# 
# ******************************************************************************
# *                                                                            *
# *                   Copyright (C) 2004-2010, Nangate Inc.                    *
# *                           All rights reserved.                             *
# *                                                                            *
# * Nangate and the Nangate logo are trademarks of Nangate Inc.                *
# *                                                                            *
# * All trademarks, logos, software marks, and trade names (collectively the   *
# * "Marks") in this program are proprietary to Nangate or other respective    *
# * owners that have granted Nangate the right and license to use such Marks.  *
# * You are not permitted to use the Marks without the prior written consent   *
# * of Nangate or such third party that may own the Marks.                     *
# *                                                                            *
# * This file has been provided pursuant to a License Agreement containing     *
# * restrictions on its use. This file contains valuable trade secrets and     *
# * proprietary information of Nangate Inc., and is protected by U.S. and      *
# * international laws and/or treaties.                                        *
# *                                                                            *
# * The copyright notice(s) in this file does not indicate actual or intended  *
# * publication of this file.                                                  *
# *                                                                            *
# *     NGLibraryCreator, v2010.08-HR32-SP3-2010-08-05 - build 1009061800      *
# *                                                                            *
# ******************************************************************************
# 
# 
# Running on brazil06.nangate.com.br for user Giancarlo Franciscatto (gfr).
# Local time is now Fri, 3 Dec 2010, 19:32:18.
# Main process id is 27821.

VERSION 5.6 ;
BUSBITCHARS "[]" ;
DIVIDERCHAR "/" ;

UNITS
  DATABASE MICRONS 2000 ;
END UNITS

MANUFACTURINGGRID 0.0050 ;

LAYER poly
  TYPE MASTERSLICE ;
END poly

LAYER active
  TYPE MASTERSLICE ;
END active

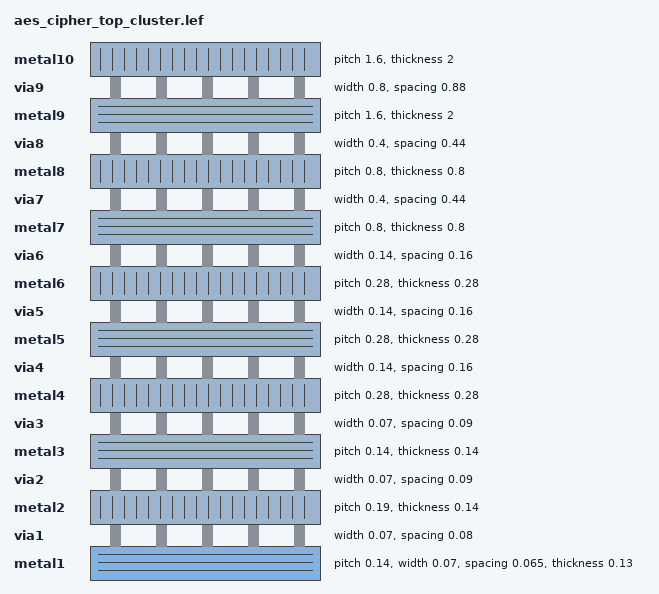
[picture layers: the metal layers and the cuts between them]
LAYER metal1
  TYPE ROUTING ;
  SPACING 0.065 ;
  WIDTH 0.07 ;
  PITCH 0.14 ;
  DIRECTION HORIZONTAL ;
  OFFSET 0.095 0.07 ;
  RESISTANCE RPERSQ 0.38 ;
  THICKNESS 0.13 ;
  HEIGHT 0.37 ;
  CAPACITANCE CPERSQDIST 7.7161e-05 ;
  EDGECAPACITANCE 2.7365e-05 ;
END metal1

LAYER via1
  TYPE CUT ;
  SPACING 0.08 ;
  WIDTH 0.07 ;
  RESISTANCE 5 ;
END via1

LAYER metal2
  TYPE ROUTING ;
  SPACINGTABLE 
    PARALLELRUNLENGTH    0.0000     0.3000     0.9000     1.8000     2.7000     4.0000     
      WIDTH 0.0000       0.0700     0.0700     0.0700     0.0700     0.0700     0.0700     
      WIDTH 0.0900       0.0700     0.0900     0.0900     0.0900     0.0900     0.0900     
      WIDTH 0.2700       0.0700     0.0900     0.2700     0.2700     0.2700     0.2700     
      WIDTH 0.5000       0.0700     0.0900     0.2700     0.5000     0.5000     0.5000     
      WIDTH 0.9000       0.0700     0.0900     0.2700     0.5000     0.9000     0.9000     
      WIDTH 1.5000       0.0700     0.0900     0.2700     0.5000     0.9000     1.5000      ;
  WIDTH 0.07 ;
  PITCH 0.19 ;
  DIRECTION VERTICAL ;
  OFFSET 0.095 0.07 ;
  RESISTANCE RPERSQ 0.25 ;
  THICKNESS 0.14 ;
  HEIGHT 0.62 ;
  CAPACITANCE CPERSQDIST 4.0896e-05 ;
  EDGECAPACITANCE 2.5157e-05 ;
END metal2

LAYER via2
  TYPE CUT ;
  SPACING 0.09 ;
  WIDTH 0.07 ;
  RESISTANCE 5 ;
END via2

LAYER metal3
  TYPE ROUTING ;
  SPACINGTABLE 
    PARALLELRUNLENGTH    0.0000     0.3000     0.9000     1.8000     2.7000     4.0000     
      WIDTH 0.0000       0.0700     0.0700     0.0700     0.0700     0.0700     0.0700     
      WIDTH 0.0900       0.0700     0.0900     0.0900     0.0900     0.0900     0.0900     
      WIDTH 0.2700       0.0700     0.0900     0.2700     0.2700     0.2700     0.2700     
      WIDTH 0.5000       0.0700     0.0900     0.2700     0.5000     0.5000     0.5000     
      WIDTH 0.9000       0.0700     0.0900     0.2700     0.5000     0.9000     0.9000     
      WIDTH 1.5000       0.0700     0.0900     0.2700     0.5000     0.9000     1.5000      ;
  WIDTH 0.07 ;
  PITCH 0.14 ;
  DIRECTION HORIZONTAL ;
  OFFSET 0.095 0.07 ;
  RESISTANCE RPERSQ 0.25 ;
  THICKNESS 0.14 ;
  HEIGHT 0.88 ;
  CAPACITANCE CPERSQDIST 2.7745e-05 ;
  EDGECAPACITANCE 2.5157e-05 ;
END metal3

LAYER via3
  TYPE CUT ;
  SPACING 0.09 ;
  WIDTH 0.07 ;
  RESISTANCE 5 ;
END via3

LAYER metal4
  TYPE ROUTING ;
  SPACINGTABLE 
    PARALLELRUNLENGTH    0.0000     0.9000     1.8000     2.7000     4.0000     
      WIDTH 0.0000       0.1400     0.1400     0.1400     0.1400     0.1400     
      WIDTH 0.2700       0.1400     0.2700     0.2700     0.2700     0.2700     
      WIDTH 0.5000       0.1400     0.2700     0.5000     0.5000     0.5000     
      WIDTH 0.9000       0.1400     0.2700     0.5000     0.9000     0.9000     
      WIDTH 1.5000       0.1400     0.2700     0.5000     0.9000     1.5000      ;
  WIDTH 0.14 ;
  PITCH 0.28 ;
  DIRECTION VERTICAL ;
  OFFSET 0.095 0.07 ;
  RESISTANCE RPERSQ 0.21 ;
  THICKNESS 0.28 ;
  HEIGHT 1.14 ;
  CAPACITANCE CPERSQDIST 2.0743e-05 ;
  EDGECAPACITANCE 3.0908e-05 ;
END metal4

LAYER via4
  TYPE CUT ;
  SPACING 0.16 ;
  WIDTH 0.14 ;
  RESISTANCE 3 ;
END via4

LAYER metal5
  TYPE ROUTING ;
  SPACINGTABLE 
    PARALLELRUNLENGTH    0.0000     0.9000     1.8000     2.7000     4.0000     
      WIDTH 0.0000       0.1400     0.1400     0.1400     0.1400     0.1400     
      WIDTH 0.2700       0.1400     0.2700     0.2700     0.2700     0.2700     
      WIDTH 0.5000       0.1400     0.2700     0.5000     0.5000     0.5000     
      WIDTH 0.9000       0.1400     0.2700     0.5000     0.9000     0.9000     
      WIDTH 1.5000       0.1400     0.2700     0.5000     0.9000     1.5000      ;
  WIDTH 0.14 ;
  PITCH 0.28 ;
  DIRECTION HORIZONTAL ;
  OFFSET 0.095 0.07 ;
  RESISTANCE RPERSQ 0.21 ;
  THICKNESS 0.28 ;
  HEIGHT 1.71 ;
  CAPACITANCE CPERSQDIST 1.3527e-05 ;
  EDGECAPACITANCE 2.3863e-06 ;
END metal5

LAYER via5
  TYPE CUT ;
  SPACING 0.16 ;
  WIDTH 0.14 ;
  RESISTANCE 3 ;
END via5

LAYER metal6
  TYPE ROUTING ;
  SPACINGTABLE 
    PARALLELRUNLENGTH    0.0000     0.9000     1.8000     2.7000     4.0000     
      WIDTH 0.0000       0.1400     0.1400     0.1400     0.1400     0.1400     
      WIDTH 0.2700       0.1400     0.2700     0.2700     0.2700     0.2700     
      WIDTH 0.5000       0.1400     0.2700     0.5000     0.5000     0.5000     
      WIDTH 0.9000       0.1400     0.2700     0.5000     0.9000     0.9000     
      WIDTH 1.5000       0.1400     0.2700     0.5000     0.9000     1.5000      ;
  WIDTH 0.14 ;
  PITCH 0.28 ;
  DIRECTION VERTICAL ;
  OFFSET 0.095 0.07 ;
  RESISTANCE RPERSQ 0.21 ;
  THICKNESS 0.28 ;
  HEIGHT 2.28 ;
  CAPACITANCE CPERSQDIST 1.0036e-05 ;
  EDGECAPACITANCE 2.3863e-05 ;
END metal6

LAYER via6
  TYPE CUT ;
  SPACING 0.16 ;
  WIDTH 0.14 ;
  RESISTANCE 3 ;
END via6

LAYER metal7
  TYPE ROUTING ;
  SPACINGTABLE 
    PARALLELRUNLENGTH    0.0000     1.8000     2.7000     4.0000     
      WIDTH 0.0000       0.4000     0.4000     0.4000     0.4000     
      WIDTH 0.5000       0.4000     0.5000     0.5000     0.5000     
      WIDTH 0.9000       0.4000     0.5000     0.9000     0.9000     
      WIDTH 1.5000       0.4000     0.5000     0.9000     1.5000      ;
  WIDTH 0.4 ;
  PITCH 0.8 ;
  DIRECTION HORIZONTAL ;
  OFFSET 0.095 0.07 ;
  RESISTANCE RPERSQ 0.075 ;
  THICKNESS 0.8 ;
  HEIGHT 2.85 ;
  CAPACITANCE CPERSQDIST 7.9771e-06 ;
  EDGECAPACITANCE 3.2577e-05 ;
END metal7

LAYER via7
  TYPE CUT ;
  SPACING 0.44 ;
  WIDTH 0.4 ;
  RESISTANCE 1 ;
END via7

LAYER metal8
  TYPE ROUTING ;
  SPACINGTABLE 
    PARALLELRUNLENGTH    0.0000     1.8000     2.7000     4.0000     
      WIDTH 0.0000       0.4000     0.4000     0.4000     0.4000     
      WIDTH 0.5000       0.4000     0.5000     0.5000     0.5000     
      WIDTH 0.9000       0.4000     0.5000     0.9000     0.9000     
      WIDTH 1.5000       0.4000     0.5000     0.9000     1.5000      ;
  WIDTH 0.4 ;
  PITCH 0.8 ;
  DIRECTION VERTICAL ;
  OFFSET 0.095 0.07 ;
  RESISTANCE RPERSQ 0.075 ;
  THICKNESS 0.8 ;
  HEIGHT 4.47 ;
  CAPACITANCE CPERSQDIST 5.0391e-06 ;
  EDGECAPACITANCE 2.3932e-05 ;
END metal8

LAYER via8
  TYPE CUT ;
  SPACING 0.44 ;
  WIDTH 0.4 ;
  RESISTANCE 1 ;
END via8

LAYER metal9
  TYPE ROUTING ;
  SPACINGTABLE 
    PARALLELRUNLENGTH    0.0000     2.7000     4.0000     
      WIDTH 0.0000       0.8000     0.8000     0.8000     
      WIDTH 0.9000       0.8000     0.9000     0.9000     
      WIDTH 1.5000       0.8000     0.9000     1.5000      ;
  WIDTH 0.8 ;
  PITCH 1.6 ;
  DIRECTION HORIZONTAL ;
  OFFSET 0.095 0.07 ;
  RESISTANCE RPERSQ 0.03 ;
  THICKNESS 2 ;
  HEIGHT 6.09 ;
  CAPACITANCE CPERSQDIST 3.6827e-06 ;
  EDGECAPACITANCE 3.0803e-05 ;
END metal9

LAYER via9
  TYPE CUT ;
  SPACING 0.88 ;
  WIDTH 0.8 ;
  RESISTANCE 0.5 ;
END via9

LAYER metal10
  TYPE ROUTING ;
  SPACINGTABLE 
    PARALLELRUNLENGTH    0.0000     2.7000     4.0000     
      WIDTH 0.0000       0.8000     0.8000     0.8000     
      WIDTH 0.9000       0.8000     0.9000     0.9000     
      WIDTH 1.5000       0.8000     0.9000     1.5000      ;
  WIDTH 0.8 ;
  PITCH 1.6 ;
  DIRECTION VERTICAL ;
  OFFSET 0.095 0.07 ;
  RESISTANCE RPERSQ 0.03 ;
  THICKNESS 2 ;
  HEIGHT 10.09 ;
  CAPACITANCE CPERSQDIST 2.2124e-06 ;
  EDGECAPACITANCE 2.3667e-05 ;
END metal10

LAYER OVERLAP
  TYPE OVERLAP ;
END OVERLAP

VIA via1_4 DEFAULT
  LAYER via1 ;
    RECT -0.035 -0.035 0.035 0.035 ;
  LAYER metal1 ;
    RECT -0.035 -0.07 0.035 0.07 ;
  LAYER metal2 ;
    RECT -0.035 -0.07 0.035 0.07 ;
END via1_4

VIA via1_0 DEFAULT
  LAYER via1 ;
    RECT -0.035 -0.035 0.035 0.035 ;
  LAYER metal1 ;
    RECT -0.07 -0.07 0.07 0.07 ;
  LAYER metal2 ;
    RECT -0.07 -0.07 0.07 0.07 ;
END via1_0

VIA via1_1 DEFAULT
  LAYER via1 ;
    RECT -0.035 -0.035 0.035 0.035 ;
  LAYER metal1 ;
    RECT -0.07 -0.07 0.07 0.07 ;
  LAYER metal2 ;
    RECT -0.035 -0.07 0.035 0.07 ;
END via1_1

VIA via1_2 DEFAULT
  LAYER via1 ;
    RECT -0.035 -0.035 0.035 0.035 ;
  LAYER metal1 ;
    RECT -0.07 -0.07 0.07 0.07 ;
  LAYER metal2 ;
    RECT -0.07 -0.035 0.07 0.035 ;
END via1_2

VIA via1_3 DEFAULT
  LAYER via1 ;
    RECT -0.035 -0.035 0.035 0.035 ;
  LAYER metal1 ;
    RECT -0.035 -0.07 0.035 0.07 ;
  LAYER metal2 ;
    RECT -0.07 -0.07 0.07 0.07 ;
END via1_3

VIA via1_5 DEFAULT
  LAYER via1 ;
    RECT -0.035 -0.035 0.035 0.035 ;
  LAYER metal1 ;
    RECT -0.035 -0.07 0.035 0.07 ;
  LAYER metal2 ;
    RECT -0.07 -0.035 0.07 0.035 ;
END via1_5

VIA via1_6 DEFAULT
  LAYER via1 ;
    RECT -0.035 -0.035 0.035 0.035 ;
  LAYER metal1 ;
    RECT -0.07 -0.035 0.07 0.035 ;
  LAYER metal2 ;
    RECT -0.07 -0.07 0.07 0.07 ;
END via1_6

VIA via1_7 DEFAULT
  LAYER via1 ;
    RECT -0.035 -0.035 0.035 0.035 ;
  LAYER metal1 ;
    RECT -0.07 -0.035 0.07 0.035 ;
  LAYER metal2 ;
    RECT -0.035 -0.07 0.035 0.07 ;
END via1_7

VIA via1_8 DEFAULT
  LAYER via1 ;
    RECT -0.035 -0.035 0.035 0.035 ;
  LAYER metal1 ;
    RECT -0.07 -0.035 0.07 0.035 ;
  LAYER metal2 ;
    RECT -0.07 -0.035 0.07 0.035 ;
END via1_8

VIA via2_8 DEFAULT
  LAYER via2 ;
    RECT -0.035 -0.035 0.035 0.035 ;
  LAYER metal2 ;
    RECT -0.07 -0.035 0.07 0.035 ;
  LAYER metal3 ;
    RECT -0.07 -0.035 0.07 0.035 ;
END via2_8

VIA via2_4 DEFAULT
  LAYER via2 ;
    RECT -0.035 -0.035 0.035 0.035 ;
  LAYER metal2 ;
    RECT -0.035 -0.07 0.035 0.07 ;
  LAYER metal3 ;
    RECT -0.035 -0.07 0.035 0.07 ;
END via2_4

VIA via2_5 DEFAULT
  LAYER via2 ;
    RECT -0.035 -0.035 0.035 0.035 ;
  LAYER metal2 ;
    RECT -0.035 -0.07 0.035 0.07 ;
  LAYER metal3 ;
    RECT -0.07 -0.035 0.07 0.035 ;
END via2_5

VIA via2_7 DEFAULT
  LAYER via2 ;
    RECT -0.035 -0.035 0.035 0.035 ;
  LAYER metal2 ;
    RECT -0.07 -0.035 0.07 0.035 ;
  LAYER metal3 ;
    RECT -0.035 -0.07 0.035 0.07 ;
END via2_7

VIA via2_6 DEFAULT
  LAYER via2 ;
    RECT -0.035 -0.035 0.035 0.035 ;
  LAYER metal2 ;
    RECT -0.07 -0.035 0.07 0.035 ;
  LAYER metal3 ;
    RECT -0.07 -0.07 0.07 0.07 ;
END via2_6

VIA via2_0 DEFAULT
  LAYER via2 ;
    RECT -0.035 -0.035 0.035 0.035 ;
  LAYER metal2 ;
    RECT -0.07 -0.07 0.07 0.07 ;
  LAYER metal3 ;
    RECT -0.07 -0.07 0.07 0.07 ;
END via2_0

VIA via2_1 DEFAULT
  LAYER via2 ;
    RECT -0.035 -0.035 0.035 0.035 ;
  LAYER metal2 ;
    RECT -0.07 -0.07 0.07 0.07 ;
  LAYER metal3 ;
    RECT -0.035 -0.07 0.035 0.07 ;
END via2_1

VIA via2_2 DEFAULT
  LAYER via2 ;
    RECT -0.035 -0.035 0.035 0.035 ;
  LAYER metal2 ;
    RECT -0.07 -0.07 0.07 0.07 ;
  LAYER metal3 ;
    RECT -0.07 -0.035 0.07 0.035 ;
END via2_2

VIA via2_3 DEFAULT
  LAYER via2 ;
    RECT -0.035 -0.035 0.035 0.035 ;
  LAYER metal2 ;
    RECT -0.035 -0.07 0.035 0.07 ;
  LAYER metal3 ;
    RECT -0.07 -0.07 0.07 0.07 ;
END via2_3

VIA via3_2 DEFAULT
  LAYER via3 ;
    RECT -0.035 -0.035 0.035 0.035 ;
  LAYER metal3 ;
    RECT -0.07 -0.035 0.07 0.035 ;
  LAYER metal4 ;
    RECT -0.07 -0.07 0.07 0.07 ;
END via3_2

VIA via3_0 DEFAULT
  LAYER via3 ;
    RECT -0.035 -0.035 0.035 0.035 ;
  LAYER metal3 ;
    RECT -0.07 -0.07 0.07 0.07 ;
  LAYER metal4 ;
    RECT -0.07 -0.07 0.07 0.07 ;
END via3_0

VIA via3_1 DEFAULT
  LAYER via3 ;
    RECT -0.035 -0.035 0.035 0.035 ;
  LAYER metal3 ;
    RECT -0.035 -0.07 0.035 0.07 ;
  LAYER metal4 ;
    RECT -0.07 -0.07 0.07 0.07 ;
END via3_1

VIA via4_0 DEFAULT
  LAYER via4 ;
    RECT -0.07 -0.07 0.07 0.07 ;
  LAYER metal4 ;
    RECT -0.07 -0.07 0.07 0.07 ;
  LAYER metal5 ;
    RECT -0.07 -0.07 0.07 0.07 ;
END via4_0

VIA via5_0 DEFAULT
  LAYER via5 ;
    RECT -0.07 -0.07 0.07 0.07 ;
  LAYER metal5 ;
    RECT -0.07 -0.07 0.07 0.07 ;
  LAYER metal6 ;
    RECT -0.07 -0.07 0.07 0.07 ;
END via5_0

VIA via6_0 DEFAULT
  LAYER via6 ;
    RECT -0.07 -0.07 0.07 0.07 ;
  LAYER metal6 ;
    RECT -0.07 -0.07 0.07 0.07 ;
  LAYER metal7 ;
    RECT -0.2 -0.2 0.2 0.2 ;
END via6_0

VIA via7_0 DEFAULT
  LAYER via7 ;
    RECT -0.2 -0.2 0.2 0.2 ;
  LAYER metal7 ;
    RECT -0.2 -0.2 0.2 0.2 ;
  LAYER metal8 ;
    RECT -0.2 -0.2 0.2 0.2 ;
END via7_0

VIA via8_0 DEFAULT
  LAYER via8 ;
    RECT -0.2 -0.2 0.2 0.2 ;
  LAYER metal8 ;
    RECT -0.2 -0.2 0.2 0.2 ;
  LAYER metal9 ;
    RECT -0.4 -0.4 0.4 0.4 ;
END via8_0

VIA via9_0 DEFAULT
  LAYER via9 ;
    RECT -0.4 -0.4 0.4 0.4 ;
  LAYER metal9 ;
    RECT -0.4 -0.4 0.4 0.4 ;
  LAYER metal10 ;
    RECT -0.4 -0.4 0.4 0.4 ;
END via9_0

VIARULE Via1Array-0 GENERATE
  LAYER metal1 ;
    ENCLOSURE 0.035 0.035 ;
  LAYER metal2 ;
    ENCLOSURE 0.035 0.035 ;
  LAYER via1 ;
    RECT -0.035 -0.035 0.035 0.035 ;
    SPACING 0.15 BY 0.15 ;
END Via1Array-0

VIARULE Via1Array-1 GENERATE
  LAYER metal1 ;
    ENCLOSURE 0 0.035 ;
  LAYER metal2 ;
    ENCLOSURE 0 0.035 ;
  LAYER via1 ;
    RECT -0.035 -0.035 0.035 0.035 ;
    SPACING 0.15 BY 0.15 ;
END Via1Array-1

VIARULE Via1Array-2 GENERATE
  LAYER metal1 ;
    ENCLOSURE 0.035 0 ;
  LAYER metal2 ;
    ENCLOSURE 0.035 0 ;
  LAYER via1 ;
    RECT -0.035 -0.035 0.035 0.035 ;
    SPACING 0.15 BY 0.15 ;
END Via1Array-2

VIARULE Via1Array-3 GENERATE
  LAYER metal1 ;
    ENCLOSURE 0 0.035 ;
  LAYER metal2 ;
    ENCLOSURE 0.035 0 ;
  LAYER via1 ;
    RECT -0.035 -0.035 0.035 0.035 ;
    SPACING 0.15 BY 0.15 ;
END Via1Array-3

VIARULE Via1Array-4 GENERATE
  LAYER metal1 ;
    ENCLOSURE 0.035 0 ;
  LAYER metal2 ;
    ENCLOSURE 0 0.035 ;
  LAYER via1 ;
    RECT -0.035 -0.035 0.035 0.035 ;
    SPACING 0.15 BY 0.15 ;
END Via1Array-4

VIARULE Via2Array-0 GENERATE
  LAYER metal2 ;
    ENCLOSURE 0.035 0.035 ;
  LAYER metal3 ;
    ENCLOSURE 0.035 0.035 ;
  LAYER via2 ;
    RECT -0.035 -0.035 0.035 0.035 ;
    SPACING 0.16 BY 0.16 ;
END Via2Array-0

VIARULE Via2Array-1 GENERATE
  LAYER metal2 ;
    ENCLOSURE 0 0.035 ;
  LAYER metal3 ;
    ENCLOSURE 0 0.035 ;
  LAYER via2 ;
    RECT -0.035 -0.035 0.035 0.035 ;
    SPACING 0.16 BY 0.16 ;
END Via2Array-1

VIARULE Via2Array-2 GENERATE
  LAYER metal2 ;
    ENCLOSURE 0.035 0 ;
  LAYER metal3 ;
    ENCLOSURE 0.035 0 ;
  LAYER via2 ;
    RECT -0.035 -0.035 0.035 0.035 ;
    SPACING 0.16 BY 0.16 ;
END Via2Array-2

VIARULE Via2Array-3 GENERATE
  LAYER metal2 ;
    ENCLOSURE 0 0.035 ;
  LAYER metal3 ;
    ENCLOSURE 0.035 0 ;
  LAYER via2 ;
    RECT -0.035 -0.035 0.035 0.035 ;
    SPACING 0.16 BY 0.16 ;
END Via2Array-3

VIARULE Via2Array-4 GENERATE
  LAYER metal2 ;
    ENCLOSURE 0.035 0 ;
  LAYER metal3 ;
    ENCLOSURE 0 0.035 ;
  LAYER via2 ;
    RECT -0.035 -0.035 0.035 0.035 ;
    SPACING 0.16 BY 0.16 ;
END Via2Array-4

VIARULE Via3Array-0 GENERATE
  LAYER metal3 ;
    ENCLOSURE 0.035 0.035 ;
  LAYER metal4 ;
    ENCLOSURE 0.035 0.035 ;
  LAYER via3 ;
    RECT -0.035 -0.035 0.035 0.035 ;
    SPACING 0.16 BY 0.16 ;
END Via3Array-0

VIARULE Via3Array-1 GENERATE
  LAYER metal3 ;
    ENCLOSURE 0 0.035 ;
  LAYER metal4 ;
    ENCLOSURE 0.035 0.035 ;
  LAYER via3 ;
    RECT -0.035 -0.035 0.035 0.035 ;
    SPACING 0.16 BY 0.16 ;
END Via3Array-1

VIARULE Via3Array-2 GENERATE
  LAYER metal3 ;
    ENCLOSURE 0.035 0 ;
  LAYER metal4 ;
    ENCLOSURE 0.035 0.035 ;
  LAYER via3 ;
    RECT -0.035 -0.035 0.035 0.035 ;
    SPACING 0.16 BY 0.16 ;
END Via3Array-2

VIARULE Via4Array-0 GENERATE
  LAYER metal4 ;
    ENCLOSURE 0 0 ;
  LAYER metal5 ;
    ENCLOSURE 0 0 ;
  LAYER via4 ;
    RECT -0.07 -0.07 0.07 0.07 ;
    SPACING 0.3 BY 0.3 ;
END Via4Array-0

VIARULE Via5Array-0 GENERATE
  LAYER metal5 ;
    ENCLOSURE 0 0 ;
  LAYER metal6 ;
    ENCLOSURE 0 0 ;
  LAYER via5 ;
    RECT -0.07 -0.07 0.07 0.07 ;
    SPACING 0.3 BY 0.3 ;
END Via5Array-0

VIARULE Via6Array-0 GENERATE
  LAYER metal6 ;
    ENCLOSURE 0 0 ;
  LAYER metal7 ;
    ENCLOSURE 0.13 0.13 ;
  LAYER via6 ;
    RECT -0.07 -0.07 0.07 0.07 ;
    SPACING 0.3 BY 0.3 ;
END Via6Array-0

VIARULE Via7Array-0 GENERATE
  LAYER metal7 ;
    ENCLOSURE 0 0 ;
  LAYER metal8 ;
    ENCLOSURE 0 0 ;
  LAYER via7 ;
    RECT -0.2 -0.2 0.2 0.2 ;
    SPACING 0.84 BY 0.84 ;
END Via7Array-0

VIARULE Via8Array-0 GENERATE
  LAYER metal8 ;
    ENCLOSURE 0 0 ;
  LAYER metal9 ;
    ENCLOSURE 0.2 0.2 ;
  LAYER via8 ;
    RECT -0.2 -0.2 0.2 0.2 ;
    SPACING 0.84 BY 0.84 ;
END Via8Array-0

VIARULE Via9Array-0 GENERATE
  LAYER metal10 ;
    ENCLOSURE 0 0 ;
  LAYER metal9 ;
    ENCLOSURE 0 0 ;
  LAYER via9 ;
    RECT -0.4 -0.4 0.4 0.4 ;
    SPACING 1.68 BY 1.68 ;
END Via9Array-0

SPACING
  SAMENET metal1 metal1 0.065 ;
  SAMENET metal2 metal2 0.07 ;
  SAMENET metal3 metal3 0.07 ;
  SAMENET metal4 metal4 0.14 ;
  SAMENET metal5 metal5 0.14 ;
  SAMENET metal6 metal6 0.14 ;
  SAMENET metal7 metal7 0.4 ;
  SAMENET metal8 metal8 0.4 ;
  SAMENET metal9 metal9 0.8 ;
  SAMENET metal10 metal10 0.8 ;
  SAMENET via1 via1 0.08 ;
  SAMENET via2 via2 0.09 ;
  SAMENET via3 via3 0.09 ;
  SAMENET via4 via4 0.16 ;
  SAMENET via5 via5 0.16 ;
  SAMENET via6 via6 0.16 ;
  SAMENET via7 via7 0.44 ;
  SAMENET via8 via8 0.44 ;
  SAMENET via9 via9 0.88 ;
  SAMENET via1 via2 0.0 STACK ;
  SAMENET via2 via3 0.0 STACK ;
  SAMENET via3 via4 0.0 STACK ;
  SAMENET via4 via5 0.0 STACK ;
  SAMENET via5 via6 0.0 STACK ;
  SAMENET via6 via7 0.0 STACK ;
  SAMENET via7 via8 0.0 STACK ;
  SAMENET via8 via9 0.0 STACK ;
END SPACING

SITE FreePDK45_38x28_10R_NP_162NW_34O
  SYMMETRY y ;
  CLASS core ;
  SIZE 0.19 BY 1.4 ;
END FreePDK45_38x28_10R_NP_162NW_34O

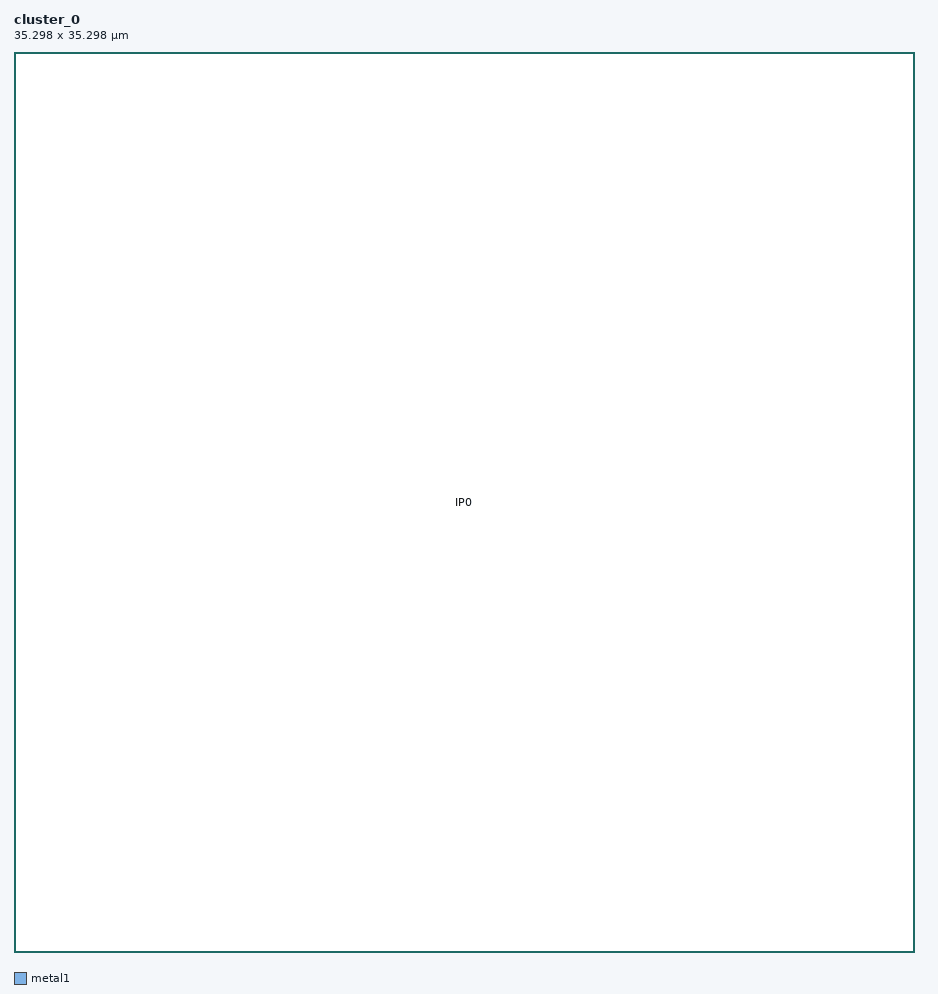
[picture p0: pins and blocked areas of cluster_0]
MACRO cluster_0
	CLASS BLOCK ;
	ORIGIN 0 0 ;
	FOREIGN cluster_0 0 0 ;
	SIZE 35.298 BY 35.298 ;
	SYMMETRY X Y ;
	PIN OP0
		DIRECTION OUTPUT ;
		USE SIGNAL ;
		PORT
			LAYER metal1 ;
			RECT 17.649 17.649 17.649 17.649 ;
			END
		END OP0
	PIN OP1
		DIRECTION OUTPUT ;
		USE SIGNAL ;
		PORT
			LAYER metal1 ;
			RECT 17.649 17.649 17.649 17.649 ;
			END
		END OP1
	PIN OP2
		DIRECTION OUTPUT ;
		USE SIGNAL ;
		PORT
			LAYER metal1 ;
			RECT 17.649 17.649 17.649 17.649 ;
			END
		END OP2
	PIN OP3
		DIRECTION OUTPUT ;
		USE SIGNAL ;
		PORT
			LAYER metal1 ;
			RECT 17.649 17.649 17.649 17.649 ;
			END
		END OP3
	PIN OP4
		DIRECTION OUTPUT ;
		USE SIGNAL ;
		PORT
			LAYER metal1 ;
			RECT 17.649 17.649 17.649 17.649 ;
			END
		END OP4
	PIN OP5
		DIRECTION OUTPUT ;
		USE SIGNAL ;
		PORT
			LAYER metal1 ;
			RECT 17.649 17.649 17.649 17.649 ;
			END
		END OP5
	PIN OP6
		DIRECTION OUTPUT ;
		USE SIGNAL ;
		PORT
			LAYER metal1 ;
			RECT 17.649 17.649 17.649 17.649 ;
			END
		END OP6
	PIN OP7
		DIRECTION OUTPUT ;
		USE SIGNAL ;
		PORT
			LAYER metal1 ;
			RECT 17.649 17.649 17.649 17.649 ;
			END
		END OP7
	PIN OP8
		DIRECTION OUTPUT ;
		USE SIGNAL ;
		PORT
			LAYER metal1 ;
			RECT 17.649 17.649 17.649 17.649 ;
			END
		END OP8
	PIN OP9
		DIRECTION OUTPUT ;
		USE SIGNAL ;
		PORT
			LAYER metal1 ;
			RECT 17.649 17.649 17.649 17.649 ;
			END
		END OP9
	PIN OP10
		DIRECTION OUTPUT ;
		USE SIGNAL ;
		PORT
			LAYER metal1 ;
			RECT 17.649 17.649 17.649 17.649 ;
			END
		END OP10
	PIN OP11
		DIRECTION OUTPUT ;
		USE SIGNAL ;
		PORT
			LAYER metal1 ;
			RECT 17.649 17.649 17.649 17.649 ;
			END
		END OP11
	PIN OP12
		DIRECTION OUTPUT ;
		USE SIGNAL ;
		PORT
			LAYER metal1 ;
			RECT 17.649 17.649 17.649 17.649 ;
			END
		END OP12
	PIN OP13
		DIRECTION OUTPUT ;
		USE SIGNAL ;
		PORT
			LAYER metal1 ;
			RECT 17.649 17.649 17.649 17.649 ;
			END
		END OP13
	PIN OP14
		DIRECTION OUTPUT ;
		USE SIGNAL ;
		PORT
			LAYER metal1 ;
			RECT 17.649 17.649 17.649 17.649 ;
			END
		END OP14
	PIN OP15
		DIRECTION OUTPUT ;
		USE SIGNAL ;
		PORT
			LAYER metal1 ;
			RECT 17.649 17.649 17.649 17.649 ;
			END
		END OP15
	PIN OP16
		DIRECTION OUTPUT ;
		USE SIGNAL ;
		PORT
			LAYER metal1 ;
			RECT 17.649 17.649 17.649 17.649 ;
			END
		END OP16
	PIN OP17
		DIRECTION OUTPUT ;
		USE SIGNAL ;
		PORT
			LAYER metal1 ;
			RECT 17.649 17.649 17.649 17.649 ;
			END
		END OP17
	PIN OP18
		DIRECTION OUTPUT ;
		USE SIGNAL ;
		PORT
			LAYER metal1 ;
			RECT 17.649 17.649 17.649 17.649 ;
			END
		END OP18
	PIN OP19
		DIRECTION OUTPUT ;
		USE SIGNAL ;
		PORT
			LAYER metal1 ;
			RECT 17.649 17.649 17.649 17.649 ;
			END
		END OP19
	PIN OP20
		DIRECTION OUTPUT ;
		USE SIGNAL ;
		PORT
			LAYER metal1 ;
			RECT 17.649 17.649 17.649 17.649 ;
			END
		END OP20
	PIN OP21
		DIRECTION OUTPUT ;
		USE SIGNAL ;
		PORT
			LAYER metal1 ;
			RECT 17.649 17.649 17.649 17.649 ;
			END
		END OP21
	PIN OP22
		DIRECTION OUTPUT ;
		USE SIGNAL ;
		PORT
			LAYER metal1 ;
			RECT 17.649 17.649 17.649 17.649 ;
			END
		END OP22
	PIN OP23
		DIRECTION OUTPUT ;
		USE SIGNAL ;
		PORT
			LAYER metal1 ;
			RECT 17.649 17.649 17.649 17.649 ;
			END
		END OP23
	PIN OP24
		DIRECTION OUTPUT ;
		USE SIGNAL ;
		PORT
			LAYER metal1 ;
			RECT 17.649 17.649 17.649 17.649 ;
			END
		END OP24
	PIN OP25
		DIRECTION OUTPUT ;
		USE SIGNAL ;
		PORT
			LAYER metal1 ;
			RECT 17.649 17.649 17.649 17.649 ;
			END
		END OP25
	PIN OP26
		DIRECTION OUTPUT ;
		USE SIGNAL ;
		PORT
			LAYER metal1 ;
			RECT 17.649 17.649 17.649 17.649 ;
			END
		END OP26
	PIN OP27
		DIRECTION OUTPUT ;
		USE SIGNAL ;
		PORT
			LAYER metal1 ;
			RECT 17.649 17.649 17.649 17.649 ;
			END
		END OP27
	PIN OP28
		DIRECTION OUTPUT ;
		USE SIGNAL ;
		PORT
			LAYER metal1 ;
			RECT 17.649 17.649 17.649 17.649 ;
			END
		END OP28
	PIN OP29
		DIRECTION OUTPUT ;
		USE SIGNAL ;
		PORT
			LAYER metal1 ;
			RECT 17.649 17.649 17.649 17.649 ;
			END
		END OP29
	PIN OP30
		DIRECTION OUTPUT ;
		USE SIGNAL ;
		PORT
			LAYER metal1 ;
			RECT 17.649 17.649 17.649 17.649 ;
			END
		END OP30
	PIN OP31
		DIRECTION OUTPUT ;
		USE SIGNAL ;
		PORT
			LAYER metal1 ;
			RECT 17.649 17.649 17.649 17.649 ;
			END
		END OP31
	PIN OP32
		DIRECTION OUTPUT ;
		USE SIGNAL ;
		PORT
			LAYER metal1 ;
			RECT 17.649 17.649 17.649 17.649 ;
			END
		END OP32
	PIN OP33
		DIRECTION OUTPUT ;
		USE SIGNAL ;
		PORT
			LAYER metal1 ;
			RECT 17.649 17.649 17.649 17.649 ;
			END
		END OP33
	PIN OP34
		DIRECTION OUTPUT ;
		USE SIGNAL ;
		PORT
			LAYER metal1 ;
			RECT 17.649 17.649 17.649 17.649 ;
			END
		END OP34
	PIN OP35
		DIRECTION OUTPUT ;
		USE SIGNAL ;
		PORT
			LAYER metal1 ;
			RECT 17.649 17.649 17.649 17.649 ;
			END
		END OP35
	PIN OP36
		DIRECTION OUTPUT ;
		USE SIGNAL ;
		PORT
			LAYER metal1 ;
			RECT 17.649 17.649 17.649 17.649 ;
			END
		END OP36
	PIN OP37
		DIRECTION OUTPUT ;
		USE SIGNAL ;
		PORT
			LAYER metal1 ;
			RECT 17.649 17.649 17.649 17.649 ;
			END
		END OP37
	PIN OP38
		DIRECTION OUTPUT ;
		USE SIGNAL ;
		PORT
			LAYER metal1 ;
			RECT 17.649 17.649 17.649 17.649 ;
			END
		END OP38
	PIN OP39
		DIRECTION OUTPUT ;
		USE SIGNAL ;
		PORT
			LAYER metal1 ;
			RECT 17.649 17.649 17.649 17.649 ;
			END
		END OP39
	PIN OP40
		DIRECTION OUTPUT ;
		USE SIGNAL ;
		PORT
			LAYER metal1 ;
			RECT 17.649 17.649 17.649 17.649 ;
			END
		END OP40
	PIN OP41
		DIRECTION OUTPUT ;
		USE SIGNAL ;
		PORT
			LAYER metal1 ;
			RECT 17.649 17.649 17.649 17.649 ;
			END
		END OP41
	PIN OP42
		DIRECTION OUTPUT ;
		USE SIGNAL ;
		PORT
			LAYER metal1 ;
			RECT 17.649 17.649 17.649 17.649 ;
			END
		END OP42
	PIN OP43
		DIRECTION OUTPUT ;
		USE SIGNAL ;
		PORT
			LAYER metal1 ;
			RECT 17.649 17.649 17.649 17.649 ;
			END
		END OP43
	PIN OP44
		DIRECTION OUTPUT ;
		USE SIGNAL ;
		PORT
			LAYER metal1 ;
			RECT 17.649 17.649 17.649 17.649 ;
			END
		END OP44
	PIN OP45
		DIRECTION OUTPUT ;
		USE SIGNAL ;
		PORT
			LAYER metal1 ;
			RECT 17.649 17.649 17.649 17.649 ;
			END
		END OP45
	PIN OP46
		DIRECTION OUTPUT ;
		USE SIGNAL ;
		PORT
			LAYER metal1 ;
			RECT 17.649 17.649 17.649 17.649 ;
			END
		END OP46
	PIN OP47
		DIRECTION OUTPUT ;
		USE SIGNAL ;
		PORT
			LAYER metal1 ;
			RECT 17.649 17.649 17.649 17.649 ;
			END
		END OP47
	PIN OP48
		DIRECTION OUTPUT ;
		USE SIGNAL ;
		PORT
			LAYER metal1 ;
			RECT 17.649 17.649 17.649 17.649 ;
			END
		END OP48
	PIN OP49
		DIRECTION OUTPUT ;
		USE SIGNAL ;
		PORT
			LAYER metal1 ;
			RECT 17.649 17.649 17.649 17.649 ;
			END
		END OP49
	PIN OP50
		DIRECTION OUTPUT ;
		USE SIGNAL ;
		PORT
			LAYER metal1 ;
			RECT 17.649 17.649 17.649 17.649 ;
			END
		END OP50
	PIN OP51
		DIRECTION OUTPUT ;
		USE SIGNAL ;
		PORT
			LAYER metal1 ;
			RECT 17.649 17.649 17.649 17.649 ;
			END
		END OP51
	PIN OP52
		DIRECTION OUTPUT ;
		USE SIGNAL ;
		PORT
			LAYER metal1 ;
			RECT 17.649 17.649 17.649 17.649 ;
			END
		END OP52
	PIN OP53
		DIRECTION OUTPUT ;
		USE SIGNAL ;
		PORT
			LAYER metal1 ;
			RECT 17.649 17.649 17.649 17.649 ;
			END
		END OP53
	PIN OP54
		DIRECTION OUTPUT ;
		USE SIGNAL ;
		PORT
			LAYER metal1 ;
			RECT 17.649 17.649 17.649 17.649 ;
			END
		END OP54
	PIN OP55
		DIRECTION OUTPUT ;
		USE SIGNAL ;
		PORT
			LAYER metal1 ;
			RECT 17.649 17.649 17.649 17.649 ;
			END
		END OP55
	PIN OP56
		DIRECTION OUTPUT ;
		USE SIGNAL ;
		PORT
			LAYER metal1 ;
			RECT 17.649 17.649 17.649 17.649 ;
			END
		END OP56
	PIN OP57
		DIRECTION OUTPUT ;
		USE SIGNAL ;
		PORT
			LAYER metal1 ;
			RECT 17.649 17.649 17.649 17.649 ;
			END
		END OP57
	PIN OP58
		DIRECTION OUTPUT ;
		USE SIGNAL ;
		PORT
			LAYER metal1 ;
			RECT 17.649 17.649 17.649 17.649 ;
			END
		END OP58
	PIN OP59
		DIRECTION OUTPUT ;
		USE SIGNAL ;
		PORT
			LAYER metal1 ;
			RECT 17.649 17.649 17.649 17.649 ;
			END
		END OP59
	PIN IP0
		DIRECTION INPUT ;
		USE SIGNAL ;
		PORT
			LAYER metal1 ;
			RECT 17.649 17.649 17.649 17.649 ;
			END
		END IP0
	PIN IP1
		DIRECTION INPUT ;
		USE SIGNAL ;
		PORT
			LAYER metal1 ;
			RECT 17.649 17.649 17.649 17.649 ;
			END
		END IP1
	PIN IP2
		DIRECTION INPUT ;
		USE SIGNAL ;
		PORT
			LAYER metal1 ;
			RECT 17.649 17.649 17.649 17.649 ;
			END
		END IP2
	PIN IP3
		DIRECTION INPUT ;
		USE SIGNAL ;
		PORT
			LAYER metal1 ;
			RECT 17.649 17.649 17.649 17.649 ;
			END
		END IP3
	PIN IP4
		DIRECTION INPUT ;
		USE SIGNAL ;
		PORT
			LAYER metal1 ;
			RECT 17.649 17.649 17.649 17.649 ;
			END
		END IP4
	PIN IP5
		DIRECTION INPUT ;
		USE SIGNAL ;
		PORT
			LAYER metal1 ;
			RECT 17.649 17.649 17.649 17.649 ;
			END
		END IP5
	PIN IP6
		DIRECTION INPUT ;
		USE SIGNAL ;
		PORT
			LAYER metal1 ;
			RECT 17.649 17.649 17.649 17.649 ;
			END
		END IP6
	PIN IP7
		DIRECTION INPUT ;
		USE SIGNAL ;
		PORT
			LAYER metal1 ;
			RECT 17.649 17.649 17.649 17.649 ;
			END
		END IP7
	PIN IP8
		DIRECTION INPUT ;
		USE SIGNAL ;
		PORT
			LAYER metal1 ;
			RECT 17.649 17.649 17.649 17.649 ;
			END
		END IP8
	PIN IP9
		DIRECTION INPUT ;
		USE SIGNAL ;
		PORT
			LAYER metal1 ;
			RECT 17.649 17.649 17.649 17.649 ;
			END
		END IP9
	PIN IP10
		DIRECTION INPUT ;
		USE SIGNAL ;
		PORT
			LAYER metal1 ;
			RECT 17.649 17.649 17.649 17.649 ;
			END
		END IP10
	PIN IP11
		DIRECTION INPUT ;
		USE SIGNAL ;
		PORT
			LAYER metal1 ;
			RECT 17.649 17.649 17.649 17.649 ;
			END
		END IP11
	PIN IP12
		DIRECTION INPUT ;
		USE SIGNAL ;
		PORT
			LAYER metal1 ;
			RECT 17.649 17.649 17.649 17.649 ;
			END
		END IP12
	PIN IP13
		DIRECTION INPUT ;
		USE SIGNAL ;
		PORT
			LAYER metal1 ;
			RECT 17.649 17.649 17.649 17.649 ;
			END
		END IP13
	PIN IP14
		DIRECTION INPUT ;
		USE SIGNAL ;
		PORT
			LAYER metal1 ;
			RECT 17.649 17.649 17.649 17.649 ;
			END
		END IP14
	PIN IP15
		DIRECTION INPUT ;
		USE SIGNAL ;
		PORT
			LAYER metal1 ;
			RECT 17.649 17.649 17.649 17.649 ;
			END
		END IP15
	PIN IP16
		DIRECTION INPUT ;
		USE SIGNAL ;
		PORT
			LAYER metal1 ;
			RECT 17.649 17.649 17.649 17.649 ;
			END
		END IP16
	PIN IP17
		DIRECTION INPUT ;
		USE SIGNAL ;
		PORT
			LAYER metal1 ;
			RECT 17.649 17.649 17.649 17.649 ;
			END
		END IP17
	PIN IP18
		DIRECTION INPUT ;
		USE SIGNAL ;
		PORT
			LAYER metal1 ;
			RECT 17.649 17.649 17.649 17.649 ;
			END
		END IP18
	PIN IP19
		DIRECTION INPUT ;
		USE SIGNAL ;
		PORT
			LAYER metal1 ;
			RECT 17.649 17.649 17.649 17.649 ;
			END
		END IP19
	PIN IP20
		DIRECTION INPUT ;
		USE SIGNAL ;
		PORT
			LAYER metal1 ;
			RECT 17.649 17.649 17.649 17.649 ;
			END
		END IP20
	PIN IP21
		DIRECTION INPUT ;
		USE SIGNAL ;
		PORT
			LAYER metal1 ;
			RECT 17.649 17.649 17.649 17.649 ;
			END
		END IP21
	PIN IP22
		DIRECTION INPUT ;
		USE SIGNAL ;
		PORT
			LAYER metal1 ;
			RECT 17.649 17.649 17.649 17.649 ;
			END
		END IP22
	PIN IP23
		DIRECTION INPUT ;
		USE SIGNAL ;
		PORT
			LAYER metal1 ;
			RECT 17.649 17.649 17.649 17.649 ;
			END
		END IP23
	PIN IP24
		DIRECTION INPUT ;
		USE SIGNAL ;
		PORT
			LAYER metal1 ;
			RECT 17.649 17.649 17.649 17.649 ;
			END
		END IP24
	PIN IP25
		DIRECTION INPUT ;
		USE SIGNAL ;
		PORT
			LAYER metal1 ;
			RECT 17.649 17.649 17.649 17.649 ;
			END
		END IP25
	PIN IP26
		DIRECTION INPUT ;
		USE SIGNAL ;
		PORT
			LAYER metal1 ;
			RECT 17.649 17.649 17.649 17.649 ;
			END
		END IP26
	PIN IP27
		DIRECTION INPUT ;
		USE SIGNAL ;
		PORT
			LAYER metal1 ;
			RECT 17.649 17.649 17.649 17.649 ;
			END
		END IP27
	PIN IP28
		DIRECTION INPUT ;
		USE SIGNAL ;
		PORT
			LAYER metal1 ;
			RECT 17.649 17.649 17.649 17.649 ;
			END
		END IP28
	PIN IP29
		DIRECTION INPUT ;
		USE SIGNAL ;
		PORT
			LAYER metal1 ;
			RECT 17.649 17.649 17.649 17.649 ;
			END
		END IP29
	PIN IP30
		DIRECTION INPUT ;
		USE SIGNAL ;
		PORT
			LAYER metal1 ;
			RECT 17.649 17.649 17.649 17.649 ;
			END
		END IP30
	PIN IP31
		DIRECTION INPUT ;
		USE SIGNAL ;
		PORT
			LAYER metal1 ;
			RECT 17.649 17.649 17.649 17.649 ;
			END
		END IP31
	PIN IP32
		DIRECTION INPUT ;
		USE SIGNAL ;
		PORT
			LAYER metal1 ;
			RECT 17.649 17.649 17.649 17.649 ;
			END
		END IP32
	PIN IP33
		DIRECTION INPUT ;
		USE SIGNAL ;
		PORT
			LAYER metal1 ;
			RECT 17.649 17.649 17.649 17.649 ;
			END
		END IP33
END cluster_0
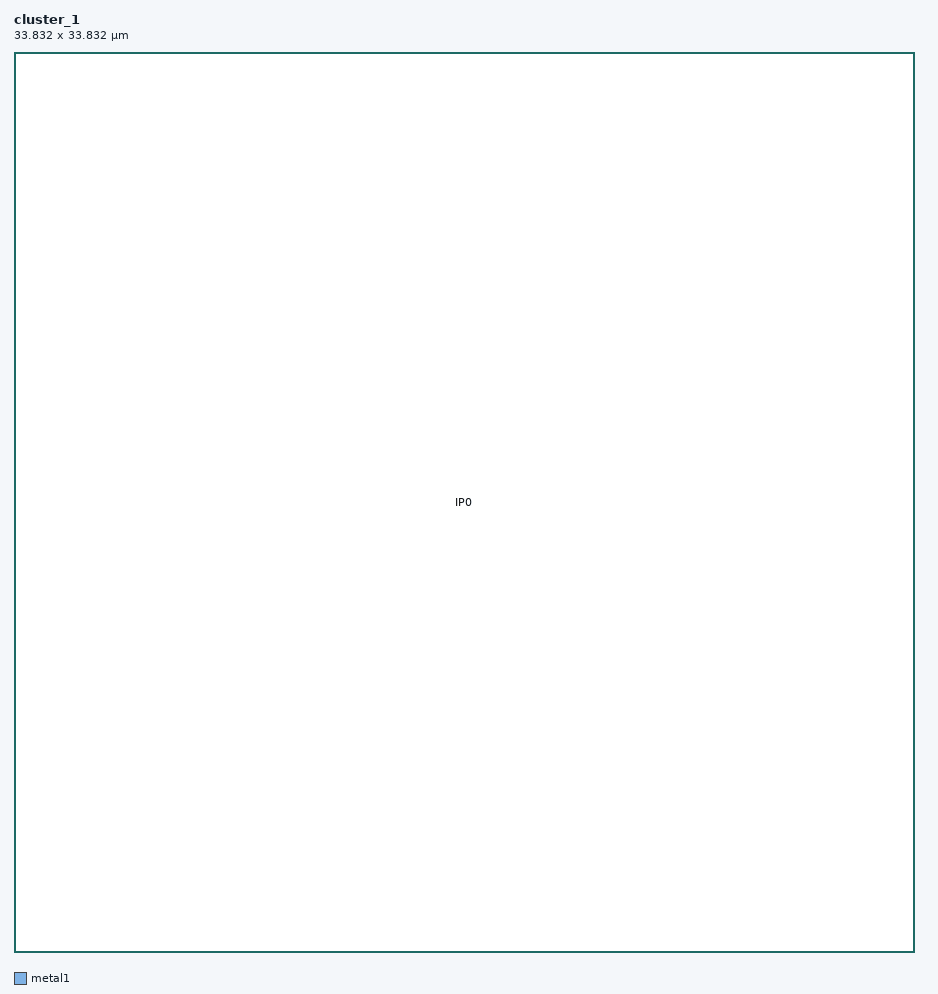
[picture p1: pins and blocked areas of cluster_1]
MACRO cluster_1
	CLASS BLOCK ;
	ORIGIN 0 0 ;
	FOREIGN cluster_1 0 0 ;
	SIZE 33.832 BY 33.832 ;
	SYMMETRY X Y ;
	PIN OP0
		DIRECTION OUTPUT ;
		USE SIGNAL ;
		PORT
			LAYER metal1 ;
			RECT 16.916 16.916 16.916 16.916 ;
			END
		END OP0
	PIN OP1
		DIRECTION OUTPUT ;
		USE SIGNAL ;
		PORT
			LAYER metal1 ;
			RECT 16.916 16.916 16.916 16.916 ;
			END
		END OP1
	PIN OP2
		DIRECTION OUTPUT ;
		USE SIGNAL ;
		PORT
			LAYER metal1 ;
			RECT 16.916 16.916 16.916 16.916 ;
			END
		END OP2
	PIN OP3
		DIRECTION OUTPUT ;
		USE SIGNAL ;
		PORT
			LAYER metal1 ;
			RECT 16.916 16.916 16.916 16.916 ;
			END
		END OP3
	PIN OP4
		DIRECTION OUTPUT ;
		USE SIGNAL ;
		PORT
			LAYER metal1 ;
			RECT 16.916 16.916 16.916 16.916 ;
			END
		END OP4
	PIN OP5
		DIRECTION OUTPUT ;
		USE SIGNAL ;
		PORT
			LAYER metal1 ;
			RECT 16.916 16.916 16.916 16.916 ;
			END
		END OP5
	PIN OP6
		DIRECTION OUTPUT ;
		USE SIGNAL ;
		PORT
			LAYER metal1 ;
			RECT 16.916 16.916 16.916 16.916 ;
			END
		END OP6
	PIN OP7
		DIRECTION OUTPUT ;
		USE SIGNAL ;
		PORT
			LAYER metal1 ;
			RECT 16.916 16.916 16.916 16.916 ;
			END
		END OP7
	PIN OP8
		DIRECTION OUTPUT ;
		USE SIGNAL ;
		PORT
			LAYER metal1 ;
			RECT 16.916 16.916 16.916 16.916 ;
			END
		END OP8
	PIN OP9
		DIRECTION OUTPUT ;
		USE SIGNAL ;
		PORT
			LAYER metal1 ;
			RECT 16.916 16.916 16.916 16.916 ;
			END
		END OP9
	PIN OP10
		DIRECTION OUTPUT ;
		USE SIGNAL ;
		PORT
			LAYER metal1 ;
			RECT 16.916 16.916 16.916 16.916 ;
			END
		END OP10
	PIN OP11
		DIRECTION OUTPUT ;
		USE SIGNAL ;
		PORT
			LAYER metal1 ;
			RECT 16.916 16.916 16.916 16.916 ;
			END
		END OP11
	PIN OP12
		DIRECTION OUTPUT ;
		USE SIGNAL ;
		PORT
			LAYER metal1 ;
			RECT 16.916 16.916 16.916 16.916 ;
			END
		END OP12
	PIN OP13
		DIRECTION OUTPUT ;
		USE SIGNAL ;
		PORT
			LAYER metal1 ;
			RECT 16.916 16.916 16.916 16.916 ;
			END
		END OP13
	PIN OP14
		DIRECTION OUTPUT ;
		USE SIGNAL ;
		PORT
			LAYER metal1 ;
			RECT 16.916 16.916 16.916 16.916 ;
			END
		END OP14
	PIN OP15
		DIRECTION OUTPUT ;
		USE SIGNAL ;
		PORT
			LAYER metal1 ;
			RECT 16.916 16.916 16.916 16.916 ;
			END
		END OP15
	PIN OP16
		DIRECTION OUTPUT ;
		USE SIGNAL ;
		PORT
			LAYER metal1 ;
			RECT 16.916 16.916 16.916 16.916 ;
			END
		END OP16
	PIN OP17
		DIRECTION OUTPUT ;
		USE SIGNAL ;
		PORT
			LAYER metal1 ;
			RECT 16.916 16.916 16.916 16.916 ;
			END
		END OP17
	PIN OP18
		DIRECTION OUTPUT ;
		USE SIGNAL ;
		PORT
			LAYER metal1 ;
			RECT 16.916 16.916 16.916 16.916 ;
			END
		END OP18
	PIN OP19
		DIRECTION OUTPUT ;
		USE SIGNAL ;
		PORT
			LAYER metal1 ;
			RECT 16.916 16.916 16.916 16.916 ;
			END
		END OP19
	PIN OP20
		DIRECTION OUTPUT ;
		USE SIGNAL ;
		PORT
			LAYER metal1 ;
			RECT 16.916 16.916 16.916 16.916 ;
			END
		END OP20
	PIN OP21
		DIRECTION OUTPUT ;
		USE SIGNAL ;
		PORT
			LAYER metal1 ;
			RECT 16.916 16.916 16.916 16.916 ;
			END
		END OP21
	PIN OP22
		DIRECTION OUTPUT ;
		USE SIGNAL ;
		PORT
			LAYER metal1 ;
			RECT 16.916 16.916 16.916 16.916 ;
			END
		END OP22
	PIN OP23
		DIRECTION OUTPUT ;
		USE SIGNAL ;
		PORT
			LAYER metal1 ;
			RECT 16.916 16.916 16.916 16.916 ;
			END
		END OP23
	PIN OP24
		DIRECTION OUTPUT ;
		USE SIGNAL ;
		PORT
			LAYER metal1 ;
			RECT 16.916 16.916 16.916 16.916 ;
			END
		END OP24
	PIN OP25
		DIRECTION OUTPUT ;
		USE SIGNAL ;
		PORT
			LAYER metal1 ;
			RECT 16.916 16.916 16.916 16.916 ;
			END
		END OP25
	PIN OP26
		DIRECTION OUTPUT ;
		USE SIGNAL ;
		PORT
			LAYER metal1 ;
			RECT 16.916 16.916 16.916 16.916 ;
			END
		END OP26
	PIN OP27
		DIRECTION OUTPUT ;
		USE SIGNAL ;
		PORT
			LAYER metal1 ;
			RECT 16.916 16.916 16.916 16.916 ;
			END
		END OP27
	PIN OP28
		DIRECTION OUTPUT ;
		USE SIGNAL ;
		PORT
			LAYER metal1 ;
			RECT 16.916 16.916 16.916 16.916 ;
			END
		END OP28
	PIN OP29
		DIRECTION OUTPUT ;
		USE SIGNAL ;
		PORT
			LAYER metal1 ;
			RECT 16.916 16.916 16.916 16.916 ;
			END
		END OP29
	PIN OP30
		DIRECTION OUTPUT ;
		USE SIGNAL ;
		PORT
			LAYER metal1 ;
			RECT 16.916 16.916 16.916 16.916 ;
			END
		END OP30
	PIN OP31
		DIRECTION OUTPUT ;
		USE SIGNAL ;
		PORT
			LAYER metal1 ;
			RECT 16.916 16.916 16.916 16.916 ;
			END
		END OP31
	PIN OP32
		DIRECTION OUTPUT ;
		USE SIGNAL ;
		PORT
			LAYER metal1 ;
			RECT 16.916 16.916 16.916 16.916 ;
			END
		END OP32
	PIN OP33
		DIRECTION OUTPUT ;
		USE SIGNAL ;
		PORT
			LAYER metal1 ;
			RECT 16.916 16.916 16.916 16.916 ;
			END
		END OP33
	PIN OP34
		DIRECTION OUTPUT ;
		USE SIGNAL ;
		PORT
			LAYER metal1 ;
			RECT 16.916 16.916 16.916 16.916 ;
			END
		END OP34
	PIN OP35
		DIRECTION OUTPUT ;
		USE SIGNAL ;
		PORT
			LAYER metal1 ;
			RECT 16.916 16.916 16.916 16.916 ;
			END
		END OP35
	PIN OP36
		DIRECTION OUTPUT ;
		USE SIGNAL ;
		PORT
			LAYER metal1 ;
			RECT 16.916 16.916 16.916 16.916 ;
			END
		END OP36
	PIN OP37
		DIRECTION OUTPUT ;
		USE SIGNAL ;
		PORT
			LAYER metal1 ;
			RECT 16.916 16.916 16.916 16.916 ;
			END
		END OP37
	PIN OP38
		DIRECTION OUTPUT ;
		USE SIGNAL ;
		PORT
			LAYER metal1 ;
			RECT 16.916 16.916 16.916 16.916 ;
			END
		END OP38
	PIN OP39
		DIRECTION OUTPUT ;
		USE SIGNAL ;
		PORT
			LAYER metal1 ;
			RECT 16.916 16.916 16.916 16.916 ;
			END
		END OP39
	PIN OP40
		DIRECTION OUTPUT ;
		USE SIGNAL ;
		PORT
			LAYER metal1 ;
			RECT 16.916 16.916 16.916 16.916 ;
			END
		END OP40
	PIN OP41
		DIRECTION OUTPUT ;
		USE SIGNAL ;
		PORT
			LAYER metal1 ;
			RECT 16.916 16.916 16.916 16.916 ;
			END
		END OP41
	PIN OP42
		DIRECTION OUTPUT ;
		USE SIGNAL ;
		PORT
			LAYER metal1 ;
			RECT 16.916 16.916 16.916 16.916 ;
			END
		END OP42
	PIN OP43
		DIRECTION OUTPUT ;
		USE SIGNAL ;
		PORT
			LAYER metal1 ;
			RECT 16.916 16.916 16.916 16.916 ;
			END
		END OP43
	PIN OP44
		DIRECTION OUTPUT ;
		USE SIGNAL ;
		PORT
			LAYER metal1 ;
			RECT 16.916 16.916 16.916 16.916 ;
			END
		END OP44
	PIN OP45
		DIRECTION OUTPUT ;
		USE SIGNAL ;
		PORT
			LAYER metal1 ;
			RECT 16.916 16.916 16.916 16.916 ;
			END
		END OP45
	PIN OP46
		DIRECTION OUTPUT ;
		USE SIGNAL ;
		PORT
			LAYER metal1 ;
			RECT 16.916 16.916 16.916 16.916 ;
			END
		END OP46
	PIN OP47
		DIRECTION OUTPUT ;
		USE SIGNAL ;
		PORT
			LAYER metal1 ;
			RECT 16.916 16.916 16.916 16.916 ;
			END
		END OP47
	PIN OP48
		DIRECTION OUTPUT ;
		USE SIGNAL ;
		PORT
			LAYER metal1 ;
			RECT 16.916 16.916 16.916 16.916 ;
			END
		END OP48
	PIN OP49
		DIRECTION OUTPUT ;
		USE SIGNAL ;
		PORT
			LAYER metal1 ;
			RECT 16.916 16.916 16.916 16.916 ;
			END
		END OP49
	PIN OP50
		DIRECTION OUTPUT ;
		USE SIGNAL ;
		PORT
			LAYER metal1 ;
			RECT 16.916 16.916 16.916 16.916 ;
			END
		END OP50
	PIN OP51
		DIRECTION OUTPUT ;
		USE SIGNAL ;
		PORT
			LAYER metal1 ;
			RECT 16.916 16.916 16.916 16.916 ;
			END
		END OP51
	PIN OP52
		DIRECTION OUTPUT ;
		USE SIGNAL ;
		PORT
			LAYER metal1 ;
			RECT 16.916 16.916 16.916 16.916 ;
			END
		END OP52
	PIN OP53
		DIRECTION OUTPUT ;
		USE SIGNAL ;
		PORT
			LAYER metal1 ;
			RECT 16.916 16.916 16.916 16.916 ;
			END
		END OP53
	PIN OP54
		DIRECTION OUTPUT ;
		USE SIGNAL ;
		PORT
			LAYER metal1 ;
			RECT 16.916 16.916 16.916 16.916 ;
			END
		END OP54
	PIN IP0
		DIRECTION INPUT ;
		USE SIGNAL ;
		PORT
			LAYER metal1 ;
			RECT 16.916 16.916 16.916 16.916 ;
			END
		END IP0
	PIN IP1
		DIRECTION INPUT ;
		USE SIGNAL ;
		PORT
			LAYER metal1 ;
			RECT 16.916 16.916 16.916 16.916 ;
			END
		END IP1
	PIN IP2
		DIRECTION INPUT ;
		USE SIGNAL ;
		PORT
			LAYER metal1 ;
			RECT 16.916 16.916 16.916 16.916 ;
			END
		END IP2
	PIN IP3
		DIRECTION INPUT ;
		USE SIGNAL ;
		PORT
			LAYER metal1 ;
			RECT 16.916 16.916 16.916 16.916 ;
			END
		END IP3
	PIN IP4
		DIRECTION INPUT ;
		USE SIGNAL ;
		PORT
			LAYER metal1 ;
			RECT 16.916 16.916 16.916 16.916 ;
			END
		END IP4
	PIN IP5
		DIRECTION INPUT ;
		USE SIGNAL ;
		PORT
			LAYER metal1 ;
			RECT 16.916 16.916 16.916 16.916 ;
			END
		END IP5
	PIN IP6
		DIRECTION INPUT ;
		USE SIGNAL ;
		PORT
			LAYER metal1 ;
			RECT 16.916 16.916 16.916 16.916 ;
			END
		END IP6
	PIN IP7
		DIRECTION INPUT ;
		USE SIGNAL ;
		PORT
			LAYER metal1 ;
			RECT 16.916 16.916 16.916 16.916 ;
			END
		END IP7
	PIN IP8
		DIRECTION INPUT ;
		USE SIGNAL ;
		PORT
			LAYER metal1 ;
			RECT 16.916 16.916 16.916 16.916 ;
			END
		END IP8
	PIN IP9
		DIRECTION INPUT ;
		USE SIGNAL ;
		PORT
			LAYER metal1 ;
			RECT 16.916 16.916 16.916 16.916 ;
			END
		END IP9
	PIN IP10
		DIRECTION INPUT ;
		USE SIGNAL ;
		PORT
			LAYER metal1 ;
			RECT 16.916 16.916 16.916 16.916 ;
			END
		END IP10
	PIN IP11
		DIRECTION INPUT ;
		USE SIGNAL ;
		PORT
			LAYER metal1 ;
			RECT 16.916 16.916 16.916 16.916 ;
			END
		END IP11
	PIN IP12
		DIRECTION INPUT ;
		USE SIGNAL ;
		PORT
			LAYER metal1 ;
			RECT 16.916 16.916 16.916 16.916 ;
			END
		END IP12
	PIN IP13
		DIRECTION INPUT ;
		USE SIGNAL ;
		PORT
			LAYER metal1 ;
			RECT 16.916 16.916 16.916 16.916 ;
			END
		END IP13
	PIN IP14
		DIRECTION INPUT ;
		USE SIGNAL ;
		PORT
			LAYER metal1 ;
			RECT 16.916 16.916 16.916 16.916 ;
			END
		END IP14
	PIN IP15
		DIRECTION INPUT ;
		USE SIGNAL ;
		PORT
			LAYER metal1 ;
			RECT 16.916 16.916 16.916 16.916 ;
			END
		END IP15
	PIN IP16
		DIRECTION INPUT ;
		USE SIGNAL ;
		PORT
			LAYER metal1 ;
			RECT 16.916 16.916 16.916 16.916 ;
			END
		END IP16
END cluster_1
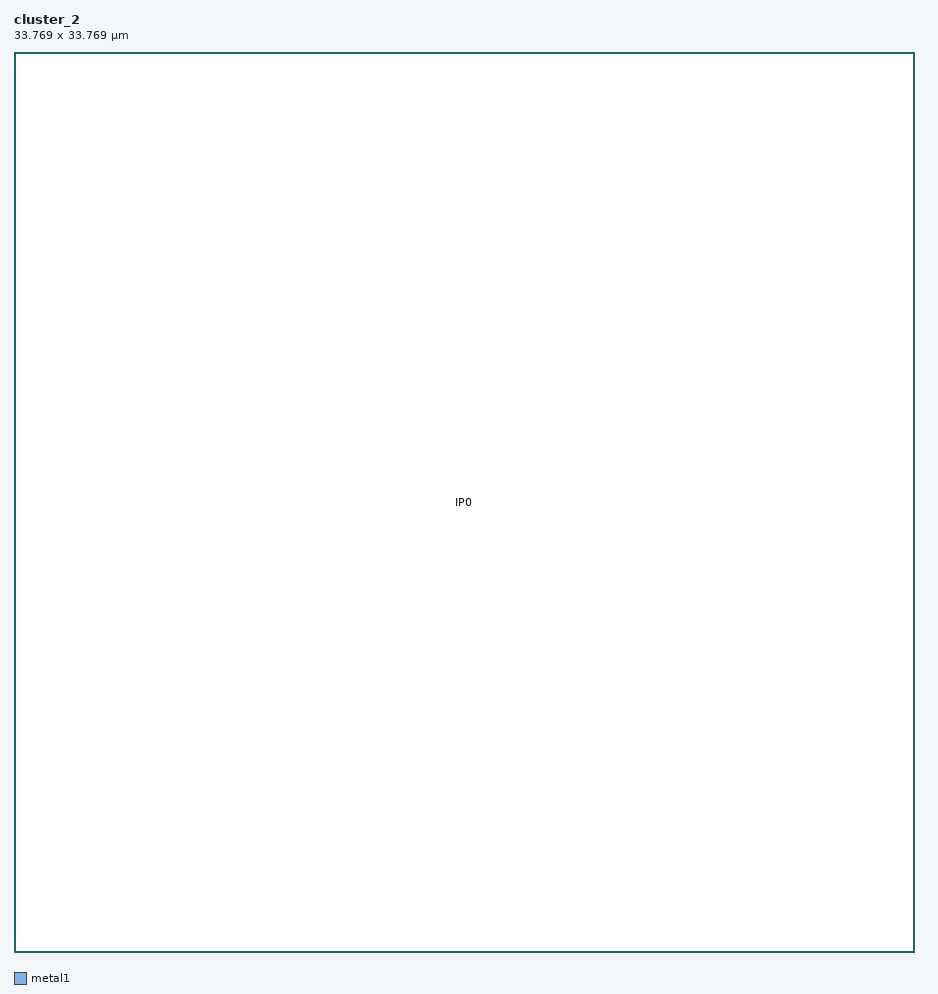
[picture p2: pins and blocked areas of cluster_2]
MACRO cluster_2
	CLASS BLOCK ;
	ORIGIN 0 0 ;
	FOREIGN cluster_2 0 0 ;
	SIZE 33.769 BY 33.769 ;
	SYMMETRY X Y ;
	PIN OP0
		DIRECTION OUTPUT ;
		USE SIGNAL ;
		PORT
			LAYER metal1 ;
			RECT 16.884 16.884 16.884 16.884 ;
			END
		END OP0
	PIN OP1
		DIRECTION OUTPUT ;
		USE SIGNAL ;
		PORT
			LAYER metal1 ;
			RECT 16.884 16.884 16.884 16.884 ;
			END
		END OP1
	PIN OP2
		DIRECTION OUTPUT ;
		USE SIGNAL ;
		PORT
			LAYER metal1 ;
			RECT 16.884 16.884 16.884 16.884 ;
			END
		END OP2
	PIN OP3
		DIRECTION OUTPUT ;
		USE SIGNAL ;
		PORT
			LAYER metal1 ;
			RECT 16.884 16.884 16.884 16.884 ;
			END
		END OP3
	PIN OP4
		DIRECTION OUTPUT ;
		USE SIGNAL ;
		PORT
			LAYER metal1 ;
			RECT 16.884 16.884 16.884 16.884 ;
			END
		END OP4
	PIN OP5
		DIRECTION OUTPUT ;
		USE SIGNAL ;
		PORT
			LAYER metal1 ;
			RECT 16.884 16.884 16.884 16.884 ;
			END
		END OP5
	PIN OP6
		DIRECTION OUTPUT ;
		USE SIGNAL ;
		PORT
			LAYER metal1 ;
			RECT 16.884 16.884 16.884 16.884 ;
			END
		END OP6
	PIN OP7
		DIRECTION OUTPUT ;
		USE SIGNAL ;
		PORT
			LAYER metal1 ;
			RECT 16.884 16.884 16.884 16.884 ;
			END
		END OP7
	PIN OP8
		DIRECTION OUTPUT ;
		USE SIGNAL ;
		PORT
			LAYER metal1 ;
			RECT 16.884 16.884 16.884 16.884 ;
			END
		END OP8
	PIN OP9
		DIRECTION OUTPUT ;
		USE SIGNAL ;
		PORT
			LAYER metal1 ;
			RECT 16.884 16.884 16.884 16.884 ;
			END
		END OP9
	PIN OP10
		DIRECTION OUTPUT ;
		USE SIGNAL ;
		PORT
			LAYER metal1 ;
			RECT 16.884 16.884 16.884 16.884 ;
			END
		END OP10
	PIN OP11
		DIRECTION OUTPUT ;
		USE SIGNAL ;
		PORT
			LAYER metal1 ;
			RECT 16.884 16.884 16.884 16.884 ;
			END
		END OP11
	PIN OP12
		DIRECTION OUTPUT ;
		USE SIGNAL ;
		PORT
			LAYER metal1 ;
			RECT 16.884 16.884 16.884 16.884 ;
			END
		END OP12
	PIN OP13
		DIRECTION OUTPUT ;
		USE SIGNAL ;
		PORT
			LAYER metal1 ;
			RECT 16.884 16.884 16.884 16.884 ;
			END
		END OP13
	PIN OP14
		DIRECTION OUTPUT ;
		USE SIGNAL ;
		PORT
			LAYER metal1 ;
			RECT 16.884 16.884 16.884 16.884 ;
			END
		END OP14
	PIN OP15
		DIRECTION OUTPUT ;
		USE SIGNAL ;
		PORT
			LAYER metal1 ;
			RECT 16.884 16.884 16.884 16.884 ;
			END
		END OP15
	PIN OP16
		DIRECTION OUTPUT ;
		USE SIGNAL ;
		PORT
			LAYER metal1 ;
			RECT 16.884 16.884 16.884 16.884 ;
			END
		END OP16
	PIN OP17
		DIRECTION OUTPUT ;
		USE SIGNAL ;
		PORT
			LAYER metal1 ;
			RECT 16.884 16.884 16.884 16.884 ;
			END
		END OP17
	PIN OP18
		DIRECTION OUTPUT ;
		USE SIGNAL ;
		PORT
			LAYER metal1 ;
			RECT 16.884 16.884 16.884 16.884 ;
			END
		END OP18
	PIN OP19
		DIRECTION OUTPUT ;
		USE SIGNAL ;
		PORT
			LAYER metal1 ;
			RECT 16.884 16.884 16.884 16.884 ;
			END
		END OP19
	PIN OP20
		DIRECTION OUTPUT ;
		USE SIGNAL ;
		PORT
			LAYER metal1 ;
			RECT 16.884 16.884 16.884 16.884 ;
			END
		END OP20
	PIN OP21
		DIRECTION OUTPUT ;
		USE SIGNAL ;
		PORT
			LAYER metal1 ;
			RECT 16.884 16.884 16.884 16.884 ;
			END
		END OP21
	PIN OP22
		DIRECTION OUTPUT ;
		USE SIGNAL ;
		PORT
			LAYER metal1 ;
			RECT 16.884 16.884 16.884 16.884 ;
			END
		END OP22
	PIN OP23
		DIRECTION OUTPUT ;
		USE SIGNAL ;
		PORT
			LAYER metal1 ;
			RECT 16.884 16.884 16.884 16.884 ;
			END
		END OP23
	PIN OP24
		DIRECTION OUTPUT ;
		USE SIGNAL ;
		PORT
			LAYER metal1 ;
			RECT 16.884 16.884 16.884 16.884 ;
			END
		END OP24
	PIN OP25
		DIRECTION OUTPUT ;
		USE SIGNAL ;
		PORT
			LAYER metal1 ;
			RECT 16.884 16.884 16.884 16.884 ;
			END
		END OP25
	PIN OP26
		DIRECTION OUTPUT ;
		USE SIGNAL ;
		PORT
			LAYER metal1 ;
			RECT 16.884 16.884 16.884 16.884 ;
			END
		END OP26
	PIN OP27
		DIRECTION OUTPUT ;
		USE SIGNAL ;
		PORT
			LAYER metal1 ;
			RECT 16.884 16.884 16.884 16.884 ;
			END
		END OP27
	PIN OP28
		DIRECTION OUTPUT ;
		USE SIGNAL ;
		PORT
			LAYER metal1 ;
			RECT 16.884 16.884 16.884 16.884 ;
			END
		END OP28
	PIN OP29
		DIRECTION OUTPUT ;
		USE SIGNAL ;
		PORT
			LAYER metal1 ;
			RECT 16.884 16.884 16.884 16.884 ;
			END
		END OP29
	PIN OP30
		DIRECTION OUTPUT ;
		USE SIGNAL ;
		PORT
			LAYER metal1 ;
			RECT 16.884 16.884 16.884 16.884 ;
			END
		END OP30
	PIN OP31
		DIRECTION OUTPUT ;
		USE SIGNAL ;
		PORT
			LAYER metal1 ;
			RECT 16.884 16.884 16.884 16.884 ;
			END
		END OP31
	PIN OP32
		DIRECTION OUTPUT ;
		USE SIGNAL ;
		PORT
			LAYER metal1 ;
			RECT 16.884 16.884 16.884 16.884 ;
			END
		END OP32
	PIN OP33
		DIRECTION OUTPUT ;
		USE SIGNAL ;
		PORT
			LAYER metal1 ;
			RECT 16.884 16.884 16.884 16.884 ;
			END
		END OP33
	PIN OP34
		DIRECTION OUTPUT ;
		USE SIGNAL ;
		PORT
			LAYER metal1 ;
			RECT 16.884 16.884 16.884 16.884 ;
			END
		END OP34
	PIN OP35
		DIRECTION OUTPUT ;
		USE SIGNAL ;
		PORT
			LAYER metal1 ;
			RECT 16.884 16.884 16.884 16.884 ;
			END
		END OP35
	PIN OP36
		DIRECTION OUTPUT ;
		USE SIGNAL ;
		PORT
			LAYER metal1 ;
			RECT 16.884 16.884 16.884 16.884 ;
			END
		END OP36
	PIN OP37
		DIRECTION OUTPUT ;
		USE SIGNAL ;
		PORT
			LAYER metal1 ;
			RECT 16.884 16.884 16.884 16.884 ;
			END
		END OP37
	PIN OP38
		DIRECTION OUTPUT ;
		USE SIGNAL ;
		PORT
			LAYER metal1 ;
			RECT 16.884 16.884 16.884 16.884 ;
			END
		END OP38
	PIN OP39
		DIRECTION OUTPUT ;
		USE SIGNAL ;
		PORT
			LAYER metal1 ;
			RECT 16.884 16.884 16.884 16.884 ;
			END
		END OP39
	PIN OP40
		DIRECTION OUTPUT ;
		USE SIGNAL ;
		PORT
			LAYER metal1 ;
			RECT 16.884 16.884 16.884 16.884 ;
			END
		END OP40
	PIN OP41
		DIRECTION OUTPUT ;
		USE SIGNAL ;
		PORT
			LAYER metal1 ;
			RECT 16.884 16.884 16.884 16.884 ;
			END
		END OP41
	PIN OP42
		DIRECTION OUTPUT ;
		USE SIGNAL ;
		PORT
			LAYER metal1 ;
			RECT 16.884 16.884 16.884 16.884 ;
			END
		END OP42
	PIN OP43
		DIRECTION OUTPUT ;
		USE SIGNAL ;
		PORT
			LAYER metal1 ;
			RECT 16.884 16.884 16.884 16.884 ;
			END
		END OP43
	PIN OP44
		DIRECTION OUTPUT ;
		USE SIGNAL ;
		PORT
			LAYER metal1 ;
			RECT 16.884 16.884 16.884 16.884 ;
			END
		END OP44
	PIN OP45
		DIRECTION OUTPUT ;
		USE SIGNAL ;
		PORT
			LAYER metal1 ;
			RECT 16.884 16.884 16.884 16.884 ;
			END
		END OP45
	PIN OP46
		DIRECTION OUTPUT ;
		USE SIGNAL ;
		PORT
			LAYER metal1 ;
			RECT 16.884 16.884 16.884 16.884 ;
			END
		END OP46
	PIN OP47
		DIRECTION OUTPUT ;
		USE SIGNAL ;
		PORT
			LAYER metal1 ;
			RECT 16.884 16.884 16.884 16.884 ;
			END
		END OP47
	PIN OP48
		DIRECTION OUTPUT ;
		USE SIGNAL ;
		PORT
			LAYER metal1 ;
			RECT 16.884 16.884 16.884 16.884 ;
			END
		END OP48
	PIN OP49
		DIRECTION OUTPUT ;
		USE SIGNAL ;
		PORT
			LAYER metal1 ;
			RECT 16.884 16.884 16.884 16.884 ;
			END
		END OP49
	PIN OP50
		DIRECTION OUTPUT ;
		USE SIGNAL ;
		PORT
			LAYER metal1 ;
			RECT 16.884 16.884 16.884 16.884 ;
			END
		END OP50
	PIN OP51
		DIRECTION OUTPUT ;
		USE SIGNAL ;
		PORT
			LAYER metal1 ;
			RECT 16.884 16.884 16.884 16.884 ;
			END
		END OP51
	PIN OP52
		DIRECTION OUTPUT ;
		USE SIGNAL ;
		PORT
			LAYER metal1 ;
			RECT 16.884 16.884 16.884 16.884 ;
			END
		END OP52
	PIN OP53
		DIRECTION OUTPUT ;
		USE SIGNAL ;
		PORT
			LAYER metal1 ;
			RECT 16.884 16.884 16.884 16.884 ;
			END
		END OP53
	PIN OP54
		DIRECTION OUTPUT ;
		USE SIGNAL ;
		PORT
			LAYER metal1 ;
			RECT 16.884 16.884 16.884 16.884 ;
			END
		END OP54
	PIN OP55
		DIRECTION OUTPUT ;
		USE SIGNAL ;
		PORT
			LAYER metal1 ;
			RECT 16.884 16.884 16.884 16.884 ;
			END
		END OP55
	PIN OP56
		DIRECTION OUTPUT ;
		USE SIGNAL ;
		PORT
			LAYER metal1 ;
			RECT 16.884 16.884 16.884 16.884 ;
			END
		END OP56
	PIN OP57
		DIRECTION OUTPUT ;
		USE SIGNAL ;
		PORT
			LAYER metal1 ;
			RECT 16.884 16.884 16.884 16.884 ;
			END
		END OP57
	PIN OP58
		DIRECTION OUTPUT ;
		USE SIGNAL ;
		PORT
			LAYER metal1 ;
			RECT 16.884 16.884 16.884 16.884 ;
			END
		END OP58
	PIN OP59
		DIRECTION OUTPUT ;
		USE SIGNAL ;
		PORT
			LAYER metal1 ;
			RECT 16.884 16.884 16.884 16.884 ;
			END
		END OP59
	PIN OP60
		DIRECTION OUTPUT ;
		USE SIGNAL ;
		PORT
			LAYER metal1 ;
			RECT 16.884 16.884 16.884 16.884 ;
			END
		END OP60
	PIN OP61
		DIRECTION OUTPUT ;
		USE SIGNAL ;
		PORT
			LAYER metal1 ;
			RECT 16.884 16.884 16.884 16.884 ;
			END
		END OP61
	PIN OP62
		DIRECTION OUTPUT ;
		USE SIGNAL ;
		PORT
			LAYER metal1 ;
			RECT 16.884 16.884 16.884 16.884 ;
			END
		END OP62
	PIN OP63
		DIRECTION OUTPUT ;
		USE SIGNAL ;
		PORT
			LAYER metal1 ;
			RECT 16.884 16.884 16.884 16.884 ;
			END
		END OP63
	PIN OP64
		DIRECTION OUTPUT ;
		USE SIGNAL ;
		PORT
			LAYER metal1 ;
			RECT 16.884 16.884 16.884 16.884 ;
			END
		END OP64
	PIN IP0
		DIRECTION INPUT ;
		USE SIGNAL ;
		PORT
			LAYER metal1 ;
			RECT 16.884 16.884 16.884 16.884 ;
			END
		END IP0
	PIN IP1
		DIRECTION INPUT ;
		USE SIGNAL ;
		PORT
			LAYER metal1 ;
			RECT 16.884 16.884 16.884 16.884 ;
			END
		END IP1
	PIN IP2
		DIRECTION INPUT ;
		USE SIGNAL ;
		PORT
			LAYER metal1 ;
			RECT 16.884 16.884 16.884 16.884 ;
			END
		END IP2
	PIN IP3
		DIRECTION INPUT ;
		USE SIGNAL ;
		PORT
			LAYER metal1 ;
			RECT 16.884 16.884 16.884 16.884 ;
			END
		END IP3
	PIN IP4
		DIRECTION INPUT ;
		USE SIGNAL ;
		PORT
			LAYER metal1 ;
			RECT 16.884 16.884 16.884 16.884 ;
			END
		END IP4
	PIN IP5
		DIRECTION INPUT ;
		USE SIGNAL ;
		PORT
			LAYER metal1 ;
			RECT 16.884 16.884 16.884 16.884 ;
			END
		END IP5
	PIN IP6
		DIRECTION INPUT ;
		USE SIGNAL ;
		PORT
			LAYER metal1 ;
			RECT 16.884 16.884 16.884 16.884 ;
			END
		END IP6
	PIN IP7
		DIRECTION INPUT ;
		USE SIGNAL ;
		PORT
			LAYER metal1 ;
			RECT 16.884 16.884 16.884 16.884 ;
			END
		END IP7
	PIN IP8
		DIRECTION INPUT ;
		USE SIGNAL ;
		PORT
			LAYER metal1 ;
			RECT 16.884 16.884 16.884 16.884 ;
			END
		END IP8
	PIN IP9
		DIRECTION INPUT ;
		USE SIGNAL ;
		PORT
			LAYER metal1 ;
			RECT 16.884 16.884 16.884 16.884 ;
			END
		END IP9
	PIN IP10
		DIRECTION INPUT ;
		USE SIGNAL ;
		PORT
			LAYER metal1 ;
			RECT 16.884 16.884 16.884 16.884 ;
			END
		END IP10
	PIN IP11
		DIRECTION INPUT ;
		USE SIGNAL ;
		PORT
			LAYER metal1 ;
			RECT 16.884 16.884 16.884 16.884 ;
			END
		END IP11
	PIN IP12
		DIRECTION INPUT ;
		USE SIGNAL ;
		PORT
			LAYER metal1 ;
			RECT 16.884 16.884 16.884 16.884 ;
			END
		END IP12
	PIN IP13
		DIRECTION INPUT ;
		USE SIGNAL ;
		PORT
			LAYER metal1 ;
			RECT 16.884 16.884 16.884 16.884 ;
			END
		END IP13
	PIN IP14
		DIRECTION INPUT ;
		USE SIGNAL ;
		PORT
			LAYER metal1 ;
			RECT 16.884 16.884 16.884 16.884 ;
			END
		END IP14
	PIN IP15
		DIRECTION INPUT ;
		USE SIGNAL ;
		PORT
			LAYER metal1 ;
			RECT 16.884 16.884 16.884 16.884 ;
			END
		END IP15
	PIN IP16
		DIRECTION INPUT ;
		USE SIGNAL ;
		PORT
			LAYER metal1 ;
			RECT 16.884 16.884 16.884 16.884 ;
			END
		END IP16
END cluster_2
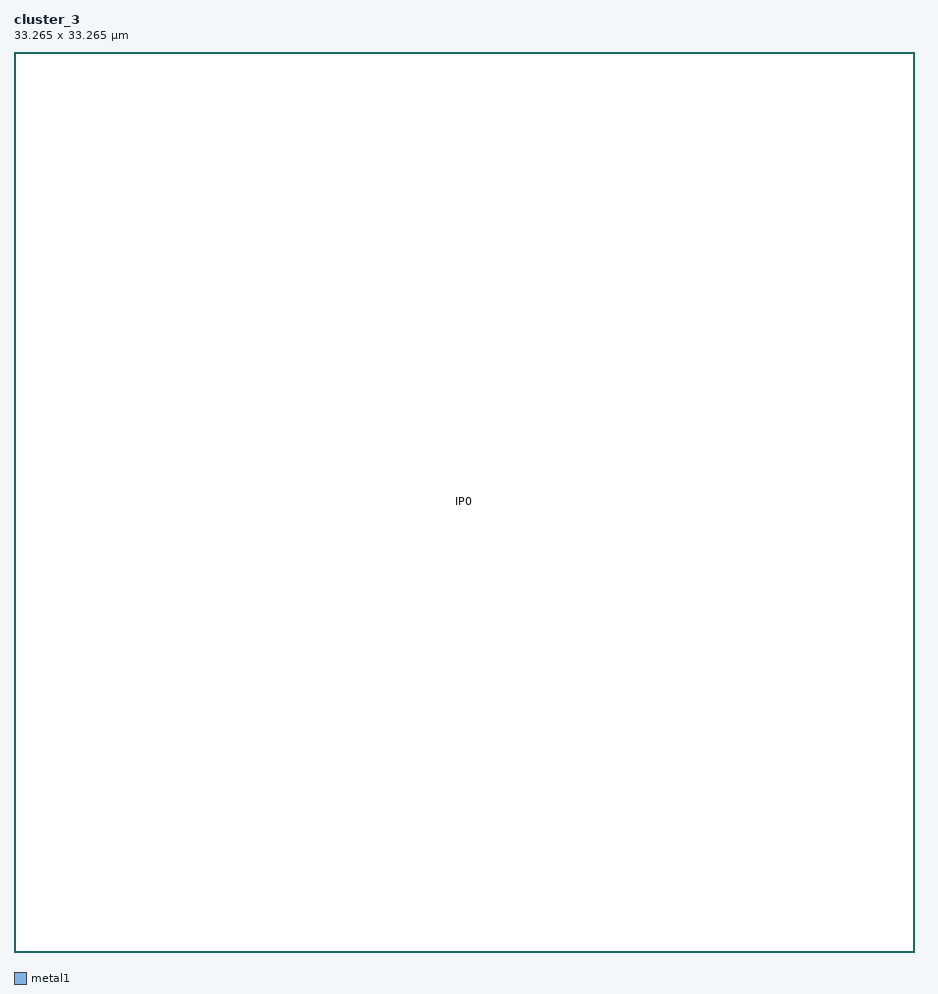
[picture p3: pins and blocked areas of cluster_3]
MACRO cluster_3
	CLASS BLOCK ;
	ORIGIN 0 0 ;
	FOREIGN cluster_3 0 0 ;
	SIZE 33.265 BY 33.265 ;
	SYMMETRY X Y ;
	PIN OP0
		DIRECTION OUTPUT ;
		USE SIGNAL ;
		PORT
			LAYER metal1 ;
			RECT 16.633 16.633 16.633 16.633 ;
			END
		END OP0
	PIN OP1
		DIRECTION OUTPUT ;
		USE SIGNAL ;
		PORT
			LAYER metal1 ;
			RECT 16.633 16.633 16.633 16.633 ;
			END
		END OP1
	PIN OP2
		DIRECTION OUTPUT ;
		USE SIGNAL ;
		PORT
			LAYER metal1 ;
			RECT 16.633 16.633 16.633 16.633 ;
			END
		END OP2
	PIN OP3
		DIRECTION OUTPUT ;
		USE SIGNAL ;
		PORT
			LAYER metal1 ;
			RECT 16.633 16.633 16.633 16.633 ;
			END
		END OP3
	PIN OP4
		DIRECTION OUTPUT ;
		USE SIGNAL ;
		PORT
			LAYER metal1 ;
			RECT 16.633 16.633 16.633 16.633 ;
			END
		END OP4
	PIN OP5
		DIRECTION OUTPUT ;
		USE SIGNAL ;
		PORT
			LAYER metal1 ;
			RECT 16.633 16.633 16.633 16.633 ;
			END
		END OP5
	PIN OP6
		DIRECTION OUTPUT ;
		USE SIGNAL ;
		PORT
			LAYER metal1 ;
			RECT 16.633 16.633 16.633 16.633 ;
			END
		END OP6
	PIN OP7
		DIRECTION OUTPUT ;
		USE SIGNAL ;
		PORT
			LAYER metal1 ;
			RECT 16.633 16.633 16.633 16.633 ;
			END
		END OP7
	PIN OP8
		DIRECTION OUTPUT ;
		USE SIGNAL ;
		PORT
			LAYER metal1 ;
			RECT 16.633 16.633 16.633 16.633 ;
			END
		END OP8
	PIN OP9
		DIRECTION OUTPUT ;
		USE SIGNAL ;
		PORT
			LAYER metal1 ;
			RECT 16.633 16.633 16.633 16.633 ;
			END
		END OP9
	PIN OP10
		DIRECTION OUTPUT ;
		USE SIGNAL ;
		PORT
			LAYER metal1 ;
			RECT 16.633 16.633 16.633 16.633 ;
			END
		END OP10
	PIN OP11
		DIRECTION OUTPUT ;
		USE SIGNAL ;
		PORT
			LAYER metal1 ;
			RECT 16.633 16.633 16.633 16.633 ;
			END
		END OP11
	PIN OP12
		DIRECTION OUTPUT ;
		USE SIGNAL ;
		PORT
			LAYER metal1 ;
			RECT 16.633 16.633 16.633 16.633 ;
			END
		END OP12
	PIN OP13
		DIRECTION OUTPUT ;
		USE SIGNAL ;
		PORT
			LAYER metal1 ;
			RECT 16.633 16.633 16.633 16.633 ;
			END
		END OP13
	PIN OP14
		DIRECTION OUTPUT ;
		USE SIGNAL ;
		PORT
			LAYER metal1 ;
			RECT 16.633 16.633 16.633 16.633 ;
			END
		END OP14
	PIN OP15
		DIRECTION OUTPUT ;
		USE SIGNAL ;
		PORT
			LAYER metal1 ;
			RECT 16.633 16.633 16.633 16.633 ;
			END
		END OP15
	PIN OP16
		DIRECTION OUTPUT ;
		USE SIGNAL ;
		PORT
			LAYER metal1 ;
			RECT 16.633 16.633 16.633 16.633 ;
			END
		END OP16
	PIN OP17
		DIRECTION OUTPUT ;
		USE SIGNAL ;
		PORT
			LAYER metal1 ;
			RECT 16.633 16.633 16.633 16.633 ;
			END
		END OP17
	PIN OP18
		DIRECTION OUTPUT ;
		USE SIGNAL ;
		PORT
			LAYER metal1 ;
			RECT 16.633 16.633 16.633 16.633 ;
			END
		END OP18
	PIN OP19
		DIRECTION OUTPUT ;
		USE SIGNAL ;
		PORT
			LAYER metal1 ;
			RECT 16.633 16.633 16.633 16.633 ;
			END
		END OP19
	PIN OP20
		DIRECTION OUTPUT ;
		USE SIGNAL ;
		PORT
			LAYER metal1 ;
			RECT 16.633 16.633 16.633 16.633 ;
			END
		END OP20
	PIN OP21
		DIRECTION OUTPUT ;
		USE SIGNAL ;
		PORT
			LAYER metal1 ;
			RECT 16.633 16.633 16.633 16.633 ;
			END
		END OP21
	PIN OP22
		DIRECTION OUTPUT ;
		USE SIGNAL ;
		PORT
			LAYER metal1 ;
			RECT 16.633 16.633 16.633 16.633 ;
			END
		END OP22
	PIN OP23
		DIRECTION OUTPUT ;
		USE SIGNAL ;
		PORT
			LAYER metal1 ;
			RECT 16.633 16.633 16.633 16.633 ;
			END
		END OP23
	PIN OP24
		DIRECTION OUTPUT ;
		USE SIGNAL ;
		PORT
			LAYER metal1 ;
			RECT 16.633 16.633 16.633 16.633 ;
			END
		END OP24
	PIN OP25
		DIRECTION OUTPUT ;
		USE SIGNAL ;
		PORT
			LAYER metal1 ;
			RECT 16.633 16.633 16.633 16.633 ;
			END
		END OP25
	PIN OP26
		DIRECTION OUTPUT ;
		USE SIGNAL ;
		PORT
			LAYER metal1 ;
			RECT 16.633 16.633 16.633 16.633 ;
			END
		END OP26
	PIN OP27
		DIRECTION OUTPUT ;
		USE SIGNAL ;
		PORT
			LAYER metal1 ;
			RECT 16.633 16.633 16.633 16.633 ;
			END
		END OP27
	PIN OP28
		DIRECTION OUTPUT ;
		USE SIGNAL ;
		PORT
			LAYER metal1 ;
			RECT 16.633 16.633 16.633 16.633 ;
			END
		END OP28
	PIN OP29
		DIRECTION OUTPUT ;
		USE SIGNAL ;
		PORT
			LAYER metal1 ;
			RECT 16.633 16.633 16.633 16.633 ;
			END
		END OP29
	PIN OP30
		DIRECTION OUTPUT ;
		USE SIGNAL ;
		PORT
			LAYER metal1 ;
			RECT 16.633 16.633 16.633 16.633 ;
			END
		END OP30
	PIN OP31
		DIRECTION OUTPUT ;
		USE SIGNAL ;
		PORT
			LAYER metal1 ;
			RECT 16.633 16.633 16.633 16.633 ;
			END
		END OP31
	PIN OP32
		DIRECTION OUTPUT ;
		USE SIGNAL ;
		PORT
			LAYER metal1 ;
			RECT 16.633 16.633 16.633 16.633 ;
			END
		END OP32
	PIN OP33
		DIRECTION OUTPUT ;
		USE SIGNAL ;
		PORT
			LAYER metal1 ;
			RECT 16.633 16.633 16.633 16.633 ;
			END
		END OP33
	PIN OP34
		DIRECTION OUTPUT ;
		USE SIGNAL ;
		PORT
			LAYER metal1 ;
			RECT 16.633 16.633 16.633 16.633 ;
			END
		END OP34
	PIN OP35
		DIRECTION OUTPUT ;
		USE SIGNAL ;
		PORT
			LAYER metal1 ;
			RECT 16.633 16.633 16.633 16.633 ;
			END
		END OP35
	PIN OP36
		DIRECTION OUTPUT ;
		USE SIGNAL ;
		PORT
			LAYER metal1 ;
			RECT 16.633 16.633 16.633 16.633 ;
			END
		END OP36
	PIN OP37
		DIRECTION OUTPUT ;
		USE SIGNAL ;
		PORT
			LAYER metal1 ;
			RECT 16.633 16.633 16.633 16.633 ;
			END
		END OP37
	PIN OP38
		DIRECTION OUTPUT ;
		USE SIGNAL ;
		PORT
			LAYER metal1 ;
			RECT 16.633 16.633 16.633 16.633 ;
			END
		END OP38
	PIN OP39
		DIRECTION OUTPUT ;
		USE SIGNAL ;
		PORT
			LAYER metal1 ;
			RECT 16.633 16.633 16.633 16.633 ;
			END
		END OP39
	PIN OP40
		DIRECTION OUTPUT ;
		USE SIGNAL ;
		PORT
			LAYER metal1 ;
			RECT 16.633 16.633 16.633 16.633 ;
			END
		END OP40
	PIN OP41
		DIRECTION OUTPUT ;
		USE SIGNAL ;
		PORT
			LAYER metal1 ;
			RECT 16.633 16.633 16.633 16.633 ;
			END
		END OP41
	PIN OP42
		DIRECTION OUTPUT ;
		USE SIGNAL ;
		PORT
			LAYER metal1 ;
			RECT 16.633 16.633 16.633 16.633 ;
			END
		END OP42
	PIN OP43
		DIRECTION OUTPUT ;
		USE SIGNAL ;
		PORT
			LAYER metal1 ;
			RECT 16.633 16.633 16.633 16.633 ;
			END
		END OP43
	PIN OP44
		DIRECTION OUTPUT ;
		USE SIGNAL ;
		PORT
			LAYER metal1 ;
			RECT 16.633 16.633 16.633 16.633 ;
			END
		END OP44
	PIN OP45
		DIRECTION OUTPUT ;
		USE SIGNAL ;
		PORT
			LAYER metal1 ;
			RECT 16.633 16.633 16.633 16.633 ;
			END
		END OP45
	PIN OP46
		DIRECTION OUTPUT ;
		USE SIGNAL ;
		PORT
			LAYER metal1 ;
			RECT 16.633 16.633 16.633 16.633 ;
			END
		END OP46
	PIN OP47
		DIRECTION OUTPUT ;
		USE SIGNAL ;
		PORT
			LAYER metal1 ;
			RECT 16.633 16.633 16.633 16.633 ;
			END
		END OP47
	PIN OP48
		DIRECTION OUTPUT ;
		USE SIGNAL ;
		PORT
			LAYER metal1 ;
			RECT 16.633 16.633 16.633 16.633 ;
			END
		END OP48
	PIN OP49
		DIRECTION OUTPUT ;
		USE SIGNAL ;
		PORT
			LAYER metal1 ;
			RECT 16.633 16.633 16.633 16.633 ;
			END
		END OP49
	PIN OP50
		DIRECTION OUTPUT ;
		USE SIGNAL ;
		PORT
			LAYER metal1 ;
			RECT 16.633 16.633 16.633 16.633 ;
			END
		END OP50
	PIN OP51
		DIRECTION OUTPUT ;
		USE SIGNAL ;
		PORT
			LAYER metal1 ;
			RECT 16.633 16.633 16.633 16.633 ;
			END
		END OP51
	PIN OP52
		DIRECTION OUTPUT ;
		USE SIGNAL ;
		PORT
			LAYER metal1 ;
			RECT 16.633 16.633 16.633 16.633 ;
			END
		END OP52
	PIN OP53
		DIRECTION OUTPUT ;
		USE SIGNAL ;
		PORT
			LAYER metal1 ;
			RECT 16.633 16.633 16.633 16.633 ;
			END
		END OP53
	PIN OP54
		DIRECTION OUTPUT ;
		USE SIGNAL ;
		PORT
			LAYER metal1 ;
			RECT 16.633 16.633 16.633 16.633 ;
			END
		END OP54
	PIN OP55
		DIRECTION OUTPUT ;
		USE SIGNAL ;
		PORT
			LAYER metal1 ;
			RECT 16.633 16.633 16.633 16.633 ;
			END
		END OP55
	PIN OP56
		DIRECTION OUTPUT ;
		USE SIGNAL ;
		PORT
			LAYER metal1 ;
			RECT 16.633 16.633 16.633 16.633 ;
			END
		END OP56
	PIN OP57
		DIRECTION OUTPUT ;
		USE SIGNAL ;
		PORT
			LAYER metal1 ;
			RECT 16.633 16.633 16.633 16.633 ;
			END
		END OP57
	PIN OP58
		DIRECTION OUTPUT ;
		USE SIGNAL ;
		PORT
			LAYER metal1 ;
			RECT 16.633 16.633 16.633 16.633 ;
			END
		END OP58
	PIN OP59
		DIRECTION OUTPUT ;
		USE SIGNAL ;
		PORT
			LAYER metal1 ;
			RECT 16.633 16.633 16.633 16.633 ;
			END
		END OP59
	PIN OP60
		DIRECTION OUTPUT ;
		USE SIGNAL ;
		PORT
			LAYER metal1 ;
			RECT 16.633 16.633 16.633 16.633 ;
			END
		END OP60
	PIN OP61
		DIRECTION OUTPUT ;
		USE SIGNAL ;
		PORT
			LAYER metal1 ;
			RECT 16.633 16.633 16.633 16.633 ;
			END
		END OP61
	PIN OP62
		DIRECTION OUTPUT ;
		USE SIGNAL ;
		PORT
			LAYER metal1 ;
			RECT 16.633 16.633 16.633 16.633 ;
			END
		END OP62
	PIN IP0
		DIRECTION INPUT ;
		USE SIGNAL ;
		PORT
			LAYER metal1 ;
			RECT 16.633 16.633 16.633 16.633 ;
			END
		END IP0
	PIN IP1
		DIRECTION INPUT ;
		USE SIGNAL ;
		PORT
			LAYER metal1 ;
			RECT 16.633 16.633 16.633 16.633 ;
			END
		END IP1
	PIN IP2
		DIRECTION INPUT ;
		USE SIGNAL ;
		PORT
			LAYER metal1 ;
			RECT 16.633 16.633 16.633 16.633 ;
			END
		END IP2
	PIN IP3
		DIRECTION INPUT ;
		USE SIGNAL ;
		PORT
			LAYER metal1 ;
			RECT 16.633 16.633 16.633 16.633 ;
			END
		END IP3
	PIN IP4
		DIRECTION INPUT ;
		USE SIGNAL ;
		PORT
			LAYER metal1 ;
			RECT 16.633 16.633 16.633 16.633 ;
			END
		END IP4
	PIN IP5
		DIRECTION INPUT ;
		USE SIGNAL ;
		PORT
			LAYER metal1 ;
			RECT 16.633 16.633 16.633 16.633 ;
			END
		END IP5
	PIN IP6
		DIRECTION INPUT ;
		USE SIGNAL ;
		PORT
			LAYER metal1 ;
			RECT 16.633 16.633 16.633 16.633 ;
			END
		END IP6
	PIN IP7
		DIRECTION INPUT ;
		USE SIGNAL ;
		PORT
			LAYER metal1 ;
			RECT 16.633 16.633 16.633 16.633 ;
			END
		END IP7
	PIN IP8
		DIRECTION INPUT ;
		USE SIGNAL ;
		PORT
			LAYER metal1 ;
			RECT 16.633 16.633 16.633 16.633 ;
			END
		END IP8
	PIN IP9
		DIRECTION INPUT ;
		USE SIGNAL ;
		PORT
			LAYER metal1 ;
			RECT 16.633 16.633 16.633 16.633 ;
			END
		END IP9
	PIN IP10
		DIRECTION INPUT ;
		USE SIGNAL ;
		PORT
			LAYER metal1 ;
			RECT 16.633 16.633 16.633 16.633 ;
			END
		END IP10
	PIN IP11
		DIRECTION INPUT ;
		USE SIGNAL ;
		PORT
			LAYER metal1 ;
			RECT 16.633 16.633 16.633 16.633 ;
			END
		END IP11
	PIN IP12
		DIRECTION INPUT ;
		USE SIGNAL ;
		PORT
			LAYER metal1 ;
			RECT 16.633 16.633 16.633 16.633 ;
			END
		END IP12
	PIN IP13
		DIRECTION INPUT ;
		USE SIGNAL ;
		PORT
			LAYER metal1 ;
			RECT 16.633 16.633 16.633 16.633 ;
			END
		END IP13
	PIN IP14
		DIRECTION INPUT ;
		USE SIGNAL ;
		PORT
			LAYER metal1 ;
			RECT 16.633 16.633 16.633 16.633 ;
			END
		END IP14
END cluster_3
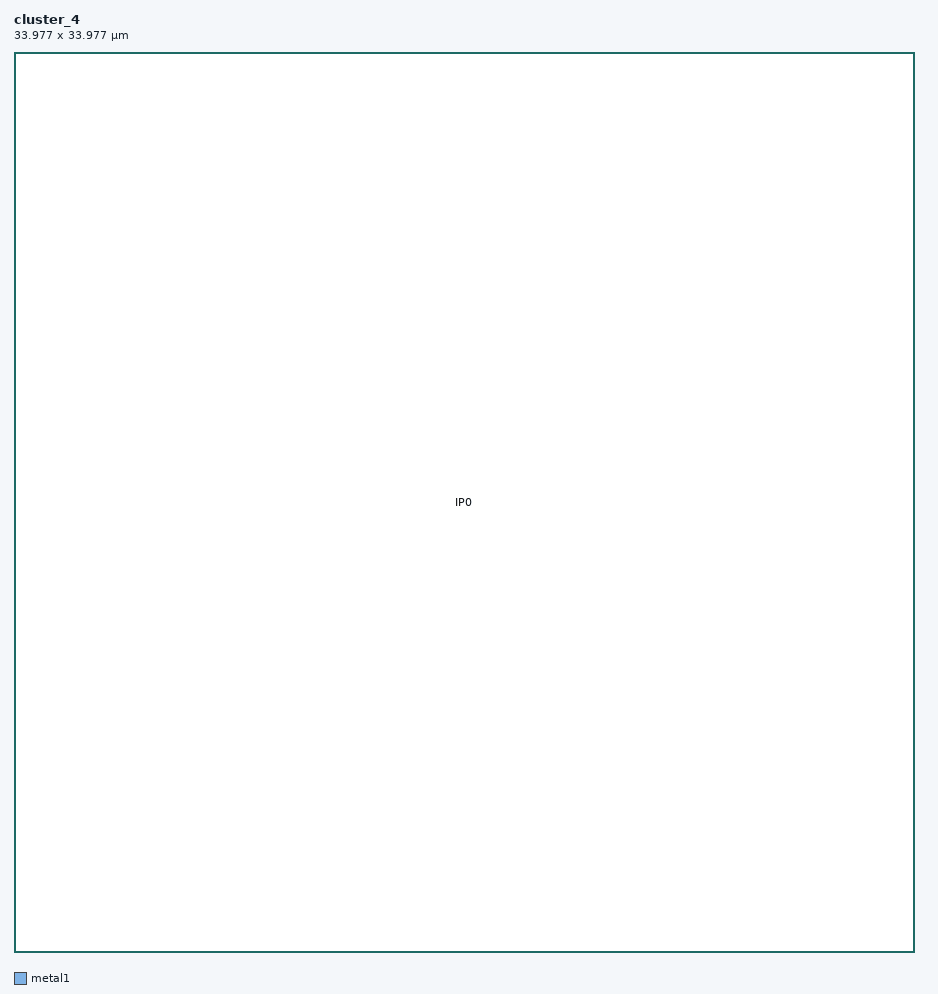
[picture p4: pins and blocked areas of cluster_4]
MACRO cluster_4
	CLASS BLOCK ;
	ORIGIN 0 0 ;
	FOREIGN cluster_4 0 0 ;
	SIZE 33.977 BY 33.977 ;
	SYMMETRY X Y ;
	PIN OP0
		DIRECTION OUTPUT ;
		USE SIGNAL ;
		PORT
			LAYER metal1 ;
			RECT 16.988 16.988 16.988 16.988 ;
			END
		END OP0
	PIN OP1
		DIRECTION OUTPUT ;
		USE SIGNAL ;
		PORT
			LAYER metal1 ;
			RECT 16.988 16.988 16.988 16.988 ;
			END
		END OP1
	PIN OP2
		DIRECTION OUTPUT ;
		USE SIGNAL ;
		PORT
			LAYER metal1 ;
			RECT 16.988 16.988 16.988 16.988 ;
			END
		END OP2
	PIN OP3
		DIRECTION OUTPUT ;
		USE SIGNAL ;
		PORT
			LAYER metal1 ;
			RECT 16.988 16.988 16.988 16.988 ;
			END
		END OP3
	PIN OP4
		DIRECTION OUTPUT ;
		USE SIGNAL ;
		PORT
			LAYER metal1 ;
			RECT 16.988 16.988 16.988 16.988 ;
			END
		END OP4
	PIN OP5
		DIRECTION OUTPUT ;
		USE SIGNAL ;
		PORT
			LAYER metal1 ;
			RECT 16.988 16.988 16.988 16.988 ;
			END
		END OP5
	PIN OP6
		DIRECTION OUTPUT ;
		USE SIGNAL ;
		PORT
			LAYER metal1 ;
			RECT 16.988 16.988 16.988 16.988 ;
			END
		END OP6
	PIN OP7
		DIRECTION OUTPUT ;
		USE SIGNAL ;
		PORT
			LAYER metal1 ;
			RECT 16.988 16.988 16.988 16.988 ;
			END
		END OP7
	PIN OP8
		DIRECTION OUTPUT ;
		USE SIGNAL ;
		PORT
			LAYER metal1 ;
			RECT 16.988 16.988 16.988 16.988 ;
			END
		END OP8
	PIN OP9
		DIRECTION OUTPUT ;
		USE SIGNAL ;
		PORT
			LAYER metal1 ;
			RECT 16.988 16.988 16.988 16.988 ;
			END
		END OP9
	PIN OP10
		DIRECTION OUTPUT ;
		USE SIGNAL ;
		PORT
			LAYER metal1 ;
			RECT 16.988 16.988 16.988 16.988 ;
			END
		END OP10
	PIN OP11
		DIRECTION OUTPUT ;
		USE SIGNAL ;
		PORT
			LAYER metal1 ;
			RECT 16.988 16.988 16.988 16.988 ;
			END
		END OP11
	PIN OP12
		DIRECTION OUTPUT ;
		USE SIGNAL ;
		PORT
			LAYER metal1 ;
			RECT 16.988 16.988 16.988 16.988 ;
			END
		END OP12
	PIN OP13
		DIRECTION OUTPUT ;
		USE SIGNAL ;
		PORT
			LAYER metal1 ;
			RECT 16.988 16.988 16.988 16.988 ;
			END
		END OP13
	PIN OP14
		DIRECTION OUTPUT ;
		USE SIGNAL ;
		PORT
			LAYER metal1 ;
			RECT 16.988 16.988 16.988 16.988 ;
			END
		END OP14
	PIN OP15
		DIRECTION OUTPUT ;
		USE SIGNAL ;
		PORT
			LAYER metal1 ;
			RECT 16.988 16.988 16.988 16.988 ;
			END
		END OP15
	PIN OP16
		DIRECTION OUTPUT ;
		USE SIGNAL ;
		PORT
			LAYER metal1 ;
			RECT 16.988 16.988 16.988 16.988 ;
			END
		END OP16
	PIN OP17
		DIRECTION OUTPUT ;
		USE SIGNAL ;
		PORT
			LAYER metal1 ;
			RECT 16.988 16.988 16.988 16.988 ;
			END
		END OP17
	PIN OP18
		DIRECTION OUTPUT ;
		USE SIGNAL ;
		PORT
			LAYER metal1 ;
			RECT 16.988 16.988 16.988 16.988 ;
			END
		END OP18
	PIN OP19
		DIRECTION OUTPUT ;
		USE SIGNAL ;
		PORT
			LAYER metal1 ;
			RECT 16.988 16.988 16.988 16.988 ;
			END
		END OP19
	PIN OP20
		DIRECTION OUTPUT ;
		USE SIGNAL ;
		PORT
			LAYER metal1 ;
			RECT 16.988 16.988 16.988 16.988 ;
			END
		END OP20
	PIN OP21
		DIRECTION OUTPUT ;
		USE SIGNAL ;
		PORT
			LAYER metal1 ;
			RECT 16.988 16.988 16.988 16.988 ;
			END
		END OP21
	PIN OP22
		DIRECTION OUTPUT ;
		USE SIGNAL ;
		PORT
			LAYER metal1 ;
			RECT 16.988 16.988 16.988 16.988 ;
			END
		END OP22
	PIN OP23
		DIRECTION OUTPUT ;
		USE SIGNAL ;
		PORT
			LAYER metal1 ;
			RECT 16.988 16.988 16.988 16.988 ;
			END
		END OP23
	PIN OP24
		DIRECTION OUTPUT ;
		USE SIGNAL ;
		PORT
			LAYER metal1 ;
			RECT 16.988 16.988 16.988 16.988 ;
			END
		END OP24
	PIN OP25
		DIRECTION OUTPUT ;
		USE SIGNAL ;
		PORT
			LAYER metal1 ;
			RECT 16.988 16.988 16.988 16.988 ;
			END
		END OP25
	PIN OP26
		DIRECTION OUTPUT ;
		USE SIGNAL ;
		PORT
			LAYER metal1 ;
			RECT 16.988 16.988 16.988 16.988 ;
			END
		END OP26
	PIN OP27
		DIRECTION OUTPUT ;
		USE SIGNAL ;
		PORT
			LAYER metal1 ;
			RECT 16.988 16.988 16.988 16.988 ;
			END
		END OP27
	PIN OP28
		DIRECTION OUTPUT ;
		USE SIGNAL ;
		PORT
			LAYER metal1 ;
			RECT 16.988 16.988 16.988 16.988 ;
			END
		END OP28
	PIN OP29
		DIRECTION OUTPUT ;
		USE SIGNAL ;
		PORT
			LAYER metal1 ;
			RECT 16.988 16.988 16.988 16.988 ;
			END
		END OP29
	PIN OP30
		DIRECTION OUTPUT ;
		USE SIGNAL ;
		PORT
			LAYER metal1 ;
			RECT 16.988 16.988 16.988 16.988 ;
			END
		END OP30
	PIN OP31
		DIRECTION OUTPUT ;
		USE SIGNAL ;
		PORT
			LAYER metal1 ;
			RECT 16.988 16.988 16.988 16.988 ;
			END
		END OP31
	PIN OP32
		DIRECTION OUTPUT ;
		USE SIGNAL ;
		PORT
			LAYER metal1 ;
			RECT 16.988 16.988 16.988 16.988 ;
			END
		END OP32
	PIN OP33
		DIRECTION OUTPUT ;
		USE SIGNAL ;
		PORT
			LAYER metal1 ;
			RECT 16.988 16.988 16.988 16.988 ;
			END
		END OP33
	PIN OP34
		DIRECTION OUTPUT ;
		USE SIGNAL ;
		PORT
			LAYER metal1 ;
			RECT 16.988 16.988 16.988 16.988 ;
			END
		END OP34
	PIN OP35
		DIRECTION OUTPUT ;
		USE SIGNAL ;
		PORT
			LAYER metal1 ;
			RECT 16.988 16.988 16.988 16.988 ;
			END
		END OP35
	PIN OP36
		DIRECTION OUTPUT ;
		USE SIGNAL ;
		PORT
			LAYER metal1 ;
			RECT 16.988 16.988 16.988 16.988 ;
			END
		END OP36
	PIN OP37
		DIRECTION OUTPUT ;
		USE SIGNAL ;
		PORT
			LAYER metal1 ;
			RECT 16.988 16.988 16.988 16.988 ;
			END
		END OP37
	PIN OP38
		DIRECTION OUTPUT ;
		USE SIGNAL ;
		PORT
			LAYER metal1 ;
			RECT 16.988 16.988 16.988 16.988 ;
			END
		END OP38
	PIN OP39
		DIRECTION OUTPUT ;
		USE SIGNAL ;
		PORT
			LAYER metal1 ;
			RECT 16.988 16.988 16.988 16.988 ;
			END
		END OP39
	PIN OP40
		DIRECTION OUTPUT ;
		USE SIGNAL ;
		PORT
			LAYER metal1 ;
			RECT 16.988 16.988 16.988 16.988 ;
			END
		END OP40
	PIN OP41
		DIRECTION OUTPUT ;
		USE SIGNAL ;
		PORT
			LAYER metal1 ;
			RECT 16.988 16.988 16.988 16.988 ;
			END
		END OP41
	PIN OP42
		DIRECTION OUTPUT ;
		USE SIGNAL ;
		PORT
			LAYER metal1 ;
			RECT 16.988 16.988 16.988 16.988 ;
			END
		END OP42
	PIN OP43
		DIRECTION OUTPUT ;
		USE SIGNAL ;
		PORT
			LAYER metal1 ;
			RECT 16.988 16.988 16.988 16.988 ;
			END
		END OP43
	PIN OP44
		DIRECTION OUTPUT ;
		USE SIGNAL ;
		PORT
			LAYER metal1 ;
			RECT 16.988 16.988 16.988 16.988 ;
			END
		END OP44
	PIN OP45
		DIRECTION OUTPUT ;
		USE SIGNAL ;
		PORT
			LAYER metal1 ;
			RECT 16.988 16.988 16.988 16.988 ;
			END
		END OP45
	PIN OP46
		DIRECTION OUTPUT ;
		USE SIGNAL ;
		PORT
			LAYER metal1 ;
			RECT 16.988 16.988 16.988 16.988 ;
			END
		END OP46
	PIN OP47
		DIRECTION OUTPUT ;
		USE SIGNAL ;
		PORT
			LAYER metal1 ;
			RECT 16.988 16.988 16.988 16.988 ;
			END
		END OP47
	PIN OP48
		DIRECTION OUTPUT ;
		USE SIGNAL ;
		PORT
			LAYER metal1 ;
			RECT 16.988 16.988 16.988 16.988 ;
			END
		END OP48
	PIN OP49
		DIRECTION OUTPUT ;
		USE SIGNAL ;
		PORT
			LAYER metal1 ;
			RECT 16.988 16.988 16.988 16.988 ;
			END
		END OP49
	PIN OP50
		DIRECTION OUTPUT ;
		USE SIGNAL ;
		PORT
			LAYER metal1 ;
			RECT 16.988 16.988 16.988 16.988 ;
			END
		END OP50
	PIN OP51
		DIRECTION OUTPUT ;
		USE SIGNAL ;
		PORT
			LAYER metal1 ;
			RECT 16.988 16.988 16.988 16.988 ;
			END
		END OP51
	PIN OP52
		DIRECTION OUTPUT ;
		USE SIGNAL ;
		PORT
			LAYER metal1 ;
			RECT 16.988 16.988 16.988 16.988 ;
			END
		END OP52
	PIN OP53
		DIRECTION OUTPUT ;
		USE SIGNAL ;
		PORT
			LAYER metal1 ;
			RECT 16.988 16.988 16.988 16.988 ;
			END
		END OP53
	PIN OP54
		DIRECTION OUTPUT ;
		USE SIGNAL ;
		PORT
			LAYER metal1 ;
			RECT 16.988 16.988 16.988 16.988 ;
			END
		END OP54
	PIN OP55
		DIRECTION OUTPUT ;
		USE SIGNAL ;
		PORT
			LAYER metal1 ;
			RECT 16.988 16.988 16.988 16.988 ;
			END
		END OP55
	PIN OP56
		DIRECTION OUTPUT ;
		USE SIGNAL ;
		PORT
			LAYER metal1 ;
			RECT 16.988 16.988 16.988 16.988 ;
			END
		END OP56
	PIN OP57
		DIRECTION OUTPUT ;
		USE SIGNAL ;
		PORT
			LAYER metal1 ;
			RECT 16.988 16.988 16.988 16.988 ;
			END
		END OP57
	PIN OP58
		DIRECTION OUTPUT ;
		USE SIGNAL ;
		PORT
			LAYER metal1 ;
			RECT 16.988 16.988 16.988 16.988 ;
			END
		END OP58
	PIN OP59
		DIRECTION OUTPUT ;
		USE SIGNAL ;
		PORT
			LAYER metal1 ;
			RECT 16.988 16.988 16.988 16.988 ;
			END
		END OP59
	PIN OP60
		DIRECTION OUTPUT ;
		USE SIGNAL ;
		PORT
			LAYER metal1 ;
			RECT 16.988 16.988 16.988 16.988 ;
			END
		END OP60
	PIN OP61
		DIRECTION OUTPUT ;
		USE SIGNAL ;
		PORT
			LAYER metal1 ;
			RECT 16.988 16.988 16.988 16.988 ;
			END
		END OP61
	PIN OP62
		DIRECTION OUTPUT ;
		USE SIGNAL ;
		PORT
			LAYER metal1 ;
			RECT 16.988 16.988 16.988 16.988 ;
			END
		END OP62
	PIN OP63
		DIRECTION OUTPUT ;
		USE SIGNAL ;
		PORT
			LAYER metal1 ;
			RECT 16.988 16.988 16.988 16.988 ;
			END
		END OP63
	PIN OP64
		DIRECTION OUTPUT ;
		USE SIGNAL ;
		PORT
			LAYER metal1 ;
			RECT 16.988 16.988 16.988 16.988 ;
			END
		END OP64
	PIN OP65
		DIRECTION OUTPUT ;
		USE SIGNAL ;
		PORT
			LAYER metal1 ;
			RECT 16.988 16.988 16.988 16.988 ;
			END
		END OP65
	PIN OP66
		DIRECTION OUTPUT ;
		USE SIGNAL ;
		PORT
			LAYER metal1 ;
			RECT 16.988 16.988 16.988 16.988 ;
			END
		END OP66
	PIN OP67
		DIRECTION OUTPUT ;
		USE SIGNAL ;
		PORT
			LAYER metal1 ;
			RECT 16.988 16.988 16.988 16.988 ;
			END
		END OP67
	PIN OP68
		DIRECTION OUTPUT ;
		USE SIGNAL ;
		PORT
			LAYER metal1 ;
			RECT 16.988 16.988 16.988 16.988 ;
			END
		END OP68
	PIN IP0
		DIRECTION INPUT ;
		USE SIGNAL ;
		PORT
			LAYER metal1 ;
			RECT 16.988 16.988 16.988 16.988 ;
			END
		END IP0
	PIN IP1
		DIRECTION INPUT ;
		USE SIGNAL ;
		PORT
			LAYER metal1 ;
			RECT 16.988 16.988 16.988 16.988 ;
			END
		END IP1
	PIN IP2
		DIRECTION INPUT ;
		USE SIGNAL ;
		PORT
			LAYER metal1 ;
			RECT 16.988 16.988 16.988 16.988 ;
			END
		END IP2
	PIN IP3
		DIRECTION INPUT ;
		USE SIGNAL ;
		PORT
			LAYER metal1 ;
			RECT 16.988 16.988 16.988 16.988 ;
			END
		END IP3
	PIN IP4
		DIRECTION INPUT ;
		USE SIGNAL ;
		PORT
			LAYER metal1 ;
			RECT 16.988 16.988 16.988 16.988 ;
			END
		END IP4
	PIN IP5
		DIRECTION INPUT ;
		USE SIGNAL ;
		PORT
			LAYER metal1 ;
			RECT 16.988 16.988 16.988 16.988 ;
			END
		END IP5
	PIN IP6
		DIRECTION INPUT ;
		USE SIGNAL ;
		PORT
			LAYER metal1 ;
			RECT 16.988 16.988 16.988 16.988 ;
			END
		END IP6
	PIN IP7
		DIRECTION INPUT ;
		USE SIGNAL ;
		PORT
			LAYER metal1 ;
			RECT 16.988 16.988 16.988 16.988 ;
			END
		END IP7
	PIN IP8
		DIRECTION INPUT ;
		USE SIGNAL ;
		PORT
			LAYER metal1 ;
			RECT 16.988 16.988 16.988 16.988 ;
			END
		END IP8
	PIN IP9
		DIRECTION INPUT ;
		USE SIGNAL ;
		PORT
			LAYER metal1 ;
			RECT 16.988 16.988 16.988 16.988 ;
			END
		END IP9
	PIN IP10
		DIRECTION INPUT ;
		USE SIGNAL ;
		PORT
			LAYER metal1 ;
			RECT 16.988 16.988 16.988 16.988 ;
			END
		END IP10
	PIN IP11
		DIRECTION INPUT ;
		USE SIGNAL ;
		PORT
			LAYER metal1 ;
			RECT 16.988 16.988 16.988 16.988 ;
			END
		END IP11
	PIN IP12
		DIRECTION INPUT ;
		USE SIGNAL ;
		PORT
			LAYER metal1 ;
			RECT 16.988 16.988 16.988 16.988 ;
			END
		END IP12
	PIN IP13
		DIRECTION INPUT ;
		USE SIGNAL ;
		PORT
			LAYER metal1 ;
			RECT 16.988 16.988 16.988 16.988 ;
			END
		END IP13
	PIN IP14
		DIRECTION INPUT ;
		USE SIGNAL ;
		PORT
			LAYER metal1 ;
			RECT 16.988 16.988 16.988 16.988 ;
			END
		END IP14
	PIN IP15
		DIRECTION INPUT ;
		USE SIGNAL ;
		PORT
			LAYER metal1 ;
			RECT 16.988 16.988 16.988 16.988 ;
			END
		END IP15
	PIN IP16
		DIRECTION INPUT ;
		USE SIGNAL ;
		PORT
			LAYER metal1 ;
			RECT 16.988 16.988 16.988 16.988 ;
			END
		END IP16
	PIN IP17
		DIRECTION INPUT ;
		USE SIGNAL ;
		PORT
			LAYER metal1 ;
			RECT 16.988 16.988 16.988 16.988 ;
			END
		END IP17
	PIN IP18
		DIRECTION INPUT ;
		USE SIGNAL ;
		PORT
			LAYER metal1 ;
			RECT 16.988 16.988 16.988 16.988 ;
			END
		END IP18
	PIN IP19
		DIRECTION INPUT ;
		USE SIGNAL ;
		PORT
			LAYER metal1 ;
			RECT 16.988 16.988 16.988 16.988 ;
			END
		END IP19
END cluster_4
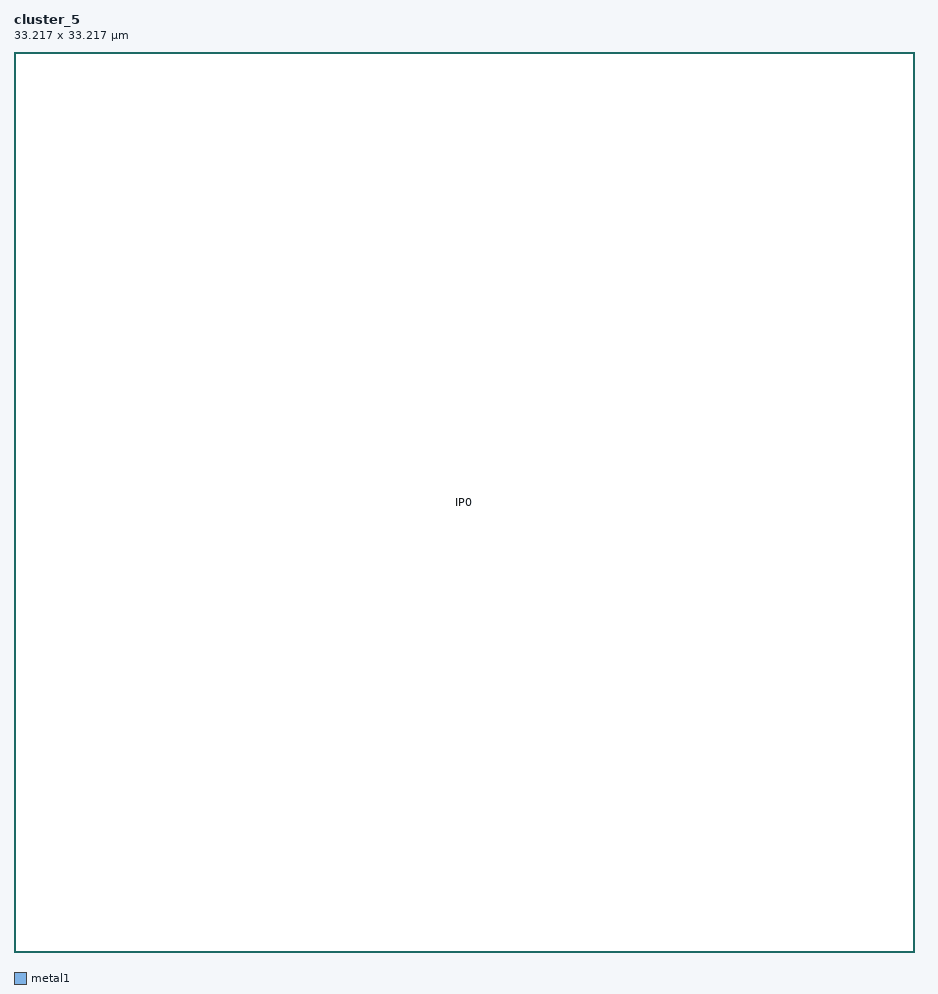
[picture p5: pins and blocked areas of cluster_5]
MACRO cluster_5
	CLASS BLOCK ;
	ORIGIN 0 0 ;
	FOREIGN cluster_5 0 0 ;
	SIZE 33.217 BY 33.217 ;
	SYMMETRY X Y ;
	PIN OP0
		DIRECTION OUTPUT ;
		USE SIGNAL ;
		PORT
			LAYER metal1 ;
			RECT 16.608 16.608 16.608 16.608 ;
			END
		END OP0
	PIN OP1
		DIRECTION OUTPUT ;
		USE SIGNAL ;
		PORT
			LAYER metal1 ;
			RECT 16.608 16.608 16.608 16.608 ;
			END
		END OP1
	PIN OP2
		DIRECTION OUTPUT ;
		USE SIGNAL ;
		PORT
			LAYER metal1 ;
			RECT 16.608 16.608 16.608 16.608 ;
			END
		END OP2
	PIN OP3
		DIRECTION OUTPUT ;
		USE SIGNAL ;
		PORT
			LAYER metal1 ;
			RECT 16.608 16.608 16.608 16.608 ;
			END
		END OP3
	PIN OP4
		DIRECTION OUTPUT ;
		USE SIGNAL ;
		PORT
			LAYER metal1 ;
			RECT 16.608 16.608 16.608 16.608 ;
			END
		END OP4
	PIN OP5
		DIRECTION OUTPUT ;
		USE SIGNAL ;
		PORT
			LAYER metal1 ;
			RECT 16.608 16.608 16.608 16.608 ;
			END
		END OP5
	PIN OP6
		DIRECTION OUTPUT ;
		USE SIGNAL ;
		PORT
			LAYER metal1 ;
			RECT 16.608 16.608 16.608 16.608 ;
			END
		END OP6
	PIN OP7
		DIRECTION OUTPUT ;
		USE SIGNAL ;
		PORT
			LAYER metal1 ;
			RECT 16.608 16.608 16.608 16.608 ;
			END
		END OP7
	PIN OP8
		DIRECTION OUTPUT ;
		USE SIGNAL ;
		PORT
			LAYER metal1 ;
			RECT 16.608 16.608 16.608 16.608 ;
			END
		END OP8
	PIN OP9
		DIRECTION OUTPUT ;
		USE SIGNAL ;
		PORT
			LAYER metal1 ;
			RECT 16.608 16.608 16.608 16.608 ;
			END
		END OP9
	PIN OP10
		DIRECTION OUTPUT ;
		USE SIGNAL ;
		PORT
			LAYER metal1 ;
			RECT 16.608 16.608 16.608 16.608 ;
			END
		END OP10
	PIN OP11
		DIRECTION OUTPUT ;
		USE SIGNAL ;
		PORT
			LAYER metal1 ;
			RECT 16.608 16.608 16.608 16.608 ;
			END
		END OP11
	PIN OP12
		DIRECTION OUTPUT ;
		USE SIGNAL ;
		PORT
			LAYER metal1 ;
			RECT 16.608 16.608 16.608 16.608 ;
			END
		END OP12
	PIN OP13
		DIRECTION OUTPUT ;
		USE SIGNAL ;
		PORT
			LAYER metal1 ;
			RECT 16.608 16.608 16.608 16.608 ;
			END
		END OP13
	PIN OP14
		DIRECTION OUTPUT ;
		USE SIGNAL ;
		PORT
			LAYER metal1 ;
			RECT 16.608 16.608 16.608 16.608 ;
			END
		END OP14
	PIN OP15
		DIRECTION OUTPUT ;
		USE SIGNAL ;
		PORT
			LAYER metal1 ;
			RECT 16.608 16.608 16.608 16.608 ;
			END
		END OP15
	PIN OP16
		DIRECTION OUTPUT ;
		USE SIGNAL ;
		PORT
			LAYER metal1 ;
			RECT 16.608 16.608 16.608 16.608 ;
			END
		END OP16
	PIN OP17
		DIRECTION OUTPUT ;
		USE SIGNAL ;
		PORT
			LAYER metal1 ;
			RECT 16.608 16.608 16.608 16.608 ;
			END
		END OP17
	PIN OP18
		DIRECTION OUTPUT ;
		USE SIGNAL ;
		PORT
			LAYER metal1 ;
			RECT 16.608 16.608 16.608 16.608 ;
			END
		END OP18
	PIN OP19
		DIRECTION OUTPUT ;
		USE SIGNAL ;
		PORT
			LAYER metal1 ;
			RECT 16.608 16.608 16.608 16.608 ;
			END
		END OP19
	PIN OP20
		DIRECTION OUTPUT ;
		USE SIGNAL ;
		PORT
			LAYER metal1 ;
			RECT 16.608 16.608 16.608 16.608 ;
			END
		END OP20
	PIN OP21
		DIRECTION OUTPUT ;
		USE SIGNAL ;
		PORT
			LAYER metal1 ;
			RECT 16.608 16.608 16.608 16.608 ;
			END
		END OP21
	PIN OP22
		DIRECTION OUTPUT ;
		USE SIGNAL ;
		PORT
			LAYER metal1 ;
			RECT 16.608 16.608 16.608 16.608 ;
			END
		END OP22
	PIN OP23
		DIRECTION OUTPUT ;
		USE SIGNAL ;
		PORT
			LAYER metal1 ;
			RECT 16.608 16.608 16.608 16.608 ;
			END
		END OP23
	PIN OP24
		DIRECTION OUTPUT ;
		USE SIGNAL ;
		PORT
			LAYER metal1 ;
			RECT 16.608 16.608 16.608 16.608 ;
			END
		END OP24
	PIN OP25
		DIRECTION OUTPUT ;
		USE SIGNAL ;
		PORT
			LAYER metal1 ;
			RECT 16.608 16.608 16.608 16.608 ;
			END
		END OP25
	PIN OP26
		DIRECTION OUTPUT ;
		USE SIGNAL ;
		PORT
			LAYER metal1 ;
			RECT 16.608 16.608 16.608 16.608 ;
			END
		END OP26
	PIN OP27
		DIRECTION OUTPUT ;
		USE SIGNAL ;
		PORT
			LAYER metal1 ;
			RECT 16.608 16.608 16.608 16.608 ;
			END
		END OP27
	PIN OP28
		DIRECTION OUTPUT ;
		USE SIGNAL ;
		PORT
			LAYER metal1 ;
			RECT 16.608 16.608 16.608 16.608 ;
			END
		END OP28
	PIN OP29
		DIRECTION OUTPUT ;
		USE SIGNAL ;
		PORT
			LAYER metal1 ;
			RECT 16.608 16.608 16.608 16.608 ;
			END
		END OP29
	PIN OP30
		DIRECTION OUTPUT ;
		USE SIGNAL ;
		PORT
			LAYER metal1 ;
			RECT 16.608 16.608 16.608 16.608 ;
			END
		END OP30
	PIN OP31
		DIRECTION OUTPUT ;
		USE SIGNAL ;
		PORT
			LAYER metal1 ;
			RECT 16.608 16.608 16.608 16.608 ;
			END
		END OP31
	PIN OP32
		DIRECTION OUTPUT ;
		USE SIGNAL ;
		PORT
			LAYER metal1 ;
			RECT 16.608 16.608 16.608 16.608 ;
			END
		END OP32
	PIN OP33
		DIRECTION OUTPUT ;
		USE SIGNAL ;
		PORT
			LAYER metal1 ;
			RECT 16.608 16.608 16.608 16.608 ;
			END
		END OP33
	PIN OP34
		DIRECTION OUTPUT ;
		USE SIGNAL ;
		PORT
			LAYER metal1 ;
			RECT 16.608 16.608 16.608 16.608 ;
			END
		END OP34
	PIN OP35
		DIRECTION OUTPUT ;
		USE SIGNAL ;
		PORT
			LAYER metal1 ;
			RECT 16.608 16.608 16.608 16.608 ;
			END
		END OP35
	PIN OP36
		DIRECTION OUTPUT ;
		USE SIGNAL ;
		PORT
			LAYER metal1 ;
			RECT 16.608 16.608 16.608 16.608 ;
			END
		END OP36
	PIN OP37
		DIRECTION OUTPUT ;
		USE SIGNAL ;
		PORT
			LAYER metal1 ;
			RECT 16.608 16.608 16.608 16.608 ;
			END
		END OP37
	PIN OP38
		DIRECTION OUTPUT ;
		USE SIGNAL ;
		PORT
			LAYER metal1 ;
			RECT 16.608 16.608 16.608 16.608 ;
			END
		END OP38
	PIN OP39
		DIRECTION OUTPUT ;
		USE SIGNAL ;
		PORT
			LAYER metal1 ;
			RECT 16.608 16.608 16.608 16.608 ;
			END
		END OP39
	PIN OP40
		DIRECTION OUTPUT ;
		USE SIGNAL ;
		PORT
			LAYER metal1 ;
			RECT 16.608 16.608 16.608 16.608 ;
			END
		END OP40
	PIN OP41
		DIRECTION OUTPUT ;
		USE SIGNAL ;
		PORT
			LAYER metal1 ;
			RECT 16.608 16.608 16.608 16.608 ;
			END
		END OP41
	PIN OP42
		DIRECTION OUTPUT ;
		USE SIGNAL ;
		PORT
			LAYER metal1 ;
			RECT 16.608 16.608 16.608 16.608 ;
			END
		END OP42
	PIN OP43
		DIRECTION OUTPUT ;
		USE SIGNAL ;
		PORT
			LAYER metal1 ;
			RECT 16.608 16.608 16.608 16.608 ;
			END
		END OP43
	PIN OP44
		DIRECTION OUTPUT ;
		USE SIGNAL ;
		PORT
			LAYER metal1 ;
			RECT 16.608 16.608 16.608 16.608 ;
			END
		END OP44
	PIN OP45
		DIRECTION OUTPUT ;
		USE SIGNAL ;
		PORT
			LAYER metal1 ;
			RECT 16.608 16.608 16.608 16.608 ;
			END
		END OP45
	PIN OP46
		DIRECTION OUTPUT ;
		USE SIGNAL ;
		PORT
			LAYER metal1 ;
			RECT 16.608 16.608 16.608 16.608 ;
			END
		END OP46
	PIN OP47
		DIRECTION OUTPUT ;
		USE SIGNAL ;
		PORT
			LAYER metal1 ;
			RECT 16.608 16.608 16.608 16.608 ;
			END
		END OP47
	PIN OP48
		DIRECTION OUTPUT ;
		USE SIGNAL ;
		PORT
			LAYER metal1 ;
			RECT 16.608 16.608 16.608 16.608 ;
			END
		END OP48
	PIN OP49
		DIRECTION OUTPUT ;
		USE SIGNAL ;
		PORT
			LAYER metal1 ;
			RECT 16.608 16.608 16.608 16.608 ;
			END
		END OP49
	PIN OP50
		DIRECTION OUTPUT ;
		USE SIGNAL ;
		PORT
			LAYER metal1 ;
			RECT 16.608 16.608 16.608 16.608 ;
			END
		END OP50
	PIN OP51
		DIRECTION OUTPUT ;
		USE SIGNAL ;
		PORT
			LAYER metal1 ;
			RECT 16.608 16.608 16.608 16.608 ;
			END
		END OP51
	PIN OP52
		DIRECTION OUTPUT ;
		USE SIGNAL ;
		PORT
			LAYER metal1 ;
			RECT 16.608 16.608 16.608 16.608 ;
			END
		END OP52
	PIN OP53
		DIRECTION OUTPUT ;
		USE SIGNAL ;
		PORT
			LAYER metal1 ;
			RECT 16.608 16.608 16.608 16.608 ;
			END
		END OP53
	PIN OP54
		DIRECTION OUTPUT ;
		USE SIGNAL ;
		PORT
			LAYER metal1 ;
			RECT 16.608 16.608 16.608 16.608 ;
			END
		END OP54
	PIN OP55
		DIRECTION OUTPUT ;
		USE SIGNAL ;
		PORT
			LAYER metal1 ;
			RECT 16.608 16.608 16.608 16.608 ;
			END
		END OP55
	PIN IP0
		DIRECTION INPUT ;
		USE SIGNAL ;
		PORT
			LAYER metal1 ;
			RECT 16.608 16.608 16.608 16.608 ;
			END
		END IP0
	PIN IP1
		DIRECTION INPUT ;
		USE SIGNAL ;
		PORT
			LAYER metal1 ;
			RECT 16.608 16.608 16.608 16.608 ;
			END
		END IP1
	PIN IP2
		DIRECTION INPUT ;
		USE SIGNAL ;
		PORT
			LAYER metal1 ;
			RECT 16.608 16.608 16.608 16.608 ;
			END
		END IP2
	PIN IP3
		DIRECTION INPUT ;
		USE SIGNAL ;
		PORT
			LAYER metal1 ;
			RECT 16.608 16.608 16.608 16.608 ;
			END
		END IP3
	PIN IP4
		DIRECTION INPUT ;
		USE SIGNAL ;
		PORT
			LAYER metal1 ;
			RECT 16.608 16.608 16.608 16.608 ;
			END
		END IP4
	PIN IP5
		DIRECTION INPUT ;
		USE SIGNAL ;
		PORT
			LAYER metal1 ;
			RECT 16.608 16.608 16.608 16.608 ;
			END
		END IP5
	PIN IP6
		DIRECTION INPUT ;
		USE SIGNAL ;
		PORT
			LAYER metal1 ;
			RECT 16.608 16.608 16.608 16.608 ;
			END
		END IP6
	PIN IP7
		DIRECTION INPUT ;
		USE SIGNAL ;
		PORT
			LAYER metal1 ;
			RECT 16.608 16.608 16.608 16.608 ;
			END
		END IP7
	PIN IP8
		DIRECTION INPUT ;
		USE SIGNAL ;
		PORT
			LAYER metal1 ;
			RECT 16.608 16.608 16.608 16.608 ;
			END
		END IP8
	PIN IP9
		DIRECTION INPUT ;
		USE SIGNAL ;
		PORT
			LAYER metal1 ;
			RECT 16.608 16.608 16.608 16.608 ;
			END
		END IP9
	PIN IP10
		DIRECTION INPUT ;
		USE SIGNAL ;
		PORT
			LAYER metal1 ;
			RECT 16.608 16.608 16.608 16.608 ;
			END
		END IP10
	PIN IP11
		DIRECTION INPUT ;
		USE SIGNAL ;
		PORT
			LAYER metal1 ;
			RECT 16.608 16.608 16.608 16.608 ;
			END
		END IP11
	PIN IP12
		DIRECTION INPUT ;
		USE SIGNAL ;
		PORT
			LAYER metal1 ;
			RECT 16.608 16.608 16.608 16.608 ;
			END
		END IP12
	PIN IP13
		DIRECTION INPUT ;
		USE SIGNAL ;
		PORT
			LAYER metal1 ;
			RECT 16.608 16.608 16.608 16.608 ;
			END
		END IP13
	PIN IP14
		DIRECTION INPUT ;
		USE SIGNAL ;
		PORT
			LAYER metal1 ;
			RECT 16.608 16.608 16.608 16.608 ;
			END
		END IP14
	PIN IP15
		DIRECTION INPUT ;
		USE SIGNAL ;
		PORT
			LAYER metal1 ;
			RECT 16.608 16.608 16.608 16.608 ;
			END
		END IP15
END cluster_5
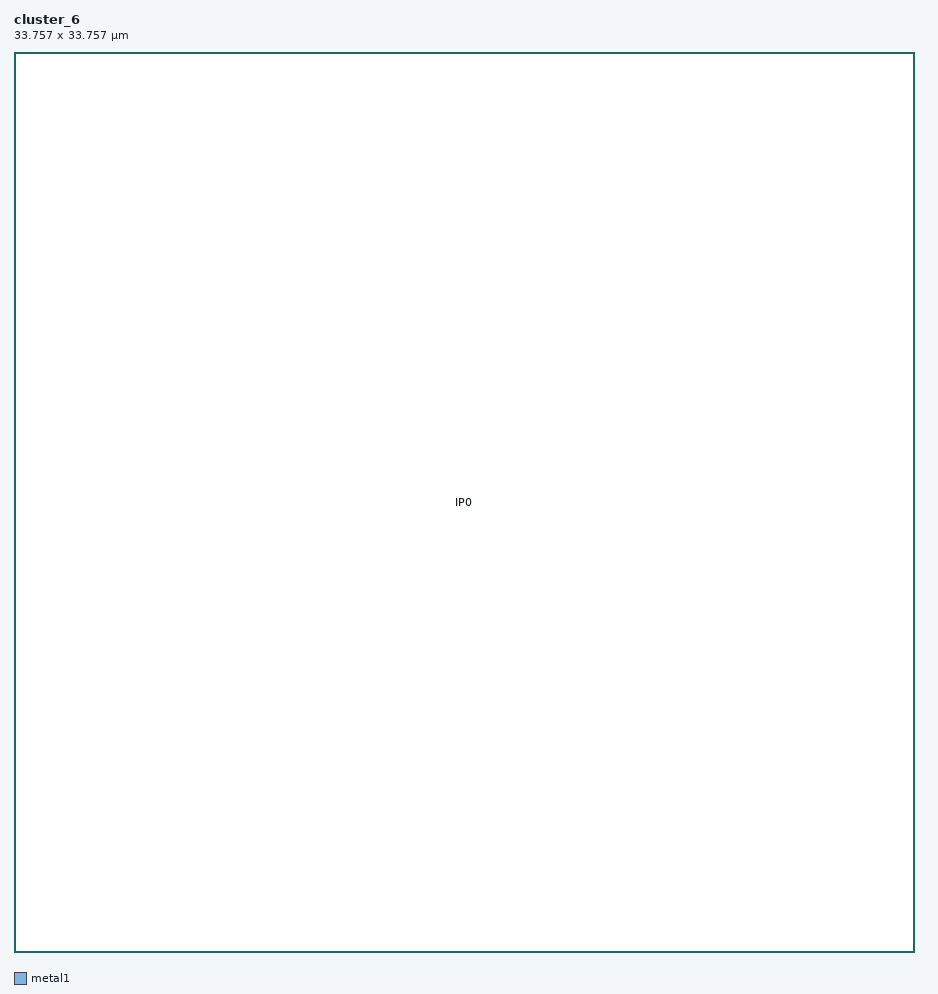
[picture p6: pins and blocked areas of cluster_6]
MACRO cluster_6
	CLASS BLOCK ;
	ORIGIN 0 0 ;
	FOREIGN cluster_6 0 0 ;
	SIZE 33.757 BY 33.757 ;
	SYMMETRY X Y ;
	PIN OP0
		DIRECTION OUTPUT ;
		USE SIGNAL ;
		PORT
			LAYER metal1 ;
			RECT 16.878 16.878 16.878 16.878 ;
			END
		END OP0
	PIN OP1
		DIRECTION OUTPUT ;
		USE SIGNAL ;
		PORT
			LAYER metal1 ;
			RECT 16.878 16.878 16.878 16.878 ;
			END
		END OP1
	PIN OP2
		DIRECTION OUTPUT ;
		USE SIGNAL ;
		PORT
			LAYER metal1 ;
			RECT 16.878 16.878 16.878 16.878 ;
			END
		END OP2
	PIN OP3
		DIRECTION OUTPUT ;
		USE SIGNAL ;
		PORT
			LAYER metal1 ;
			RECT 16.878 16.878 16.878 16.878 ;
			END
		END OP3
	PIN OP4
		DIRECTION OUTPUT ;
		USE SIGNAL ;
		PORT
			LAYER metal1 ;
			RECT 16.878 16.878 16.878 16.878 ;
			END
		END OP4
	PIN OP5
		DIRECTION OUTPUT ;
		USE SIGNAL ;
		PORT
			LAYER metal1 ;
			RECT 16.878 16.878 16.878 16.878 ;
			END
		END OP5
	PIN OP6
		DIRECTION OUTPUT ;
		USE SIGNAL ;
		PORT
			LAYER metal1 ;
			RECT 16.878 16.878 16.878 16.878 ;
			END
		END OP6
	PIN OP7
		DIRECTION OUTPUT ;
		USE SIGNAL ;
		PORT
			LAYER metal1 ;
			RECT 16.878 16.878 16.878 16.878 ;
			END
		END OP7
	PIN OP8
		DIRECTION OUTPUT ;
		USE SIGNAL ;
		PORT
			LAYER metal1 ;
			RECT 16.878 16.878 16.878 16.878 ;
			END
		END OP8
	PIN OP9
		DIRECTION OUTPUT ;
		USE SIGNAL ;
		PORT
			LAYER metal1 ;
			RECT 16.878 16.878 16.878 16.878 ;
			END
		END OP9
	PIN OP10
		DIRECTION OUTPUT ;
		USE SIGNAL ;
		PORT
			LAYER metal1 ;
			RECT 16.878 16.878 16.878 16.878 ;
			END
		END OP10
	PIN OP11
		DIRECTION OUTPUT ;
		USE SIGNAL ;
		PORT
			LAYER metal1 ;
			RECT 16.878 16.878 16.878 16.878 ;
			END
		END OP11
	PIN OP12
		DIRECTION OUTPUT ;
		USE SIGNAL ;
		PORT
			LAYER metal1 ;
			RECT 16.878 16.878 16.878 16.878 ;
			END
		END OP12
	PIN OP13
		DIRECTION OUTPUT ;
		USE SIGNAL ;
		PORT
			LAYER metal1 ;
			RECT 16.878 16.878 16.878 16.878 ;
			END
		END OP13
	PIN OP14
		DIRECTION OUTPUT ;
		USE SIGNAL ;
		PORT
			LAYER metal1 ;
			RECT 16.878 16.878 16.878 16.878 ;
			END
		END OP14
	PIN OP15
		DIRECTION OUTPUT ;
		USE SIGNAL ;
		PORT
			LAYER metal1 ;
			RECT 16.878 16.878 16.878 16.878 ;
			END
		END OP15
	PIN OP16
		DIRECTION OUTPUT ;
		USE SIGNAL ;
		PORT
			LAYER metal1 ;
			RECT 16.878 16.878 16.878 16.878 ;
			END
		END OP16
	PIN OP17
		DIRECTION OUTPUT ;
		USE SIGNAL ;
		PORT
			LAYER metal1 ;
			RECT 16.878 16.878 16.878 16.878 ;
			END
		END OP17
	PIN OP18
		DIRECTION OUTPUT ;
		USE SIGNAL ;
		PORT
			LAYER metal1 ;
			RECT 16.878 16.878 16.878 16.878 ;
			END
		END OP18
	PIN OP19
		DIRECTION OUTPUT ;
		USE SIGNAL ;
		PORT
			LAYER metal1 ;
			RECT 16.878 16.878 16.878 16.878 ;
			END
		END OP19
	PIN OP20
		DIRECTION OUTPUT ;
		USE SIGNAL ;
		PORT
			LAYER metal1 ;
			RECT 16.878 16.878 16.878 16.878 ;
			END
		END OP20
	PIN OP21
		DIRECTION OUTPUT ;
		USE SIGNAL ;
		PORT
			LAYER metal1 ;
			RECT 16.878 16.878 16.878 16.878 ;
			END
		END OP21
	PIN OP22
		DIRECTION OUTPUT ;
		USE SIGNAL ;
		PORT
			LAYER metal1 ;
			RECT 16.878 16.878 16.878 16.878 ;
			END
		END OP22
	PIN OP23
		DIRECTION OUTPUT ;
		USE SIGNAL ;
		PORT
			LAYER metal1 ;
			RECT 16.878 16.878 16.878 16.878 ;
			END
		END OP23
	PIN OP24
		DIRECTION OUTPUT ;
		USE SIGNAL ;
		PORT
			LAYER metal1 ;
			RECT 16.878 16.878 16.878 16.878 ;
			END
		END OP24
	PIN OP25
		DIRECTION OUTPUT ;
		USE SIGNAL ;
		PORT
			LAYER metal1 ;
			RECT 16.878 16.878 16.878 16.878 ;
			END
		END OP25
	PIN OP26
		DIRECTION OUTPUT ;
		USE SIGNAL ;
		PORT
			LAYER metal1 ;
			RECT 16.878 16.878 16.878 16.878 ;
			END
		END OP26
	PIN OP27
		DIRECTION OUTPUT ;
		USE SIGNAL ;
		PORT
			LAYER metal1 ;
			RECT 16.878 16.878 16.878 16.878 ;
			END
		END OP27
	PIN OP28
		DIRECTION OUTPUT ;
		USE SIGNAL ;
		PORT
			LAYER metal1 ;
			RECT 16.878 16.878 16.878 16.878 ;
			END
		END OP28
	PIN OP29
		DIRECTION OUTPUT ;
		USE SIGNAL ;
		PORT
			LAYER metal1 ;
			RECT 16.878 16.878 16.878 16.878 ;
			END
		END OP29
	PIN OP30
		DIRECTION OUTPUT ;
		USE SIGNAL ;
		PORT
			LAYER metal1 ;
			RECT 16.878 16.878 16.878 16.878 ;
			END
		END OP30
	PIN OP31
		DIRECTION OUTPUT ;
		USE SIGNAL ;
		PORT
			LAYER metal1 ;
			RECT 16.878 16.878 16.878 16.878 ;
			END
		END OP31
	PIN OP32
		DIRECTION OUTPUT ;
		USE SIGNAL ;
		PORT
			LAYER metal1 ;
			RECT 16.878 16.878 16.878 16.878 ;
			END
		END OP32
	PIN OP33
		DIRECTION OUTPUT ;
		USE SIGNAL ;
		PORT
			LAYER metal1 ;
			RECT 16.878 16.878 16.878 16.878 ;
			END
		END OP33
	PIN OP34
		DIRECTION OUTPUT ;
		USE SIGNAL ;
		PORT
			LAYER metal1 ;
			RECT 16.878 16.878 16.878 16.878 ;
			END
		END OP34
	PIN OP35
		DIRECTION OUTPUT ;
		USE SIGNAL ;
		PORT
			LAYER metal1 ;
			RECT 16.878 16.878 16.878 16.878 ;
			END
		END OP35
	PIN OP36
		DIRECTION OUTPUT ;
		USE SIGNAL ;
		PORT
			LAYER metal1 ;
			RECT 16.878 16.878 16.878 16.878 ;
			END
		END OP36
	PIN OP37
		DIRECTION OUTPUT ;
		USE SIGNAL ;
		PORT
			LAYER metal1 ;
			RECT 16.878 16.878 16.878 16.878 ;
			END
		END OP37
	PIN OP38
		DIRECTION OUTPUT ;
		USE SIGNAL ;
		PORT
			LAYER metal1 ;
			RECT 16.878 16.878 16.878 16.878 ;
			END
		END OP38
	PIN OP39
		DIRECTION OUTPUT ;
		USE SIGNAL ;
		PORT
			LAYER metal1 ;
			RECT 16.878 16.878 16.878 16.878 ;
			END
		END OP39
	PIN OP40
		DIRECTION OUTPUT ;
		USE SIGNAL ;
		PORT
			LAYER metal1 ;
			RECT 16.878 16.878 16.878 16.878 ;
			END
		END OP40
	PIN OP41
		DIRECTION OUTPUT ;
		USE SIGNAL ;
		PORT
			LAYER metal1 ;
			RECT 16.878 16.878 16.878 16.878 ;
			END
		END OP41
	PIN OP42
		DIRECTION OUTPUT ;
		USE SIGNAL ;
		PORT
			LAYER metal1 ;
			RECT 16.878 16.878 16.878 16.878 ;
			END
		END OP42
	PIN OP43
		DIRECTION OUTPUT ;
		USE SIGNAL ;
		PORT
			LAYER metal1 ;
			RECT 16.878 16.878 16.878 16.878 ;
			END
		END OP43
	PIN OP44
		DIRECTION OUTPUT ;
		USE SIGNAL ;
		PORT
			LAYER metal1 ;
			RECT 16.878 16.878 16.878 16.878 ;
			END
		END OP44
	PIN OP45
		DIRECTION OUTPUT ;
		USE SIGNAL ;
		PORT
			LAYER metal1 ;
			RECT 16.878 16.878 16.878 16.878 ;
			END
		END OP45
	PIN OP46
		DIRECTION OUTPUT ;
		USE SIGNAL ;
		PORT
			LAYER metal1 ;
			RECT 16.878 16.878 16.878 16.878 ;
			END
		END OP46
	PIN OP47
		DIRECTION OUTPUT ;
		USE SIGNAL ;
		PORT
			LAYER metal1 ;
			RECT 16.878 16.878 16.878 16.878 ;
			END
		END OP47
	PIN OP48
		DIRECTION OUTPUT ;
		USE SIGNAL ;
		PORT
			LAYER metal1 ;
			RECT 16.878 16.878 16.878 16.878 ;
			END
		END OP48
	PIN OP49
		DIRECTION OUTPUT ;
		USE SIGNAL ;
		PORT
			LAYER metal1 ;
			RECT 16.878 16.878 16.878 16.878 ;
			END
		END OP49
	PIN OP50
		DIRECTION OUTPUT ;
		USE SIGNAL ;
		PORT
			LAYER metal1 ;
			RECT 16.878 16.878 16.878 16.878 ;
			END
		END OP50
	PIN OP51
		DIRECTION OUTPUT ;
		USE SIGNAL ;
		PORT
			LAYER metal1 ;
			RECT 16.878 16.878 16.878 16.878 ;
			END
		END OP51
	PIN OP52
		DIRECTION OUTPUT ;
		USE SIGNAL ;
		PORT
			LAYER metal1 ;
			RECT 16.878 16.878 16.878 16.878 ;
			END
		END OP52
	PIN OP53
		DIRECTION OUTPUT ;
		USE SIGNAL ;
		PORT
			LAYER metal1 ;
			RECT 16.878 16.878 16.878 16.878 ;
			END
		END OP53
	PIN OP54
		DIRECTION OUTPUT ;
		USE SIGNAL ;
		PORT
			LAYER metal1 ;
			RECT 16.878 16.878 16.878 16.878 ;
			END
		END OP54
	PIN OP55
		DIRECTION OUTPUT ;
		USE SIGNAL ;
		PORT
			LAYER metal1 ;
			RECT 16.878 16.878 16.878 16.878 ;
			END
		END OP55
	PIN OP56
		DIRECTION OUTPUT ;
		USE SIGNAL ;
		PORT
			LAYER metal1 ;
			RECT 16.878 16.878 16.878 16.878 ;
			END
		END OP56
	PIN OP57
		DIRECTION OUTPUT ;
		USE SIGNAL ;
		PORT
			LAYER metal1 ;
			RECT 16.878 16.878 16.878 16.878 ;
			END
		END OP57
	PIN IP0
		DIRECTION INPUT ;
		USE SIGNAL ;
		PORT
			LAYER metal1 ;
			RECT 16.878 16.878 16.878 16.878 ;
			END
		END IP0
	PIN IP1
		DIRECTION INPUT ;
		USE SIGNAL ;
		PORT
			LAYER metal1 ;
			RECT 16.878 16.878 16.878 16.878 ;
			END
		END IP1
	PIN IP2
		DIRECTION INPUT ;
		USE SIGNAL ;
		PORT
			LAYER metal1 ;
			RECT 16.878 16.878 16.878 16.878 ;
			END
		END IP2
	PIN IP3
		DIRECTION INPUT ;
		USE SIGNAL ;
		PORT
			LAYER metal1 ;
			RECT 16.878 16.878 16.878 16.878 ;
			END
		END IP3
	PIN IP4
		DIRECTION INPUT ;
		USE SIGNAL ;
		PORT
			LAYER metal1 ;
			RECT 16.878 16.878 16.878 16.878 ;
			END
		END IP4
	PIN IP5
		DIRECTION INPUT ;
		USE SIGNAL ;
		PORT
			LAYER metal1 ;
			RECT 16.878 16.878 16.878 16.878 ;
			END
		END IP5
	PIN IP6
		DIRECTION INPUT ;
		USE SIGNAL ;
		PORT
			LAYER metal1 ;
			RECT 16.878 16.878 16.878 16.878 ;
			END
		END IP6
	PIN IP7
		DIRECTION INPUT ;
		USE SIGNAL ;
		PORT
			LAYER metal1 ;
			RECT 16.878 16.878 16.878 16.878 ;
			END
		END IP7
	PIN IP8
		DIRECTION INPUT ;
		USE SIGNAL ;
		PORT
			LAYER metal1 ;
			RECT 16.878 16.878 16.878 16.878 ;
			END
		END IP8
	PIN IP9
		DIRECTION INPUT ;
		USE SIGNAL ;
		PORT
			LAYER metal1 ;
			RECT 16.878 16.878 16.878 16.878 ;
			END
		END IP9
	PIN IP10
		DIRECTION INPUT ;
		USE SIGNAL ;
		PORT
			LAYER metal1 ;
			RECT 16.878 16.878 16.878 16.878 ;
			END
		END IP10
	PIN IP11
		DIRECTION INPUT ;
		USE SIGNAL ;
		PORT
			LAYER metal1 ;
			RECT 16.878 16.878 16.878 16.878 ;
			END
		END IP11
	PIN IP12
		DIRECTION INPUT ;
		USE SIGNAL ;
		PORT
			LAYER metal1 ;
			RECT 16.878 16.878 16.878 16.878 ;
			END
		END IP12
	PIN IP13
		DIRECTION INPUT ;
		USE SIGNAL ;
		PORT
			LAYER metal1 ;
			RECT 16.878 16.878 16.878 16.878 ;
			END
		END IP13
	PIN IP14
		DIRECTION INPUT ;
		USE SIGNAL ;
		PORT
			LAYER metal1 ;
			RECT 16.878 16.878 16.878 16.878 ;
			END
		END IP14
	PIN IP15
		DIRECTION INPUT ;
		USE SIGNAL ;
		PORT
			LAYER metal1 ;
			RECT 16.878 16.878 16.878 16.878 ;
			END
		END IP15
	PIN IP16
		DIRECTION INPUT ;
		USE SIGNAL ;
		PORT
			LAYER metal1 ;
			RECT 16.878 16.878 16.878 16.878 ;
			END
		END IP16
	PIN IP17
		DIRECTION INPUT ;
		USE SIGNAL ;
		PORT
			LAYER metal1 ;
			RECT 16.878 16.878 16.878 16.878 ;
			END
		END IP17
	PIN IP18
		DIRECTION INPUT ;
		USE SIGNAL ;
		PORT
			LAYER metal1 ;
			RECT 16.878 16.878 16.878 16.878 ;
			END
		END IP18
	PIN IP19
		DIRECTION INPUT ;
		USE SIGNAL ;
		PORT
			LAYER metal1 ;
			RECT 16.878 16.878 16.878 16.878 ;
			END
		END IP19
	PIN IP20
		DIRECTION INPUT ;
		USE SIGNAL ;
		PORT
			LAYER metal1 ;
			RECT 16.878 16.878 16.878 16.878 ;
			END
		END IP20
	PIN IP21
		DIRECTION INPUT ;
		USE SIGNAL ;
		PORT
			LAYER metal1 ;
			RECT 16.878 16.878 16.878 16.878 ;
			END
		END IP21
	PIN IP22
		DIRECTION INPUT ;
		USE SIGNAL ;
		PORT
			LAYER metal1 ;
			RECT 16.878 16.878 16.878 16.878 ;
			END
		END IP22
	PIN IP23
		DIRECTION INPUT ;
		USE SIGNAL ;
		PORT
			LAYER metal1 ;
			RECT 16.878 16.878 16.878 16.878 ;
			END
		END IP23
END cluster_6
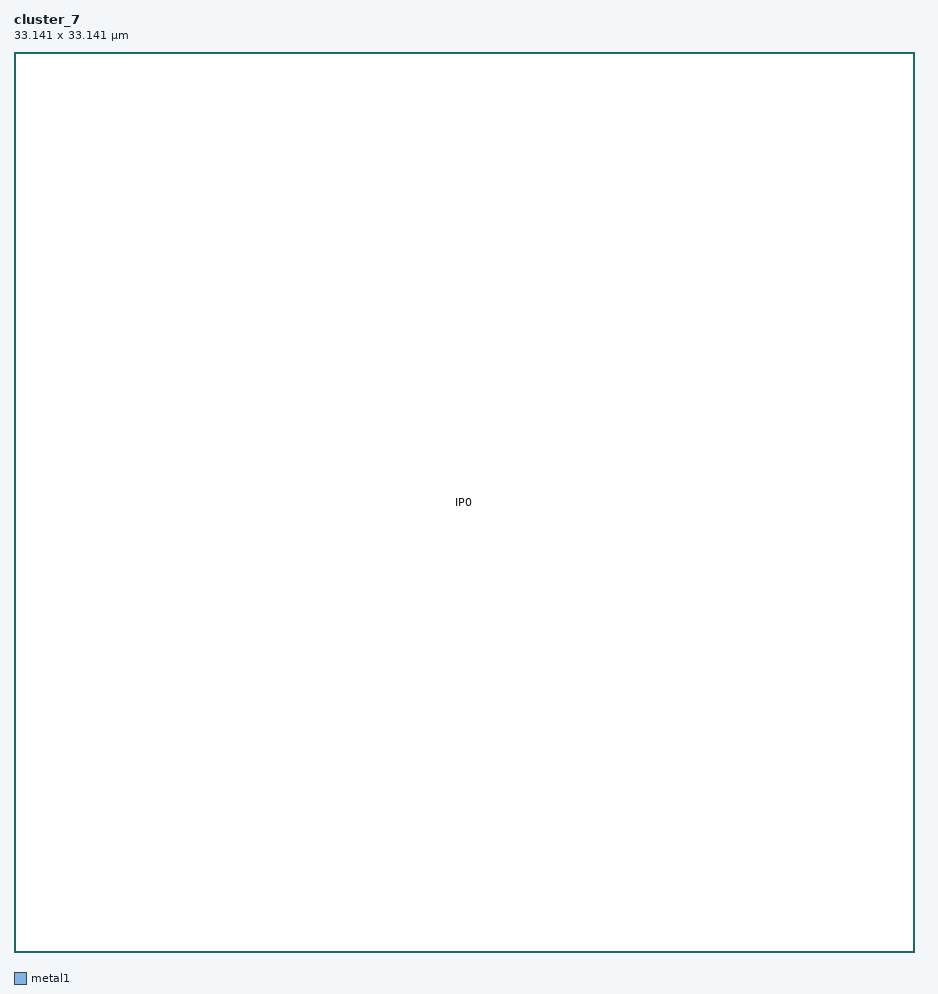
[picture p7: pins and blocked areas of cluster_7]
MACRO cluster_7
	CLASS BLOCK ;
	ORIGIN 0 0 ;
	FOREIGN cluster_7 0 0 ;
	SIZE 33.141 BY 33.141 ;
	SYMMETRY X Y ;
	PIN OP0
		DIRECTION OUTPUT ;
		USE SIGNAL ;
		PORT
			LAYER metal1 ;
			RECT 16.57 16.57 16.57 16.57 ;
			END
		END OP0
	PIN OP1
		DIRECTION OUTPUT ;
		USE SIGNAL ;
		PORT
			LAYER metal1 ;
			RECT 16.57 16.57 16.57 16.57 ;
			END
		END OP1
	PIN OP2
		DIRECTION OUTPUT ;
		USE SIGNAL ;
		PORT
			LAYER metal1 ;
			RECT 16.57 16.57 16.57 16.57 ;
			END
		END OP2
	PIN OP3
		DIRECTION OUTPUT ;
		USE SIGNAL ;
		PORT
			LAYER metal1 ;
			RECT 16.57 16.57 16.57 16.57 ;
			END
		END OP3
	PIN OP4
		DIRECTION OUTPUT ;
		USE SIGNAL ;
		PORT
			LAYER metal1 ;
			RECT 16.57 16.57 16.57 16.57 ;
			END
		END OP4
	PIN OP5
		DIRECTION OUTPUT ;
		USE SIGNAL ;
		PORT
			LAYER metal1 ;
			RECT 16.57 16.57 16.57 16.57 ;
			END
		END OP5
	PIN OP6
		DIRECTION OUTPUT ;
		USE SIGNAL ;
		PORT
			LAYER metal1 ;
			RECT 16.57 16.57 16.57 16.57 ;
			END
		END OP6
	PIN OP7
		DIRECTION OUTPUT ;
		USE SIGNAL ;
		PORT
			LAYER metal1 ;
			RECT 16.57 16.57 16.57 16.57 ;
			END
		END OP7
	PIN OP8
		DIRECTION OUTPUT ;
		USE SIGNAL ;
		PORT
			LAYER metal1 ;
			RECT 16.57 16.57 16.57 16.57 ;
			END
		END OP8
	PIN OP9
		DIRECTION OUTPUT ;
		USE SIGNAL ;
		PORT
			LAYER metal1 ;
			RECT 16.57 16.57 16.57 16.57 ;
			END
		END OP9
	PIN OP10
		DIRECTION OUTPUT ;
		USE SIGNAL ;
		PORT
			LAYER metal1 ;
			RECT 16.57 16.57 16.57 16.57 ;
			END
		END OP10
	PIN OP11
		DIRECTION OUTPUT ;
		USE SIGNAL ;
		PORT
			LAYER metal1 ;
			RECT 16.57 16.57 16.57 16.57 ;
			END
		END OP11
	PIN OP12
		DIRECTION OUTPUT ;
		USE SIGNAL ;
		PORT
			LAYER metal1 ;
			RECT 16.57 16.57 16.57 16.57 ;
			END
		END OP12
	PIN OP13
		DIRECTION OUTPUT ;
		USE SIGNAL ;
		PORT
			LAYER metal1 ;
			RECT 16.57 16.57 16.57 16.57 ;
			END
		END OP13
	PIN OP14
		DIRECTION OUTPUT ;
		USE SIGNAL ;
		PORT
			LAYER metal1 ;
			RECT 16.57 16.57 16.57 16.57 ;
			END
		END OP14
	PIN OP15
		DIRECTION OUTPUT ;
		USE SIGNAL ;
		PORT
			LAYER metal1 ;
			RECT 16.57 16.57 16.57 16.57 ;
			END
		END OP15
	PIN OP16
		DIRECTION OUTPUT ;
		USE SIGNAL ;
		PORT
			LAYER metal1 ;
			RECT 16.57 16.57 16.57 16.57 ;
			END
		END OP16
	PIN OP17
		DIRECTION OUTPUT ;
		USE SIGNAL ;
		PORT
			LAYER metal1 ;
			RECT 16.57 16.57 16.57 16.57 ;
			END
		END OP17
	PIN OP18
		DIRECTION OUTPUT ;
		USE SIGNAL ;
		PORT
			LAYER metal1 ;
			RECT 16.57 16.57 16.57 16.57 ;
			END
		END OP18
	PIN OP19
		DIRECTION OUTPUT ;
		USE SIGNAL ;
		PORT
			LAYER metal1 ;
			RECT 16.57 16.57 16.57 16.57 ;
			END
		END OP19
	PIN OP20
		DIRECTION OUTPUT ;
		USE SIGNAL ;
		PORT
			LAYER metal1 ;
			RECT 16.57 16.57 16.57 16.57 ;
			END
		END OP20
	PIN OP21
		DIRECTION OUTPUT ;
		USE SIGNAL ;
		PORT
			LAYER metal1 ;
			RECT 16.57 16.57 16.57 16.57 ;
			END
		END OP21
	PIN OP22
		DIRECTION OUTPUT ;
		USE SIGNAL ;
		PORT
			LAYER metal1 ;
			RECT 16.57 16.57 16.57 16.57 ;
			END
		END OP22
	PIN OP23
		DIRECTION OUTPUT ;
		USE SIGNAL ;
		PORT
			LAYER metal1 ;
			RECT 16.57 16.57 16.57 16.57 ;
			END
		END OP23
	PIN OP24
		DIRECTION OUTPUT ;
		USE SIGNAL ;
		PORT
			LAYER metal1 ;
			RECT 16.57 16.57 16.57 16.57 ;
			END
		END OP24
	PIN OP25
		DIRECTION OUTPUT ;
		USE SIGNAL ;
		PORT
			LAYER metal1 ;
			RECT 16.57 16.57 16.57 16.57 ;
			END
		END OP25
	PIN OP26
		DIRECTION OUTPUT ;
		USE SIGNAL ;
		PORT
			LAYER metal1 ;
			RECT 16.57 16.57 16.57 16.57 ;
			END
		END OP26
	PIN OP27
		DIRECTION OUTPUT ;
		USE SIGNAL ;
		PORT
			LAYER metal1 ;
			RECT 16.57 16.57 16.57 16.57 ;
			END
		END OP27
	PIN OP28
		DIRECTION OUTPUT ;
		USE SIGNAL ;
		PORT
			LAYER metal1 ;
			RECT 16.57 16.57 16.57 16.57 ;
			END
		END OP28
	PIN OP29
		DIRECTION OUTPUT ;
		USE SIGNAL ;
		PORT
			LAYER metal1 ;
			RECT 16.57 16.57 16.57 16.57 ;
			END
		END OP29
	PIN OP30
		DIRECTION OUTPUT ;
		USE SIGNAL ;
		PORT
			LAYER metal1 ;
			RECT 16.57 16.57 16.57 16.57 ;
			END
		END OP30
	PIN OP31
		DIRECTION OUTPUT ;
		USE SIGNAL ;
		PORT
			LAYER metal1 ;
			RECT 16.57 16.57 16.57 16.57 ;
			END
		END OP31
	PIN OP32
		DIRECTION OUTPUT ;
		USE SIGNAL ;
		PORT
			LAYER metal1 ;
			RECT 16.57 16.57 16.57 16.57 ;
			END
		END OP32
	PIN OP33
		DIRECTION OUTPUT ;
		USE SIGNAL ;
		PORT
			LAYER metal1 ;
			RECT 16.57 16.57 16.57 16.57 ;
			END
		END OP33
	PIN OP34
		DIRECTION OUTPUT ;
		USE SIGNAL ;
		PORT
			LAYER metal1 ;
			RECT 16.57 16.57 16.57 16.57 ;
			END
		END OP34
	PIN OP35
		DIRECTION OUTPUT ;
		USE SIGNAL ;
		PORT
			LAYER metal1 ;
			RECT 16.57 16.57 16.57 16.57 ;
			END
		END OP35
	PIN OP36
		DIRECTION OUTPUT ;
		USE SIGNAL ;
		PORT
			LAYER metal1 ;
			RECT 16.57 16.57 16.57 16.57 ;
			END
		END OP36
	PIN OP37
		DIRECTION OUTPUT ;
		USE SIGNAL ;
		PORT
			LAYER metal1 ;
			RECT 16.57 16.57 16.57 16.57 ;
			END
		END OP37
	PIN OP38
		DIRECTION OUTPUT ;
		USE SIGNAL ;
		PORT
			LAYER metal1 ;
			RECT 16.57 16.57 16.57 16.57 ;
			END
		END OP38
	PIN OP39
		DIRECTION OUTPUT ;
		USE SIGNAL ;
		PORT
			LAYER metal1 ;
			RECT 16.57 16.57 16.57 16.57 ;
			END
		END OP39
	PIN OP40
		DIRECTION OUTPUT ;
		USE SIGNAL ;
		PORT
			LAYER metal1 ;
			RECT 16.57 16.57 16.57 16.57 ;
			END
		END OP40
	PIN OP41
		DIRECTION OUTPUT ;
		USE SIGNAL ;
		PORT
			LAYER metal1 ;
			RECT 16.57 16.57 16.57 16.57 ;
			END
		END OP41
	PIN OP42
		DIRECTION OUTPUT ;
		USE SIGNAL ;
		PORT
			LAYER metal1 ;
			RECT 16.57 16.57 16.57 16.57 ;
			END
		END OP42
	PIN OP43
		DIRECTION OUTPUT ;
		USE SIGNAL ;
		PORT
			LAYER metal1 ;
			RECT 16.57 16.57 16.57 16.57 ;
			END
		END OP43
	PIN OP44
		DIRECTION OUTPUT ;
		USE SIGNAL ;
		PORT
			LAYER metal1 ;
			RECT 16.57 16.57 16.57 16.57 ;
			END
		END OP44
	PIN OP45
		DIRECTION OUTPUT ;
		USE SIGNAL ;
		PORT
			LAYER metal1 ;
			RECT 16.57 16.57 16.57 16.57 ;
			END
		END OP45
	PIN OP46
		DIRECTION OUTPUT ;
		USE SIGNAL ;
		PORT
			LAYER metal1 ;
			RECT 16.57 16.57 16.57 16.57 ;
			END
		END OP46
	PIN OP47
		DIRECTION OUTPUT ;
		USE SIGNAL ;
		PORT
			LAYER metal1 ;
			RECT 16.57 16.57 16.57 16.57 ;
			END
		END OP47
	PIN OP48
		DIRECTION OUTPUT ;
		USE SIGNAL ;
		PORT
			LAYER metal1 ;
			RECT 16.57 16.57 16.57 16.57 ;
			END
		END OP48
	PIN OP49
		DIRECTION OUTPUT ;
		USE SIGNAL ;
		PORT
			LAYER metal1 ;
			RECT 16.57 16.57 16.57 16.57 ;
			END
		END OP49
	PIN OP50
		DIRECTION OUTPUT ;
		USE SIGNAL ;
		PORT
			LAYER metal1 ;
			RECT 16.57 16.57 16.57 16.57 ;
			END
		END OP50
	PIN OP51
		DIRECTION OUTPUT ;
		USE SIGNAL ;
		PORT
			LAYER metal1 ;
			RECT 16.57 16.57 16.57 16.57 ;
			END
		END OP51
	PIN OP52
		DIRECTION OUTPUT ;
		USE SIGNAL ;
		PORT
			LAYER metal1 ;
			RECT 16.57 16.57 16.57 16.57 ;
			END
		END OP52
	PIN OP53
		DIRECTION OUTPUT ;
		USE SIGNAL ;
		PORT
			LAYER metal1 ;
			RECT 16.57 16.57 16.57 16.57 ;
			END
		END OP53
	PIN OP54
		DIRECTION OUTPUT ;
		USE SIGNAL ;
		PORT
			LAYER metal1 ;
			RECT 16.57 16.57 16.57 16.57 ;
			END
		END OP54
	PIN OP55
		DIRECTION OUTPUT ;
		USE SIGNAL ;
		PORT
			LAYER metal1 ;
			RECT 16.57 16.57 16.57 16.57 ;
			END
		END OP55
	PIN OP56
		DIRECTION OUTPUT ;
		USE SIGNAL ;
		PORT
			LAYER metal1 ;
			RECT 16.57 16.57 16.57 16.57 ;
			END
		END OP56
	PIN OP57
		DIRECTION OUTPUT ;
		USE SIGNAL ;
		PORT
			LAYER metal1 ;
			RECT 16.57 16.57 16.57 16.57 ;
			END
		END OP57
	PIN OP58
		DIRECTION OUTPUT ;
		USE SIGNAL ;
		PORT
			LAYER metal1 ;
			RECT 16.57 16.57 16.57 16.57 ;
			END
		END OP58
	PIN OP59
		DIRECTION OUTPUT ;
		USE SIGNAL ;
		PORT
			LAYER metal1 ;
			RECT 16.57 16.57 16.57 16.57 ;
			END
		END OP59
	PIN IP0
		DIRECTION INPUT ;
		USE SIGNAL ;
		PORT
			LAYER metal1 ;
			RECT 16.57 16.57 16.57 16.57 ;
			END
		END IP0
	PIN IP1
		DIRECTION INPUT ;
		USE SIGNAL ;
		PORT
			LAYER metal1 ;
			RECT 16.57 16.57 16.57 16.57 ;
			END
		END IP1
	PIN IP2
		DIRECTION INPUT ;
		USE SIGNAL ;
		PORT
			LAYER metal1 ;
			RECT 16.57 16.57 16.57 16.57 ;
			END
		END IP2
	PIN IP3
		DIRECTION INPUT ;
		USE SIGNAL ;
		PORT
			LAYER metal1 ;
			RECT 16.57 16.57 16.57 16.57 ;
			END
		END IP3
	PIN IP4
		DIRECTION INPUT ;
		USE SIGNAL ;
		PORT
			LAYER metal1 ;
			RECT 16.57 16.57 16.57 16.57 ;
			END
		END IP4
	PIN IP5
		DIRECTION INPUT ;
		USE SIGNAL ;
		PORT
			LAYER metal1 ;
			RECT 16.57 16.57 16.57 16.57 ;
			END
		END IP5
	PIN IP6
		DIRECTION INPUT ;
		USE SIGNAL ;
		PORT
			LAYER metal1 ;
			RECT 16.57 16.57 16.57 16.57 ;
			END
		END IP6
	PIN IP7
		DIRECTION INPUT ;
		USE SIGNAL ;
		PORT
			LAYER metal1 ;
			RECT 16.57 16.57 16.57 16.57 ;
			END
		END IP7
	PIN IP8
		DIRECTION INPUT ;
		USE SIGNAL ;
		PORT
			LAYER metal1 ;
			RECT 16.57 16.57 16.57 16.57 ;
			END
		END IP8
	PIN IP9
		DIRECTION INPUT ;
		USE SIGNAL ;
		PORT
			LAYER metal1 ;
			RECT 16.57 16.57 16.57 16.57 ;
			END
		END IP9
	PIN IP10
		DIRECTION INPUT ;
		USE SIGNAL ;
		PORT
			LAYER metal1 ;
			RECT 16.57 16.57 16.57 16.57 ;
			END
		END IP10
	PIN IP11
		DIRECTION INPUT ;
		USE SIGNAL ;
		PORT
			LAYER metal1 ;
			RECT 16.57 16.57 16.57 16.57 ;
			END
		END IP11
	PIN IP12
		DIRECTION INPUT ;
		USE SIGNAL ;
		PORT
			LAYER metal1 ;
			RECT 16.57 16.57 16.57 16.57 ;
			END
		END IP12
	PIN IP13
		DIRECTION INPUT ;
		USE SIGNAL ;
		PORT
			LAYER metal1 ;
			RECT 16.57 16.57 16.57 16.57 ;
			END
		END IP13
	PIN IP14
		DIRECTION INPUT ;
		USE SIGNAL ;
		PORT
			LAYER metal1 ;
			RECT 16.57 16.57 16.57 16.57 ;
			END
		END IP14
	PIN IP15
		DIRECTION INPUT ;
		USE SIGNAL ;
		PORT
			LAYER metal1 ;
			RECT 16.57 16.57 16.57 16.57 ;
			END
		END IP15
END cluster_7
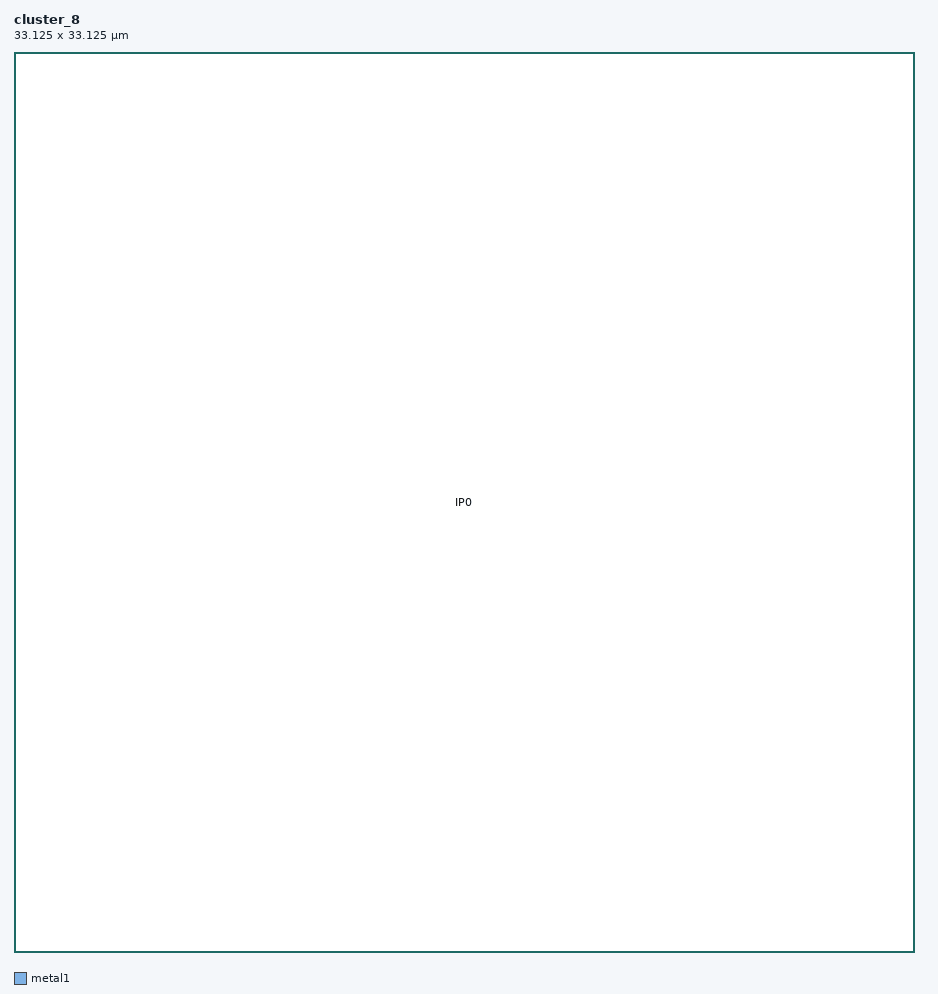
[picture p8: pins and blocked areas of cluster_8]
MACRO cluster_8
	CLASS BLOCK ;
	ORIGIN 0 0 ;
	FOREIGN cluster_8 0 0 ;
	SIZE 33.125 BY 33.125 ;
	SYMMETRY X Y ;
	PIN OP0
		DIRECTION OUTPUT ;
		USE SIGNAL ;
		PORT
			LAYER metal1 ;
			RECT 16.562 16.562 16.562 16.562 ;
			END
		END OP0
	PIN OP1
		DIRECTION OUTPUT ;
		USE SIGNAL ;
		PORT
			LAYER metal1 ;
			RECT 16.562 16.562 16.562 16.562 ;
			END
		END OP1
	PIN OP2
		DIRECTION OUTPUT ;
		USE SIGNAL ;
		PORT
			LAYER metal1 ;
			RECT 16.562 16.562 16.562 16.562 ;
			END
		END OP2
	PIN OP3
		DIRECTION OUTPUT ;
		USE SIGNAL ;
		PORT
			LAYER metal1 ;
			RECT 16.562 16.562 16.562 16.562 ;
			END
		END OP3
	PIN OP4
		DIRECTION OUTPUT ;
		USE SIGNAL ;
		PORT
			LAYER metal1 ;
			RECT 16.562 16.562 16.562 16.562 ;
			END
		END OP4
	PIN OP5
		DIRECTION OUTPUT ;
		USE SIGNAL ;
		PORT
			LAYER metal1 ;
			RECT 16.562 16.562 16.562 16.562 ;
			END
		END OP5
	PIN OP6
		DIRECTION OUTPUT ;
		USE SIGNAL ;
		PORT
			LAYER metal1 ;
			RECT 16.562 16.562 16.562 16.562 ;
			END
		END OP6
	PIN OP7
		DIRECTION OUTPUT ;
		USE SIGNAL ;
		PORT
			LAYER metal1 ;
			RECT 16.562 16.562 16.562 16.562 ;
			END
		END OP7
	PIN OP8
		DIRECTION OUTPUT ;
		USE SIGNAL ;
		PORT
			LAYER metal1 ;
			RECT 16.562 16.562 16.562 16.562 ;
			END
		END OP8
	PIN OP9
		DIRECTION OUTPUT ;
		USE SIGNAL ;
		PORT
			LAYER metal1 ;
			RECT 16.562 16.562 16.562 16.562 ;
			END
		END OP9
	PIN OP10
		DIRECTION OUTPUT ;
		USE SIGNAL ;
		PORT
			LAYER metal1 ;
			RECT 16.562 16.562 16.562 16.562 ;
			END
		END OP10
	PIN OP11
		DIRECTION OUTPUT ;
		USE SIGNAL ;
		PORT
			LAYER metal1 ;
			RECT 16.562 16.562 16.562 16.562 ;
			END
		END OP11
	PIN OP12
		DIRECTION OUTPUT ;
		USE SIGNAL ;
		PORT
			LAYER metal1 ;
			RECT 16.562 16.562 16.562 16.562 ;
			END
		END OP12
	PIN OP13
		DIRECTION OUTPUT ;
		USE SIGNAL ;
		PORT
			LAYER metal1 ;
			RECT 16.562 16.562 16.562 16.562 ;
			END
		END OP13
	PIN OP14
		DIRECTION OUTPUT ;
		USE SIGNAL ;
		PORT
			LAYER metal1 ;
			RECT 16.562 16.562 16.562 16.562 ;
			END
		END OP14
	PIN OP15
		DIRECTION OUTPUT ;
		USE SIGNAL ;
		PORT
			LAYER metal1 ;
			RECT 16.562 16.562 16.562 16.562 ;
			END
		END OP15
	PIN OP16
		DIRECTION OUTPUT ;
		USE SIGNAL ;
		PORT
			LAYER metal1 ;
			RECT 16.562 16.562 16.562 16.562 ;
			END
		END OP16
	PIN OP17
		DIRECTION OUTPUT ;
		USE SIGNAL ;
		PORT
			LAYER metal1 ;
			RECT 16.562 16.562 16.562 16.562 ;
			END
		END OP17
	PIN OP18
		DIRECTION OUTPUT ;
		USE SIGNAL ;
		PORT
			LAYER metal1 ;
			RECT 16.562 16.562 16.562 16.562 ;
			END
		END OP18
	PIN OP19
		DIRECTION OUTPUT ;
		USE SIGNAL ;
		PORT
			LAYER metal1 ;
			RECT 16.562 16.562 16.562 16.562 ;
			END
		END OP19
	PIN OP20
		DIRECTION OUTPUT ;
		USE SIGNAL ;
		PORT
			LAYER metal1 ;
			RECT 16.562 16.562 16.562 16.562 ;
			END
		END OP20
	PIN OP21
		DIRECTION OUTPUT ;
		USE SIGNAL ;
		PORT
			LAYER metal1 ;
			RECT 16.562 16.562 16.562 16.562 ;
			END
		END OP21
	PIN OP22
		DIRECTION OUTPUT ;
		USE SIGNAL ;
		PORT
			LAYER metal1 ;
			RECT 16.562 16.562 16.562 16.562 ;
			END
		END OP22
	PIN OP23
		DIRECTION OUTPUT ;
		USE SIGNAL ;
		PORT
			LAYER metal1 ;
			RECT 16.562 16.562 16.562 16.562 ;
			END
		END OP23
	PIN OP24
		DIRECTION OUTPUT ;
		USE SIGNAL ;
		PORT
			LAYER metal1 ;
			RECT 16.562 16.562 16.562 16.562 ;
			END
		END OP24
	PIN OP25
		DIRECTION OUTPUT ;
		USE SIGNAL ;
		PORT
			LAYER metal1 ;
			RECT 16.562 16.562 16.562 16.562 ;
			END
		END OP25
	PIN OP26
		DIRECTION OUTPUT ;
		USE SIGNAL ;
		PORT
			LAYER metal1 ;
			RECT 16.562 16.562 16.562 16.562 ;
			END
		END OP26
	PIN OP27
		DIRECTION OUTPUT ;
		USE SIGNAL ;
		PORT
			LAYER metal1 ;
			RECT 16.562 16.562 16.562 16.562 ;
			END
		END OP27
	PIN OP28
		DIRECTION OUTPUT ;
		USE SIGNAL ;
		PORT
			LAYER metal1 ;
			RECT 16.562 16.562 16.562 16.562 ;
			END
		END OP28
	PIN OP29
		DIRECTION OUTPUT ;
		USE SIGNAL ;
		PORT
			LAYER metal1 ;
			RECT 16.562 16.562 16.562 16.562 ;
			END
		END OP29
	PIN OP30
		DIRECTION OUTPUT ;
		USE SIGNAL ;
		PORT
			LAYER metal1 ;
			RECT 16.562 16.562 16.562 16.562 ;
			END
		END OP30
	PIN OP31
		DIRECTION OUTPUT ;
		USE SIGNAL ;
		PORT
			LAYER metal1 ;
			RECT 16.562 16.562 16.562 16.562 ;
			END
		END OP31
	PIN OP32
		DIRECTION OUTPUT ;
		USE SIGNAL ;
		PORT
			LAYER metal1 ;
			RECT 16.562 16.562 16.562 16.562 ;
			END
		END OP32
	PIN OP33
		DIRECTION OUTPUT ;
		USE SIGNAL ;
		PORT
			LAYER metal1 ;
			RECT 16.562 16.562 16.562 16.562 ;
			END
		END OP33
	PIN OP34
		DIRECTION OUTPUT ;
		USE SIGNAL ;
		PORT
			LAYER metal1 ;
			RECT 16.562 16.562 16.562 16.562 ;
			END
		END OP34
	PIN OP35
		DIRECTION OUTPUT ;
		USE SIGNAL ;
		PORT
			LAYER metal1 ;
			RECT 16.562 16.562 16.562 16.562 ;
			END
		END OP35
	PIN OP36
		DIRECTION OUTPUT ;
		USE SIGNAL ;
		PORT
			LAYER metal1 ;
			RECT 16.562 16.562 16.562 16.562 ;
			END
		END OP36
	PIN OP37
		DIRECTION OUTPUT ;
		USE SIGNAL ;
		PORT
			LAYER metal1 ;
			RECT 16.562 16.562 16.562 16.562 ;
			END
		END OP37
	PIN OP38
		DIRECTION OUTPUT ;
		USE SIGNAL ;
		PORT
			LAYER metal1 ;
			RECT 16.562 16.562 16.562 16.562 ;
			END
		END OP38
	PIN OP39
		DIRECTION OUTPUT ;
		USE SIGNAL ;
		PORT
			LAYER metal1 ;
			RECT 16.562 16.562 16.562 16.562 ;
			END
		END OP39
	PIN OP40
		DIRECTION OUTPUT ;
		USE SIGNAL ;
		PORT
			LAYER metal1 ;
			RECT 16.562 16.562 16.562 16.562 ;
			END
		END OP40
	PIN OP41
		DIRECTION OUTPUT ;
		USE SIGNAL ;
		PORT
			LAYER metal1 ;
			RECT 16.562 16.562 16.562 16.562 ;
			END
		END OP41
	PIN OP42
		DIRECTION OUTPUT ;
		USE SIGNAL ;
		PORT
			LAYER metal1 ;
			RECT 16.562 16.562 16.562 16.562 ;
			END
		END OP42
	PIN OP43
		DIRECTION OUTPUT ;
		USE SIGNAL ;
		PORT
			LAYER metal1 ;
			RECT 16.562 16.562 16.562 16.562 ;
			END
		END OP43
	PIN OP44
		DIRECTION OUTPUT ;
		USE SIGNAL ;
		PORT
			LAYER metal1 ;
			RECT 16.562 16.562 16.562 16.562 ;
			END
		END OP44
	PIN OP45
		DIRECTION OUTPUT ;
		USE SIGNAL ;
		PORT
			LAYER metal1 ;
			RECT 16.562 16.562 16.562 16.562 ;
			END
		END OP45
	PIN OP46
		DIRECTION OUTPUT ;
		USE SIGNAL ;
		PORT
			LAYER metal1 ;
			RECT 16.562 16.562 16.562 16.562 ;
			END
		END OP46
	PIN OP47
		DIRECTION OUTPUT ;
		USE SIGNAL ;
		PORT
			LAYER metal1 ;
			RECT 16.562 16.562 16.562 16.562 ;
			END
		END OP47
	PIN OP48
		DIRECTION OUTPUT ;
		USE SIGNAL ;
		PORT
			LAYER metal1 ;
			RECT 16.562 16.562 16.562 16.562 ;
			END
		END OP48
	PIN OP49
		DIRECTION OUTPUT ;
		USE SIGNAL ;
		PORT
			LAYER metal1 ;
			RECT 16.562 16.562 16.562 16.562 ;
			END
		END OP49
	PIN OP50
		DIRECTION OUTPUT ;
		USE SIGNAL ;
		PORT
			LAYER metal1 ;
			RECT 16.562 16.562 16.562 16.562 ;
			END
		END OP50
	PIN OP51
		DIRECTION OUTPUT ;
		USE SIGNAL ;
		PORT
			LAYER metal1 ;
			RECT 16.562 16.562 16.562 16.562 ;
			END
		END OP51
	PIN OP52
		DIRECTION OUTPUT ;
		USE SIGNAL ;
		PORT
			LAYER metal1 ;
			RECT 16.562 16.562 16.562 16.562 ;
			END
		END OP52
	PIN OP53
		DIRECTION OUTPUT ;
		USE SIGNAL ;
		PORT
			LAYER metal1 ;
			RECT 16.562 16.562 16.562 16.562 ;
			END
		END OP53
	PIN OP54
		DIRECTION OUTPUT ;
		USE SIGNAL ;
		PORT
			LAYER metal1 ;
			RECT 16.562 16.562 16.562 16.562 ;
			END
		END OP54
	PIN OP55
		DIRECTION OUTPUT ;
		USE SIGNAL ;
		PORT
			LAYER metal1 ;
			RECT 16.562 16.562 16.562 16.562 ;
			END
		END OP55
	PIN OP56
		DIRECTION OUTPUT ;
		USE SIGNAL ;
		PORT
			LAYER metal1 ;
			RECT 16.562 16.562 16.562 16.562 ;
			END
		END OP56
	PIN OP57
		DIRECTION OUTPUT ;
		USE SIGNAL ;
		PORT
			LAYER metal1 ;
			RECT 16.562 16.562 16.562 16.562 ;
			END
		END OP57
	PIN OP58
		DIRECTION OUTPUT ;
		USE SIGNAL ;
		PORT
			LAYER metal1 ;
			RECT 16.562 16.562 16.562 16.562 ;
			END
		END OP58
	PIN OP59
		DIRECTION OUTPUT ;
		USE SIGNAL ;
		PORT
			LAYER metal1 ;
			RECT 16.562 16.562 16.562 16.562 ;
			END
		END OP59
	PIN IP0
		DIRECTION INPUT ;
		USE SIGNAL ;
		PORT
			LAYER metal1 ;
			RECT 16.562 16.562 16.562 16.562 ;
			END
		END IP0
	PIN IP1
		DIRECTION INPUT ;
		USE SIGNAL ;
		PORT
			LAYER metal1 ;
			RECT 16.562 16.562 16.562 16.562 ;
			END
		END IP1
	PIN IP2
		DIRECTION INPUT ;
		USE SIGNAL ;
		PORT
			LAYER metal1 ;
			RECT 16.562 16.562 16.562 16.562 ;
			END
		END IP2
	PIN IP3
		DIRECTION INPUT ;
		USE SIGNAL ;
		PORT
			LAYER metal1 ;
			RECT 16.562 16.562 16.562 16.562 ;
			END
		END IP3
	PIN IP4
		DIRECTION INPUT ;
		USE SIGNAL ;
		PORT
			LAYER metal1 ;
			RECT 16.562 16.562 16.562 16.562 ;
			END
		END IP4
	PIN IP5
		DIRECTION INPUT ;
		USE SIGNAL ;
		PORT
			LAYER metal1 ;
			RECT 16.562 16.562 16.562 16.562 ;
			END
		END IP5
	PIN IP6
		DIRECTION INPUT ;
		USE SIGNAL ;
		PORT
			LAYER metal1 ;
			RECT 16.562 16.562 16.562 16.562 ;
			END
		END IP6
	PIN IP7
		DIRECTION INPUT ;
		USE SIGNAL ;
		PORT
			LAYER metal1 ;
			RECT 16.562 16.562 16.562 16.562 ;
			END
		END IP7
	PIN IP8
		DIRECTION INPUT ;
		USE SIGNAL ;
		PORT
			LAYER metal1 ;
			RECT 16.562 16.562 16.562 16.562 ;
			END
		END IP8
	PIN IP9
		DIRECTION INPUT ;
		USE SIGNAL ;
		PORT
			LAYER metal1 ;
			RECT 16.562 16.562 16.562 16.562 ;
			END
		END IP9
	PIN IP10
		DIRECTION INPUT ;
		USE SIGNAL ;
		PORT
			LAYER metal1 ;
			RECT 16.562 16.562 16.562 16.562 ;
			END
		END IP10
	PIN IP11
		DIRECTION INPUT ;
		USE SIGNAL ;
		PORT
			LAYER metal1 ;
			RECT 16.562 16.562 16.562 16.562 ;
			END
		END IP11
	PIN IP12
		DIRECTION INPUT ;
		USE SIGNAL ;
		PORT
			LAYER metal1 ;
			RECT 16.562 16.562 16.562 16.562 ;
			END
		END IP12
	PIN IP13
		DIRECTION INPUT ;
		USE SIGNAL ;
		PORT
			LAYER metal1 ;
			RECT 16.562 16.562 16.562 16.562 ;
			END
		END IP13
END cluster_8
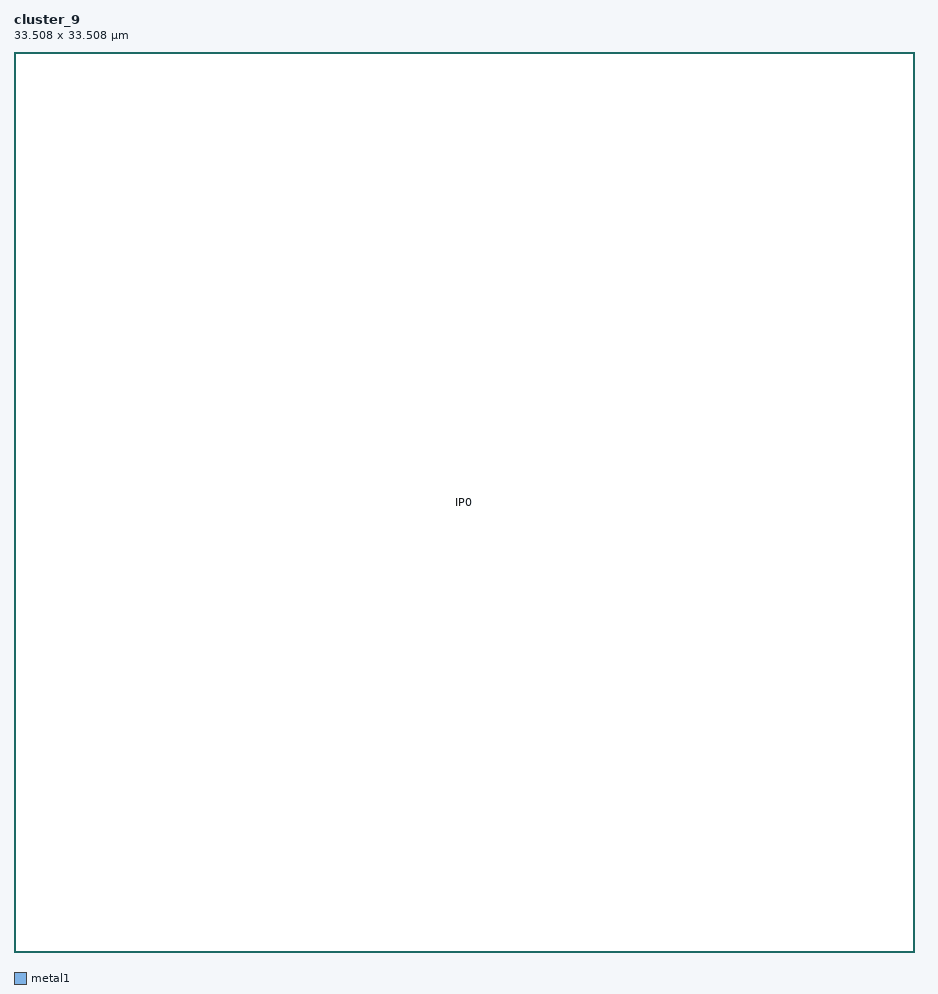
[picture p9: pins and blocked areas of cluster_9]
MACRO cluster_9
	CLASS BLOCK ;
	ORIGIN 0 0 ;
	FOREIGN cluster_9 0 0 ;
	SIZE 33.508 BY 33.508 ;
	SYMMETRY X Y ;
	PIN OP0
		DIRECTION OUTPUT ;
		USE SIGNAL ;
		PORT
			LAYER metal1 ;
			RECT 16.754 16.754 16.754 16.754 ;
			END
		END OP0
	PIN OP1
		DIRECTION OUTPUT ;
		USE SIGNAL ;
		PORT
			LAYER metal1 ;
			RECT 16.754 16.754 16.754 16.754 ;
			END
		END OP1
	PIN OP2
		DIRECTION OUTPUT ;
		USE SIGNAL ;
		PORT
			LAYER metal1 ;
			RECT 16.754 16.754 16.754 16.754 ;
			END
		END OP2
	PIN OP3
		DIRECTION OUTPUT ;
		USE SIGNAL ;
		PORT
			LAYER metal1 ;
			RECT 16.754 16.754 16.754 16.754 ;
			END
		END OP3
	PIN OP4
		DIRECTION OUTPUT ;
		USE SIGNAL ;
		PORT
			LAYER metal1 ;
			RECT 16.754 16.754 16.754 16.754 ;
			END
		END OP4
	PIN OP5
		DIRECTION OUTPUT ;
		USE SIGNAL ;
		PORT
			LAYER metal1 ;
			RECT 16.754 16.754 16.754 16.754 ;
			END
		END OP5
	PIN OP6
		DIRECTION OUTPUT ;
		USE SIGNAL ;
		PORT
			LAYER metal1 ;
			RECT 16.754 16.754 16.754 16.754 ;
			END
		END OP6
	PIN OP7
		DIRECTION OUTPUT ;
		USE SIGNAL ;
		PORT
			LAYER metal1 ;
			RECT 16.754 16.754 16.754 16.754 ;
			END
		END OP7
	PIN OP8
		DIRECTION OUTPUT ;
		USE SIGNAL ;
		PORT
			LAYER metal1 ;
			RECT 16.754 16.754 16.754 16.754 ;
			END
		END OP8
	PIN OP9
		DIRECTION OUTPUT ;
		USE SIGNAL ;
		PORT
			LAYER metal1 ;
			RECT 16.754 16.754 16.754 16.754 ;
			END
		END OP9
	PIN OP10
		DIRECTION OUTPUT ;
		USE SIGNAL ;
		PORT
			LAYER metal1 ;
			RECT 16.754 16.754 16.754 16.754 ;
			END
		END OP10
	PIN OP11
		DIRECTION OUTPUT ;
		USE SIGNAL ;
		PORT
			LAYER metal1 ;
			RECT 16.754 16.754 16.754 16.754 ;
			END
		END OP11
	PIN OP12
		DIRECTION OUTPUT ;
		USE SIGNAL ;
		PORT
			LAYER metal1 ;
			RECT 16.754 16.754 16.754 16.754 ;
			END
		END OP12
	PIN OP13
		DIRECTION OUTPUT ;
		USE SIGNAL ;
		PORT
			LAYER metal1 ;
			RECT 16.754 16.754 16.754 16.754 ;
			END
		END OP13
	PIN OP14
		DIRECTION OUTPUT ;
		USE SIGNAL ;
		PORT
			LAYER metal1 ;
			RECT 16.754 16.754 16.754 16.754 ;
			END
		END OP14
	PIN OP15
		DIRECTION OUTPUT ;
		USE SIGNAL ;
		PORT
			LAYER metal1 ;
			RECT 16.754 16.754 16.754 16.754 ;
			END
		END OP15
	PIN OP16
		DIRECTION OUTPUT ;
		USE SIGNAL ;
		PORT
			LAYER metal1 ;
			RECT 16.754 16.754 16.754 16.754 ;
			END
		END OP16
	PIN OP17
		DIRECTION OUTPUT ;
		USE SIGNAL ;
		PORT
			LAYER metal1 ;
			RECT 16.754 16.754 16.754 16.754 ;
			END
		END OP17
	PIN OP18
		DIRECTION OUTPUT ;
		USE SIGNAL ;
		PORT
			LAYER metal1 ;
			RECT 16.754 16.754 16.754 16.754 ;
			END
		END OP18
	PIN OP19
		DIRECTION OUTPUT ;
		USE SIGNAL ;
		PORT
			LAYER metal1 ;
			RECT 16.754 16.754 16.754 16.754 ;
			END
		END OP19
	PIN OP20
		DIRECTION OUTPUT ;
		USE SIGNAL ;
		PORT
			LAYER metal1 ;
			RECT 16.754 16.754 16.754 16.754 ;
			END
		END OP20
	PIN OP21
		DIRECTION OUTPUT ;
		USE SIGNAL ;
		PORT
			LAYER metal1 ;
			RECT 16.754 16.754 16.754 16.754 ;
			END
		END OP21
	PIN OP22
		DIRECTION OUTPUT ;
		USE SIGNAL ;
		PORT
			LAYER metal1 ;
			RECT 16.754 16.754 16.754 16.754 ;
			END
		END OP22
	PIN OP23
		DIRECTION OUTPUT ;
		USE SIGNAL ;
		PORT
			LAYER metal1 ;
			RECT 16.754 16.754 16.754 16.754 ;
			END
		END OP23
	PIN OP24
		DIRECTION OUTPUT ;
		USE SIGNAL ;
		PORT
			LAYER metal1 ;
			RECT 16.754 16.754 16.754 16.754 ;
			END
		END OP24
	PIN OP25
		DIRECTION OUTPUT ;
		USE SIGNAL ;
		PORT
			LAYER metal1 ;
			RECT 16.754 16.754 16.754 16.754 ;
			END
		END OP25
	PIN OP26
		DIRECTION OUTPUT ;
		USE SIGNAL ;
		PORT
			LAYER metal1 ;
			RECT 16.754 16.754 16.754 16.754 ;
			END
		END OP26
	PIN OP27
		DIRECTION OUTPUT ;
		USE SIGNAL ;
		PORT
			LAYER metal1 ;
			RECT 16.754 16.754 16.754 16.754 ;
			END
		END OP27
	PIN OP28
		DIRECTION OUTPUT ;
		USE SIGNAL ;
		PORT
			LAYER metal1 ;
			RECT 16.754 16.754 16.754 16.754 ;
			END
		END OP28
	PIN OP29
		DIRECTION OUTPUT ;
		USE SIGNAL ;
		PORT
			LAYER metal1 ;
			RECT 16.754 16.754 16.754 16.754 ;
			END
		END OP29
	PIN OP30
		DIRECTION OUTPUT ;
		USE SIGNAL ;
		PORT
			LAYER metal1 ;
			RECT 16.754 16.754 16.754 16.754 ;
			END
		END OP30
	PIN OP31
		DIRECTION OUTPUT ;
		USE SIGNAL ;
		PORT
			LAYER metal1 ;
			RECT 16.754 16.754 16.754 16.754 ;
			END
		END OP31
	PIN OP32
		DIRECTION OUTPUT ;
		USE SIGNAL ;
		PORT
			LAYER metal1 ;
			RECT 16.754 16.754 16.754 16.754 ;
			END
		END OP32
	PIN OP33
		DIRECTION OUTPUT ;
		USE SIGNAL ;
		PORT
			LAYER metal1 ;
			RECT 16.754 16.754 16.754 16.754 ;
			END
		END OP33
	PIN OP34
		DIRECTION OUTPUT ;
		USE SIGNAL ;
		PORT
			LAYER metal1 ;
			RECT 16.754 16.754 16.754 16.754 ;
			END
		END OP34
	PIN OP35
		DIRECTION OUTPUT ;
		USE SIGNAL ;
		PORT
			LAYER metal1 ;
			RECT 16.754 16.754 16.754 16.754 ;
			END
		END OP35
	PIN OP36
		DIRECTION OUTPUT ;
		USE SIGNAL ;
		PORT
			LAYER metal1 ;
			RECT 16.754 16.754 16.754 16.754 ;
			END
		END OP36
	PIN OP37
		DIRECTION OUTPUT ;
		USE SIGNAL ;
		PORT
			LAYER metal1 ;
			RECT 16.754 16.754 16.754 16.754 ;
			END
		END OP37
	PIN OP38
		DIRECTION OUTPUT ;
		USE SIGNAL ;
		PORT
			LAYER metal1 ;
			RECT 16.754 16.754 16.754 16.754 ;
			END
		END OP38
	PIN OP39
		DIRECTION OUTPUT ;
		USE SIGNAL ;
		PORT
			LAYER metal1 ;
			RECT 16.754 16.754 16.754 16.754 ;
			END
		END OP39
	PIN OP40
		DIRECTION OUTPUT ;
		USE SIGNAL ;
		PORT
			LAYER metal1 ;
			RECT 16.754 16.754 16.754 16.754 ;
			END
		END OP40
	PIN OP41
		DIRECTION OUTPUT ;
		USE SIGNAL ;
		PORT
			LAYER metal1 ;
			RECT 16.754 16.754 16.754 16.754 ;
			END
		END OP41
	PIN OP42
		DIRECTION OUTPUT ;
		USE SIGNAL ;
		PORT
			LAYER metal1 ;
			RECT 16.754 16.754 16.754 16.754 ;
			END
		END OP42
	PIN OP43
		DIRECTION OUTPUT ;
		USE SIGNAL ;
		PORT
			LAYER metal1 ;
			RECT 16.754 16.754 16.754 16.754 ;
			END
		END OP43
	PIN OP44
		DIRECTION OUTPUT ;
		USE SIGNAL ;
		PORT
			LAYER metal1 ;
			RECT 16.754 16.754 16.754 16.754 ;
			END
		END OP44
	PIN OP45
		DIRECTION OUTPUT ;
		USE SIGNAL ;
		PORT
			LAYER metal1 ;
			RECT 16.754 16.754 16.754 16.754 ;
			END
		END OP45
	PIN OP46
		DIRECTION OUTPUT ;
		USE SIGNAL ;
		PORT
			LAYER metal1 ;
			RECT 16.754 16.754 16.754 16.754 ;
			END
		END OP46
	PIN OP47
		DIRECTION OUTPUT ;
		USE SIGNAL ;
		PORT
			LAYER metal1 ;
			RECT 16.754 16.754 16.754 16.754 ;
			END
		END OP47
	PIN OP48
		DIRECTION OUTPUT ;
		USE SIGNAL ;
		PORT
			LAYER metal1 ;
			RECT 16.754 16.754 16.754 16.754 ;
			END
		END OP48
	PIN OP49
		DIRECTION OUTPUT ;
		USE SIGNAL ;
		PORT
			LAYER metal1 ;
			RECT 16.754 16.754 16.754 16.754 ;
			END
		END OP49
	PIN OP50
		DIRECTION OUTPUT ;
		USE SIGNAL ;
		PORT
			LAYER metal1 ;
			RECT 16.754 16.754 16.754 16.754 ;
			END
		END OP50
	PIN OP51
		DIRECTION OUTPUT ;
		USE SIGNAL ;
		PORT
			LAYER metal1 ;
			RECT 16.754 16.754 16.754 16.754 ;
			END
		END OP51
	PIN OP52
		DIRECTION OUTPUT ;
		USE SIGNAL ;
		PORT
			LAYER metal1 ;
			RECT 16.754 16.754 16.754 16.754 ;
			END
		END OP52
	PIN OP53
		DIRECTION OUTPUT ;
		USE SIGNAL ;
		PORT
			LAYER metal1 ;
			RECT 16.754 16.754 16.754 16.754 ;
			END
		END OP53
	PIN OP54
		DIRECTION OUTPUT ;
		USE SIGNAL ;
		PORT
			LAYER metal1 ;
			RECT 16.754 16.754 16.754 16.754 ;
			END
		END OP54
	PIN OP55
		DIRECTION OUTPUT ;
		USE SIGNAL ;
		PORT
			LAYER metal1 ;
			RECT 16.754 16.754 16.754 16.754 ;
			END
		END OP55
	PIN OP56
		DIRECTION OUTPUT ;
		USE SIGNAL ;
		PORT
			LAYER metal1 ;
			RECT 16.754 16.754 16.754 16.754 ;
			END
		END OP56
	PIN OP57
		DIRECTION OUTPUT ;
		USE SIGNAL ;
		PORT
			LAYER metal1 ;
			RECT 16.754 16.754 16.754 16.754 ;
			END
		END OP57
	PIN OP58
		DIRECTION OUTPUT ;
		USE SIGNAL ;
		PORT
			LAYER metal1 ;
			RECT 16.754 16.754 16.754 16.754 ;
			END
		END OP58
	PIN OP59
		DIRECTION OUTPUT ;
		USE SIGNAL ;
		PORT
			LAYER metal1 ;
			RECT 16.754 16.754 16.754 16.754 ;
			END
		END OP59
	PIN OP60
		DIRECTION OUTPUT ;
		USE SIGNAL ;
		PORT
			LAYER metal1 ;
			RECT 16.754 16.754 16.754 16.754 ;
			END
		END OP60
	PIN OP61
		DIRECTION OUTPUT ;
		USE SIGNAL ;
		PORT
			LAYER metal1 ;
			RECT 16.754 16.754 16.754 16.754 ;
			END
		END OP61
	PIN OP62
		DIRECTION OUTPUT ;
		USE SIGNAL ;
		PORT
			LAYER metal1 ;
			RECT 16.754 16.754 16.754 16.754 ;
			END
		END OP62
	PIN OP63
		DIRECTION OUTPUT ;
		USE SIGNAL ;
		PORT
			LAYER metal1 ;
			RECT 16.754 16.754 16.754 16.754 ;
			END
		END OP63
	PIN OP64
		DIRECTION OUTPUT ;
		USE SIGNAL ;
		PORT
			LAYER metal1 ;
			RECT 16.754 16.754 16.754 16.754 ;
			END
		END OP64
	PIN OP65
		DIRECTION OUTPUT ;
		USE SIGNAL ;
		PORT
			LAYER metal1 ;
			RECT 16.754 16.754 16.754 16.754 ;
			END
		END OP65
	PIN OP66
		DIRECTION OUTPUT ;
		USE SIGNAL ;
		PORT
			LAYER metal1 ;
			RECT 16.754 16.754 16.754 16.754 ;
			END
		END OP66
	PIN IP0
		DIRECTION INPUT ;
		USE SIGNAL ;
		PORT
			LAYER metal1 ;
			RECT 16.754 16.754 16.754 16.754 ;
			END
		END IP0
	PIN IP1
		DIRECTION INPUT ;
		USE SIGNAL ;
		PORT
			LAYER metal1 ;
			RECT 16.754 16.754 16.754 16.754 ;
			END
		END IP1
	PIN IP2
		DIRECTION INPUT ;
		USE SIGNAL ;
		PORT
			LAYER metal1 ;
			RECT 16.754 16.754 16.754 16.754 ;
			END
		END IP2
	PIN IP3
		DIRECTION INPUT ;
		USE SIGNAL ;
		PORT
			LAYER metal1 ;
			RECT 16.754 16.754 16.754 16.754 ;
			END
		END IP3
	PIN IP4
		DIRECTION INPUT ;
		USE SIGNAL ;
		PORT
			LAYER metal1 ;
			RECT 16.754 16.754 16.754 16.754 ;
			END
		END IP4
	PIN IP5
		DIRECTION INPUT ;
		USE SIGNAL ;
		PORT
			LAYER metal1 ;
			RECT 16.754 16.754 16.754 16.754 ;
			END
		END IP5
	PIN IP6
		DIRECTION INPUT ;
		USE SIGNAL ;
		PORT
			LAYER metal1 ;
			RECT 16.754 16.754 16.754 16.754 ;
			END
		END IP6
	PIN IP7
		DIRECTION INPUT ;
		USE SIGNAL ;
		PORT
			LAYER metal1 ;
			RECT 16.754 16.754 16.754 16.754 ;
			END
		END IP7
	PIN IP8
		DIRECTION INPUT ;
		USE SIGNAL ;
		PORT
			LAYER metal1 ;
			RECT 16.754 16.754 16.754 16.754 ;
			END
		END IP8
	PIN IP9
		DIRECTION INPUT ;
		USE SIGNAL ;
		PORT
			LAYER metal1 ;
			RECT 16.754 16.754 16.754 16.754 ;
			END
		END IP9
	PIN IP10
		DIRECTION INPUT ;
		USE SIGNAL ;
		PORT
			LAYER metal1 ;
			RECT 16.754 16.754 16.754 16.754 ;
			END
		END IP10
	PIN IP11
		DIRECTION INPUT ;
		USE SIGNAL ;
		PORT
			LAYER metal1 ;
			RECT 16.754 16.754 16.754 16.754 ;
			END
		END IP11
	PIN IP12
		DIRECTION INPUT ;
		USE SIGNAL ;
		PORT
			LAYER metal1 ;
			RECT 16.754 16.754 16.754 16.754 ;
			END
		END IP12
	PIN IP13
		DIRECTION INPUT ;
		USE SIGNAL ;
		PORT
			LAYER metal1 ;
			RECT 16.754 16.754 16.754 16.754 ;
			END
		END IP13
	PIN IP14
		DIRECTION INPUT ;
		USE SIGNAL ;
		PORT
			LAYER metal1 ;
			RECT 16.754 16.754 16.754 16.754 ;
			END
		END IP14
	PIN IP15
		DIRECTION INPUT ;
		USE SIGNAL ;
		PORT
			LAYER metal1 ;
			RECT 16.754 16.754 16.754 16.754 ;
			END
		END IP15
	PIN IP16
		DIRECTION INPUT ;
		USE SIGNAL ;
		PORT
			LAYER metal1 ;
			RECT 16.754 16.754 16.754 16.754 ;
			END
		END IP16
	PIN IP17
		DIRECTION INPUT ;
		USE SIGNAL ;
		PORT
			LAYER metal1 ;
			RECT 16.754 16.754 16.754 16.754 ;
			END
		END IP17
	PIN IP18
		DIRECTION INPUT ;
		USE SIGNAL ;
		PORT
			LAYER metal1 ;
			RECT 16.754 16.754 16.754 16.754 ;
			END
		END IP18
	PIN IP19
		DIRECTION INPUT ;
		USE SIGNAL ;
		PORT
			LAYER metal1 ;
			RECT 16.754 16.754 16.754 16.754 ;
			END
		END IP19
END cluster_9
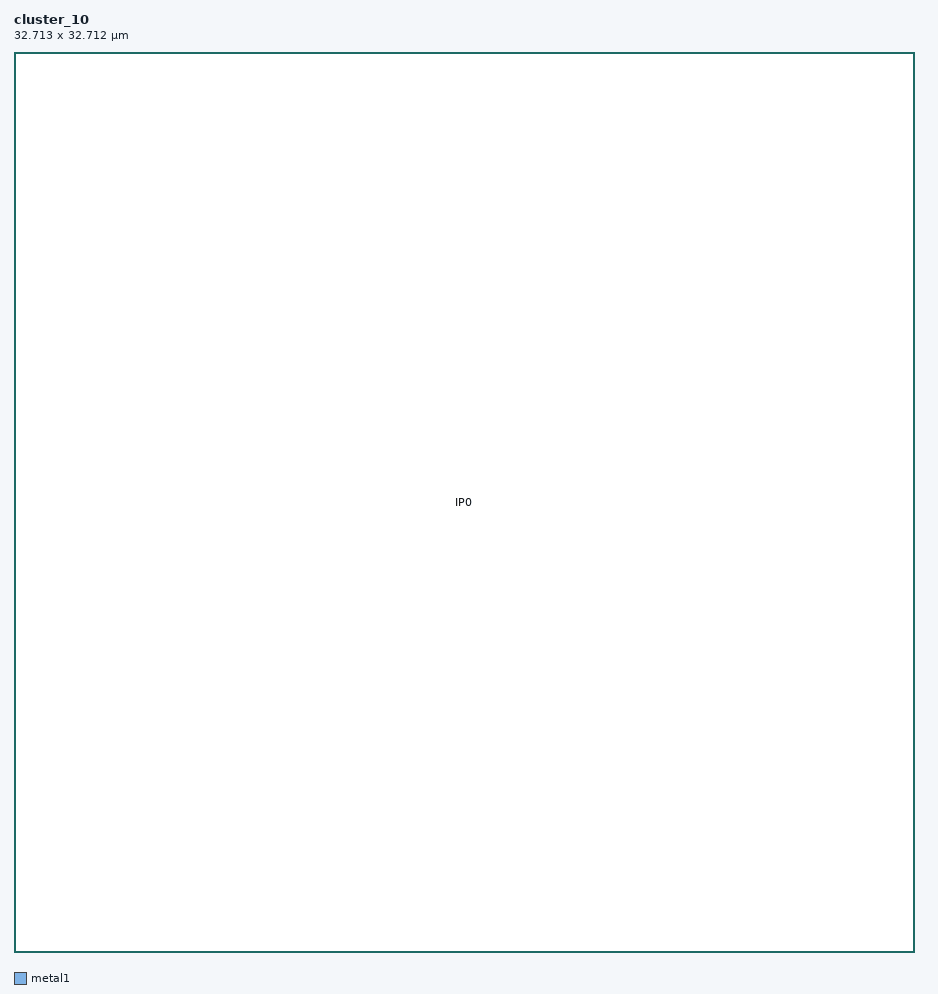
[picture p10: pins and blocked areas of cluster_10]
MACRO cluster_10
	CLASS BLOCK ;
	ORIGIN 0 0 ;
	FOREIGN cluster_10 0 0 ;
	SIZE 32.713 BY 32.712 ;
	SYMMETRY X Y ;
	PIN OP0
		DIRECTION OUTPUT ;
		USE SIGNAL ;
		PORT
			LAYER metal1 ;
			RECT 16.357 16.356 16.357 16.356 ;
			END
		END OP0
	PIN OP1
		DIRECTION OUTPUT ;
		USE SIGNAL ;
		PORT
			LAYER metal1 ;
			RECT 16.357 16.356 16.357 16.356 ;
			END
		END OP1
	PIN OP2
		DIRECTION OUTPUT ;
		USE SIGNAL ;
		PORT
			LAYER metal1 ;
			RECT 16.357 16.356 16.357 16.356 ;
			END
		END OP2
	PIN OP3
		DIRECTION OUTPUT ;
		USE SIGNAL ;
		PORT
			LAYER metal1 ;
			RECT 16.357 16.356 16.357 16.356 ;
			END
		END OP3
	PIN OP4
		DIRECTION OUTPUT ;
		USE SIGNAL ;
		PORT
			LAYER metal1 ;
			RECT 16.357 16.356 16.357 16.356 ;
			END
		END OP4
	PIN OP5
		DIRECTION OUTPUT ;
		USE SIGNAL ;
		PORT
			LAYER metal1 ;
			RECT 16.357 16.356 16.357 16.356 ;
			END
		END OP5
	PIN OP6
		DIRECTION OUTPUT ;
		USE SIGNAL ;
		PORT
			LAYER metal1 ;
			RECT 16.357 16.356 16.357 16.356 ;
			END
		END OP6
	PIN OP7
		DIRECTION OUTPUT ;
		USE SIGNAL ;
		PORT
			LAYER metal1 ;
			RECT 16.357 16.356 16.357 16.356 ;
			END
		END OP7
	PIN OP8
		DIRECTION OUTPUT ;
		USE SIGNAL ;
		PORT
			LAYER metal1 ;
			RECT 16.357 16.356 16.357 16.356 ;
			END
		END OP8
	PIN OP9
		DIRECTION OUTPUT ;
		USE SIGNAL ;
		PORT
			LAYER metal1 ;
			RECT 16.357 16.356 16.357 16.356 ;
			END
		END OP9
	PIN OP10
		DIRECTION OUTPUT ;
		USE SIGNAL ;
		PORT
			LAYER metal1 ;
			RECT 16.357 16.356 16.357 16.356 ;
			END
		END OP10
	PIN OP11
		DIRECTION OUTPUT ;
		USE SIGNAL ;
		PORT
			LAYER metal1 ;
			RECT 16.357 16.356 16.357 16.356 ;
			END
		END OP11
	PIN OP12
		DIRECTION OUTPUT ;
		USE SIGNAL ;
		PORT
			LAYER metal1 ;
			RECT 16.357 16.356 16.357 16.356 ;
			END
		END OP12
	PIN OP13
		DIRECTION OUTPUT ;
		USE SIGNAL ;
		PORT
			LAYER metal1 ;
			RECT 16.357 16.356 16.357 16.356 ;
			END
		END OP13
	PIN OP14
		DIRECTION OUTPUT ;
		USE SIGNAL ;
		PORT
			LAYER metal1 ;
			RECT 16.357 16.356 16.357 16.356 ;
			END
		END OP14
	PIN OP15
		DIRECTION OUTPUT ;
		USE SIGNAL ;
		PORT
			LAYER metal1 ;
			RECT 16.357 16.356 16.357 16.356 ;
			END
		END OP15
	PIN OP16
		DIRECTION OUTPUT ;
		USE SIGNAL ;
		PORT
			LAYER metal1 ;
			RECT 16.357 16.356 16.357 16.356 ;
			END
		END OP16
	PIN OP17
		DIRECTION OUTPUT ;
		USE SIGNAL ;
		PORT
			LAYER metal1 ;
			RECT 16.357 16.356 16.357 16.356 ;
			END
		END OP17
	PIN OP18
		DIRECTION OUTPUT ;
		USE SIGNAL ;
		PORT
			LAYER metal1 ;
			RECT 16.357 16.356 16.357 16.356 ;
			END
		END OP18
	PIN OP19
		DIRECTION OUTPUT ;
		USE SIGNAL ;
		PORT
			LAYER metal1 ;
			RECT 16.357 16.356 16.357 16.356 ;
			END
		END OP19
	PIN OP20
		DIRECTION OUTPUT ;
		USE SIGNAL ;
		PORT
			LAYER metal1 ;
			RECT 16.357 16.356 16.357 16.356 ;
			END
		END OP20
	PIN OP21
		DIRECTION OUTPUT ;
		USE SIGNAL ;
		PORT
			LAYER metal1 ;
			RECT 16.357 16.356 16.357 16.356 ;
			END
		END OP21
	PIN OP22
		DIRECTION OUTPUT ;
		USE SIGNAL ;
		PORT
			LAYER metal1 ;
			RECT 16.357 16.356 16.357 16.356 ;
			END
		END OP22
	PIN OP23
		DIRECTION OUTPUT ;
		USE SIGNAL ;
		PORT
			LAYER metal1 ;
			RECT 16.357 16.356 16.357 16.356 ;
			END
		END OP23
	PIN OP24
		DIRECTION OUTPUT ;
		USE SIGNAL ;
		PORT
			LAYER metal1 ;
			RECT 16.357 16.356 16.357 16.356 ;
			END
		END OP24
	PIN OP25
		DIRECTION OUTPUT ;
		USE SIGNAL ;
		PORT
			LAYER metal1 ;
			RECT 16.357 16.356 16.357 16.356 ;
			END
		END OP25
	PIN OP26
		DIRECTION OUTPUT ;
		USE SIGNAL ;
		PORT
			LAYER metal1 ;
			RECT 16.357 16.356 16.357 16.356 ;
			END
		END OP26
	PIN OP27
		DIRECTION OUTPUT ;
		USE SIGNAL ;
		PORT
			LAYER metal1 ;
			RECT 16.357 16.356 16.357 16.356 ;
			END
		END OP27
	PIN OP28
		DIRECTION OUTPUT ;
		USE SIGNAL ;
		PORT
			LAYER metal1 ;
			RECT 16.357 16.356 16.357 16.356 ;
			END
		END OP28
	PIN OP29
		DIRECTION OUTPUT ;
		USE SIGNAL ;
		PORT
			LAYER metal1 ;
			RECT 16.357 16.356 16.357 16.356 ;
			END
		END OP29
	PIN OP30
		DIRECTION OUTPUT ;
		USE SIGNAL ;
		PORT
			LAYER metal1 ;
			RECT 16.357 16.356 16.357 16.356 ;
			END
		END OP30
	PIN OP31
		DIRECTION OUTPUT ;
		USE SIGNAL ;
		PORT
			LAYER metal1 ;
			RECT 16.357 16.356 16.357 16.356 ;
			END
		END OP31
	PIN OP32
		DIRECTION OUTPUT ;
		USE SIGNAL ;
		PORT
			LAYER metal1 ;
			RECT 16.357 16.356 16.357 16.356 ;
			END
		END OP32
	PIN OP33
		DIRECTION OUTPUT ;
		USE SIGNAL ;
		PORT
			LAYER metal1 ;
			RECT 16.357 16.356 16.357 16.356 ;
			END
		END OP33
	PIN OP34
		DIRECTION OUTPUT ;
		USE SIGNAL ;
		PORT
			LAYER metal1 ;
			RECT 16.357 16.356 16.357 16.356 ;
			END
		END OP34
	PIN OP35
		DIRECTION OUTPUT ;
		USE SIGNAL ;
		PORT
			LAYER metal1 ;
			RECT 16.357 16.356 16.357 16.356 ;
			END
		END OP35
	PIN OP36
		DIRECTION OUTPUT ;
		USE SIGNAL ;
		PORT
			LAYER metal1 ;
			RECT 16.357 16.356 16.357 16.356 ;
			END
		END OP36
	PIN OP37
		DIRECTION OUTPUT ;
		USE SIGNAL ;
		PORT
			LAYER metal1 ;
			RECT 16.357 16.356 16.357 16.356 ;
			END
		END OP37
	PIN OP38
		DIRECTION OUTPUT ;
		USE SIGNAL ;
		PORT
			LAYER metal1 ;
			RECT 16.357 16.356 16.357 16.356 ;
			END
		END OP38
	PIN OP39
		DIRECTION OUTPUT ;
		USE SIGNAL ;
		PORT
			LAYER metal1 ;
			RECT 16.357 16.356 16.357 16.356 ;
			END
		END OP39
	PIN OP40
		DIRECTION OUTPUT ;
		USE SIGNAL ;
		PORT
			LAYER metal1 ;
			RECT 16.357 16.356 16.357 16.356 ;
			END
		END OP40
	PIN OP41
		DIRECTION OUTPUT ;
		USE SIGNAL ;
		PORT
			LAYER metal1 ;
			RECT 16.357 16.356 16.357 16.356 ;
			END
		END OP41
	PIN OP42
		DIRECTION OUTPUT ;
		USE SIGNAL ;
		PORT
			LAYER metal1 ;
			RECT 16.357 16.356 16.357 16.356 ;
			END
		END OP42
	PIN OP43
		DIRECTION OUTPUT ;
		USE SIGNAL ;
		PORT
			LAYER metal1 ;
			RECT 16.357 16.356 16.357 16.356 ;
			END
		END OP43
	PIN OP44
		DIRECTION OUTPUT ;
		USE SIGNAL ;
		PORT
			LAYER metal1 ;
			RECT 16.357 16.356 16.357 16.356 ;
			END
		END OP44
	PIN OP45
		DIRECTION OUTPUT ;
		USE SIGNAL ;
		PORT
			LAYER metal1 ;
			RECT 16.357 16.356 16.357 16.356 ;
			END
		END OP45
	PIN OP46
		DIRECTION OUTPUT ;
		USE SIGNAL ;
		PORT
			LAYER metal1 ;
			RECT 16.357 16.356 16.357 16.356 ;
			END
		END OP46
	PIN OP47
		DIRECTION OUTPUT ;
		USE SIGNAL ;
		PORT
			LAYER metal1 ;
			RECT 16.357 16.356 16.357 16.356 ;
			END
		END OP47
	PIN OP48
		DIRECTION OUTPUT ;
		USE SIGNAL ;
		PORT
			LAYER metal1 ;
			RECT 16.357 16.356 16.357 16.356 ;
			END
		END OP48
	PIN OP49
		DIRECTION OUTPUT ;
		USE SIGNAL ;
		PORT
			LAYER metal1 ;
			RECT 16.357 16.356 16.357 16.356 ;
			END
		END OP49
	PIN OP50
		DIRECTION OUTPUT ;
		USE SIGNAL ;
		PORT
			LAYER metal1 ;
			RECT 16.357 16.356 16.357 16.356 ;
			END
		END OP50
	PIN OP51
		DIRECTION OUTPUT ;
		USE SIGNAL ;
		PORT
			LAYER metal1 ;
			RECT 16.357 16.356 16.357 16.356 ;
			END
		END OP51
	PIN IP0
		DIRECTION INPUT ;
		USE SIGNAL ;
		PORT
			LAYER metal1 ;
			RECT 16.357 16.356 16.357 16.356 ;
			END
		END IP0
	PIN IP1
		DIRECTION INPUT ;
		USE SIGNAL ;
		PORT
			LAYER metal1 ;
			RECT 16.357 16.356 16.357 16.356 ;
			END
		END IP1
	PIN IP2
		DIRECTION INPUT ;
		USE SIGNAL ;
		PORT
			LAYER metal1 ;
			RECT 16.357 16.356 16.357 16.356 ;
			END
		END IP2
	PIN IP3
		DIRECTION INPUT ;
		USE SIGNAL ;
		PORT
			LAYER metal1 ;
			RECT 16.357 16.356 16.357 16.356 ;
			END
		END IP3
	PIN IP4
		DIRECTION INPUT ;
		USE SIGNAL ;
		PORT
			LAYER metal1 ;
			RECT 16.357 16.356 16.357 16.356 ;
			END
		END IP4
	PIN IP5
		DIRECTION INPUT ;
		USE SIGNAL ;
		PORT
			LAYER metal1 ;
			RECT 16.357 16.356 16.357 16.356 ;
			END
		END IP5
	PIN IP6
		DIRECTION INPUT ;
		USE SIGNAL ;
		PORT
			LAYER metal1 ;
			RECT 16.357 16.356 16.357 16.356 ;
			END
		END IP6
	PIN IP7
		DIRECTION INPUT ;
		USE SIGNAL ;
		PORT
			LAYER metal1 ;
			RECT 16.357 16.356 16.357 16.356 ;
			END
		END IP7
	PIN IP8
		DIRECTION INPUT ;
		USE SIGNAL ;
		PORT
			LAYER metal1 ;
			RECT 16.357 16.356 16.357 16.356 ;
			END
		END IP8
	PIN IP9
		DIRECTION INPUT ;
		USE SIGNAL ;
		PORT
			LAYER metal1 ;
			RECT 16.357 16.356 16.357 16.356 ;
			END
		END IP9
	PIN IP10
		DIRECTION INPUT ;
		USE SIGNAL ;
		PORT
			LAYER metal1 ;
			RECT 16.357 16.356 16.357 16.356 ;
			END
		END IP10
	PIN IP11
		DIRECTION INPUT ;
		USE SIGNAL ;
		PORT
			LAYER metal1 ;
			RECT 16.357 16.356 16.357 16.356 ;
			END
		END IP11
	PIN IP12
		DIRECTION INPUT ;
		USE SIGNAL ;
		PORT
			LAYER metal1 ;
			RECT 16.357 16.356 16.357 16.356 ;
			END
		END IP12
END cluster_10
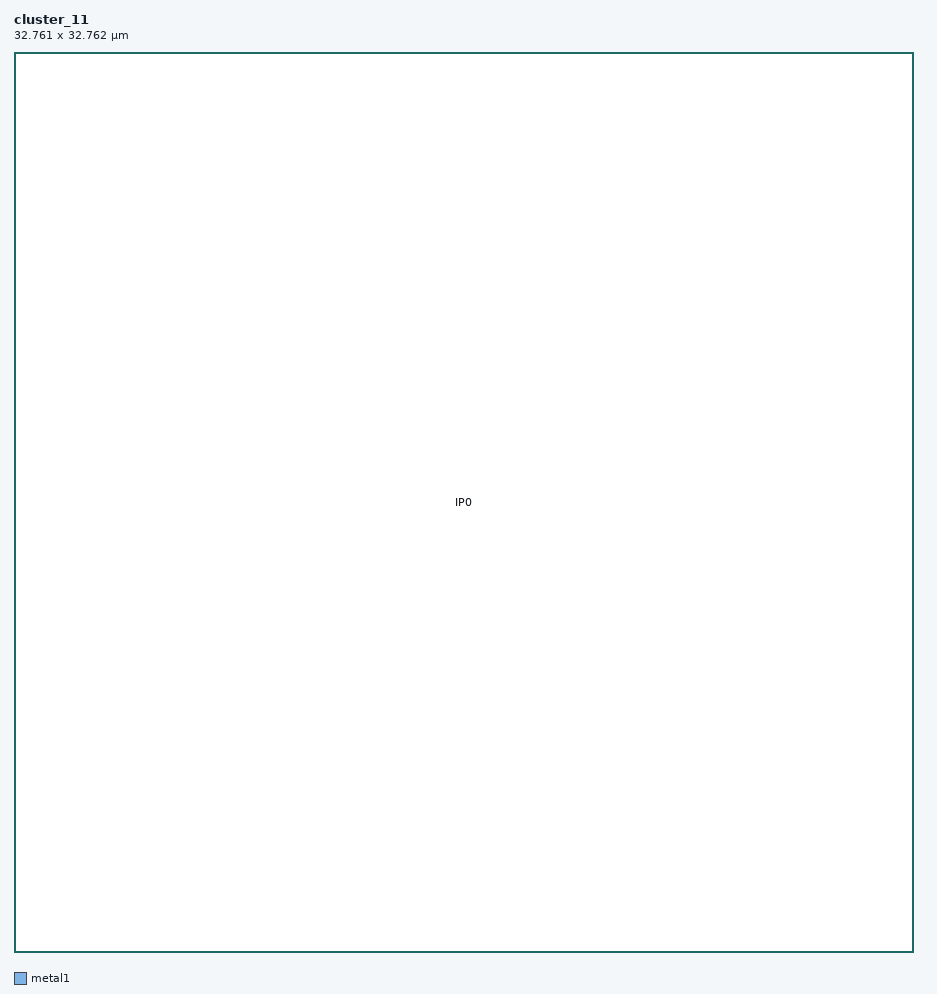
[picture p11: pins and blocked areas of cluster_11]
MACRO cluster_11
	CLASS BLOCK ;
	ORIGIN 0 0 ;
	FOREIGN cluster_11 0 0 ;
	SIZE 32.761 BY 32.762 ;
	SYMMETRY X Y ;
	PIN OP0
		DIRECTION OUTPUT ;
		USE SIGNAL ;
		PORT
			LAYER metal1 ;
			RECT 16.381 16.381 16.381 16.381 ;
			END
		END OP0
	PIN OP1
		DIRECTION OUTPUT ;
		USE SIGNAL ;
		PORT
			LAYER metal1 ;
			RECT 16.381 16.381 16.381 16.381 ;
			END
		END OP1
	PIN OP2
		DIRECTION OUTPUT ;
		USE SIGNAL ;
		PORT
			LAYER metal1 ;
			RECT 16.381 16.381 16.381 16.381 ;
			END
		END OP2
	PIN OP3
		DIRECTION OUTPUT ;
		USE SIGNAL ;
		PORT
			LAYER metal1 ;
			RECT 16.381 16.381 16.381 16.381 ;
			END
		END OP3
	PIN OP4
		DIRECTION OUTPUT ;
		USE SIGNAL ;
		PORT
			LAYER metal1 ;
			RECT 16.381 16.381 16.381 16.381 ;
			END
		END OP4
	PIN OP5
		DIRECTION OUTPUT ;
		USE SIGNAL ;
		PORT
			LAYER metal1 ;
			RECT 16.381 16.381 16.381 16.381 ;
			END
		END OP5
	PIN OP6
		DIRECTION OUTPUT ;
		USE SIGNAL ;
		PORT
			LAYER metal1 ;
			RECT 16.381 16.381 16.381 16.381 ;
			END
		END OP6
	PIN OP7
		DIRECTION OUTPUT ;
		USE SIGNAL ;
		PORT
			LAYER metal1 ;
			RECT 16.381 16.381 16.381 16.381 ;
			END
		END OP7
	PIN OP8
		DIRECTION OUTPUT ;
		USE SIGNAL ;
		PORT
			LAYER metal1 ;
			RECT 16.381 16.381 16.381 16.381 ;
			END
		END OP8
	PIN OP9
		DIRECTION OUTPUT ;
		USE SIGNAL ;
		PORT
			LAYER metal1 ;
			RECT 16.381 16.381 16.381 16.381 ;
			END
		END OP9
	PIN OP10
		DIRECTION OUTPUT ;
		USE SIGNAL ;
		PORT
			LAYER metal1 ;
			RECT 16.381 16.381 16.381 16.381 ;
			END
		END OP10
	PIN OP11
		DIRECTION OUTPUT ;
		USE SIGNAL ;
		PORT
			LAYER metal1 ;
			RECT 16.381 16.381 16.381 16.381 ;
			END
		END OP11
	PIN OP12
		DIRECTION OUTPUT ;
		USE SIGNAL ;
		PORT
			LAYER metal1 ;
			RECT 16.381 16.381 16.381 16.381 ;
			END
		END OP12
	PIN OP13
		DIRECTION OUTPUT ;
		USE SIGNAL ;
		PORT
			LAYER metal1 ;
			RECT 16.381 16.381 16.381 16.381 ;
			END
		END OP13
	PIN OP14
		DIRECTION OUTPUT ;
		USE SIGNAL ;
		PORT
			LAYER metal1 ;
			RECT 16.381 16.381 16.381 16.381 ;
			END
		END OP14
	PIN OP15
		DIRECTION OUTPUT ;
		USE SIGNAL ;
		PORT
			LAYER metal1 ;
			RECT 16.381 16.381 16.381 16.381 ;
			END
		END OP15
	PIN OP16
		DIRECTION OUTPUT ;
		USE SIGNAL ;
		PORT
			LAYER metal1 ;
			RECT 16.381 16.381 16.381 16.381 ;
			END
		END OP16
	PIN OP17
		DIRECTION OUTPUT ;
		USE SIGNAL ;
		PORT
			LAYER metal1 ;
			RECT 16.381 16.381 16.381 16.381 ;
			END
		END OP17
	PIN OP18
		DIRECTION OUTPUT ;
		USE SIGNAL ;
		PORT
			LAYER metal1 ;
			RECT 16.381 16.381 16.381 16.381 ;
			END
		END OP18
	PIN OP19
		DIRECTION OUTPUT ;
		USE SIGNAL ;
		PORT
			LAYER metal1 ;
			RECT 16.381 16.381 16.381 16.381 ;
			END
		END OP19
	PIN OP20
		DIRECTION OUTPUT ;
		USE SIGNAL ;
		PORT
			LAYER metal1 ;
			RECT 16.381 16.381 16.381 16.381 ;
			END
		END OP20
	PIN OP21
		DIRECTION OUTPUT ;
		USE SIGNAL ;
		PORT
			LAYER metal1 ;
			RECT 16.381 16.381 16.381 16.381 ;
			END
		END OP21
	PIN OP22
		DIRECTION OUTPUT ;
		USE SIGNAL ;
		PORT
			LAYER metal1 ;
			RECT 16.381 16.381 16.381 16.381 ;
			END
		END OP22
	PIN OP23
		DIRECTION OUTPUT ;
		USE SIGNAL ;
		PORT
			LAYER metal1 ;
			RECT 16.381 16.381 16.381 16.381 ;
			END
		END OP23
	PIN OP24
		DIRECTION OUTPUT ;
		USE SIGNAL ;
		PORT
			LAYER metal1 ;
			RECT 16.381 16.381 16.381 16.381 ;
			END
		END OP24
	PIN OP25
		DIRECTION OUTPUT ;
		USE SIGNAL ;
		PORT
			LAYER metal1 ;
			RECT 16.381 16.381 16.381 16.381 ;
			END
		END OP25
	PIN OP26
		DIRECTION OUTPUT ;
		USE SIGNAL ;
		PORT
			LAYER metal1 ;
			RECT 16.381 16.381 16.381 16.381 ;
			END
		END OP26
	PIN OP27
		DIRECTION OUTPUT ;
		USE SIGNAL ;
		PORT
			LAYER metal1 ;
			RECT 16.381 16.381 16.381 16.381 ;
			END
		END OP27
	PIN OP28
		DIRECTION OUTPUT ;
		USE SIGNAL ;
		PORT
			LAYER metal1 ;
			RECT 16.381 16.381 16.381 16.381 ;
			END
		END OP28
	PIN OP29
		DIRECTION OUTPUT ;
		USE SIGNAL ;
		PORT
			LAYER metal1 ;
			RECT 16.381 16.381 16.381 16.381 ;
			END
		END OP29
	PIN OP30
		DIRECTION OUTPUT ;
		USE SIGNAL ;
		PORT
			LAYER metal1 ;
			RECT 16.381 16.381 16.381 16.381 ;
			END
		END OP30
	PIN OP31
		DIRECTION OUTPUT ;
		USE SIGNAL ;
		PORT
			LAYER metal1 ;
			RECT 16.381 16.381 16.381 16.381 ;
			END
		END OP31
	PIN OP32
		DIRECTION OUTPUT ;
		USE SIGNAL ;
		PORT
			LAYER metal1 ;
			RECT 16.381 16.381 16.381 16.381 ;
			END
		END OP32
	PIN OP33
		DIRECTION OUTPUT ;
		USE SIGNAL ;
		PORT
			LAYER metal1 ;
			RECT 16.381 16.381 16.381 16.381 ;
			END
		END OP33
	PIN OP34
		DIRECTION OUTPUT ;
		USE SIGNAL ;
		PORT
			LAYER metal1 ;
			RECT 16.381 16.381 16.381 16.381 ;
			END
		END OP34
	PIN OP35
		DIRECTION OUTPUT ;
		USE SIGNAL ;
		PORT
			LAYER metal1 ;
			RECT 16.381 16.381 16.381 16.381 ;
			END
		END OP35
	PIN OP36
		DIRECTION OUTPUT ;
		USE SIGNAL ;
		PORT
			LAYER metal1 ;
			RECT 16.381 16.381 16.381 16.381 ;
			END
		END OP36
	PIN OP37
		DIRECTION OUTPUT ;
		USE SIGNAL ;
		PORT
			LAYER metal1 ;
			RECT 16.381 16.381 16.381 16.381 ;
			END
		END OP37
	PIN OP38
		DIRECTION OUTPUT ;
		USE SIGNAL ;
		PORT
			LAYER metal1 ;
			RECT 16.381 16.381 16.381 16.381 ;
			END
		END OP38
	PIN OP39
		DIRECTION OUTPUT ;
		USE SIGNAL ;
		PORT
			LAYER metal1 ;
			RECT 16.381 16.381 16.381 16.381 ;
			END
		END OP39
	PIN OP40
		DIRECTION OUTPUT ;
		USE SIGNAL ;
		PORT
			LAYER metal1 ;
			RECT 16.381 16.381 16.381 16.381 ;
			END
		END OP40
	PIN OP41
		DIRECTION OUTPUT ;
		USE SIGNAL ;
		PORT
			LAYER metal1 ;
			RECT 16.381 16.381 16.381 16.381 ;
			END
		END OP41
	PIN OP42
		DIRECTION OUTPUT ;
		USE SIGNAL ;
		PORT
			LAYER metal1 ;
			RECT 16.381 16.381 16.381 16.381 ;
			END
		END OP42
	PIN OP43
		DIRECTION OUTPUT ;
		USE SIGNAL ;
		PORT
			LAYER metal1 ;
			RECT 16.381 16.381 16.381 16.381 ;
			END
		END OP43
	PIN OP44
		DIRECTION OUTPUT ;
		USE SIGNAL ;
		PORT
			LAYER metal1 ;
			RECT 16.381 16.381 16.381 16.381 ;
			END
		END OP44
	PIN OP45
		DIRECTION OUTPUT ;
		USE SIGNAL ;
		PORT
			LAYER metal1 ;
			RECT 16.381 16.381 16.381 16.381 ;
			END
		END OP45
	PIN OP46
		DIRECTION OUTPUT ;
		USE SIGNAL ;
		PORT
			LAYER metal1 ;
			RECT 16.381 16.381 16.381 16.381 ;
			END
		END OP46
	PIN OP47
		DIRECTION OUTPUT ;
		USE SIGNAL ;
		PORT
			LAYER metal1 ;
			RECT 16.381 16.381 16.381 16.381 ;
			END
		END OP47
	PIN OP48
		DIRECTION OUTPUT ;
		USE SIGNAL ;
		PORT
			LAYER metal1 ;
			RECT 16.381 16.381 16.381 16.381 ;
			END
		END OP48
	PIN IP0
		DIRECTION INPUT ;
		USE SIGNAL ;
		PORT
			LAYER metal1 ;
			RECT 16.381 16.381 16.381 16.381 ;
			END
		END IP0
	PIN IP1
		DIRECTION INPUT ;
		USE SIGNAL ;
		PORT
			LAYER metal1 ;
			RECT 16.381 16.381 16.381 16.381 ;
			END
		END IP1
	PIN IP2
		DIRECTION INPUT ;
		USE SIGNAL ;
		PORT
			LAYER metal1 ;
			RECT 16.381 16.381 16.381 16.381 ;
			END
		END IP2
	PIN IP3
		DIRECTION INPUT ;
		USE SIGNAL ;
		PORT
			LAYER metal1 ;
			RECT 16.381 16.381 16.381 16.381 ;
			END
		END IP3
	PIN IP4
		DIRECTION INPUT ;
		USE SIGNAL ;
		PORT
			LAYER metal1 ;
			RECT 16.381 16.381 16.381 16.381 ;
			END
		END IP4
	PIN IP5
		DIRECTION INPUT ;
		USE SIGNAL ;
		PORT
			LAYER metal1 ;
			RECT 16.381 16.381 16.381 16.381 ;
			END
		END IP5
	PIN IP6
		DIRECTION INPUT ;
		USE SIGNAL ;
		PORT
			LAYER metal1 ;
			RECT 16.381 16.381 16.381 16.381 ;
			END
		END IP6
	PIN IP7
		DIRECTION INPUT ;
		USE SIGNAL ;
		PORT
			LAYER metal1 ;
			RECT 16.381 16.381 16.381 16.381 ;
			END
		END IP7
	PIN IP8
		DIRECTION INPUT ;
		USE SIGNAL ;
		PORT
			LAYER metal1 ;
			RECT 16.381 16.381 16.381 16.381 ;
			END
		END IP8
	PIN IP9
		DIRECTION INPUT ;
		USE SIGNAL ;
		PORT
			LAYER metal1 ;
			RECT 16.381 16.381 16.381 16.381 ;
			END
		END IP9
	PIN IP10
		DIRECTION INPUT ;
		USE SIGNAL ;
		PORT
			LAYER metal1 ;
			RECT 16.381 16.381 16.381 16.381 ;
			END
		END IP10
	PIN IP11
		DIRECTION INPUT ;
		USE SIGNAL ;
		PORT
			LAYER metal1 ;
			RECT 16.381 16.381 16.381 16.381 ;
			END
		END IP11
	PIN IP12
		DIRECTION INPUT ;
		USE SIGNAL ;
		PORT
			LAYER metal1 ;
			RECT 16.381 16.381 16.381 16.381 ;
			END
		END IP12
	PIN IP13
		DIRECTION INPUT ;
		USE SIGNAL ;
		PORT
			LAYER metal1 ;
			RECT 16.381 16.381 16.381 16.381 ;
			END
		END IP13
	PIN IP14
		DIRECTION INPUT ;
		USE SIGNAL ;
		PORT
			LAYER metal1 ;
			RECT 16.381 16.381 16.381 16.381 ;
			END
		END IP14
	PIN IP15
		DIRECTION INPUT ;
		USE SIGNAL ;
		PORT
			LAYER metal1 ;
			RECT 16.381 16.381 16.381 16.381 ;
			END
		END IP15
	PIN IP16
		DIRECTION INPUT ;
		USE SIGNAL ;
		PORT
			LAYER metal1 ;
			RECT 16.381 16.381 16.381 16.381 ;
			END
		END IP16
	PIN IP17
		DIRECTION INPUT ;
		USE SIGNAL ;
		PORT
			LAYER metal1 ;
			RECT 16.381 16.381 16.381 16.381 ;
			END
		END IP17
	PIN IP18
		DIRECTION INPUT ;
		USE SIGNAL ;
		PORT
			LAYER metal1 ;
			RECT 16.381 16.381 16.381 16.381 ;
			END
		END IP18
	PIN IP19
		DIRECTION INPUT ;
		USE SIGNAL ;
		PORT
			LAYER metal1 ;
			RECT 16.381 16.381 16.381 16.381 ;
			END
		END IP19
	PIN IP20
		DIRECTION INPUT ;
		USE SIGNAL ;
		PORT
			LAYER metal1 ;
			RECT 16.381 16.381 16.381 16.381 ;
			END
		END IP20
END cluster_11
MACRO cluster_12
	CLASS BLOCK ;
	ORIGIN 0 0 ;
	FOREIGN cluster_12 0 0 ;
	SIZE 32.151 BY 32.151 ;
	SYMMETRY X Y ;
	PIN OP0
		DIRECTION OUTPUT ;
		USE SIGNAL ;
		PORT
			LAYER metal1 ;
			RECT 16.076 16.076 16.076 16.076 ;
			END
		END OP0
	PIN OP1
		DIRECTION OUTPUT ;
		USE SIGNAL ;
		PORT
			LAYER metal1 ;
			RECT 16.076 16.076 16.076 16.076 ;
			END
		END OP1
	PIN OP2
		DIRECTION OUTPUT ;
		USE SIGNAL ;
		PORT
			LAYER metal1 ;
			RECT 16.076 16.076 16.076 16.076 ;
			END
		END OP2
	PIN OP3
		DIRECTION OUTPUT ;
		USE SIGNAL ;
		PORT
			LAYER metal1 ;
			RECT 16.076 16.076 16.076 16.076 ;
			END
		END OP3
	PIN OP4
		DIRECTION OUTPUT ;
		USE SIGNAL ;
		PORT
			LAYER metal1 ;
			RECT 16.076 16.076 16.076 16.076 ;
			END
		END OP4
	PIN OP5
		DIRECTION OUTPUT ;
		USE SIGNAL ;
		PORT
			LAYER metal1 ;
			RECT 16.076 16.076 16.076 16.076 ;
			END
		END OP5
	PIN OP6
		DIRECTION OUTPUT ;
		USE SIGNAL ;
		PORT
			LAYER metal1 ;
			RECT 16.076 16.076 16.076 16.076 ;
			END
		END OP6
	PIN OP7
		DIRECTION OUTPUT ;
		USE SIGNAL ;
		PORT
			LAYER metal1 ;
			RECT 16.076 16.076 16.076 16.076 ;
			END
		END OP7
	PIN OP8
		DIRECTION OUTPUT ;
		USE SIGNAL ;
		PORT
			LAYER metal1 ;
			RECT 16.076 16.076 16.076 16.076 ;
			END
		END OP8
	PIN OP9
		DIRECTION OUTPUT ;
		USE SIGNAL ;
		PORT
			LAYER metal1 ;
			RECT 16.076 16.076 16.076 16.076 ;
			END
		END OP9
	PIN OP10
		DIRECTION OUTPUT ;
		USE SIGNAL ;
		PORT
			LAYER metal1 ;
			RECT 16.076 16.076 16.076 16.076 ;
			END
		END OP10
	PIN OP11
		DIRECTION OUTPUT ;
		USE SIGNAL ;
		PORT
			LAYER metal1 ;
			RECT 16.076 16.076 16.076 16.076 ;
			END
		END OP11
	PIN OP12
		DIRECTION OUTPUT ;
		USE SIGNAL ;
		PORT
			LAYER metal1 ;
			RECT 16.076 16.076 16.076 16.076 ;
			END
		END OP12
	PIN OP13
		DIRECTION OUTPUT ;
		USE SIGNAL ;
		PORT
			LAYER metal1 ;
			RECT 16.076 16.076 16.076 16.076 ;
			END
		END OP13
	PIN OP14
		DIRECTION OUTPUT ;
		USE SIGNAL ;
		PORT
			LAYER metal1 ;
			RECT 16.076 16.076 16.076 16.076 ;
			END
		END OP14
	PIN OP15
		DIRECTION OUTPUT ;
		USE SIGNAL ;
		PORT
			LAYER metal1 ;
			RECT 16.076 16.076 16.076 16.076 ;
			END
		END OP15
	PIN OP16
		DIRECTION OUTPUT ;
		USE SIGNAL ;
		PORT
			LAYER metal1 ;
			RECT 16.076 16.076 16.076 16.076 ;
			END
		END OP16
	PIN OP17
		DIRECTION OUTPUT ;
		USE SIGNAL ;
		PORT
			LAYER metal1 ;
			RECT 16.076 16.076 16.076 16.076 ;
			END
		END OP17
	PIN OP18
		DIRECTION OUTPUT ;
		USE SIGNAL ;
		PORT
			LAYER metal1 ;
			RECT 16.076 16.076 16.076 16.076 ;
			END
		END OP18
	PIN OP19
		DIRECTION OUTPUT ;
		USE SIGNAL ;
		PORT
			LAYER metal1 ;
			RECT 16.076 16.076 16.076 16.076 ;
			END
		END OP19
	PIN OP20
		DIRECTION OUTPUT ;
		USE SIGNAL ;
		PORT
			LAYER metal1 ;
			RECT 16.076 16.076 16.076 16.076 ;
			END
		END OP20
	PIN OP21
		DIRECTION OUTPUT ;
		USE SIGNAL ;
		PORT
			LAYER metal1 ;
			RECT 16.076 16.076 16.076 16.076 ;
			END
		END OP21
	PIN OP22
		DIRECTION OUTPUT ;
		USE SIGNAL ;
		PORT
			LAYER metal1 ;
			RECT 16.076 16.076 16.076 16.076 ;
			END
		END OP22
	PIN OP23
		DIRECTION OUTPUT ;
		USE SIGNAL ;
		PORT
			LAYER metal1 ;
			RECT 16.076 16.076 16.076 16.076 ;
			END
		END OP23
	PIN OP24
		DIRECTION OUTPUT ;
		USE SIGNAL ;
		PORT
			LAYER metal1 ;
			RECT 16.076 16.076 16.076 16.076 ;
			END
		END OP24
	PIN OP25
		DIRECTION OUTPUT ;
		USE SIGNAL ;
		PORT
			LAYER metal1 ;
			RECT 16.076 16.076 16.076 16.076 ;
			END
		END OP25
	PIN OP26
		DIRECTION OUTPUT ;
		USE SIGNAL ;
		PORT
			LAYER metal1 ;
			RECT 16.076 16.076 16.076 16.076 ;
			END
		END OP26
	PIN OP27
		DIRECTION OUTPUT ;
		USE SIGNAL ;
		PORT
			LAYER metal1 ;
			RECT 16.076 16.076 16.076 16.076 ;
			END
		END OP27
	PIN OP28
		DIRECTION OUTPUT ;
		USE SIGNAL ;
		PORT
			LAYER metal1 ;
			RECT 16.076 16.076 16.076 16.076 ;
			END
		END OP28
	PIN OP29
		DIRECTION OUTPUT ;
		USE SIGNAL ;
		PORT
			LAYER metal1 ;
			RECT 16.076 16.076 16.076 16.076 ;
			END
		END OP29
	PIN OP30
		DIRECTION OUTPUT ;
		USE SIGNAL ;
		PORT
			LAYER metal1 ;
			RECT 16.076 16.076 16.076 16.076 ;
			END
		END OP30
	PIN OP31
		DIRECTION OUTPUT ;
		USE SIGNAL ;
		PORT
			LAYER metal1 ;
			RECT 16.076 16.076 16.076 16.076 ;
			END
		END OP31
	PIN OP32
		DIRECTION OUTPUT ;
		USE SIGNAL ;
		PORT
			LAYER metal1 ;
			RECT 16.076 16.076 16.076 16.076 ;
			END
		END OP32
	PIN OP33
		DIRECTION OUTPUT ;
		USE SIGNAL ;
		PORT
			LAYER metal1 ;
			RECT 16.076 16.076 16.076 16.076 ;
			END
		END OP33
	PIN OP34
		DIRECTION OUTPUT ;
		USE SIGNAL ;
		PORT
			LAYER metal1 ;
			RECT 16.076 16.076 16.076 16.076 ;
			END
		END OP34
	PIN OP35
		DIRECTION OUTPUT ;
		USE SIGNAL ;
		PORT
			LAYER metal1 ;
			RECT 16.076 16.076 16.076 16.076 ;
			END
		END OP35
	PIN OP36
		DIRECTION OUTPUT ;
		USE SIGNAL ;
		PORT
			LAYER metal1 ;
			RECT 16.076 16.076 16.076 16.076 ;
			END
		END OP36
	PIN OP37
		DIRECTION OUTPUT ;
		USE SIGNAL ;
		PORT
			LAYER metal1 ;
			RECT 16.076 16.076 16.076 16.076 ;
			END
		END OP37
	PIN OP38
		DIRECTION OUTPUT ;
		USE SIGNAL ;
		PORT
			LAYER metal1 ;
			RECT 16.076 16.076 16.076 16.076 ;
			END
		END OP38
	PIN OP39
		DIRECTION OUTPUT ;
		USE SIGNAL ;
		PORT
			LAYER metal1 ;
			RECT 16.076 16.076 16.076 16.076 ;
			END
		END OP39
	PIN OP40
		DIRECTION OUTPUT ;
		USE SIGNAL ;
		PORT
			LAYER metal1 ;
			RECT 16.076 16.076 16.076 16.076 ;
			END
		END OP40
	PIN OP41
		DIRECTION OUTPUT ;
		USE SIGNAL ;
		PORT
			LAYER metal1 ;
			RECT 16.076 16.076 16.076 16.076 ;
			END
		END OP41
	PIN OP42
		DIRECTION OUTPUT ;
		USE SIGNAL ;
		PORT
			LAYER metal1 ;
			RECT 16.076 16.076 16.076 16.076 ;
			END
		END OP42
	PIN OP43
		DIRECTION OUTPUT ;
		USE SIGNAL ;
		PORT
			LAYER metal1 ;
			RECT 16.076 16.076 16.076 16.076 ;
			END
		END OP43
	PIN OP44
		DIRECTION OUTPUT ;
		USE SIGNAL ;
		PORT
			LAYER metal1 ;
			RECT 16.076 16.076 16.076 16.076 ;
			END
		END OP44
	PIN OP45
		DIRECTION OUTPUT ;
		USE SIGNAL ;
		PORT
			LAYER metal1 ;
			RECT 16.076 16.076 16.076 16.076 ;
			END
		END OP45
	PIN OP46
		DIRECTION OUTPUT ;
		USE SIGNAL ;
		PORT
			LAYER metal1 ;
			RECT 16.076 16.076 16.076 16.076 ;
			END
		END OP46
	PIN OP47
		DIRECTION OUTPUT ;
		USE SIGNAL ;
		PORT
			LAYER metal1 ;
			RECT 16.076 16.076 16.076 16.076 ;
			END
		END OP47
	PIN OP48
		DIRECTION OUTPUT ;
		USE SIGNAL ;
		PORT
			LAYER metal1 ;
			RECT 16.076 16.076 16.076 16.076 ;
			END
		END OP48
	PIN OP49
		DIRECTION OUTPUT ;
		USE SIGNAL ;
		PORT
			LAYER metal1 ;
			RECT 16.076 16.076 16.076 16.076 ;
			END
		END OP49
	PIN OP50
		DIRECTION OUTPUT ;
		USE SIGNAL ;
		PORT
			LAYER metal1 ;
			RECT 16.076 16.076 16.076 16.076 ;
			END
		END OP50
	PIN IP0
		DIRECTION INPUT ;
		USE SIGNAL ;
		PORT
			LAYER metal1 ;
			RECT 16.076 16.076 16.076 16.076 ;
			END
		END IP0
	PIN IP1
		DIRECTION INPUT ;
		USE SIGNAL ;
		PORT
			LAYER metal1 ;
			RECT 16.076 16.076 16.076 16.076 ;
			END
		END IP1
	PIN IP2
		DIRECTION INPUT ;
		USE SIGNAL ;
		PORT
			LAYER metal1 ;
			RECT 16.076 16.076 16.076 16.076 ;
			END
		END IP2
	PIN IP3
		DIRECTION INPUT ;
		USE SIGNAL ;
		PORT
			LAYER metal1 ;
			RECT 16.076 16.076 16.076 16.076 ;
			END
		END IP3
	PIN IP4
		DIRECTION INPUT ;
		USE SIGNAL ;
		PORT
			LAYER metal1 ;
			RECT 16.076 16.076 16.076 16.076 ;
			END
		END IP4
	PIN IP5
		DIRECTION INPUT ;
		USE SIGNAL ;
		PORT
			LAYER metal1 ;
			RECT 16.076 16.076 16.076 16.076 ;
			END
		END IP5
	PIN IP6
		DIRECTION INPUT ;
		USE SIGNAL ;
		PORT
			LAYER metal1 ;
			RECT 16.076 16.076 16.076 16.076 ;
			END
		END IP6
	PIN IP7
		DIRECTION INPUT ;
		USE SIGNAL ;
		PORT
			LAYER metal1 ;
			RECT 16.076 16.076 16.076 16.076 ;
			END
		END IP7
	PIN IP8
		DIRECTION INPUT ;
		USE SIGNAL ;
		PORT
			LAYER metal1 ;
			RECT 16.076 16.076 16.076 16.076 ;
			END
		END IP8
	PIN IP9
		DIRECTION INPUT ;
		USE SIGNAL ;
		PORT
			LAYER metal1 ;
			RECT 16.076 16.076 16.076 16.076 ;
			END
		END IP9
	PIN IP10
		DIRECTION INPUT ;
		USE SIGNAL ;
		PORT
			LAYER metal1 ;
			RECT 16.076 16.076 16.076 16.076 ;
			END
		END IP10
	PIN IP11
		DIRECTION INPUT ;
		USE SIGNAL ;
		PORT
			LAYER metal1 ;
			RECT 16.076 16.076 16.076 16.076 ;
			END
		END IP11
	PIN IP12
		DIRECTION INPUT ;
		USE SIGNAL ;
		PORT
			LAYER metal1 ;
			RECT 16.076 16.076 16.076 16.076 ;
			END
		END IP12
	PIN IP13
		DIRECTION INPUT ;
		USE SIGNAL ;
		PORT
			LAYER metal1 ;
			RECT 16.076 16.076 16.076 16.076 ;
			END
		END IP13
	PIN IP14
		DIRECTION INPUT ;
		USE SIGNAL ;
		PORT
			LAYER metal1 ;
			RECT 16.076 16.076 16.076 16.076 ;
			END
		END IP14
END cluster_12
MACRO cluster_13
	CLASS BLOCK ;
	ORIGIN 0 0 ;
	FOREIGN cluster_13 0 0 ;
	SIZE 33.008 BY 33.008 ;
	SYMMETRY X Y ;
	PIN OP0
		DIRECTION OUTPUT ;
		USE SIGNAL ;
		PORT
			LAYER metal1 ;
			RECT 16.504 16.504 16.504 16.504 ;
			END
		END OP0
	PIN OP1
		DIRECTION OUTPUT ;
		USE SIGNAL ;
		PORT
			LAYER metal1 ;
			RECT 16.504 16.504 16.504 16.504 ;
			END
		END OP1
	PIN OP2
		DIRECTION OUTPUT ;
		USE SIGNAL ;
		PORT
			LAYER metal1 ;
			RECT 16.504 16.504 16.504 16.504 ;
			END
		END OP2
	PIN OP3
		DIRECTION OUTPUT ;
		USE SIGNAL ;
		PORT
			LAYER metal1 ;
			RECT 16.504 16.504 16.504 16.504 ;
			END
		END OP3
	PIN OP4
		DIRECTION OUTPUT ;
		USE SIGNAL ;
		PORT
			LAYER metal1 ;
			RECT 16.504 16.504 16.504 16.504 ;
			END
		END OP4
	PIN OP5
		DIRECTION OUTPUT ;
		USE SIGNAL ;
		PORT
			LAYER metal1 ;
			RECT 16.504 16.504 16.504 16.504 ;
			END
		END OP5
	PIN OP6
		DIRECTION OUTPUT ;
		USE SIGNAL ;
		PORT
			LAYER metal1 ;
			RECT 16.504 16.504 16.504 16.504 ;
			END
		END OP6
	PIN OP7
		DIRECTION OUTPUT ;
		USE SIGNAL ;
		PORT
			LAYER metal1 ;
			RECT 16.504 16.504 16.504 16.504 ;
			END
		END OP7
	PIN OP8
		DIRECTION OUTPUT ;
		USE SIGNAL ;
		PORT
			LAYER metal1 ;
			RECT 16.504 16.504 16.504 16.504 ;
			END
		END OP8
	PIN OP9
		DIRECTION OUTPUT ;
		USE SIGNAL ;
		PORT
			LAYER metal1 ;
			RECT 16.504 16.504 16.504 16.504 ;
			END
		END OP9
	PIN OP10
		DIRECTION OUTPUT ;
		USE SIGNAL ;
		PORT
			LAYER metal1 ;
			RECT 16.504 16.504 16.504 16.504 ;
			END
		END OP10
	PIN OP11
		DIRECTION OUTPUT ;
		USE SIGNAL ;
		PORT
			LAYER metal1 ;
			RECT 16.504 16.504 16.504 16.504 ;
			END
		END OP11
	PIN OP12
		DIRECTION OUTPUT ;
		USE SIGNAL ;
		PORT
			LAYER metal1 ;
			RECT 16.504 16.504 16.504 16.504 ;
			END
		END OP12
	PIN OP13
		DIRECTION OUTPUT ;
		USE SIGNAL ;
		PORT
			LAYER metal1 ;
			RECT 16.504 16.504 16.504 16.504 ;
			END
		END OP13
	PIN OP14
		DIRECTION OUTPUT ;
		USE SIGNAL ;
		PORT
			LAYER metal1 ;
			RECT 16.504 16.504 16.504 16.504 ;
			END
		END OP14
	PIN OP15
		DIRECTION OUTPUT ;
		USE SIGNAL ;
		PORT
			LAYER metal1 ;
			RECT 16.504 16.504 16.504 16.504 ;
			END
		END OP15
	PIN OP16
		DIRECTION OUTPUT ;
		USE SIGNAL ;
		PORT
			LAYER metal1 ;
			RECT 16.504 16.504 16.504 16.504 ;
			END
		END OP16
	PIN OP17
		DIRECTION OUTPUT ;
		USE SIGNAL ;
		PORT
			LAYER metal1 ;
			RECT 16.504 16.504 16.504 16.504 ;
			END
		END OP17
	PIN OP18
		DIRECTION OUTPUT ;
		USE SIGNAL ;
		PORT
			LAYER metal1 ;
			RECT 16.504 16.504 16.504 16.504 ;
			END
		END OP18
	PIN OP19
		DIRECTION OUTPUT ;
		USE SIGNAL ;
		PORT
			LAYER metal1 ;
			RECT 16.504 16.504 16.504 16.504 ;
			END
		END OP19
	PIN OP20
		DIRECTION OUTPUT ;
		USE SIGNAL ;
		PORT
			LAYER metal1 ;
			RECT 16.504 16.504 16.504 16.504 ;
			END
		END OP20
	PIN OP21
		DIRECTION OUTPUT ;
		USE SIGNAL ;
		PORT
			LAYER metal1 ;
			RECT 16.504 16.504 16.504 16.504 ;
			END
		END OP21
	PIN OP22
		DIRECTION OUTPUT ;
		USE SIGNAL ;
		PORT
			LAYER metal1 ;
			RECT 16.504 16.504 16.504 16.504 ;
			END
		END OP22
	PIN OP23
		DIRECTION OUTPUT ;
		USE SIGNAL ;
		PORT
			LAYER metal1 ;
			RECT 16.504 16.504 16.504 16.504 ;
			END
		END OP23
	PIN OP24
		DIRECTION OUTPUT ;
		USE SIGNAL ;
		PORT
			LAYER metal1 ;
			RECT 16.504 16.504 16.504 16.504 ;
			END
		END OP24
	PIN OP25
		DIRECTION OUTPUT ;
		USE SIGNAL ;
		PORT
			LAYER metal1 ;
			RECT 16.504 16.504 16.504 16.504 ;
			END
		END OP25
	PIN OP26
		DIRECTION OUTPUT ;
		USE SIGNAL ;
		PORT
			LAYER metal1 ;
			RECT 16.504 16.504 16.504 16.504 ;
			END
		END OP26
	PIN OP27
		DIRECTION OUTPUT ;
		USE SIGNAL ;
		PORT
			LAYER metal1 ;
			RECT 16.504 16.504 16.504 16.504 ;
			END
		END OP27
	PIN OP28
		DIRECTION OUTPUT ;
		USE SIGNAL ;
		PORT
			LAYER metal1 ;
			RECT 16.504 16.504 16.504 16.504 ;
			END
		END OP28
	PIN OP29
		DIRECTION OUTPUT ;
		USE SIGNAL ;
		PORT
			LAYER metal1 ;
			RECT 16.504 16.504 16.504 16.504 ;
			END
		END OP29
	PIN OP30
		DIRECTION OUTPUT ;
		USE SIGNAL ;
		PORT
			LAYER metal1 ;
			RECT 16.504 16.504 16.504 16.504 ;
			END
		END OP30
	PIN OP31
		DIRECTION OUTPUT ;
		USE SIGNAL ;
		PORT
			LAYER metal1 ;
			RECT 16.504 16.504 16.504 16.504 ;
			END
		END OP31
	PIN OP32
		DIRECTION OUTPUT ;
		USE SIGNAL ;
		PORT
			LAYER metal1 ;
			RECT 16.504 16.504 16.504 16.504 ;
			END
		END OP32
	PIN OP33
		DIRECTION OUTPUT ;
		USE SIGNAL ;
		PORT
			LAYER metal1 ;
			RECT 16.504 16.504 16.504 16.504 ;
			END
		END OP33
	PIN OP34
		DIRECTION OUTPUT ;
		USE SIGNAL ;
		PORT
			LAYER metal1 ;
			RECT 16.504 16.504 16.504 16.504 ;
			END
		END OP34
	PIN OP35
		DIRECTION OUTPUT ;
		USE SIGNAL ;
		PORT
			LAYER metal1 ;
			RECT 16.504 16.504 16.504 16.504 ;
			END
		END OP35
	PIN OP36
		DIRECTION OUTPUT ;
		USE SIGNAL ;
		PORT
			LAYER metal1 ;
			RECT 16.504 16.504 16.504 16.504 ;
			END
		END OP36
	PIN OP37
		DIRECTION OUTPUT ;
		USE SIGNAL ;
		PORT
			LAYER metal1 ;
			RECT 16.504 16.504 16.504 16.504 ;
			END
		END OP37
	PIN OP38
		DIRECTION OUTPUT ;
		USE SIGNAL ;
		PORT
			LAYER metal1 ;
			RECT 16.504 16.504 16.504 16.504 ;
			END
		END OP38
	PIN OP39
		DIRECTION OUTPUT ;
		USE SIGNAL ;
		PORT
			LAYER metal1 ;
			RECT 16.504 16.504 16.504 16.504 ;
			END
		END OP39
	PIN OP40
		DIRECTION OUTPUT ;
		USE SIGNAL ;
		PORT
			LAYER metal1 ;
			RECT 16.504 16.504 16.504 16.504 ;
			END
		END OP40
	PIN OP41
		DIRECTION OUTPUT ;
		USE SIGNAL ;
		PORT
			LAYER metal1 ;
			RECT 16.504 16.504 16.504 16.504 ;
			END
		END OP41
	PIN OP42
		DIRECTION OUTPUT ;
		USE SIGNAL ;
		PORT
			LAYER metal1 ;
			RECT 16.504 16.504 16.504 16.504 ;
			END
		END OP42
	PIN OP43
		DIRECTION OUTPUT ;
		USE SIGNAL ;
		PORT
			LAYER metal1 ;
			RECT 16.504 16.504 16.504 16.504 ;
			END
		END OP43
	PIN OP44
		DIRECTION OUTPUT ;
		USE SIGNAL ;
		PORT
			LAYER metal1 ;
			RECT 16.504 16.504 16.504 16.504 ;
			END
		END OP44
	PIN OP45
		DIRECTION OUTPUT ;
		USE SIGNAL ;
		PORT
			LAYER metal1 ;
			RECT 16.504 16.504 16.504 16.504 ;
			END
		END OP45
	PIN OP46
		DIRECTION OUTPUT ;
		USE SIGNAL ;
		PORT
			LAYER metal1 ;
			RECT 16.504 16.504 16.504 16.504 ;
			END
		END OP46
	PIN OP47
		DIRECTION OUTPUT ;
		USE SIGNAL ;
		PORT
			LAYER metal1 ;
			RECT 16.504 16.504 16.504 16.504 ;
			END
		END OP47
	PIN OP48
		DIRECTION OUTPUT ;
		USE SIGNAL ;
		PORT
			LAYER metal1 ;
			RECT 16.504 16.504 16.504 16.504 ;
			END
		END OP48
	PIN OP49
		DIRECTION OUTPUT ;
		USE SIGNAL ;
		PORT
			LAYER metal1 ;
			RECT 16.504 16.504 16.504 16.504 ;
			END
		END OP49
	PIN OP50
		DIRECTION OUTPUT ;
		USE SIGNAL ;
		PORT
			LAYER metal1 ;
			RECT 16.504 16.504 16.504 16.504 ;
			END
		END OP50
	PIN OP51
		DIRECTION OUTPUT ;
		USE SIGNAL ;
		PORT
			LAYER metal1 ;
			RECT 16.504 16.504 16.504 16.504 ;
			END
		END OP51
	PIN OP52
		DIRECTION OUTPUT ;
		USE SIGNAL ;
		PORT
			LAYER metal1 ;
			RECT 16.504 16.504 16.504 16.504 ;
			END
		END OP52
	PIN OP53
		DIRECTION OUTPUT ;
		USE SIGNAL ;
		PORT
			LAYER metal1 ;
			RECT 16.504 16.504 16.504 16.504 ;
			END
		END OP53
	PIN OP54
		DIRECTION OUTPUT ;
		USE SIGNAL ;
		PORT
			LAYER metal1 ;
			RECT 16.504 16.504 16.504 16.504 ;
			END
		END OP54
	PIN OP55
		DIRECTION OUTPUT ;
		USE SIGNAL ;
		PORT
			LAYER metal1 ;
			RECT 16.504 16.504 16.504 16.504 ;
			END
		END OP55
	PIN OP56
		DIRECTION OUTPUT ;
		USE SIGNAL ;
		PORT
			LAYER metal1 ;
			RECT 16.504 16.504 16.504 16.504 ;
			END
		END OP56
	PIN OP57
		DIRECTION OUTPUT ;
		USE SIGNAL ;
		PORT
			LAYER metal1 ;
			RECT 16.504 16.504 16.504 16.504 ;
			END
		END OP57
	PIN OP58
		DIRECTION OUTPUT ;
		USE SIGNAL ;
		PORT
			LAYER metal1 ;
			RECT 16.504 16.504 16.504 16.504 ;
			END
		END OP58
	PIN OP59
		DIRECTION OUTPUT ;
		USE SIGNAL ;
		PORT
			LAYER metal1 ;
			RECT 16.504 16.504 16.504 16.504 ;
			END
		END OP59
	PIN IP0
		DIRECTION INPUT ;
		USE SIGNAL ;
		PORT
			LAYER metal1 ;
			RECT 16.504 16.504 16.504 16.504 ;
			END
		END IP0
	PIN IP1
		DIRECTION INPUT ;
		USE SIGNAL ;
		PORT
			LAYER metal1 ;
			RECT 16.504 16.504 16.504 16.504 ;
			END
		END IP1
	PIN IP2
		DIRECTION INPUT ;
		USE SIGNAL ;
		PORT
			LAYER metal1 ;
			RECT 16.504 16.504 16.504 16.504 ;
			END
		END IP2
	PIN IP3
		DIRECTION INPUT ;
		USE SIGNAL ;
		PORT
			LAYER metal1 ;
			RECT 16.504 16.504 16.504 16.504 ;
			END
		END IP3
	PIN IP4
		DIRECTION INPUT ;
		USE SIGNAL ;
		PORT
			LAYER metal1 ;
			RECT 16.504 16.504 16.504 16.504 ;
			END
		END IP4
	PIN IP5
		DIRECTION INPUT ;
		USE SIGNAL ;
		PORT
			LAYER metal1 ;
			RECT 16.504 16.504 16.504 16.504 ;
			END
		END IP5
	PIN IP6
		DIRECTION INPUT ;
		USE SIGNAL ;
		PORT
			LAYER metal1 ;
			RECT 16.504 16.504 16.504 16.504 ;
			END
		END IP6
	PIN IP7
		DIRECTION INPUT ;
		USE SIGNAL ;
		PORT
			LAYER metal1 ;
			RECT 16.504 16.504 16.504 16.504 ;
			END
		END IP7
	PIN IP8
		DIRECTION INPUT ;
		USE SIGNAL ;
		PORT
			LAYER metal1 ;
			RECT 16.504 16.504 16.504 16.504 ;
			END
		END IP8
	PIN IP9
		DIRECTION INPUT ;
		USE SIGNAL ;
		PORT
			LAYER metal1 ;
			RECT 16.504 16.504 16.504 16.504 ;
			END
		END IP9
	PIN IP10
		DIRECTION INPUT ;
		USE SIGNAL ;
		PORT
			LAYER metal1 ;
			RECT 16.504 16.504 16.504 16.504 ;
			END
		END IP10
	PIN IP11
		DIRECTION INPUT ;
		USE SIGNAL ;
		PORT
			LAYER metal1 ;
			RECT 16.504 16.504 16.504 16.504 ;
			END
		END IP11
	PIN IP12
		DIRECTION INPUT ;
		USE SIGNAL ;
		PORT
			LAYER metal1 ;
			RECT 16.504 16.504 16.504 16.504 ;
			END
		END IP12
	PIN IP13
		DIRECTION INPUT ;
		USE SIGNAL ;
		PORT
			LAYER metal1 ;
			RECT 16.504 16.504 16.504 16.504 ;
			END
		END IP13
	PIN IP14
		DIRECTION INPUT ;
		USE SIGNAL ;
		PORT
			LAYER metal1 ;
			RECT 16.504 16.504 16.504 16.504 ;
			END
		END IP14
	PIN IP15
		DIRECTION INPUT ;
		USE SIGNAL ;
		PORT
			LAYER metal1 ;
			RECT 16.504 16.504 16.504 16.504 ;
			END
		END IP15
	PIN IP16
		DIRECTION INPUT ;
		USE SIGNAL ;
		PORT
			LAYER metal1 ;
			RECT 16.504 16.504 16.504 16.504 ;
			END
		END IP16
	PIN IP17
		DIRECTION INPUT ;
		USE SIGNAL ;
		PORT
			LAYER metal1 ;
			RECT 16.504 16.504 16.504 16.504 ;
			END
		END IP17
	PIN IP18
		DIRECTION INPUT ;
		USE SIGNAL ;
		PORT
			LAYER metal1 ;
			RECT 16.504 16.504 16.504 16.504 ;
			END
		END IP18
	PIN IP19
		DIRECTION INPUT ;
		USE SIGNAL ;
		PORT
			LAYER metal1 ;
			RECT 16.504 16.504 16.504 16.504 ;
			END
		END IP19
END cluster_13
MACRO cluster_14
	CLASS BLOCK ;
	ORIGIN 0 0 ;
	FOREIGN cluster_14 0 0 ;
	SIZE 32.891 BY 32.891 ;
	SYMMETRY X Y ;
	PIN OP0
		DIRECTION OUTPUT ;
		USE SIGNAL ;
		PORT
			LAYER metal1 ;
			RECT 16.445 16.445 16.445 16.445 ;
			END
		END OP0
	PIN OP1
		DIRECTION OUTPUT ;
		USE SIGNAL ;
		PORT
			LAYER metal1 ;
			RECT 16.445 16.445 16.445 16.445 ;
			END
		END OP1
	PIN OP2
		DIRECTION OUTPUT ;
		USE SIGNAL ;
		PORT
			LAYER metal1 ;
			RECT 16.445 16.445 16.445 16.445 ;
			END
		END OP2
	PIN OP3
		DIRECTION OUTPUT ;
		USE SIGNAL ;
		PORT
			LAYER metal1 ;
			RECT 16.445 16.445 16.445 16.445 ;
			END
		END OP3
	PIN OP4
		DIRECTION OUTPUT ;
		USE SIGNAL ;
		PORT
			LAYER metal1 ;
			RECT 16.445 16.445 16.445 16.445 ;
			END
		END OP4
	PIN OP5
		DIRECTION OUTPUT ;
		USE SIGNAL ;
		PORT
			LAYER metal1 ;
			RECT 16.445 16.445 16.445 16.445 ;
			END
		END OP5
	PIN OP6
		DIRECTION OUTPUT ;
		USE SIGNAL ;
		PORT
			LAYER metal1 ;
			RECT 16.445 16.445 16.445 16.445 ;
			END
		END OP6
	PIN OP7
		DIRECTION OUTPUT ;
		USE SIGNAL ;
		PORT
			LAYER metal1 ;
			RECT 16.445 16.445 16.445 16.445 ;
			END
		END OP7
	PIN OP8
		DIRECTION OUTPUT ;
		USE SIGNAL ;
		PORT
			LAYER metal1 ;
			RECT 16.445 16.445 16.445 16.445 ;
			END
		END OP8
	PIN OP9
		DIRECTION OUTPUT ;
		USE SIGNAL ;
		PORT
			LAYER metal1 ;
			RECT 16.445 16.445 16.445 16.445 ;
			END
		END OP9
	PIN OP10
		DIRECTION OUTPUT ;
		USE SIGNAL ;
		PORT
			LAYER metal1 ;
			RECT 16.445 16.445 16.445 16.445 ;
			END
		END OP10
	PIN OP11
		DIRECTION OUTPUT ;
		USE SIGNAL ;
		PORT
			LAYER metal1 ;
			RECT 16.445 16.445 16.445 16.445 ;
			END
		END OP11
	PIN OP12
		DIRECTION OUTPUT ;
		USE SIGNAL ;
		PORT
			LAYER metal1 ;
			RECT 16.445 16.445 16.445 16.445 ;
			END
		END OP12
	PIN OP13
		DIRECTION OUTPUT ;
		USE SIGNAL ;
		PORT
			LAYER metal1 ;
			RECT 16.445 16.445 16.445 16.445 ;
			END
		END OP13
	PIN OP14
		DIRECTION OUTPUT ;
		USE SIGNAL ;
		PORT
			LAYER metal1 ;
			RECT 16.445 16.445 16.445 16.445 ;
			END
		END OP14
	PIN OP15
		DIRECTION OUTPUT ;
		USE SIGNAL ;
		PORT
			LAYER metal1 ;
			RECT 16.445 16.445 16.445 16.445 ;
			END
		END OP15
	PIN OP16
		DIRECTION OUTPUT ;
		USE SIGNAL ;
		PORT
			LAYER metal1 ;
			RECT 16.445 16.445 16.445 16.445 ;
			END
		END OP16
	PIN OP17
		DIRECTION OUTPUT ;
		USE SIGNAL ;
		PORT
			LAYER metal1 ;
			RECT 16.445 16.445 16.445 16.445 ;
			END
		END OP17
	PIN OP18
		DIRECTION OUTPUT ;
		USE SIGNAL ;
		PORT
			LAYER metal1 ;
			RECT 16.445 16.445 16.445 16.445 ;
			END
		END OP18
	PIN OP19
		DIRECTION OUTPUT ;
		USE SIGNAL ;
		PORT
			LAYER metal1 ;
			RECT 16.445 16.445 16.445 16.445 ;
			END
		END OP19
	PIN OP20
		DIRECTION OUTPUT ;
		USE SIGNAL ;
		PORT
			LAYER metal1 ;
			RECT 16.445 16.445 16.445 16.445 ;
			END
		END OP20
	PIN OP21
		DIRECTION OUTPUT ;
		USE SIGNAL ;
		PORT
			LAYER metal1 ;
			RECT 16.445 16.445 16.445 16.445 ;
			END
		END OP21
	PIN OP22
		DIRECTION OUTPUT ;
		USE SIGNAL ;
		PORT
			LAYER metal1 ;
			RECT 16.445 16.445 16.445 16.445 ;
			END
		END OP22
	PIN OP23
		DIRECTION OUTPUT ;
		USE SIGNAL ;
		PORT
			LAYER metal1 ;
			RECT 16.445 16.445 16.445 16.445 ;
			END
		END OP23
	PIN OP24
		DIRECTION OUTPUT ;
		USE SIGNAL ;
		PORT
			LAYER metal1 ;
			RECT 16.445 16.445 16.445 16.445 ;
			END
		END OP24
	PIN OP25
		DIRECTION OUTPUT ;
		USE SIGNAL ;
		PORT
			LAYER metal1 ;
			RECT 16.445 16.445 16.445 16.445 ;
			END
		END OP25
	PIN OP26
		DIRECTION OUTPUT ;
		USE SIGNAL ;
		PORT
			LAYER metal1 ;
			RECT 16.445 16.445 16.445 16.445 ;
			END
		END OP26
	PIN OP27
		DIRECTION OUTPUT ;
		USE SIGNAL ;
		PORT
			LAYER metal1 ;
			RECT 16.445 16.445 16.445 16.445 ;
			END
		END OP27
	PIN OP28
		DIRECTION OUTPUT ;
		USE SIGNAL ;
		PORT
			LAYER metal1 ;
			RECT 16.445 16.445 16.445 16.445 ;
			END
		END OP28
	PIN OP29
		DIRECTION OUTPUT ;
		USE SIGNAL ;
		PORT
			LAYER metal1 ;
			RECT 16.445 16.445 16.445 16.445 ;
			END
		END OP29
	PIN OP30
		DIRECTION OUTPUT ;
		USE SIGNAL ;
		PORT
			LAYER metal1 ;
			RECT 16.445 16.445 16.445 16.445 ;
			END
		END OP30
	PIN OP31
		DIRECTION OUTPUT ;
		USE SIGNAL ;
		PORT
			LAYER metal1 ;
			RECT 16.445 16.445 16.445 16.445 ;
			END
		END OP31
	PIN OP32
		DIRECTION OUTPUT ;
		USE SIGNAL ;
		PORT
			LAYER metal1 ;
			RECT 16.445 16.445 16.445 16.445 ;
			END
		END OP32
	PIN OP33
		DIRECTION OUTPUT ;
		USE SIGNAL ;
		PORT
			LAYER metal1 ;
			RECT 16.445 16.445 16.445 16.445 ;
			END
		END OP33
	PIN OP34
		DIRECTION OUTPUT ;
		USE SIGNAL ;
		PORT
			LAYER metal1 ;
			RECT 16.445 16.445 16.445 16.445 ;
			END
		END OP34
	PIN OP35
		DIRECTION OUTPUT ;
		USE SIGNAL ;
		PORT
			LAYER metal1 ;
			RECT 16.445 16.445 16.445 16.445 ;
			END
		END OP35
	PIN OP36
		DIRECTION OUTPUT ;
		USE SIGNAL ;
		PORT
			LAYER metal1 ;
			RECT 16.445 16.445 16.445 16.445 ;
			END
		END OP36
	PIN OP37
		DIRECTION OUTPUT ;
		USE SIGNAL ;
		PORT
			LAYER metal1 ;
			RECT 16.445 16.445 16.445 16.445 ;
			END
		END OP37
	PIN OP38
		DIRECTION OUTPUT ;
		USE SIGNAL ;
		PORT
			LAYER metal1 ;
			RECT 16.445 16.445 16.445 16.445 ;
			END
		END OP38
	PIN OP39
		DIRECTION OUTPUT ;
		USE SIGNAL ;
		PORT
			LAYER metal1 ;
			RECT 16.445 16.445 16.445 16.445 ;
			END
		END OP39
	PIN OP40
		DIRECTION OUTPUT ;
		USE SIGNAL ;
		PORT
			LAYER metal1 ;
			RECT 16.445 16.445 16.445 16.445 ;
			END
		END OP40
	PIN OP41
		DIRECTION OUTPUT ;
		USE SIGNAL ;
		PORT
			LAYER metal1 ;
			RECT 16.445 16.445 16.445 16.445 ;
			END
		END OP41
	PIN OP42
		DIRECTION OUTPUT ;
		USE SIGNAL ;
		PORT
			LAYER metal1 ;
			RECT 16.445 16.445 16.445 16.445 ;
			END
		END OP42
	PIN OP43
		DIRECTION OUTPUT ;
		USE SIGNAL ;
		PORT
			LAYER metal1 ;
			RECT 16.445 16.445 16.445 16.445 ;
			END
		END OP43
	PIN OP44
		DIRECTION OUTPUT ;
		USE SIGNAL ;
		PORT
			LAYER metal1 ;
			RECT 16.445 16.445 16.445 16.445 ;
			END
		END OP44
	PIN OP45
		DIRECTION OUTPUT ;
		USE SIGNAL ;
		PORT
			LAYER metal1 ;
			RECT 16.445 16.445 16.445 16.445 ;
			END
		END OP45
	PIN OP46
		DIRECTION OUTPUT ;
		USE SIGNAL ;
		PORT
			LAYER metal1 ;
			RECT 16.445 16.445 16.445 16.445 ;
			END
		END OP46
	PIN OP47
		DIRECTION OUTPUT ;
		USE SIGNAL ;
		PORT
			LAYER metal1 ;
			RECT 16.445 16.445 16.445 16.445 ;
			END
		END OP47
	PIN OP48
		DIRECTION OUTPUT ;
		USE SIGNAL ;
		PORT
			LAYER metal1 ;
			RECT 16.445 16.445 16.445 16.445 ;
			END
		END OP48
	PIN OP49
		DIRECTION OUTPUT ;
		USE SIGNAL ;
		PORT
			LAYER metal1 ;
			RECT 16.445 16.445 16.445 16.445 ;
			END
		END OP49
	PIN OP50
		DIRECTION OUTPUT ;
		USE SIGNAL ;
		PORT
			LAYER metal1 ;
			RECT 16.445 16.445 16.445 16.445 ;
			END
		END OP50
	PIN OP51
		DIRECTION OUTPUT ;
		USE SIGNAL ;
		PORT
			LAYER metal1 ;
			RECT 16.445 16.445 16.445 16.445 ;
			END
		END OP51
	PIN OP52
		DIRECTION OUTPUT ;
		USE SIGNAL ;
		PORT
			LAYER metal1 ;
			RECT 16.445 16.445 16.445 16.445 ;
			END
		END OP52
	PIN OP53
		DIRECTION OUTPUT ;
		USE SIGNAL ;
		PORT
			LAYER metal1 ;
			RECT 16.445 16.445 16.445 16.445 ;
			END
		END OP53
	PIN OP54
		DIRECTION OUTPUT ;
		USE SIGNAL ;
		PORT
			LAYER metal1 ;
			RECT 16.445 16.445 16.445 16.445 ;
			END
		END OP54
	PIN OP55
		DIRECTION OUTPUT ;
		USE SIGNAL ;
		PORT
			LAYER metal1 ;
			RECT 16.445 16.445 16.445 16.445 ;
			END
		END OP55
	PIN OP56
		DIRECTION OUTPUT ;
		USE SIGNAL ;
		PORT
			LAYER metal1 ;
			RECT 16.445 16.445 16.445 16.445 ;
			END
		END OP56
	PIN OP57
		DIRECTION OUTPUT ;
		USE SIGNAL ;
		PORT
			LAYER metal1 ;
			RECT 16.445 16.445 16.445 16.445 ;
			END
		END OP57
	PIN OP58
		DIRECTION OUTPUT ;
		USE SIGNAL ;
		PORT
			LAYER metal1 ;
			RECT 16.445 16.445 16.445 16.445 ;
			END
		END OP58
	PIN OP59
		DIRECTION OUTPUT ;
		USE SIGNAL ;
		PORT
			LAYER metal1 ;
			RECT 16.445 16.445 16.445 16.445 ;
			END
		END OP59
	PIN OP60
		DIRECTION OUTPUT ;
		USE SIGNAL ;
		PORT
			LAYER metal1 ;
			RECT 16.445 16.445 16.445 16.445 ;
			END
		END OP60
	PIN IP0
		DIRECTION INPUT ;
		USE SIGNAL ;
		PORT
			LAYER metal1 ;
			RECT 16.445 16.445 16.445 16.445 ;
			END
		END IP0
	PIN IP1
		DIRECTION INPUT ;
		USE SIGNAL ;
		PORT
			LAYER metal1 ;
			RECT 16.445 16.445 16.445 16.445 ;
			END
		END IP1
	PIN IP2
		DIRECTION INPUT ;
		USE SIGNAL ;
		PORT
			LAYER metal1 ;
			RECT 16.445 16.445 16.445 16.445 ;
			END
		END IP2
	PIN IP3
		DIRECTION INPUT ;
		USE SIGNAL ;
		PORT
			LAYER metal1 ;
			RECT 16.445 16.445 16.445 16.445 ;
			END
		END IP3
	PIN IP4
		DIRECTION INPUT ;
		USE SIGNAL ;
		PORT
			LAYER metal1 ;
			RECT 16.445 16.445 16.445 16.445 ;
			END
		END IP4
	PIN IP5
		DIRECTION INPUT ;
		USE SIGNAL ;
		PORT
			LAYER metal1 ;
			RECT 16.445 16.445 16.445 16.445 ;
			END
		END IP5
	PIN IP6
		DIRECTION INPUT ;
		USE SIGNAL ;
		PORT
			LAYER metal1 ;
			RECT 16.445 16.445 16.445 16.445 ;
			END
		END IP6
	PIN IP7
		DIRECTION INPUT ;
		USE SIGNAL ;
		PORT
			LAYER metal1 ;
			RECT 16.445 16.445 16.445 16.445 ;
			END
		END IP7
	PIN IP8
		DIRECTION INPUT ;
		USE SIGNAL ;
		PORT
			LAYER metal1 ;
			RECT 16.445 16.445 16.445 16.445 ;
			END
		END IP8
	PIN IP9
		DIRECTION INPUT ;
		USE SIGNAL ;
		PORT
			LAYER metal1 ;
			RECT 16.445 16.445 16.445 16.445 ;
			END
		END IP9
	PIN IP10
		DIRECTION INPUT ;
		USE SIGNAL ;
		PORT
			LAYER metal1 ;
			RECT 16.445 16.445 16.445 16.445 ;
			END
		END IP10
	PIN IP11
		DIRECTION INPUT ;
		USE SIGNAL ;
		PORT
			LAYER metal1 ;
			RECT 16.445 16.445 16.445 16.445 ;
			END
		END IP11
	PIN IP12
		DIRECTION INPUT ;
		USE SIGNAL ;
		PORT
			LAYER metal1 ;
			RECT 16.445 16.445 16.445 16.445 ;
			END
		END IP12
END cluster_14
MACRO cluster_15
	CLASS BLOCK ;
	ORIGIN 0 0 ;
	FOREIGN cluster_15 0 0 ;
	SIZE 32.163 BY 32.163 ;
	SYMMETRY X Y ;
	PIN OP0
		DIRECTION OUTPUT ;
		USE SIGNAL ;
		PORT
			LAYER metal1 ;
			RECT 16.081 16.081 16.081 16.081 ;
			END
		END OP0
	PIN OP1
		DIRECTION OUTPUT ;
		USE SIGNAL ;
		PORT
			LAYER metal1 ;
			RECT 16.081 16.081 16.081 16.081 ;
			END
		END OP1
	PIN OP2
		DIRECTION OUTPUT ;
		USE SIGNAL ;
		PORT
			LAYER metal1 ;
			RECT 16.081 16.081 16.081 16.081 ;
			END
		END OP2
	PIN OP3
		DIRECTION OUTPUT ;
		USE SIGNAL ;
		PORT
			LAYER metal1 ;
			RECT 16.081 16.081 16.081 16.081 ;
			END
		END OP3
	PIN OP4
		DIRECTION OUTPUT ;
		USE SIGNAL ;
		PORT
			LAYER metal1 ;
			RECT 16.081 16.081 16.081 16.081 ;
			END
		END OP4
	PIN OP5
		DIRECTION OUTPUT ;
		USE SIGNAL ;
		PORT
			LAYER metal1 ;
			RECT 16.081 16.081 16.081 16.081 ;
			END
		END OP5
	PIN OP6
		DIRECTION OUTPUT ;
		USE SIGNAL ;
		PORT
			LAYER metal1 ;
			RECT 16.081 16.081 16.081 16.081 ;
			END
		END OP6
	PIN OP7
		DIRECTION OUTPUT ;
		USE SIGNAL ;
		PORT
			LAYER metal1 ;
			RECT 16.081 16.081 16.081 16.081 ;
			END
		END OP7
	PIN OP8
		DIRECTION OUTPUT ;
		USE SIGNAL ;
		PORT
			LAYER metal1 ;
			RECT 16.081 16.081 16.081 16.081 ;
			END
		END OP8
	PIN OP9
		DIRECTION OUTPUT ;
		USE SIGNAL ;
		PORT
			LAYER metal1 ;
			RECT 16.081 16.081 16.081 16.081 ;
			END
		END OP9
	PIN OP10
		DIRECTION OUTPUT ;
		USE SIGNAL ;
		PORT
			LAYER metal1 ;
			RECT 16.081 16.081 16.081 16.081 ;
			END
		END OP10
	PIN OP11
		DIRECTION OUTPUT ;
		USE SIGNAL ;
		PORT
			LAYER metal1 ;
			RECT 16.081 16.081 16.081 16.081 ;
			END
		END OP11
	PIN OP12
		DIRECTION OUTPUT ;
		USE SIGNAL ;
		PORT
			LAYER metal1 ;
			RECT 16.081 16.081 16.081 16.081 ;
			END
		END OP12
	PIN OP13
		DIRECTION OUTPUT ;
		USE SIGNAL ;
		PORT
			LAYER metal1 ;
			RECT 16.081 16.081 16.081 16.081 ;
			END
		END OP13
	PIN OP14
		DIRECTION OUTPUT ;
		USE SIGNAL ;
		PORT
			LAYER metal1 ;
			RECT 16.081 16.081 16.081 16.081 ;
			END
		END OP14
	PIN OP15
		DIRECTION OUTPUT ;
		USE SIGNAL ;
		PORT
			LAYER metal1 ;
			RECT 16.081 16.081 16.081 16.081 ;
			END
		END OP15
	PIN OP16
		DIRECTION OUTPUT ;
		USE SIGNAL ;
		PORT
			LAYER metal1 ;
			RECT 16.081 16.081 16.081 16.081 ;
			END
		END OP16
	PIN OP17
		DIRECTION OUTPUT ;
		USE SIGNAL ;
		PORT
			LAYER metal1 ;
			RECT 16.081 16.081 16.081 16.081 ;
			END
		END OP17
	PIN OP18
		DIRECTION OUTPUT ;
		USE SIGNAL ;
		PORT
			LAYER metal1 ;
			RECT 16.081 16.081 16.081 16.081 ;
			END
		END OP18
	PIN OP19
		DIRECTION OUTPUT ;
		USE SIGNAL ;
		PORT
			LAYER metal1 ;
			RECT 16.081 16.081 16.081 16.081 ;
			END
		END OP19
	PIN OP20
		DIRECTION OUTPUT ;
		USE SIGNAL ;
		PORT
			LAYER metal1 ;
			RECT 16.081 16.081 16.081 16.081 ;
			END
		END OP20
	PIN OP21
		DIRECTION OUTPUT ;
		USE SIGNAL ;
		PORT
			LAYER metal1 ;
			RECT 16.081 16.081 16.081 16.081 ;
			END
		END OP21
	PIN OP22
		DIRECTION OUTPUT ;
		USE SIGNAL ;
		PORT
			LAYER metal1 ;
			RECT 16.081 16.081 16.081 16.081 ;
			END
		END OP22
	PIN OP23
		DIRECTION OUTPUT ;
		USE SIGNAL ;
		PORT
			LAYER metal1 ;
			RECT 16.081 16.081 16.081 16.081 ;
			END
		END OP23
	PIN OP24
		DIRECTION OUTPUT ;
		USE SIGNAL ;
		PORT
			LAYER metal1 ;
			RECT 16.081 16.081 16.081 16.081 ;
			END
		END OP24
	PIN OP25
		DIRECTION OUTPUT ;
		USE SIGNAL ;
		PORT
			LAYER metal1 ;
			RECT 16.081 16.081 16.081 16.081 ;
			END
		END OP25
	PIN OP26
		DIRECTION OUTPUT ;
		USE SIGNAL ;
		PORT
			LAYER metal1 ;
			RECT 16.081 16.081 16.081 16.081 ;
			END
		END OP26
	PIN OP27
		DIRECTION OUTPUT ;
		USE SIGNAL ;
		PORT
			LAYER metal1 ;
			RECT 16.081 16.081 16.081 16.081 ;
			END
		END OP27
	PIN OP28
		DIRECTION OUTPUT ;
		USE SIGNAL ;
		PORT
			LAYER metal1 ;
			RECT 16.081 16.081 16.081 16.081 ;
			END
		END OP28
	PIN OP29
		DIRECTION OUTPUT ;
		USE SIGNAL ;
		PORT
			LAYER metal1 ;
			RECT 16.081 16.081 16.081 16.081 ;
			END
		END OP29
	PIN OP30
		DIRECTION OUTPUT ;
		USE SIGNAL ;
		PORT
			LAYER metal1 ;
			RECT 16.081 16.081 16.081 16.081 ;
			END
		END OP30
	PIN OP31
		DIRECTION OUTPUT ;
		USE SIGNAL ;
		PORT
			LAYER metal1 ;
			RECT 16.081 16.081 16.081 16.081 ;
			END
		END OP31
	PIN OP32
		DIRECTION OUTPUT ;
		USE SIGNAL ;
		PORT
			LAYER metal1 ;
			RECT 16.081 16.081 16.081 16.081 ;
			END
		END OP32
	PIN OP33
		DIRECTION OUTPUT ;
		USE SIGNAL ;
		PORT
			LAYER metal1 ;
			RECT 16.081 16.081 16.081 16.081 ;
			END
		END OP33
	PIN OP34
		DIRECTION OUTPUT ;
		USE SIGNAL ;
		PORT
			LAYER metal1 ;
			RECT 16.081 16.081 16.081 16.081 ;
			END
		END OP34
	PIN OP35
		DIRECTION OUTPUT ;
		USE SIGNAL ;
		PORT
			LAYER metal1 ;
			RECT 16.081 16.081 16.081 16.081 ;
			END
		END OP35
	PIN OP36
		DIRECTION OUTPUT ;
		USE SIGNAL ;
		PORT
			LAYER metal1 ;
			RECT 16.081 16.081 16.081 16.081 ;
			END
		END OP36
	PIN OP37
		DIRECTION OUTPUT ;
		USE SIGNAL ;
		PORT
			LAYER metal1 ;
			RECT 16.081 16.081 16.081 16.081 ;
			END
		END OP37
	PIN OP38
		DIRECTION OUTPUT ;
		USE SIGNAL ;
		PORT
			LAYER metal1 ;
			RECT 16.081 16.081 16.081 16.081 ;
			END
		END OP38
	PIN OP39
		DIRECTION OUTPUT ;
		USE SIGNAL ;
		PORT
			LAYER metal1 ;
			RECT 16.081 16.081 16.081 16.081 ;
			END
		END OP39
	PIN OP40
		DIRECTION OUTPUT ;
		USE SIGNAL ;
		PORT
			LAYER metal1 ;
			RECT 16.081 16.081 16.081 16.081 ;
			END
		END OP40
	PIN OP41
		DIRECTION OUTPUT ;
		USE SIGNAL ;
		PORT
			LAYER metal1 ;
			RECT 16.081 16.081 16.081 16.081 ;
			END
		END OP41
	PIN OP42
		DIRECTION OUTPUT ;
		USE SIGNAL ;
		PORT
			LAYER metal1 ;
			RECT 16.081 16.081 16.081 16.081 ;
			END
		END OP42
	PIN OP43
		DIRECTION OUTPUT ;
		USE SIGNAL ;
		PORT
			LAYER metal1 ;
			RECT 16.081 16.081 16.081 16.081 ;
			END
		END OP43
	PIN OP44
		DIRECTION OUTPUT ;
		USE SIGNAL ;
		PORT
			LAYER metal1 ;
			RECT 16.081 16.081 16.081 16.081 ;
			END
		END OP44
	PIN OP45
		DIRECTION OUTPUT ;
		USE SIGNAL ;
		PORT
			LAYER metal1 ;
			RECT 16.081 16.081 16.081 16.081 ;
			END
		END OP45
	PIN OP46
		DIRECTION OUTPUT ;
		USE SIGNAL ;
		PORT
			LAYER metal1 ;
			RECT 16.081 16.081 16.081 16.081 ;
			END
		END OP46
	PIN OP47
		DIRECTION OUTPUT ;
		USE SIGNAL ;
		PORT
			LAYER metal1 ;
			RECT 16.081 16.081 16.081 16.081 ;
			END
		END OP47
	PIN OP48
		DIRECTION OUTPUT ;
		USE SIGNAL ;
		PORT
			LAYER metal1 ;
			RECT 16.081 16.081 16.081 16.081 ;
			END
		END OP48
	PIN IP0
		DIRECTION INPUT ;
		USE SIGNAL ;
		PORT
			LAYER metal1 ;
			RECT 16.081 16.081 16.081 16.081 ;
			END
		END IP0
	PIN IP1
		DIRECTION INPUT ;
		USE SIGNAL ;
		PORT
			LAYER metal1 ;
			RECT 16.081 16.081 16.081 16.081 ;
			END
		END IP1
	PIN IP2
		DIRECTION INPUT ;
		USE SIGNAL ;
		PORT
			LAYER metal1 ;
			RECT 16.081 16.081 16.081 16.081 ;
			END
		END IP2
	PIN IP3
		DIRECTION INPUT ;
		USE SIGNAL ;
		PORT
			LAYER metal1 ;
			RECT 16.081 16.081 16.081 16.081 ;
			END
		END IP3
	PIN IP4
		DIRECTION INPUT ;
		USE SIGNAL ;
		PORT
			LAYER metal1 ;
			RECT 16.081 16.081 16.081 16.081 ;
			END
		END IP4
	PIN IP5
		DIRECTION INPUT ;
		USE SIGNAL ;
		PORT
			LAYER metal1 ;
			RECT 16.081 16.081 16.081 16.081 ;
			END
		END IP5
	PIN IP6
		DIRECTION INPUT ;
		USE SIGNAL ;
		PORT
			LAYER metal1 ;
			RECT 16.081 16.081 16.081 16.081 ;
			END
		END IP6
	PIN IP7
		DIRECTION INPUT ;
		USE SIGNAL ;
		PORT
			LAYER metal1 ;
			RECT 16.081 16.081 16.081 16.081 ;
			END
		END IP7
	PIN IP8
		DIRECTION INPUT ;
		USE SIGNAL ;
		PORT
			LAYER metal1 ;
			RECT 16.081 16.081 16.081 16.081 ;
			END
		END IP8
	PIN IP9
		DIRECTION INPUT ;
		USE SIGNAL ;
		PORT
			LAYER metal1 ;
			RECT 16.081 16.081 16.081 16.081 ;
			END
		END IP9
	PIN IP10
		DIRECTION INPUT ;
		USE SIGNAL ;
		PORT
			LAYER metal1 ;
			RECT 16.081 16.081 16.081 16.081 ;
			END
		END IP10
	PIN IP11
		DIRECTION INPUT ;
		USE SIGNAL ;
		PORT
			LAYER metal1 ;
			RECT 16.081 16.081 16.081 16.081 ;
			END
		END IP11
	PIN IP12
		DIRECTION INPUT ;
		USE SIGNAL ;
		PORT
			LAYER metal1 ;
			RECT 16.081 16.081 16.081 16.081 ;
			END
		END IP12
	PIN IP13
		DIRECTION INPUT ;
		USE SIGNAL ;
		PORT
			LAYER metal1 ;
			RECT 16.081 16.081 16.081 16.081 ;
			END
		END IP13
	PIN IP14
		DIRECTION INPUT ;
		USE SIGNAL ;
		PORT
			LAYER metal1 ;
			RECT 16.081 16.081 16.081 16.081 ;
			END
		END IP14
	PIN IP15
		DIRECTION INPUT ;
		USE SIGNAL ;
		PORT
			LAYER metal1 ;
			RECT 16.081 16.081 16.081 16.081 ;
			END
		END IP15
END cluster_15
MACRO cluster_16
	CLASS BLOCK ;
	ORIGIN 0 0 ;
	FOREIGN cluster_16 0 0 ;
	SIZE 30.038 BY 30.038 ;
	SYMMETRY X Y ;
	PIN OP0
		DIRECTION OUTPUT ;
		USE SIGNAL ;
		PORT
			LAYER metal1 ;
			RECT 15.019 15.019 15.019 15.019 ;
			END
		END OP0
	PIN OP1
		DIRECTION OUTPUT ;
		USE SIGNAL ;
		PORT
			LAYER metal1 ;
			RECT 15.019 15.019 15.019 15.019 ;
			END
		END OP1
	PIN OP2
		DIRECTION OUTPUT ;
		USE SIGNAL ;
		PORT
			LAYER metal1 ;
			RECT 15.019 15.019 15.019 15.019 ;
			END
		END OP2
	PIN OP3
		DIRECTION OUTPUT ;
		USE SIGNAL ;
		PORT
			LAYER metal1 ;
			RECT 15.019 15.019 15.019 15.019 ;
			END
		END OP3
	PIN OP4
		DIRECTION OUTPUT ;
		USE SIGNAL ;
		PORT
			LAYER metal1 ;
			RECT 15.019 15.019 15.019 15.019 ;
			END
		END OP4
	PIN OP5
		DIRECTION OUTPUT ;
		USE SIGNAL ;
		PORT
			LAYER metal1 ;
			RECT 15.019 15.019 15.019 15.019 ;
			END
		END OP5
	PIN OP6
		DIRECTION OUTPUT ;
		USE SIGNAL ;
		PORT
			LAYER metal1 ;
			RECT 15.019 15.019 15.019 15.019 ;
			END
		END OP6
	PIN OP7
		DIRECTION OUTPUT ;
		USE SIGNAL ;
		PORT
			LAYER metal1 ;
			RECT 15.019 15.019 15.019 15.019 ;
			END
		END OP7
	PIN OP8
		DIRECTION OUTPUT ;
		USE SIGNAL ;
		PORT
			LAYER metal1 ;
			RECT 15.019 15.019 15.019 15.019 ;
			END
		END OP8
	PIN OP9
		DIRECTION OUTPUT ;
		USE SIGNAL ;
		PORT
			LAYER metal1 ;
			RECT 15.019 15.019 15.019 15.019 ;
			END
		END OP9
	PIN OP10
		DIRECTION OUTPUT ;
		USE SIGNAL ;
		PORT
			LAYER metal1 ;
			RECT 15.019 15.019 15.019 15.019 ;
			END
		END OP10
	PIN OP11
		DIRECTION OUTPUT ;
		USE SIGNAL ;
		PORT
			LAYER metal1 ;
			RECT 15.019 15.019 15.019 15.019 ;
			END
		END OP11
	PIN OP12
		DIRECTION OUTPUT ;
		USE SIGNAL ;
		PORT
			LAYER metal1 ;
			RECT 15.019 15.019 15.019 15.019 ;
			END
		END OP12
	PIN OP13
		DIRECTION OUTPUT ;
		USE SIGNAL ;
		PORT
			LAYER metal1 ;
			RECT 15.019 15.019 15.019 15.019 ;
			END
		END OP13
	PIN OP14
		DIRECTION OUTPUT ;
		USE SIGNAL ;
		PORT
			LAYER metal1 ;
			RECT 15.019 15.019 15.019 15.019 ;
			END
		END OP14
	PIN OP15
		DIRECTION OUTPUT ;
		USE SIGNAL ;
		PORT
			LAYER metal1 ;
			RECT 15.019 15.019 15.019 15.019 ;
			END
		END OP15
	PIN OP16
		DIRECTION OUTPUT ;
		USE SIGNAL ;
		PORT
			LAYER metal1 ;
			RECT 15.019 15.019 15.019 15.019 ;
			END
		END OP16
	PIN OP17
		DIRECTION OUTPUT ;
		USE SIGNAL ;
		PORT
			LAYER metal1 ;
			RECT 15.019 15.019 15.019 15.019 ;
			END
		END OP17
	PIN OP18
		DIRECTION OUTPUT ;
		USE SIGNAL ;
		PORT
			LAYER metal1 ;
			RECT 15.019 15.019 15.019 15.019 ;
			END
		END OP18
	PIN OP19
		DIRECTION OUTPUT ;
		USE SIGNAL ;
		PORT
			LAYER metal1 ;
			RECT 15.019 15.019 15.019 15.019 ;
			END
		END OP19
	PIN OP20
		DIRECTION OUTPUT ;
		USE SIGNAL ;
		PORT
			LAYER metal1 ;
			RECT 15.019 15.019 15.019 15.019 ;
			END
		END OP20
	PIN OP21
		DIRECTION OUTPUT ;
		USE SIGNAL ;
		PORT
			LAYER metal1 ;
			RECT 15.019 15.019 15.019 15.019 ;
			END
		END OP21
	PIN OP22
		DIRECTION OUTPUT ;
		USE SIGNAL ;
		PORT
			LAYER metal1 ;
			RECT 15.019 15.019 15.019 15.019 ;
			END
		END OP22
	PIN OP23
		DIRECTION OUTPUT ;
		USE SIGNAL ;
		PORT
			LAYER metal1 ;
			RECT 15.019 15.019 15.019 15.019 ;
			END
		END OP23
	PIN OP24
		DIRECTION OUTPUT ;
		USE SIGNAL ;
		PORT
			LAYER metal1 ;
			RECT 15.019 15.019 15.019 15.019 ;
			END
		END OP24
	PIN IP0
		DIRECTION INPUT ;
		USE SIGNAL ;
		PORT
			LAYER metal1 ;
			RECT 15.019 15.019 15.019 15.019 ;
			END
		END IP0
	PIN IP1
		DIRECTION INPUT ;
		USE SIGNAL ;
		PORT
			LAYER metal1 ;
			RECT 15.019 15.019 15.019 15.019 ;
			END
		END IP1
	PIN IP2
		DIRECTION INPUT ;
		USE SIGNAL ;
		PORT
			LAYER metal1 ;
			RECT 15.019 15.019 15.019 15.019 ;
			END
		END IP2
	PIN IP3
		DIRECTION INPUT ;
		USE SIGNAL ;
		PORT
			LAYER metal1 ;
			RECT 15.019 15.019 15.019 15.019 ;
			END
		END IP3
	PIN IP4
		DIRECTION INPUT ;
		USE SIGNAL ;
		PORT
			LAYER metal1 ;
			RECT 15.019 15.019 15.019 15.019 ;
			END
		END IP4
	PIN IP5
		DIRECTION INPUT ;
		USE SIGNAL ;
		PORT
			LAYER metal1 ;
			RECT 15.019 15.019 15.019 15.019 ;
			END
		END IP5
	PIN IP6
		DIRECTION INPUT ;
		USE SIGNAL ;
		PORT
			LAYER metal1 ;
			RECT 15.019 15.019 15.019 15.019 ;
			END
		END IP6
	PIN IP7
		DIRECTION INPUT ;
		USE SIGNAL ;
		PORT
			LAYER metal1 ;
			RECT 15.019 15.019 15.019 15.019 ;
			END
		END IP7
	PIN IP8
		DIRECTION INPUT ;
		USE SIGNAL ;
		PORT
			LAYER metal1 ;
			RECT 15.019 15.019 15.019 15.019 ;
			END
		END IP8
	PIN IP9
		DIRECTION INPUT ;
		USE SIGNAL ;
		PORT
			LAYER metal1 ;
			RECT 15.019 15.019 15.019 15.019 ;
			END
		END IP9
	PIN IP10
		DIRECTION INPUT ;
		USE SIGNAL ;
		PORT
			LAYER metal1 ;
			RECT 15.019 15.019 15.019 15.019 ;
			END
		END IP10
	PIN IP11
		DIRECTION INPUT ;
		USE SIGNAL ;
		PORT
			LAYER metal1 ;
			RECT 15.019 15.019 15.019 15.019 ;
			END
		END IP11
	PIN IP12
		DIRECTION INPUT ;
		USE SIGNAL ;
		PORT
			LAYER metal1 ;
			RECT 15.019 15.019 15.019 15.019 ;
			END
		END IP12
	PIN IP13
		DIRECTION INPUT ;
		USE SIGNAL ;
		PORT
			LAYER metal1 ;
			RECT 15.019 15.019 15.019 15.019 ;
			END
		END IP13
	PIN IP14
		DIRECTION INPUT ;
		USE SIGNAL ;
		PORT
			LAYER metal1 ;
			RECT 15.019 15.019 15.019 15.019 ;
			END
		END IP14
	PIN IP15
		DIRECTION INPUT ;
		USE SIGNAL ;
		PORT
			LAYER metal1 ;
			RECT 15.019 15.019 15.019 15.019 ;
			END
		END IP15
	PIN IP16
		DIRECTION INPUT ;
		USE SIGNAL ;
		PORT
			LAYER metal1 ;
			RECT 15.019 15.019 15.019 15.019 ;
			END
		END IP16
	PIN IP17
		DIRECTION INPUT ;
		USE SIGNAL ;
		PORT
			LAYER metal1 ;
			RECT 15.019 15.019 15.019 15.019 ;
			END
		END IP17
	PIN IP18
		DIRECTION INPUT ;
		USE SIGNAL ;
		PORT
			LAYER metal1 ;
			RECT 15.019 15.019 15.019 15.019 ;
			END
		END IP18
	PIN IP19
		DIRECTION INPUT ;
		USE SIGNAL ;
		PORT
			LAYER metal1 ;
			RECT 15.019 15.019 15.019 15.019 ;
			END
		END IP19
	PIN IP20
		DIRECTION INPUT ;
		USE SIGNAL ;
		PORT
			LAYER metal1 ;
			RECT 15.019 15.019 15.019 15.019 ;
			END
		END IP20
	PIN IP21
		DIRECTION INPUT ;
		USE SIGNAL ;
		PORT
			LAYER metal1 ;
			RECT 15.019 15.019 15.019 15.019 ;
			END
		END IP21
	PIN IP22
		DIRECTION INPUT ;
		USE SIGNAL ;
		PORT
			LAYER metal1 ;
			RECT 15.019 15.019 15.019 15.019 ;
			END
		END IP22
	PIN IP23
		DIRECTION INPUT ;
		USE SIGNAL ;
		PORT
			LAYER metal1 ;
			RECT 15.019 15.019 15.019 15.019 ;
			END
		END IP23
END cluster_16
MACRO cluster_17
	CLASS BLOCK ;
	ORIGIN 0 0 ;
	FOREIGN cluster_17 0 0 ;
	SIZE 30.201 BY 30.201 ;
	SYMMETRY X Y ;
	PIN OP0
		DIRECTION OUTPUT ;
		USE SIGNAL ;
		PORT
			LAYER metal1 ;
			RECT 15.101 15.101 15.101 15.101 ;
			END
		END OP0
	PIN OP1
		DIRECTION OUTPUT ;
		USE SIGNAL ;
		PORT
			LAYER metal1 ;
			RECT 15.101 15.101 15.101 15.101 ;
			END
		END OP1
	PIN OP2
		DIRECTION OUTPUT ;
		USE SIGNAL ;
		PORT
			LAYER metal1 ;
			RECT 15.101 15.101 15.101 15.101 ;
			END
		END OP2
	PIN OP3
		DIRECTION OUTPUT ;
		USE SIGNAL ;
		PORT
			LAYER metal1 ;
			RECT 15.101 15.101 15.101 15.101 ;
			END
		END OP3
	PIN OP4
		DIRECTION OUTPUT ;
		USE SIGNAL ;
		PORT
			LAYER metal1 ;
			RECT 15.101 15.101 15.101 15.101 ;
			END
		END OP4
	PIN OP5
		DIRECTION OUTPUT ;
		USE SIGNAL ;
		PORT
			LAYER metal1 ;
			RECT 15.101 15.101 15.101 15.101 ;
			END
		END OP5
	PIN OP6
		DIRECTION OUTPUT ;
		USE SIGNAL ;
		PORT
			LAYER metal1 ;
			RECT 15.101 15.101 15.101 15.101 ;
			END
		END OP6
	PIN OP7
		DIRECTION OUTPUT ;
		USE SIGNAL ;
		PORT
			LAYER metal1 ;
			RECT 15.101 15.101 15.101 15.101 ;
			END
		END OP7
	PIN OP8
		DIRECTION OUTPUT ;
		USE SIGNAL ;
		PORT
			LAYER metal1 ;
			RECT 15.101 15.101 15.101 15.101 ;
			END
		END OP8
	PIN OP9
		DIRECTION OUTPUT ;
		USE SIGNAL ;
		PORT
			LAYER metal1 ;
			RECT 15.101 15.101 15.101 15.101 ;
			END
		END OP9
	PIN OP10
		DIRECTION OUTPUT ;
		USE SIGNAL ;
		PORT
			LAYER metal1 ;
			RECT 15.101 15.101 15.101 15.101 ;
			END
		END OP10
	PIN OP11
		DIRECTION OUTPUT ;
		USE SIGNAL ;
		PORT
			LAYER metal1 ;
			RECT 15.101 15.101 15.101 15.101 ;
			END
		END OP11
	PIN OP12
		DIRECTION OUTPUT ;
		USE SIGNAL ;
		PORT
			LAYER metal1 ;
			RECT 15.101 15.101 15.101 15.101 ;
			END
		END OP12
	PIN OP13
		DIRECTION OUTPUT ;
		USE SIGNAL ;
		PORT
			LAYER metal1 ;
			RECT 15.101 15.101 15.101 15.101 ;
			END
		END OP13
	PIN OP14
		DIRECTION OUTPUT ;
		USE SIGNAL ;
		PORT
			LAYER metal1 ;
			RECT 15.101 15.101 15.101 15.101 ;
			END
		END OP14
	PIN OP15
		DIRECTION OUTPUT ;
		USE SIGNAL ;
		PORT
			LAYER metal1 ;
			RECT 15.101 15.101 15.101 15.101 ;
			END
		END OP15
	PIN OP16
		DIRECTION OUTPUT ;
		USE SIGNAL ;
		PORT
			LAYER metal1 ;
			RECT 15.101 15.101 15.101 15.101 ;
			END
		END OP16
	PIN OP17
		DIRECTION OUTPUT ;
		USE SIGNAL ;
		PORT
			LAYER metal1 ;
			RECT 15.101 15.101 15.101 15.101 ;
			END
		END OP17
	PIN OP18
		DIRECTION OUTPUT ;
		USE SIGNAL ;
		PORT
			LAYER metal1 ;
			RECT 15.101 15.101 15.101 15.101 ;
			END
		END OP18
	PIN OP19
		DIRECTION OUTPUT ;
		USE SIGNAL ;
		PORT
			LAYER metal1 ;
			RECT 15.101 15.101 15.101 15.101 ;
			END
		END OP19
	PIN OP20
		DIRECTION OUTPUT ;
		USE SIGNAL ;
		PORT
			LAYER metal1 ;
			RECT 15.101 15.101 15.101 15.101 ;
			END
		END OP20
	PIN OP21
		DIRECTION OUTPUT ;
		USE SIGNAL ;
		PORT
			LAYER metal1 ;
			RECT 15.101 15.101 15.101 15.101 ;
			END
		END OP21
	PIN OP22
		DIRECTION OUTPUT ;
		USE SIGNAL ;
		PORT
			LAYER metal1 ;
			RECT 15.101 15.101 15.101 15.101 ;
			END
		END OP22
	PIN OP23
		DIRECTION OUTPUT ;
		USE SIGNAL ;
		PORT
			LAYER metal1 ;
			RECT 15.101 15.101 15.101 15.101 ;
			END
		END OP23
	PIN OP24
		DIRECTION OUTPUT ;
		USE SIGNAL ;
		PORT
			LAYER metal1 ;
			RECT 15.101 15.101 15.101 15.101 ;
			END
		END OP24
	PIN OP25
		DIRECTION OUTPUT ;
		USE SIGNAL ;
		PORT
			LAYER metal1 ;
			RECT 15.101 15.101 15.101 15.101 ;
			END
		END OP25
	PIN OP26
		DIRECTION OUTPUT ;
		USE SIGNAL ;
		PORT
			LAYER metal1 ;
			RECT 15.101 15.101 15.101 15.101 ;
			END
		END OP26
	PIN OP27
		DIRECTION OUTPUT ;
		USE SIGNAL ;
		PORT
			LAYER metal1 ;
			RECT 15.101 15.101 15.101 15.101 ;
			END
		END OP27
	PIN OP28
		DIRECTION OUTPUT ;
		USE SIGNAL ;
		PORT
			LAYER metal1 ;
			RECT 15.101 15.101 15.101 15.101 ;
			END
		END OP28
	PIN OP29
		DIRECTION OUTPUT ;
		USE SIGNAL ;
		PORT
			LAYER metal1 ;
			RECT 15.101 15.101 15.101 15.101 ;
			END
		END OP29
	PIN OP30
		DIRECTION OUTPUT ;
		USE SIGNAL ;
		PORT
			LAYER metal1 ;
			RECT 15.101 15.101 15.101 15.101 ;
			END
		END OP30
	PIN OP31
		DIRECTION OUTPUT ;
		USE SIGNAL ;
		PORT
			LAYER metal1 ;
			RECT 15.101 15.101 15.101 15.101 ;
			END
		END OP31
	PIN OP32
		DIRECTION OUTPUT ;
		USE SIGNAL ;
		PORT
			LAYER metal1 ;
			RECT 15.101 15.101 15.101 15.101 ;
			END
		END OP32
	PIN IP0
		DIRECTION INPUT ;
		USE SIGNAL ;
		PORT
			LAYER metal1 ;
			RECT 15.101 15.101 15.101 15.101 ;
			END
		END IP0
	PIN IP1
		DIRECTION INPUT ;
		USE SIGNAL ;
		PORT
			LAYER metal1 ;
			RECT 15.101 15.101 15.101 15.101 ;
			END
		END IP1
	PIN IP2
		DIRECTION INPUT ;
		USE SIGNAL ;
		PORT
			LAYER metal1 ;
			RECT 15.101 15.101 15.101 15.101 ;
			END
		END IP2
	PIN IP3
		DIRECTION INPUT ;
		USE SIGNAL ;
		PORT
			LAYER metal1 ;
			RECT 15.101 15.101 15.101 15.101 ;
			END
		END IP3
	PIN IP4
		DIRECTION INPUT ;
		USE SIGNAL ;
		PORT
			LAYER metal1 ;
			RECT 15.101 15.101 15.101 15.101 ;
			END
		END IP4
	PIN IP5
		DIRECTION INPUT ;
		USE SIGNAL ;
		PORT
			LAYER metal1 ;
			RECT 15.101 15.101 15.101 15.101 ;
			END
		END IP5
	PIN IP6
		DIRECTION INPUT ;
		USE SIGNAL ;
		PORT
			LAYER metal1 ;
			RECT 15.101 15.101 15.101 15.101 ;
			END
		END IP6
	PIN IP7
		DIRECTION INPUT ;
		USE SIGNAL ;
		PORT
			LAYER metal1 ;
			RECT 15.101 15.101 15.101 15.101 ;
			END
		END IP7
	PIN IP8
		DIRECTION INPUT ;
		USE SIGNAL ;
		PORT
			LAYER metal1 ;
			RECT 15.101 15.101 15.101 15.101 ;
			END
		END IP8
	PIN IP9
		DIRECTION INPUT ;
		USE SIGNAL ;
		PORT
			LAYER metal1 ;
			RECT 15.101 15.101 15.101 15.101 ;
			END
		END IP9
	PIN IP10
		DIRECTION INPUT ;
		USE SIGNAL ;
		PORT
			LAYER metal1 ;
			RECT 15.101 15.101 15.101 15.101 ;
			END
		END IP10
	PIN IP11
		DIRECTION INPUT ;
		USE SIGNAL ;
		PORT
			LAYER metal1 ;
			RECT 15.101 15.101 15.101 15.101 ;
			END
		END IP11
	PIN IP12
		DIRECTION INPUT ;
		USE SIGNAL ;
		PORT
			LAYER metal1 ;
			RECT 15.101 15.101 15.101 15.101 ;
			END
		END IP12
	PIN IP13
		DIRECTION INPUT ;
		USE SIGNAL ;
		PORT
			LAYER metal1 ;
			RECT 15.101 15.101 15.101 15.101 ;
			END
		END IP13
	PIN IP14
		DIRECTION INPUT ;
		USE SIGNAL ;
		PORT
			LAYER metal1 ;
			RECT 15.101 15.101 15.101 15.101 ;
			END
		END IP14
	PIN IP15
		DIRECTION INPUT ;
		USE SIGNAL ;
		PORT
			LAYER metal1 ;
			RECT 15.101 15.101 15.101 15.101 ;
			END
		END IP15
	PIN IP16
		DIRECTION INPUT ;
		USE SIGNAL ;
		PORT
			LAYER metal1 ;
			RECT 15.101 15.101 15.101 15.101 ;
			END
		END IP16
	PIN IP17
		DIRECTION INPUT ;
		USE SIGNAL ;
		PORT
			LAYER metal1 ;
			RECT 15.101 15.101 15.101 15.101 ;
			END
		END IP17
	PIN IP18
		DIRECTION INPUT ;
		USE SIGNAL ;
		PORT
			LAYER metal1 ;
			RECT 15.101 15.101 15.101 15.101 ;
			END
		END IP18
	PIN IP19
		DIRECTION INPUT ;
		USE SIGNAL ;
		PORT
			LAYER metal1 ;
			RECT 15.101 15.101 15.101 15.101 ;
			END
		END IP19
	PIN IP20
		DIRECTION INPUT ;
		USE SIGNAL ;
		PORT
			LAYER metal1 ;
			RECT 15.101 15.101 15.101 15.101 ;
			END
		END IP20
	PIN IP21
		DIRECTION INPUT ;
		USE SIGNAL ;
		PORT
			LAYER metal1 ;
			RECT 15.101 15.101 15.101 15.101 ;
			END
		END IP21
END cluster_17
MACRO cluster_18
	CLASS BLOCK ;
	ORIGIN 0 0 ;
	FOREIGN cluster_18 0 0 ;
	SIZE 30.113 BY 30.113 ;
	SYMMETRY X Y ;
	PIN OP0
		DIRECTION OUTPUT ;
		USE SIGNAL ;
		PORT
			LAYER metal1 ;
			RECT 15.056 15.056 15.056 15.056 ;
			END
		END OP0
	PIN OP1
		DIRECTION OUTPUT ;
		USE SIGNAL ;
		PORT
			LAYER metal1 ;
			RECT 15.056 15.056 15.056 15.056 ;
			END
		END OP1
	PIN OP2
		DIRECTION OUTPUT ;
		USE SIGNAL ;
		PORT
			LAYER metal1 ;
			RECT 15.056 15.056 15.056 15.056 ;
			END
		END OP2
	PIN OP3
		DIRECTION OUTPUT ;
		USE SIGNAL ;
		PORT
			LAYER metal1 ;
			RECT 15.056 15.056 15.056 15.056 ;
			END
		END OP3
	PIN OP4
		DIRECTION OUTPUT ;
		USE SIGNAL ;
		PORT
			LAYER metal1 ;
			RECT 15.056 15.056 15.056 15.056 ;
			END
		END OP4
	PIN OP5
		DIRECTION OUTPUT ;
		USE SIGNAL ;
		PORT
			LAYER metal1 ;
			RECT 15.056 15.056 15.056 15.056 ;
			END
		END OP5
	PIN OP6
		DIRECTION OUTPUT ;
		USE SIGNAL ;
		PORT
			LAYER metal1 ;
			RECT 15.056 15.056 15.056 15.056 ;
			END
		END OP6
	PIN OP7
		DIRECTION OUTPUT ;
		USE SIGNAL ;
		PORT
			LAYER metal1 ;
			RECT 15.056 15.056 15.056 15.056 ;
			END
		END OP7
	PIN OP8
		DIRECTION OUTPUT ;
		USE SIGNAL ;
		PORT
			LAYER metal1 ;
			RECT 15.056 15.056 15.056 15.056 ;
			END
		END OP8
	PIN OP9
		DIRECTION OUTPUT ;
		USE SIGNAL ;
		PORT
			LAYER metal1 ;
			RECT 15.056 15.056 15.056 15.056 ;
			END
		END OP9
	PIN OP10
		DIRECTION OUTPUT ;
		USE SIGNAL ;
		PORT
			LAYER metal1 ;
			RECT 15.056 15.056 15.056 15.056 ;
			END
		END OP10
	PIN OP11
		DIRECTION OUTPUT ;
		USE SIGNAL ;
		PORT
			LAYER metal1 ;
			RECT 15.056 15.056 15.056 15.056 ;
			END
		END OP11
	PIN OP12
		DIRECTION OUTPUT ;
		USE SIGNAL ;
		PORT
			LAYER metal1 ;
			RECT 15.056 15.056 15.056 15.056 ;
			END
		END OP12
	PIN OP13
		DIRECTION OUTPUT ;
		USE SIGNAL ;
		PORT
			LAYER metal1 ;
			RECT 15.056 15.056 15.056 15.056 ;
			END
		END OP13
	PIN OP14
		DIRECTION OUTPUT ;
		USE SIGNAL ;
		PORT
			LAYER metal1 ;
			RECT 15.056 15.056 15.056 15.056 ;
			END
		END OP14
	PIN OP15
		DIRECTION OUTPUT ;
		USE SIGNAL ;
		PORT
			LAYER metal1 ;
			RECT 15.056 15.056 15.056 15.056 ;
			END
		END OP15
	PIN OP16
		DIRECTION OUTPUT ;
		USE SIGNAL ;
		PORT
			LAYER metal1 ;
			RECT 15.056 15.056 15.056 15.056 ;
			END
		END OP16
	PIN OP17
		DIRECTION OUTPUT ;
		USE SIGNAL ;
		PORT
			LAYER metal1 ;
			RECT 15.056 15.056 15.056 15.056 ;
			END
		END OP17
	PIN OP18
		DIRECTION OUTPUT ;
		USE SIGNAL ;
		PORT
			LAYER metal1 ;
			RECT 15.056 15.056 15.056 15.056 ;
			END
		END OP18
	PIN OP19
		DIRECTION OUTPUT ;
		USE SIGNAL ;
		PORT
			LAYER metal1 ;
			RECT 15.056 15.056 15.056 15.056 ;
			END
		END OP19
	PIN OP20
		DIRECTION OUTPUT ;
		USE SIGNAL ;
		PORT
			LAYER metal1 ;
			RECT 15.056 15.056 15.056 15.056 ;
			END
		END OP20
	PIN OP21
		DIRECTION OUTPUT ;
		USE SIGNAL ;
		PORT
			LAYER metal1 ;
			RECT 15.056 15.056 15.056 15.056 ;
			END
		END OP21
	PIN OP22
		DIRECTION OUTPUT ;
		USE SIGNAL ;
		PORT
			LAYER metal1 ;
			RECT 15.056 15.056 15.056 15.056 ;
			END
		END OP22
	PIN OP23
		DIRECTION OUTPUT ;
		USE SIGNAL ;
		PORT
			LAYER metal1 ;
			RECT 15.056 15.056 15.056 15.056 ;
			END
		END OP23
	PIN OP24
		DIRECTION OUTPUT ;
		USE SIGNAL ;
		PORT
			LAYER metal1 ;
			RECT 15.056 15.056 15.056 15.056 ;
			END
		END OP24
	PIN IP0
		DIRECTION INPUT ;
		USE SIGNAL ;
		PORT
			LAYER metal1 ;
			RECT 15.056 15.056 15.056 15.056 ;
			END
		END IP0
	PIN IP1
		DIRECTION INPUT ;
		USE SIGNAL ;
		PORT
			LAYER metal1 ;
			RECT 15.056 15.056 15.056 15.056 ;
			END
		END IP1
	PIN IP2
		DIRECTION INPUT ;
		USE SIGNAL ;
		PORT
			LAYER metal1 ;
			RECT 15.056 15.056 15.056 15.056 ;
			END
		END IP2
	PIN IP3
		DIRECTION INPUT ;
		USE SIGNAL ;
		PORT
			LAYER metal1 ;
			RECT 15.056 15.056 15.056 15.056 ;
			END
		END IP3
	PIN IP4
		DIRECTION INPUT ;
		USE SIGNAL ;
		PORT
			LAYER metal1 ;
			RECT 15.056 15.056 15.056 15.056 ;
			END
		END IP4
	PIN IP5
		DIRECTION INPUT ;
		USE SIGNAL ;
		PORT
			LAYER metal1 ;
			RECT 15.056 15.056 15.056 15.056 ;
			END
		END IP5
	PIN IP6
		DIRECTION INPUT ;
		USE SIGNAL ;
		PORT
			LAYER metal1 ;
			RECT 15.056 15.056 15.056 15.056 ;
			END
		END IP6
	PIN IP7
		DIRECTION INPUT ;
		USE SIGNAL ;
		PORT
			LAYER metal1 ;
			RECT 15.056 15.056 15.056 15.056 ;
			END
		END IP7
	PIN IP8
		DIRECTION INPUT ;
		USE SIGNAL ;
		PORT
			LAYER metal1 ;
			RECT 15.056 15.056 15.056 15.056 ;
			END
		END IP8
	PIN IP9
		DIRECTION INPUT ;
		USE SIGNAL ;
		PORT
			LAYER metal1 ;
			RECT 15.056 15.056 15.056 15.056 ;
			END
		END IP9
	PIN IP10
		DIRECTION INPUT ;
		USE SIGNAL ;
		PORT
			LAYER metal1 ;
			RECT 15.056 15.056 15.056 15.056 ;
			END
		END IP10
	PIN IP11
		DIRECTION INPUT ;
		USE SIGNAL ;
		PORT
			LAYER metal1 ;
			RECT 15.056 15.056 15.056 15.056 ;
			END
		END IP11
	PIN IP12
		DIRECTION INPUT ;
		USE SIGNAL ;
		PORT
			LAYER metal1 ;
			RECT 15.056 15.056 15.056 15.056 ;
			END
		END IP12
	PIN IP13
		DIRECTION INPUT ;
		USE SIGNAL ;
		PORT
			LAYER metal1 ;
			RECT 15.056 15.056 15.056 15.056 ;
			END
		END IP13
	PIN IP14
		DIRECTION INPUT ;
		USE SIGNAL ;
		PORT
			LAYER metal1 ;
			RECT 15.056 15.056 15.056 15.056 ;
			END
		END IP14
	PIN IP15
		DIRECTION INPUT ;
		USE SIGNAL ;
		PORT
			LAYER metal1 ;
			RECT 15.056 15.056 15.056 15.056 ;
			END
		END IP15
	PIN IP16
		DIRECTION INPUT ;
		USE SIGNAL ;
		PORT
			LAYER metal1 ;
			RECT 15.056 15.056 15.056 15.056 ;
			END
		END IP16
	PIN IP17
		DIRECTION INPUT ;
		USE SIGNAL ;
		PORT
			LAYER metal1 ;
			RECT 15.056 15.056 15.056 15.056 ;
			END
		END IP17
	PIN IP18
		DIRECTION INPUT ;
		USE SIGNAL ;
		PORT
			LAYER metal1 ;
			RECT 15.056 15.056 15.056 15.056 ;
			END
		END IP18
	PIN IP19
		DIRECTION INPUT ;
		USE SIGNAL ;
		PORT
			LAYER metal1 ;
			RECT 15.056 15.056 15.056 15.056 ;
			END
		END IP19
	PIN IP20
		DIRECTION INPUT ;
		USE SIGNAL ;
		PORT
			LAYER metal1 ;
			RECT 15.056 15.056 15.056 15.056 ;
			END
		END IP20
END cluster_18
MACRO cluster_19
	CLASS BLOCK ;
	ORIGIN 0 0 ;
	FOREIGN cluster_19 0 0 ;
	SIZE 30.1 BY 30.1 ;
	SYMMETRY X Y ;
	PIN OP0
		DIRECTION OUTPUT ;
		USE SIGNAL ;
		PORT
			LAYER metal1 ;
			RECT 15.05 15.05 15.05 15.05 ;
			END
		END OP0
	PIN OP1
		DIRECTION OUTPUT ;
		USE SIGNAL ;
		PORT
			LAYER metal1 ;
			RECT 15.05 15.05 15.05 15.05 ;
			END
		END OP1
	PIN OP2
		DIRECTION OUTPUT ;
		USE SIGNAL ;
		PORT
			LAYER metal1 ;
			RECT 15.05 15.05 15.05 15.05 ;
			END
		END OP2
	PIN OP3
		DIRECTION OUTPUT ;
		USE SIGNAL ;
		PORT
			LAYER metal1 ;
			RECT 15.05 15.05 15.05 15.05 ;
			END
		END OP3
	PIN OP4
		DIRECTION OUTPUT ;
		USE SIGNAL ;
		PORT
			LAYER metal1 ;
			RECT 15.05 15.05 15.05 15.05 ;
			END
		END OP4
	PIN OP5
		DIRECTION OUTPUT ;
		USE SIGNAL ;
		PORT
			LAYER metal1 ;
			RECT 15.05 15.05 15.05 15.05 ;
			END
		END OP5
	PIN OP6
		DIRECTION OUTPUT ;
		USE SIGNAL ;
		PORT
			LAYER metal1 ;
			RECT 15.05 15.05 15.05 15.05 ;
			END
		END OP6
	PIN OP7
		DIRECTION OUTPUT ;
		USE SIGNAL ;
		PORT
			LAYER metal1 ;
			RECT 15.05 15.05 15.05 15.05 ;
			END
		END OP7
	PIN OP8
		DIRECTION OUTPUT ;
		USE SIGNAL ;
		PORT
			LAYER metal1 ;
			RECT 15.05 15.05 15.05 15.05 ;
			END
		END OP8
	PIN OP9
		DIRECTION OUTPUT ;
		USE SIGNAL ;
		PORT
			LAYER metal1 ;
			RECT 15.05 15.05 15.05 15.05 ;
			END
		END OP9
	PIN OP10
		DIRECTION OUTPUT ;
		USE SIGNAL ;
		PORT
			LAYER metal1 ;
			RECT 15.05 15.05 15.05 15.05 ;
			END
		END OP10
	PIN OP11
		DIRECTION OUTPUT ;
		USE SIGNAL ;
		PORT
			LAYER metal1 ;
			RECT 15.05 15.05 15.05 15.05 ;
			END
		END OP11
	PIN OP12
		DIRECTION OUTPUT ;
		USE SIGNAL ;
		PORT
			LAYER metal1 ;
			RECT 15.05 15.05 15.05 15.05 ;
			END
		END OP12
	PIN OP13
		DIRECTION OUTPUT ;
		USE SIGNAL ;
		PORT
			LAYER metal1 ;
			RECT 15.05 15.05 15.05 15.05 ;
			END
		END OP13
	PIN OP14
		DIRECTION OUTPUT ;
		USE SIGNAL ;
		PORT
			LAYER metal1 ;
			RECT 15.05 15.05 15.05 15.05 ;
			END
		END OP14
	PIN OP15
		DIRECTION OUTPUT ;
		USE SIGNAL ;
		PORT
			LAYER metal1 ;
			RECT 15.05 15.05 15.05 15.05 ;
			END
		END OP15
	PIN OP16
		DIRECTION OUTPUT ;
		USE SIGNAL ;
		PORT
			LAYER metal1 ;
			RECT 15.05 15.05 15.05 15.05 ;
			END
		END OP16
	PIN OP17
		DIRECTION OUTPUT ;
		USE SIGNAL ;
		PORT
			LAYER metal1 ;
			RECT 15.05 15.05 15.05 15.05 ;
			END
		END OP17
	PIN OP18
		DIRECTION OUTPUT ;
		USE SIGNAL ;
		PORT
			LAYER metal1 ;
			RECT 15.05 15.05 15.05 15.05 ;
			END
		END OP18
	PIN OP19
		DIRECTION OUTPUT ;
		USE SIGNAL ;
		PORT
			LAYER metal1 ;
			RECT 15.05 15.05 15.05 15.05 ;
			END
		END OP19
	PIN OP20
		DIRECTION OUTPUT ;
		USE SIGNAL ;
		PORT
			LAYER metal1 ;
			RECT 15.05 15.05 15.05 15.05 ;
			END
		END OP20
	PIN OP21
		DIRECTION OUTPUT ;
		USE SIGNAL ;
		PORT
			LAYER metal1 ;
			RECT 15.05 15.05 15.05 15.05 ;
			END
		END OP21
	PIN OP22
		DIRECTION OUTPUT ;
		USE SIGNAL ;
		PORT
			LAYER metal1 ;
			RECT 15.05 15.05 15.05 15.05 ;
			END
		END OP22
	PIN OP23
		DIRECTION OUTPUT ;
		USE SIGNAL ;
		PORT
			LAYER metal1 ;
			RECT 15.05 15.05 15.05 15.05 ;
			END
		END OP23
	PIN OP24
		DIRECTION OUTPUT ;
		USE SIGNAL ;
		PORT
			LAYER metal1 ;
			RECT 15.05 15.05 15.05 15.05 ;
			END
		END OP24
	PIN OP25
		DIRECTION OUTPUT ;
		USE SIGNAL ;
		PORT
			LAYER metal1 ;
			RECT 15.05 15.05 15.05 15.05 ;
			END
		END OP25
	PIN OP26
		DIRECTION OUTPUT ;
		USE SIGNAL ;
		PORT
			LAYER metal1 ;
			RECT 15.05 15.05 15.05 15.05 ;
			END
		END OP26
	PIN OP27
		DIRECTION OUTPUT ;
		USE SIGNAL ;
		PORT
			LAYER metal1 ;
			RECT 15.05 15.05 15.05 15.05 ;
			END
		END OP27
	PIN OP28
		DIRECTION OUTPUT ;
		USE SIGNAL ;
		PORT
			LAYER metal1 ;
			RECT 15.05 15.05 15.05 15.05 ;
			END
		END OP28
	PIN OP29
		DIRECTION OUTPUT ;
		USE SIGNAL ;
		PORT
			LAYER metal1 ;
			RECT 15.05 15.05 15.05 15.05 ;
			END
		END OP29
	PIN OP30
		DIRECTION OUTPUT ;
		USE SIGNAL ;
		PORT
			LAYER metal1 ;
			RECT 15.05 15.05 15.05 15.05 ;
			END
		END OP30
	PIN OP31
		DIRECTION OUTPUT ;
		USE SIGNAL ;
		PORT
			LAYER metal1 ;
			RECT 15.05 15.05 15.05 15.05 ;
			END
		END OP31
	PIN OP32
		DIRECTION OUTPUT ;
		USE SIGNAL ;
		PORT
			LAYER metal1 ;
			RECT 15.05 15.05 15.05 15.05 ;
			END
		END OP32
	PIN IP0
		DIRECTION INPUT ;
		USE SIGNAL ;
		PORT
			LAYER metal1 ;
			RECT 15.05 15.05 15.05 15.05 ;
			END
		END IP0
	PIN IP1
		DIRECTION INPUT ;
		USE SIGNAL ;
		PORT
			LAYER metal1 ;
			RECT 15.05 15.05 15.05 15.05 ;
			END
		END IP1
	PIN IP2
		DIRECTION INPUT ;
		USE SIGNAL ;
		PORT
			LAYER metal1 ;
			RECT 15.05 15.05 15.05 15.05 ;
			END
		END IP2
	PIN IP3
		DIRECTION INPUT ;
		USE SIGNAL ;
		PORT
			LAYER metal1 ;
			RECT 15.05 15.05 15.05 15.05 ;
			END
		END IP3
	PIN IP4
		DIRECTION INPUT ;
		USE SIGNAL ;
		PORT
			LAYER metal1 ;
			RECT 15.05 15.05 15.05 15.05 ;
			END
		END IP4
	PIN IP5
		DIRECTION INPUT ;
		USE SIGNAL ;
		PORT
			LAYER metal1 ;
			RECT 15.05 15.05 15.05 15.05 ;
			END
		END IP5
	PIN IP6
		DIRECTION INPUT ;
		USE SIGNAL ;
		PORT
			LAYER metal1 ;
			RECT 15.05 15.05 15.05 15.05 ;
			END
		END IP6
	PIN IP7
		DIRECTION INPUT ;
		USE SIGNAL ;
		PORT
			LAYER metal1 ;
			RECT 15.05 15.05 15.05 15.05 ;
			END
		END IP7
	PIN IP8
		DIRECTION INPUT ;
		USE SIGNAL ;
		PORT
			LAYER metal1 ;
			RECT 15.05 15.05 15.05 15.05 ;
			END
		END IP8
	PIN IP9
		DIRECTION INPUT ;
		USE SIGNAL ;
		PORT
			LAYER metal1 ;
			RECT 15.05 15.05 15.05 15.05 ;
			END
		END IP9
	PIN IP10
		DIRECTION INPUT ;
		USE SIGNAL ;
		PORT
			LAYER metal1 ;
			RECT 15.05 15.05 15.05 15.05 ;
			END
		END IP10
	PIN IP11
		DIRECTION INPUT ;
		USE SIGNAL ;
		PORT
			LAYER metal1 ;
			RECT 15.05 15.05 15.05 15.05 ;
			END
		END IP11
	PIN IP12
		DIRECTION INPUT ;
		USE SIGNAL ;
		PORT
			LAYER metal1 ;
			RECT 15.05 15.05 15.05 15.05 ;
			END
		END IP12
	PIN IP13
		DIRECTION INPUT ;
		USE SIGNAL ;
		PORT
			LAYER metal1 ;
			RECT 15.05 15.05 15.05 15.05 ;
			END
		END IP13
	PIN IP14
		DIRECTION INPUT ;
		USE SIGNAL ;
		PORT
			LAYER metal1 ;
			RECT 15.05 15.05 15.05 15.05 ;
			END
		END IP14
	PIN IP15
		DIRECTION INPUT ;
		USE SIGNAL ;
		PORT
			LAYER metal1 ;
			RECT 15.05 15.05 15.05 15.05 ;
			END
		END IP15
	PIN IP16
		DIRECTION INPUT ;
		USE SIGNAL ;
		PORT
			LAYER metal1 ;
			RECT 15.05 15.05 15.05 15.05 ;
			END
		END IP16
	PIN IP17
		DIRECTION INPUT ;
		USE SIGNAL ;
		PORT
			LAYER metal1 ;
			RECT 15.05 15.05 15.05 15.05 ;
			END
		END IP17
	PIN IP18
		DIRECTION INPUT ;
		USE SIGNAL ;
		PORT
			LAYER metal1 ;
			RECT 15.05 15.05 15.05 15.05 ;
			END
		END IP18
	PIN IP19
		DIRECTION INPUT ;
		USE SIGNAL ;
		PORT
			LAYER metal1 ;
			RECT 15.05 15.05 15.05 15.05 ;
			END
		END IP19
	PIN IP20
		DIRECTION INPUT ;
		USE SIGNAL ;
		PORT
			LAYER metal1 ;
			RECT 15.05 15.05 15.05 15.05 ;
			END
		END IP20
END cluster_19
MACRO cluster_20
	CLASS BLOCK ;
	ORIGIN 0 0 ;
	FOREIGN cluster_20 0 0 ;
	SIZE 21.857 BY 21.857 ;
	SYMMETRY X Y ;
	PIN OP0
		DIRECTION OUTPUT ;
		USE SIGNAL ;
		PORT
			LAYER metal1 ;
			RECT 10.928 10.928 10.928 10.928 ;
			END
		END OP0
	PIN OP1
		DIRECTION OUTPUT ;
		USE SIGNAL ;
		PORT
			LAYER metal1 ;
			RECT 10.928 10.928 10.928 10.928 ;
			END
		END OP1
	PIN OP2
		DIRECTION OUTPUT ;
		USE SIGNAL ;
		PORT
			LAYER metal1 ;
			RECT 10.928 10.928 10.928 10.928 ;
			END
		END OP2
	PIN OP3
		DIRECTION OUTPUT ;
		USE SIGNAL ;
		PORT
			LAYER metal1 ;
			RECT 10.928 10.928 10.928 10.928 ;
			END
		END OP3
	PIN OP4
		DIRECTION OUTPUT ;
		USE SIGNAL ;
		PORT
			LAYER metal1 ;
			RECT 10.928 10.928 10.928 10.928 ;
			END
		END OP4
	PIN OP5
		DIRECTION OUTPUT ;
		USE SIGNAL ;
		PORT
			LAYER metal1 ;
			RECT 10.928 10.928 10.928 10.928 ;
			END
		END OP5
	PIN OP6
		DIRECTION OUTPUT ;
		USE SIGNAL ;
		PORT
			LAYER metal1 ;
			RECT 10.928 10.928 10.928 10.928 ;
			END
		END OP6
	PIN OP7
		DIRECTION OUTPUT ;
		USE SIGNAL ;
		PORT
			LAYER metal1 ;
			RECT 10.928 10.928 10.928 10.928 ;
			END
		END OP7
	PIN OP8
		DIRECTION OUTPUT ;
		USE SIGNAL ;
		PORT
			LAYER metal1 ;
			RECT 10.928 10.928 10.928 10.928 ;
			END
		END OP8
	PIN OP9
		DIRECTION OUTPUT ;
		USE SIGNAL ;
		PORT
			LAYER metal1 ;
			RECT 10.928 10.928 10.928 10.928 ;
			END
		END OP9
	PIN OP10
		DIRECTION OUTPUT ;
		USE SIGNAL ;
		PORT
			LAYER metal1 ;
			RECT 10.928 10.928 10.928 10.928 ;
			END
		END OP10
	PIN OP11
		DIRECTION OUTPUT ;
		USE SIGNAL ;
		PORT
			LAYER metal1 ;
			RECT 10.928 10.928 10.928 10.928 ;
			END
		END OP11
	PIN OP12
		DIRECTION OUTPUT ;
		USE SIGNAL ;
		PORT
			LAYER metal1 ;
			RECT 10.928 10.928 10.928 10.928 ;
			END
		END OP12
	PIN OP13
		DIRECTION OUTPUT ;
		USE SIGNAL ;
		PORT
			LAYER metal1 ;
			RECT 10.928 10.928 10.928 10.928 ;
			END
		END OP13
	PIN OP14
		DIRECTION OUTPUT ;
		USE SIGNAL ;
		PORT
			LAYER metal1 ;
			RECT 10.928 10.928 10.928 10.928 ;
			END
		END OP14
	PIN OP15
		DIRECTION OUTPUT ;
		USE SIGNAL ;
		PORT
			LAYER metal1 ;
			RECT 10.928 10.928 10.928 10.928 ;
			END
		END OP15
	PIN OP16
		DIRECTION OUTPUT ;
		USE SIGNAL ;
		PORT
			LAYER metal1 ;
			RECT 10.928 10.928 10.928 10.928 ;
			END
		END OP16
	PIN OP17
		DIRECTION OUTPUT ;
		USE SIGNAL ;
		PORT
			LAYER metal1 ;
			RECT 10.928 10.928 10.928 10.928 ;
			END
		END OP17
	PIN OP18
		DIRECTION OUTPUT ;
		USE SIGNAL ;
		PORT
			LAYER metal1 ;
			RECT 10.928 10.928 10.928 10.928 ;
			END
		END OP18
	PIN OP19
		DIRECTION OUTPUT ;
		USE SIGNAL ;
		PORT
			LAYER metal1 ;
			RECT 10.928 10.928 10.928 10.928 ;
			END
		END OP19
	PIN OP20
		DIRECTION OUTPUT ;
		USE SIGNAL ;
		PORT
			LAYER metal1 ;
			RECT 10.928 10.928 10.928 10.928 ;
			END
		END OP20
	PIN OP21
		DIRECTION OUTPUT ;
		USE SIGNAL ;
		PORT
			LAYER metal1 ;
			RECT 10.928 10.928 10.928 10.928 ;
			END
		END OP21
	PIN OP22
		DIRECTION OUTPUT ;
		USE SIGNAL ;
		PORT
			LAYER metal1 ;
			RECT 10.928 10.928 10.928 10.928 ;
			END
		END OP22
	PIN OP23
		DIRECTION OUTPUT ;
		USE SIGNAL ;
		PORT
			LAYER metal1 ;
			RECT 10.928 10.928 10.928 10.928 ;
			END
		END OP23
	PIN OP24
		DIRECTION OUTPUT ;
		USE SIGNAL ;
		PORT
			LAYER metal1 ;
			RECT 10.928 10.928 10.928 10.928 ;
			END
		END OP24
	PIN OP25
		DIRECTION OUTPUT ;
		USE SIGNAL ;
		PORT
			LAYER metal1 ;
			RECT 10.928 10.928 10.928 10.928 ;
			END
		END OP25
	PIN OP26
		DIRECTION OUTPUT ;
		USE SIGNAL ;
		PORT
			LAYER metal1 ;
			RECT 10.928 10.928 10.928 10.928 ;
			END
		END OP26
	PIN OP27
		DIRECTION OUTPUT ;
		USE SIGNAL ;
		PORT
			LAYER metal1 ;
			RECT 10.928 10.928 10.928 10.928 ;
			END
		END OP27
	PIN OP28
		DIRECTION OUTPUT ;
		USE SIGNAL ;
		PORT
			LAYER metal1 ;
			RECT 10.928 10.928 10.928 10.928 ;
			END
		END OP28
	PIN OP29
		DIRECTION OUTPUT ;
		USE SIGNAL ;
		PORT
			LAYER metal1 ;
			RECT 10.928 10.928 10.928 10.928 ;
			END
		END OP29
	PIN OP30
		DIRECTION OUTPUT ;
		USE SIGNAL ;
		PORT
			LAYER metal1 ;
			RECT 10.928 10.928 10.928 10.928 ;
			END
		END OP30
	PIN OP31
		DIRECTION OUTPUT ;
		USE SIGNAL ;
		PORT
			LAYER metal1 ;
			RECT 10.928 10.928 10.928 10.928 ;
			END
		END OP31
	PIN OP32
		DIRECTION OUTPUT ;
		USE SIGNAL ;
		PORT
			LAYER metal1 ;
			RECT 10.928 10.928 10.928 10.928 ;
			END
		END OP32
	PIN OP33
		DIRECTION OUTPUT ;
		USE SIGNAL ;
		PORT
			LAYER metal1 ;
			RECT 10.928 10.928 10.928 10.928 ;
			END
		END OP33
	PIN OP34
		DIRECTION OUTPUT ;
		USE SIGNAL ;
		PORT
			LAYER metal1 ;
			RECT 10.928 10.928 10.928 10.928 ;
			END
		END OP34
	PIN OP35
		DIRECTION OUTPUT ;
		USE SIGNAL ;
		PORT
			LAYER metal1 ;
			RECT 10.928 10.928 10.928 10.928 ;
			END
		END OP35
	PIN OP36
		DIRECTION OUTPUT ;
		USE SIGNAL ;
		PORT
			LAYER metal1 ;
			RECT 10.928 10.928 10.928 10.928 ;
			END
		END OP36
	PIN OP37
		DIRECTION OUTPUT ;
		USE SIGNAL ;
		PORT
			LAYER metal1 ;
			RECT 10.928 10.928 10.928 10.928 ;
			END
		END OP37
	PIN OP38
		DIRECTION OUTPUT ;
		USE SIGNAL ;
		PORT
			LAYER metal1 ;
			RECT 10.928 10.928 10.928 10.928 ;
			END
		END OP38
	PIN OP39
		DIRECTION OUTPUT ;
		USE SIGNAL ;
		PORT
			LAYER metal1 ;
			RECT 10.928 10.928 10.928 10.928 ;
			END
		END OP39
	PIN OP40
		DIRECTION OUTPUT ;
		USE SIGNAL ;
		PORT
			LAYER metal1 ;
			RECT 10.928 10.928 10.928 10.928 ;
			END
		END OP40
	PIN OP41
		DIRECTION OUTPUT ;
		USE SIGNAL ;
		PORT
			LAYER metal1 ;
			RECT 10.928 10.928 10.928 10.928 ;
			END
		END OP41
	PIN OP42
		DIRECTION OUTPUT ;
		USE SIGNAL ;
		PORT
			LAYER metal1 ;
			RECT 10.928 10.928 10.928 10.928 ;
			END
		END OP42
	PIN OP43
		DIRECTION OUTPUT ;
		USE SIGNAL ;
		PORT
			LAYER metal1 ;
			RECT 10.928 10.928 10.928 10.928 ;
			END
		END OP43
	PIN OP44
		DIRECTION OUTPUT ;
		USE SIGNAL ;
		PORT
			LAYER metal1 ;
			RECT 10.928 10.928 10.928 10.928 ;
			END
		END OP44
	PIN OP45
		DIRECTION OUTPUT ;
		USE SIGNAL ;
		PORT
			LAYER metal1 ;
			RECT 10.928 10.928 10.928 10.928 ;
			END
		END OP45
	PIN OP46
		DIRECTION OUTPUT ;
		USE SIGNAL ;
		PORT
			LAYER metal1 ;
			RECT 10.928 10.928 10.928 10.928 ;
			END
		END OP46
	PIN OP47
		DIRECTION OUTPUT ;
		USE SIGNAL ;
		PORT
			LAYER metal1 ;
			RECT 10.928 10.928 10.928 10.928 ;
			END
		END OP47
	PIN OP48
		DIRECTION OUTPUT ;
		USE SIGNAL ;
		PORT
			LAYER metal1 ;
			RECT 10.928 10.928 10.928 10.928 ;
			END
		END OP48
	PIN OP49
		DIRECTION OUTPUT ;
		USE SIGNAL ;
		PORT
			LAYER metal1 ;
			RECT 10.928 10.928 10.928 10.928 ;
			END
		END OP49
	PIN OP50
		DIRECTION OUTPUT ;
		USE SIGNAL ;
		PORT
			LAYER metal1 ;
			RECT 10.928 10.928 10.928 10.928 ;
			END
		END OP50
	PIN OP51
		DIRECTION OUTPUT ;
		USE SIGNAL ;
		PORT
			LAYER metal1 ;
			RECT 10.928 10.928 10.928 10.928 ;
			END
		END OP51
	PIN OP52
		DIRECTION OUTPUT ;
		USE SIGNAL ;
		PORT
			LAYER metal1 ;
			RECT 10.928 10.928 10.928 10.928 ;
			END
		END OP52
	PIN OP53
		DIRECTION OUTPUT ;
		USE SIGNAL ;
		PORT
			LAYER metal1 ;
			RECT 10.928 10.928 10.928 10.928 ;
			END
		END OP53
	PIN OP54
		DIRECTION OUTPUT ;
		USE SIGNAL ;
		PORT
			LAYER metal1 ;
			RECT 10.928 10.928 10.928 10.928 ;
			END
		END OP54
	PIN OP55
		DIRECTION OUTPUT ;
		USE SIGNAL ;
		PORT
			LAYER metal1 ;
			RECT 10.928 10.928 10.928 10.928 ;
			END
		END OP55
	PIN OP56
		DIRECTION OUTPUT ;
		USE SIGNAL ;
		PORT
			LAYER metal1 ;
			RECT 10.928 10.928 10.928 10.928 ;
			END
		END OP56
	PIN OP57
		DIRECTION OUTPUT ;
		USE SIGNAL ;
		PORT
			LAYER metal1 ;
			RECT 10.928 10.928 10.928 10.928 ;
			END
		END OP57
	PIN OP58
		DIRECTION OUTPUT ;
		USE SIGNAL ;
		PORT
			LAYER metal1 ;
			RECT 10.928 10.928 10.928 10.928 ;
			END
		END OP58
	PIN OP59
		DIRECTION OUTPUT ;
		USE SIGNAL ;
		PORT
			LAYER metal1 ;
			RECT 10.928 10.928 10.928 10.928 ;
			END
		END OP59
	PIN IP0
		DIRECTION INPUT ;
		USE SIGNAL ;
		PORT
			LAYER metal1 ;
			RECT 10.928 10.928 10.928 10.928 ;
			END
		END IP0
	PIN IP1
		DIRECTION INPUT ;
		USE SIGNAL ;
		PORT
			LAYER metal1 ;
			RECT 10.928 10.928 10.928 10.928 ;
			END
		END IP1
	PIN IP2
		DIRECTION INPUT ;
		USE SIGNAL ;
		PORT
			LAYER metal1 ;
			RECT 10.928 10.928 10.928 10.928 ;
			END
		END IP2
	PIN IP3
		DIRECTION INPUT ;
		USE SIGNAL ;
		PORT
			LAYER metal1 ;
			RECT 10.928 10.928 10.928 10.928 ;
			END
		END IP3
	PIN IP4
		DIRECTION INPUT ;
		USE SIGNAL ;
		PORT
			LAYER metal1 ;
			RECT 10.928 10.928 10.928 10.928 ;
			END
		END IP4
	PIN IP5
		DIRECTION INPUT ;
		USE SIGNAL ;
		PORT
			LAYER metal1 ;
			RECT 10.928 10.928 10.928 10.928 ;
			END
		END IP5
	PIN IP6
		DIRECTION INPUT ;
		USE SIGNAL ;
		PORT
			LAYER metal1 ;
			RECT 10.928 10.928 10.928 10.928 ;
			END
		END IP6
	PIN IP7
		DIRECTION INPUT ;
		USE SIGNAL ;
		PORT
			LAYER metal1 ;
			RECT 10.928 10.928 10.928 10.928 ;
			END
		END IP7
	PIN IP8
		DIRECTION INPUT ;
		USE SIGNAL ;
		PORT
			LAYER metal1 ;
			RECT 10.928 10.928 10.928 10.928 ;
			END
		END IP8
	PIN IP9
		DIRECTION INPUT ;
		USE SIGNAL ;
		PORT
			LAYER metal1 ;
			RECT 10.928 10.928 10.928 10.928 ;
			END
		END IP9
	PIN IP10
		DIRECTION INPUT ;
		USE SIGNAL ;
		PORT
			LAYER metal1 ;
			RECT 10.928 10.928 10.928 10.928 ;
			END
		END IP10
	PIN IP11
		DIRECTION INPUT ;
		USE SIGNAL ;
		PORT
			LAYER metal1 ;
			RECT 10.928 10.928 10.928 10.928 ;
			END
		END IP11
	PIN IP12
		DIRECTION INPUT ;
		USE SIGNAL ;
		PORT
			LAYER metal1 ;
			RECT 10.928 10.928 10.928 10.928 ;
			END
		END IP12
	PIN IP13
		DIRECTION INPUT ;
		USE SIGNAL ;
		PORT
			LAYER metal1 ;
			RECT 10.928 10.928 10.928 10.928 ;
			END
		END IP13
	PIN IP14
		DIRECTION INPUT ;
		USE SIGNAL ;
		PORT
			LAYER metal1 ;
			RECT 10.928 10.928 10.928 10.928 ;
			END
		END IP14
	PIN IP15
		DIRECTION INPUT ;
		USE SIGNAL ;
		PORT
			LAYER metal1 ;
			RECT 10.928 10.928 10.928 10.928 ;
			END
		END IP15
	PIN IP16
		DIRECTION INPUT ;
		USE SIGNAL ;
		PORT
			LAYER metal1 ;
			RECT 10.928 10.928 10.928 10.928 ;
			END
		END IP16
	PIN IP17
		DIRECTION INPUT ;
		USE SIGNAL ;
		PORT
			LAYER metal1 ;
			RECT 10.928 10.928 10.928 10.928 ;
			END
		END IP17
	PIN IP18
		DIRECTION INPUT ;
		USE SIGNAL ;
		PORT
			LAYER metal1 ;
			RECT 10.928 10.928 10.928 10.928 ;
			END
		END IP18
	PIN IP19
		DIRECTION INPUT ;
		USE SIGNAL ;
		PORT
			LAYER metal1 ;
			RECT 10.928 10.928 10.928 10.928 ;
			END
		END IP19
	PIN IP20
		DIRECTION INPUT ;
		USE SIGNAL ;
		PORT
			LAYER metal1 ;
			RECT 10.928 10.928 10.928 10.928 ;
			END
		END IP20
	PIN IP21
		DIRECTION INPUT ;
		USE SIGNAL ;
		PORT
			LAYER metal1 ;
			RECT 10.928 10.928 10.928 10.928 ;
			END
		END IP21
	PIN IP22
		DIRECTION INPUT ;
		USE SIGNAL ;
		PORT
			LAYER metal1 ;
			RECT 10.928 10.928 10.928 10.928 ;
			END
		END IP22
	PIN IP23
		DIRECTION INPUT ;
		USE SIGNAL ;
		PORT
			LAYER metal1 ;
			RECT 10.928 10.928 10.928 10.928 ;
			END
		END IP23
	PIN IP24
		DIRECTION INPUT ;
		USE SIGNAL ;
		PORT
			LAYER metal1 ;
			RECT 10.928 10.928 10.928 10.928 ;
			END
		END IP24
	PIN IP25
		DIRECTION INPUT ;
		USE SIGNAL ;
		PORT
			LAYER metal1 ;
			RECT 10.928 10.928 10.928 10.928 ;
			END
		END IP25
	PIN IP26
		DIRECTION INPUT ;
		USE SIGNAL ;
		PORT
			LAYER metal1 ;
			RECT 10.928 10.928 10.928 10.928 ;
			END
		END IP26
	PIN IP27
		DIRECTION INPUT ;
		USE SIGNAL ;
		PORT
			LAYER metal1 ;
			RECT 10.928 10.928 10.928 10.928 ;
			END
		END IP27
	PIN IP28
		DIRECTION INPUT ;
		USE SIGNAL ;
		PORT
			LAYER metal1 ;
			RECT 10.928 10.928 10.928 10.928 ;
			END
		END IP28
	PIN IP29
		DIRECTION INPUT ;
		USE SIGNAL ;
		PORT
			LAYER metal1 ;
			RECT 10.928 10.928 10.928 10.928 ;
			END
		END IP29
	PIN IP30
		DIRECTION INPUT ;
		USE SIGNAL ;
		PORT
			LAYER metal1 ;
			RECT 10.928 10.928 10.928 10.928 ;
			END
		END IP30
	PIN IP31
		DIRECTION INPUT ;
		USE SIGNAL ;
		PORT
			LAYER metal1 ;
			RECT 10.928 10.928 10.928 10.928 ;
			END
		END IP31
	PIN IP32
		DIRECTION INPUT ;
		USE SIGNAL ;
		PORT
			LAYER metal1 ;
			RECT 10.928 10.928 10.928 10.928 ;
			END
		END IP32
	PIN IP33
		DIRECTION INPUT ;
		USE SIGNAL ;
		PORT
			LAYER metal1 ;
			RECT 10.928 10.928 10.928 10.928 ;
			END
		END IP33
	PIN IP34
		DIRECTION INPUT ;
		USE SIGNAL ;
		PORT
			LAYER metal1 ;
			RECT 10.928 10.928 10.928 10.928 ;
			END
		END IP34
	PIN IP35
		DIRECTION INPUT ;
		USE SIGNAL ;
		PORT
			LAYER metal1 ;
			RECT 10.928 10.928 10.928 10.928 ;
			END
		END IP35
	PIN IP36
		DIRECTION INPUT ;
		USE SIGNAL ;
		PORT
			LAYER metal1 ;
			RECT 10.928 10.928 10.928 10.928 ;
			END
		END IP36
	PIN IP37
		DIRECTION INPUT ;
		USE SIGNAL ;
		PORT
			LAYER metal1 ;
			RECT 10.928 10.928 10.928 10.928 ;
			END
		END IP37
	PIN IP38
		DIRECTION INPUT ;
		USE SIGNAL ;
		PORT
			LAYER metal1 ;
			RECT 10.928 10.928 10.928 10.928 ;
			END
		END IP38
	PIN IP39
		DIRECTION INPUT ;
		USE SIGNAL ;
		PORT
			LAYER metal1 ;
			RECT 10.928 10.928 10.928 10.928 ;
			END
		END IP39
	PIN IP40
		DIRECTION INPUT ;
		USE SIGNAL ;
		PORT
			LAYER metal1 ;
			RECT 10.928 10.928 10.928 10.928 ;
			END
		END IP40
	PIN IP41
		DIRECTION INPUT ;
		USE SIGNAL ;
		PORT
			LAYER metal1 ;
			RECT 10.928 10.928 10.928 10.928 ;
			END
		END IP41
	PIN IP42
		DIRECTION INPUT ;
		USE SIGNAL ;
		PORT
			LAYER metal1 ;
			RECT 10.928 10.928 10.928 10.928 ;
			END
		END IP42
	PIN IP43
		DIRECTION INPUT ;
		USE SIGNAL ;
		PORT
			LAYER metal1 ;
			RECT 10.928 10.928 10.928 10.928 ;
			END
		END IP43
	PIN IP44
		DIRECTION INPUT ;
		USE SIGNAL ;
		PORT
			LAYER metal1 ;
			RECT 10.928 10.928 10.928 10.928 ;
			END
		END IP44
	PIN IP45
		DIRECTION INPUT ;
		USE SIGNAL ;
		PORT
			LAYER metal1 ;
			RECT 10.928 10.928 10.928 10.928 ;
			END
		END IP45
	PIN IP46
		DIRECTION INPUT ;
		USE SIGNAL ;
		PORT
			LAYER metal1 ;
			RECT 10.928 10.928 10.928 10.928 ;
			END
		END IP46
	PIN IP47
		DIRECTION INPUT ;
		USE SIGNAL ;
		PORT
			LAYER metal1 ;
			RECT 10.928 10.928 10.928 10.928 ;
			END
		END IP47
	PIN IP48
		DIRECTION INPUT ;
		USE SIGNAL ;
		PORT
			LAYER metal1 ;
			RECT 10.928 10.928 10.928 10.928 ;
			END
		END IP48
	PIN IP49
		DIRECTION INPUT ;
		USE SIGNAL ;
		PORT
			LAYER metal1 ;
			RECT 10.928 10.928 10.928 10.928 ;
			END
		END IP49
	PIN IP50
		DIRECTION INPUT ;
		USE SIGNAL ;
		PORT
			LAYER metal1 ;
			RECT 10.928 10.928 10.928 10.928 ;
			END
		END IP50
	PIN IP51
		DIRECTION INPUT ;
		USE SIGNAL ;
		PORT
			LAYER metal1 ;
			RECT 10.928 10.928 10.928 10.928 ;
			END
		END IP51
END cluster_20
MACRO cluster_21
	CLASS BLOCK ;
	ORIGIN 0 0 ;
	FOREIGN cluster_21 0 0 ;
	SIZE 20.161 BY 20.16 ;
	SYMMETRY X Y ;
	PIN OP0
		DIRECTION OUTPUT ;
		USE SIGNAL ;
		PORT
			LAYER metal1 ;
			RECT 10.081 10.08 10.081 10.08 ;
			END
		END OP0
	PIN OP1
		DIRECTION OUTPUT ;
		USE SIGNAL ;
		PORT
			LAYER metal1 ;
			RECT 10.081 10.08 10.081 10.08 ;
			END
		END OP1
	PIN OP2
		DIRECTION OUTPUT ;
		USE SIGNAL ;
		PORT
			LAYER metal1 ;
			RECT 10.081 10.08 10.081 10.08 ;
			END
		END OP2
	PIN OP3
		DIRECTION OUTPUT ;
		USE SIGNAL ;
		PORT
			LAYER metal1 ;
			RECT 10.081 10.08 10.081 10.08 ;
			END
		END OP3
	PIN OP4
		DIRECTION OUTPUT ;
		USE SIGNAL ;
		PORT
			LAYER metal1 ;
			RECT 10.081 10.08 10.081 10.08 ;
			END
		END OP4
	PIN OP5
		DIRECTION OUTPUT ;
		USE SIGNAL ;
		PORT
			LAYER metal1 ;
			RECT 10.081 10.08 10.081 10.08 ;
			END
		END OP5
	PIN OP6
		DIRECTION OUTPUT ;
		USE SIGNAL ;
		PORT
			LAYER metal1 ;
			RECT 10.081 10.08 10.081 10.08 ;
			END
		END OP6
	PIN OP7
		DIRECTION OUTPUT ;
		USE SIGNAL ;
		PORT
			LAYER metal1 ;
			RECT 10.081 10.08 10.081 10.08 ;
			END
		END OP7
	PIN OP8
		DIRECTION OUTPUT ;
		USE SIGNAL ;
		PORT
			LAYER metal1 ;
			RECT 10.081 10.08 10.081 10.08 ;
			END
		END OP8
	PIN OP9
		DIRECTION OUTPUT ;
		USE SIGNAL ;
		PORT
			LAYER metal1 ;
			RECT 10.081 10.08 10.081 10.08 ;
			END
		END OP9
	PIN OP10
		DIRECTION OUTPUT ;
		USE SIGNAL ;
		PORT
			LAYER metal1 ;
			RECT 10.081 10.08 10.081 10.08 ;
			END
		END OP10
	PIN OP11
		DIRECTION OUTPUT ;
		USE SIGNAL ;
		PORT
			LAYER metal1 ;
			RECT 10.081 10.08 10.081 10.08 ;
			END
		END OP11
	PIN OP12
		DIRECTION OUTPUT ;
		USE SIGNAL ;
		PORT
			LAYER metal1 ;
			RECT 10.081 10.08 10.081 10.08 ;
			END
		END OP12
	PIN OP13
		DIRECTION OUTPUT ;
		USE SIGNAL ;
		PORT
			LAYER metal1 ;
			RECT 10.081 10.08 10.081 10.08 ;
			END
		END OP13
	PIN OP14
		DIRECTION OUTPUT ;
		USE SIGNAL ;
		PORT
			LAYER metal1 ;
			RECT 10.081 10.08 10.081 10.08 ;
			END
		END OP14
	PIN OP15
		DIRECTION OUTPUT ;
		USE SIGNAL ;
		PORT
			LAYER metal1 ;
			RECT 10.081 10.08 10.081 10.08 ;
			END
		END OP15
	PIN OP16
		DIRECTION OUTPUT ;
		USE SIGNAL ;
		PORT
			LAYER metal1 ;
			RECT 10.081 10.08 10.081 10.08 ;
			END
		END OP16
	PIN OP17
		DIRECTION OUTPUT ;
		USE SIGNAL ;
		PORT
			LAYER metal1 ;
			RECT 10.081 10.08 10.081 10.08 ;
			END
		END OP17
	PIN OP18
		DIRECTION OUTPUT ;
		USE SIGNAL ;
		PORT
			LAYER metal1 ;
			RECT 10.081 10.08 10.081 10.08 ;
			END
		END OP18
	PIN OP19
		DIRECTION OUTPUT ;
		USE SIGNAL ;
		PORT
			LAYER metal1 ;
			RECT 10.081 10.08 10.081 10.08 ;
			END
		END OP19
	PIN OP20
		DIRECTION OUTPUT ;
		USE SIGNAL ;
		PORT
			LAYER metal1 ;
			RECT 10.081 10.08 10.081 10.08 ;
			END
		END OP20
	PIN OP21
		DIRECTION OUTPUT ;
		USE SIGNAL ;
		PORT
			LAYER metal1 ;
			RECT 10.081 10.08 10.081 10.08 ;
			END
		END OP21
	PIN OP22
		DIRECTION OUTPUT ;
		USE SIGNAL ;
		PORT
			LAYER metal1 ;
			RECT 10.081 10.08 10.081 10.08 ;
			END
		END OP22
	PIN OP23
		DIRECTION OUTPUT ;
		USE SIGNAL ;
		PORT
			LAYER metal1 ;
			RECT 10.081 10.08 10.081 10.08 ;
			END
		END OP23
	PIN OP24
		DIRECTION OUTPUT ;
		USE SIGNAL ;
		PORT
			LAYER metal1 ;
			RECT 10.081 10.08 10.081 10.08 ;
			END
		END OP24
	PIN OP25
		DIRECTION OUTPUT ;
		USE SIGNAL ;
		PORT
			LAYER metal1 ;
			RECT 10.081 10.08 10.081 10.08 ;
			END
		END OP25
	PIN OP26
		DIRECTION OUTPUT ;
		USE SIGNAL ;
		PORT
			LAYER metal1 ;
			RECT 10.081 10.08 10.081 10.08 ;
			END
		END OP26
	PIN OP27
		DIRECTION OUTPUT ;
		USE SIGNAL ;
		PORT
			LAYER metal1 ;
			RECT 10.081 10.08 10.081 10.08 ;
			END
		END OP27
	PIN OP28
		DIRECTION OUTPUT ;
		USE SIGNAL ;
		PORT
			LAYER metal1 ;
			RECT 10.081 10.08 10.081 10.08 ;
			END
		END OP28
	PIN OP29
		DIRECTION OUTPUT ;
		USE SIGNAL ;
		PORT
			LAYER metal1 ;
			RECT 10.081 10.08 10.081 10.08 ;
			END
		END OP29
	PIN OP30
		DIRECTION OUTPUT ;
		USE SIGNAL ;
		PORT
			LAYER metal1 ;
			RECT 10.081 10.08 10.081 10.08 ;
			END
		END OP30
	PIN OP31
		DIRECTION OUTPUT ;
		USE SIGNAL ;
		PORT
			LAYER metal1 ;
			RECT 10.081 10.08 10.081 10.08 ;
			END
		END OP31
	PIN OP32
		DIRECTION OUTPUT ;
		USE SIGNAL ;
		PORT
			LAYER metal1 ;
			RECT 10.081 10.08 10.081 10.08 ;
			END
		END OP32
	PIN OP33
		DIRECTION OUTPUT ;
		USE SIGNAL ;
		PORT
			LAYER metal1 ;
			RECT 10.081 10.08 10.081 10.08 ;
			END
		END OP33
	PIN OP34
		DIRECTION OUTPUT ;
		USE SIGNAL ;
		PORT
			LAYER metal1 ;
			RECT 10.081 10.08 10.081 10.08 ;
			END
		END OP34
	PIN OP35
		DIRECTION OUTPUT ;
		USE SIGNAL ;
		PORT
			LAYER metal1 ;
			RECT 10.081 10.08 10.081 10.08 ;
			END
		END OP35
	PIN OP36
		DIRECTION OUTPUT ;
		USE SIGNAL ;
		PORT
			LAYER metal1 ;
			RECT 10.081 10.08 10.081 10.08 ;
			END
		END OP36
	PIN OP37
		DIRECTION OUTPUT ;
		USE SIGNAL ;
		PORT
			LAYER metal1 ;
			RECT 10.081 10.08 10.081 10.08 ;
			END
		END OP37
	PIN OP38
		DIRECTION OUTPUT ;
		USE SIGNAL ;
		PORT
			LAYER metal1 ;
			RECT 10.081 10.08 10.081 10.08 ;
			END
		END OP38
	PIN OP39
		DIRECTION OUTPUT ;
		USE SIGNAL ;
		PORT
			LAYER metal1 ;
			RECT 10.081 10.08 10.081 10.08 ;
			END
		END OP39
	PIN OP40
		DIRECTION OUTPUT ;
		USE SIGNAL ;
		PORT
			LAYER metal1 ;
			RECT 10.081 10.08 10.081 10.08 ;
			END
		END OP40
	PIN OP41
		DIRECTION OUTPUT ;
		USE SIGNAL ;
		PORT
			LAYER metal1 ;
			RECT 10.081 10.08 10.081 10.08 ;
			END
		END OP41
	PIN OP42
		DIRECTION OUTPUT ;
		USE SIGNAL ;
		PORT
			LAYER metal1 ;
			RECT 10.081 10.08 10.081 10.08 ;
			END
		END OP42
	PIN OP43
		DIRECTION OUTPUT ;
		USE SIGNAL ;
		PORT
			LAYER metal1 ;
			RECT 10.081 10.08 10.081 10.08 ;
			END
		END OP43
	PIN OP44
		DIRECTION OUTPUT ;
		USE SIGNAL ;
		PORT
			LAYER metal1 ;
			RECT 10.081 10.08 10.081 10.08 ;
			END
		END OP44
	PIN OP45
		DIRECTION OUTPUT ;
		USE SIGNAL ;
		PORT
			LAYER metal1 ;
			RECT 10.081 10.08 10.081 10.08 ;
			END
		END OP45
	PIN OP46
		DIRECTION OUTPUT ;
		USE SIGNAL ;
		PORT
			LAYER metal1 ;
			RECT 10.081 10.08 10.081 10.08 ;
			END
		END OP46
	PIN OP47
		DIRECTION OUTPUT ;
		USE SIGNAL ;
		PORT
			LAYER metal1 ;
			RECT 10.081 10.08 10.081 10.08 ;
			END
		END OP47
	PIN OP48
		DIRECTION OUTPUT ;
		USE SIGNAL ;
		PORT
			LAYER metal1 ;
			RECT 10.081 10.08 10.081 10.08 ;
			END
		END OP48
	PIN OP49
		DIRECTION OUTPUT ;
		USE SIGNAL ;
		PORT
			LAYER metal1 ;
			RECT 10.081 10.08 10.081 10.08 ;
			END
		END OP49
	PIN OP50
		DIRECTION OUTPUT ;
		USE SIGNAL ;
		PORT
			LAYER metal1 ;
			RECT 10.081 10.08 10.081 10.08 ;
			END
		END OP50
	PIN OP51
		DIRECTION OUTPUT ;
		USE SIGNAL ;
		PORT
			LAYER metal1 ;
			RECT 10.081 10.08 10.081 10.08 ;
			END
		END OP51
	PIN OP52
		DIRECTION OUTPUT ;
		USE SIGNAL ;
		PORT
			LAYER metal1 ;
			RECT 10.081 10.08 10.081 10.08 ;
			END
		END OP52
	PIN OP53
		DIRECTION OUTPUT ;
		USE SIGNAL ;
		PORT
			LAYER metal1 ;
			RECT 10.081 10.08 10.081 10.08 ;
			END
		END OP53
	PIN OP54
		DIRECTION OUTPUT ;
		USE SIGNAL ;
		PORT
			LAYER metal1 ;
			RECT 10.081 10.08 10.081 10.08 ;
			END
		END OP54
	PIN OP55
		DIRECTION OUTPUT ;
		USE SIGNAL ;
		PORT
			LAYER metal1 ;
			RECT 10.081 10.08 10.081 10.08 ;
			END
		END OP55
	PIN OP56
		DIRECTION OUTPUT ;
		USE SIGNAL ;
		PORT
			LAYER metal1 ;
			RECT 10.081 10.08 10.081 10.08 ;
			END
		END OP56
	PIN OP57
		DIRECTION OUTPUT ;
		USE SIGNAL ;
		PORT
			LAYER metal1 ;
			RECT 10.081 10.08 10.081 10.08 ;
			END
		END OP57
	PIN OP58
		DIRECTION OUTPUT ;
		USE SIGNAL ;
		PORT
			LAYER metal1 ;
			RECT 10.081 10.08 10.081 10.08 ;
			END
		END OP58
	PIN OP59
		DIRECTION OUTPUT ;
		USE SIGNAL ;
		PORT
			LAYER metal1 ;
			RECT 10.081 10.08 10.081 10.08 ;
			END
		END OP59
	PIN OP60
		DIRECTION OUTPUT ;
		USE SIGNAL ;
		PORT
			LAYER metal1 ;
			RECT 10.081 10.08 10.081 10.08 ;
			END
		END OP60
	PIN OP61
		DIRECTION OUTPUT ;
		USE SIGNAL ;
		PORT
			LAYER metal1 ;
			RECT 10.081 10.08 10.081 10.08 ;
			END
		END OP61
	PIN OP62
		DIRECTION OUTPUT ;
		USE SIGNAL ;
		PORT
			LAYER metal1 ;
			RECT 10.081 10.08 10.081 10.08 ;
			END
		END OP62
	PIN OP63
		DIRECTION OUTPUT ;
		USE SIGNAL ;
		PORT
			LAYER metal1 ;
			RECT 10.081 10.08 10.081 10.08 ;
			END
		END OP63
	PIN OP64
		DIRECTION OUTPUT ;
		USE SIGNAL ;
		PORT
			LAYER metal1 ;
			RECT 10.081 10.08 10.081 10.08 ;
			END
		END OP64
	PIN OP65
		DIRECTION OUTPUT ;
		USE SIGNAL ;
		PORT
			LAYER metal1 ;
			RECT 10.081 10.08 10.081 10.08 ;
			END
		END OP65
	PIN OP66
		DIRECTION OUTPUT ;
		USE SIGNAL ;
		PORT
			LAYER metal1 ;
			RECT 10.081 10.08 10.081 10.08 ;
			END
		END OP66
	PIN OP67
		DIRECTION OUTPUT ;
		USE SIGNAL ;
		PORT
			LAYER metal1 ;
			RECT 10.081 10.08 10.081 10.08 ;
			END
		END OP67
	PIN OP68
		DIRECTION OUTPUT ;
		USE SIGNAL ;
		PORT
			LAYER metal1 ;
			RECT 10.081 10.08 10.081 10.08 ;
			END
		END OP68
	PIN IP0
		DIRECTION INPUT ;
		USE SIGNAL ;
		PORT
			LAYER metal1 ;
			RECT 10.081 10.08 10.081 10.08 ;
			END
		END IP0
	PIN IP1
		DIRECTION INPUT ;
		USE SIGNAL ;
		PORT
			LAYER metal1 ;
			RECT 10.081 10.08 10.081 10.08 ;
			END
		END IP1
	PIN IP2
		DIRECTION INPUT ;
		USE SIGNAL ;
		PORT
			LAYER metal1 ;
			RECT 10.081 10.08 10.081 10.08 ;
			END
		END IP2
	PIN IP3
		DIRECTION INPUT ;
		USE SIGNAL ;
		PORT
			LAYER metal1 ;
			RECT 10.081 10.08 10.081 10.08 ;
			END
		END IP3
	PIN IP4
		DIRECTION INPUT ;
		USE SIGNAL ;
		PORT
			LAYER metal1 ;
			RECT 10.081 10.08 10.081 10.08 ;
			END
		END IP4
	PIN IP5
		DIRECTION INPUT ;
		USE SIGNAL ;
		PORT
			LAYER metal1 ;
			RECT 10.081 10.08 10.081 10.08 ;
			END
		END IP5
	PIN IP6
		DIRECTION INPUT ;
		USE SIGNAL ;
		PORT
			LAYER metal1 ;
			RECT 10.081 10.08 10.081 10.08 ;
			END
		END IP6
	PIN IP7
		DIRECTION INPUT ;
		USE SIGNAL ;
		PORT
			LAYER metal1 ;
			RECT 10.081 10.08 10.081 10.08 ;
			END
		END IP7
	PIN IP8
		DIRECTION INPUT ;
		USE SIGNAL ;
		PORT
			LAYER metal1 ;
			RECT 10.081 10.08 10.081 10.08 ;
			END
		END IP8
	PIN IP9
		DIRECTION INPUT ;
		USE SIGNAL ;
		PORT
			LAYER metal1 ;
			RECT 10.081 10.08 10.081 10.08 ;
			END
		END IP9
	PIN IP10
		DIRECTION INPUT ;
		USE SIGNAL ;
		PORT
			LAYER metal1 ;
			RECT 10.081 10.08 10.081 10.08 ;
			END
		END IP10
	PIN IP11
		DIRECTION INPUT ;
		USE SIGNAL ;
		PORT
			LAYER metal1 ;
			RECT 10.081 10.08 10.081 10.08 ;
			END
		END IP11
	PIN IP12
		DIRECTION INPUT ;
		USE SIGNAL ;
		PORT
			LAYER metal1 ;
			RECT 10.081 10.08 10.081 10.08 ;
			END
		END IP12
	PIN IP13
		DIRECTION INPUT ;
		USE SIGNAL ;
		PORT
			LAYER metal1 ;
			RECT 10.081 10.08 10.081 10.08 ;
			END
		END IP13
	PIN IP14
		DIRECTION INPUT ;
		USE SIGNAL ;
		PORT
			LAYER metal1 ;
			RECT 10.081 10.08 10.081 10.08 ;
			END
		END IP14
	PIN IP15
		DIRECTION INPUT ;
		USE SIGNAL ;
		PORT
			LAYER metal1 ;
			RECT 10.081 10.08 10.081 10.08 ;
			END
		END IP15
	PIN IP16
		DIRECTION INPUT ;
		USE SIGNAL ;
		PORT
			LAYER metal1 ;
			RECT 10.081 10.08 10.081 10.08 ;
			END
		END IP16
	PIN IP17
		DIRECTION INPUT ;
		USE SIGNAL ;
		PORT
			LAYER metal1 ;
			RECT 10.081 10.08 10.081 10.08 ;
			END
		END IP17
	PIN IP18
		DIRECTION INPUT ;
		USE SIGNAL ;
		PORT
			LAYER metal1 ;
			RECT 10.081 10.08 10.081 10.08 ;
			END
		END IP18
	PIN IP19
		DIRECTION INPUT ;
		USE SIGNAL ;
		PORT
			LAYER metal1 ;
			RECT 10.081 10.08 10.081 10.08 ;
			END
		END IP19
	PIN IP20
		DIRECTION INPUT ;
		USE SIGNAL ;
		PORT
			LAYER metal1 ;
			RECT 10.081 10.08 10.081 10.08 ;
			END
		END IP20
	PIN IP21
		DIRECTION INPUT ;
		USE SIGNAL ;
		PORT
			LAYER metal1 ;
			RECT 10.081 10.08 10.081 10.08 ;
			END
		END IP21
	PIN IP22
		DIRECTION INPUT ;
		USE SIGNAL ;
		PORT
			LAYER metal1 ;
			RECT 10.081 10.08 10.081 10.08 ;
			END
		END IP22
	PIN IP23
		DIRECTION INPUT ;
		USE SIGNAL ;
		PORT
			LAYER metal1 ;
			RECT 10.081 10.08 10.081 10.08 ;
			END
		END IP23
	PIN IP24
		DIRECTION INPUT ;
		USE SIGNAL ;
		PORT
			LAYER metal1 ;
			RECT 10.081 10.08 10.081 10.08 ;
			END
		END IP24
	PIN IP25
		DIRECTION INPUT ;
		USE SIGNAL ;
		PORT
			LAYER metal1 ;
			RECT 10.081 10.08 10.081 10.08 ;
			END
		END IP25
	PIN IP26
		DIRECTION INPUT ;
		USE SIGNAL ;
		PORT
			LAYER metal1 ;
			RECT 10.081 10.08 10.081 10.08 ;
			END
		END IP26
	PIN IP27
		DIRECTION INPUT ;
		USE SIGNAL ;
		PORT
			LAYER metal1 ;
			RECT 10.081 10.08 10.081 10.08 ;
			END
		END IP27
	PIN IP28
		DIRECTION INPUT ;
		USE SIGNAL ;
		PORT
			LAYER metal1 ;
			RECT 10.081 10.08 10.081 10.08 ;
			END
		END IP28
	PIN IP29
		DIRECTION INPUT ;
		USE SIGNAL ;
		PORT
			LAYER metal1 ;
			RECT 10.081 10.08 10.081 10.08 ;
			END
		END IP29
	PIN IP30
		DIRECTION INPUT ;
		USE SIGNAL ;
		PORT
			LAYER metal1 ;
			RECT 10.081 10.08 10.081 10.08 ;
			END
		END IP30
	PIN IP31
		DIRECTION INPUT ;
		USE SIGNAL ;
		PORT
			LAYER metal1 ;
			RECT 10.081 10.08 10.081 10.08 ;
			END
		END IP31
	PIN IP32
		DIRECTION INPUT ;
		USE SIGNAL ;
		PORT
			LAYER metal1 ;
			RECT 10.081 10.08 10.081 10.08 ;
			END
		END IP32
	PIN IP33
		DIRECTION INPUT ;
		USE SIGNAL ;
		PORT
			LAYER metal1 ;
			RECT 10.081 10.08 10.081 10.08 ;
			END
		END IP33
	PIN IP34
		DIRECTION INPUT ;
		USE SIGNAL ;
		PORT
			LAYER metal1 ;
			RECT 10.081 10.08 10.081 10.08 ;
			END
		END IP34
	PIN IP35
		DIRECTION INPUT ;
		USE SIGNAL ;
		PORT
			LAYER metal1 ;
			RECT 10.081 10.08 10.081 10.08 ;
			END
		END IP35
	PIN IP36
		DIRECTION INPUT ;
		USE SIGNAL ;
		PORT
			LAYER metal1 ;
			RECT 10.081 10.08 10.081 10.08 ;
			END
		END IP36
	PIN IP37
		DIRECTION INPUT ;
		USE SIGNAL ;
		PORT
			LAYER metal1 ;
			RECT 10.081 10.08 10.081 10.08 ;
			END
		END IP37
END cluster_21
MACRO cluster_22
	CLASS BLOCK ;
	ORIGIN 0 0 ;
	FOREIGN cluster_22 0 0 ;
	SIZE 14.615 BY 14.615 ;
	SYMMETRY X Y ;
	PIN OP0
		DIRECTION OUTPUT ;
		USE SIGNAL ;
		PORT
			LAYER metal1 ;
			RECT 7.308 7.308 7.308 7.308 ;
			END
		END OP0
	PIN OP1
		DIRECTION OUTPUT ;
		USE SIGNAL ;
		PORT
			LAYER metal1 ;
			RECT 7.308 7.308 7.308 7.308 ;
			END
		END OP1
	PIN OP2
		DIRECTION OUTPUT ;
		USE SIGNAL ;
		PORT
			LAYER metal1 ;
			RECT 7.308 7.308 7.308 7.308 ;
			END
		END OP2
	PIN OP3
		DIRECTION OUTPUT ;
		USE SIGNAL ;
		PORT
			LAYER metal1 ;
			RECT 7.308 7.308 7.308 7.308 ;
			END
		END OP3
	PIN OP4
		DIRECTION OUTPUT ;
		USE SIGNAL ;
		PORT
			LAYER metal1 ;
			RECT 7.308 7.308 7.308 7.308 ;
			END
		END OP4
	PIN OP5
		DIRECTION OUTPUT ;
		USE SIGNAL ;
		PORT
			LAYER metal1 ;
			RECT 7.308 7.308 7.308 7.308 ;
			END
		END OP5
	PIN OP6
		DIRECTION OUTPUT ;
		USE SIGNAL ;
		PORT
			LAYER metal1 ;
			RECT 7.308 7.308 7.308 7.308 ;
			END
		END OP6
	PIN OP7
		DIRECTION OUTPUT ;
		USE SIGNAL ;
		PORT
			LAYER metal1 ;
			RECT 7.308 7.308 7.308 7.308 ;
			END
		END OP7
	PIN OP8
		DIRECTION OUTPUT ;
		USE SIGNAL ;
		PORT
			LAYER metal1 ;
			RECT 7.308 7.308 7.308 7.308 ;
			END
		END OP8
	PIN OP9
		DIRECTION OUTPUT ;
		USE SIGNAL ;
		PORT
			LAYER metal1 ;
			RECT 7.308 7.308 7.308 7.308 ;
			END
		END OP9
	PIN OP10
		DIRECTION OUTPUT ;
		USE SIGNAL ;
		PORT
			LAYER metal1 ;
			RECT 7.308 7.308 7.308 7.308 ;
			END
		END OP10
	PIN OP11
		DIRECTION OUTPUT ;
		USE SIGNAL ;
		PORT
			LAYER metal1 ;
			RECT 7.308 7.308 7.308 7.308 ;
			END
		END OP11
	PIN OP12
		DIRECTION OUTPUT ;
		USE SIGNAL ;
		PORT
			LAYER metal1 ;
			RECT 7.308 7.308 7.308 7.308 ;
			END
		END OP12
	PIN OP13
		DIRECTION OUTPUT ;
		USE SIGNAL ;
		PORT
			LAYER metal1 ;
			RECT 7.308 7.308 7.308 7.308 ;
			END
		END OP13
	PIN OP14
		DIRECTION OUTPUT ;
		USE SIGNAL ;
		PORT
			LAYER metal1 ;
			RECT 7.308 7.308 7.308 7.308 ;
			END
		END OP14
	PIN OP15
		DIRECTION OUTPUT ;
		USE SIGNAL ;
		PORT
			LAYER metal1 ;
			RECT 7.308 7.308 7.308 7.308 ;
			END
		END OP15
	PIN OP16
		DIRECTION OUTPUT ;
		USE SIGNAL ;
		PORT
			LAYER metal1 ;
			RECT 7.308 7.308 7.308 7.308 ;
			END
		END OP16
	PIN OP17
		DIRECTION OUTPUT ;
		USE SIGNAL ;
		PORT
			LAYER metal1 ;
			RECT 7.308 7.308 7.308 7.308 ;
			END
		END OP17
	PIN OP18
		DIRECTION OUTPUT ;
		USE SIGNAL ;
		PORT
			LAYER metal1 ;
			RECT 7.308 7.308 7.308 7.308 ;
			END
		END OP18
	PIN OP19
		DIRECTION OUTPUT ;
		USE SIGNAL ;
		PORT
			LAYER metal1 ;
			RECT 7.308 7.308 7.308 7.308 ;
			END
		END OP19
	PIN OP20
		DIRECTION OUTPUT ;
		USE SIGNAL ;
		PORT
			LAYER metal1 ;
			RECT 7.308 7.308 7.308 7.308 ;
			END
		END OP20
	PIN OP21
		DIRECTION OUTPUT ;
		USE SIGNAL ;
		PORT
			LAYER metal1 ;
			RECT 7.308 7.308 7.308 7.308 ;
			END
		END OP21
	PIN OP22
		DIRECTION OUTPUT ;
		USE SIGNAL ;
		PORT
			LAYER metal1 ;
			RECT 7.308 7.308 7.308 7.308 ;
			END
		END OP22
	PIN OP23
		DIRECTION OUTPUT ;
		USE SIGNAL ;
		PORT
			LAYER metal1 ;
			RECT 7.308 7.308 7.308 7.308 ;
			END
		END OP23
	PIN OP24
		DIRECTION OUTPUT ;
		USE SIGNAL ;
		PORT
			LAYER metal1 ;
			RECT 7.308 7.308 7.308 7.308 ;
			END
		END OP24
	PIN OP25
		DIRECTION OUTPUT ;
		USE SIGNAL ;
		PORT
			LAYER metal1 ;
			RECT 7.308 7.308 7.308 7.308 ;
			END
		END OP25
	PIN OP26
		DIRECTION OUTPUT ;
		USE SIGNAL ;
		PORT
			LAYER metal1 ;
			RECT 7.308 7.308 7.308 7.308 ;
			END
		END OP26
	PIN OP27
		DIRECTION OUTPUT ;
		USE SIGNAL ;
		PORT
			LAYER metal1 ;
			RECT 7.308 7.308 7.308 7.308 ;
			END
		END OP27
	PIN OP28
		DIRECTION OUTPUT ;
		USE SIGNAL ;
		PORT
			LAYER metal1 ;
			RECT 7.308 7.308 7.308 7.308 ;
			END
		END OP28
	PIN IP0
		DIRECTION INPUT ;
		USE SIGNAL ;
		PORT
			LAYER metal1 ;
			RECT 7.308 7.308 7.308 7.308 ;
			END
		END IP0
	PIN IP1
		DIRECTION INPUT ;
		USE SIGNAL ;
		PORT
			LAYER metal1 ;
			RECT 7.308 7.308 7.308 7.308 ;
			END
		END IP1
	PIN IP2
		DIRECTION INPUT ;
		USE SIGNAL ;
		PORT
			LAYER metal1 ;
			RECT 7.308 7.308 7.308 7.308 ;
			END
		END IP2
	PIN IP3
		DIRECTION INPUT ;
		USE SIGNAL ;
		PORT
			LAYER metal1 ;
			RECT 7.308 7.308 7.308 7.308 ;
			END
		END IP3
	PIN IP4
		DIRECTION INPUT ;
		USE SIGNAL ;
		PORT
			LAYER metal1 ;
			RECT 7.308 7.308 7.308 7.308 ;
			END
		END IP4
	PIN IP5
		DIRECTION INPUT ;
		USE SIGNAL ;
		PORT
			LAYER metal1 ;
			RECT 7.308 7.308 7.308 7.308 ;
			END
		END IP5
	PIN IP6
		DIRECTION INPUT ;
		USE SIGNAL ;
		PORT
			LAYER metal1 ;
			RECT 7.308 7.308 7.308 7.308 ;
			END
		END IP6
	PIN IP7
		DIRECTION INPUT ;
		USE SIGNAL ;
		PORT
			LAYER metal1 ;
			RECT 7.308 7.308 7.308 7.308 ;
			END
		END IP7
	PIN IP8
		DIRECTION INPUT ;
		USE SIGNAL ;
		PORT
			LAYER metal1 ;
			RECT 7.308 7.308 7.308 7.308 ;
			END
		END IP8
	PIN IP9
		DIRECTION INPUT ;
		USE SIGNAL ;
		PORT
			LAYER metal1 ;
			RECT 7.308 7.308 7.308 7.308 ;
			END
		END IP9
	PIN IP10
		DIRECTION INPUT ;
		USE SIGNAL ;
		PORT
			LAYER metal1 ;
			RECT 7.308 7.308 7.308 7.308 ;
			END
		END IP10
	PIN IP11
		DIRECTION INPUT ;
		USE SIGNAL ;
		PORT
			LAYER metal1 ;
			RECT 7.308 7.308 7.308 7.308 ;
			END
		END IP11
	PIN IP12
		DIRECTION INPUT ;
		USE SIGNAL ;
		PORT
			LAYER metal1 ;
			RECT 7.308 7.308 7.308 7.308 ;
			END
		END IP12
	PIN IP13
		DIRECTION INPUT ;
		USE SIGNAL ;
		PORT
			LAYER metal1 ;
			RECT 7.308 7.308 7.308 7.308 ;
			END
		END IP13
	PIN IP14
		DIRECTION INPUT ;
		USE SIGNAL ;
		PORT
			LAYER metal1 ;
			RECT 7.308 7.308 7.308 7.308 ;
			END
		END IP14
	PIN IP15
		DIRECTION INPUT ;
		USE SIGNAL ;
		PORT
			LAYER metal1 ;
			RECT 7.308 7.308 7.308 7.308 ;
			END
		END IP15
	PIN IP16
		DIRECTION INPUT ;
		USE SIGNAL ;
		PORT
			LAYER metal1 ;
			RECT 7.308 7.308 7.308 7.308 ;
			END
		END IP16
	PIN IP17
		DIRECTION INPUT ;
		USE SIGNAL ;
		PORT
			LAYER metal1 ;
			RECT 7.308 7.308 7.308 7.308 ;
			END
		END IP17
	PIN IP18
		DIRECTION INPUT ;
		USE SIGNAL ;
		PORT
			LAYER metal1 ;
			RECT 7.308 7.308 7.308 7.308 ;
			END
		END IP18
	PIN IP19
		DIRECTION INPUT ;
		USE SIGNAL ;
		PORT
			LAYER metal1 ;
			RECT 7.308 7.308 7.308 7.308 ;
			END
		END IP19
	PIN IP20
		DIRECTION INPUT ;
		USE SIGNAL ;
		PORT
			LAYER metal1 ;
			RECT 7.308 7.308 7.308 7.308 ;
			END
		END IP20
	PIN IP21
		DIRECTION INPUT ;
		USE SIGNAL ;
		PORT
			LAYER metal1 ;
			RECT 7.308 7.308 7.308 7.308 ;
			END
		END IP21
	PIN IP22
		DIRECTION INPUT ;
		USE SIGNAL ;
		PORT
			LAYER metal1 ;
			RECT 7.308 7.308 7.308 7.308 ;
			END
		END IP22
	PIN IP23
		DIRECTION INPUT ;
		USE SIGNAL ;
		PORT
			LAYER metal1 ;
			RECT 7.308 7.308 7.308 7.308 ;
			END
		END IP23
	PIN IP24
		DIRECTION INPUT ;
		USE SIGNAL ;
		PORT
			LAYER metal1 ;
			RECT 7.308 7.308 7.308 7.308 ;
			END
		END IP24
	PIN IP25
		DIRECTION INPUT ;
		USE SIGNAL ;
		PORT
			LAYER metal1 ;
			RECT 7.308 7.308 7.308 7.308 ;
			END
		END IP25
	PIN IP26
		DIRECTION INPUT ;
		USE SIGNAL ;
		PORT
			LAYER metal1 ;
			RECT 7.308 7.308 7.308 7.308 ;
			END
		END IP26
	PIN IP27
		DIRECTION INPUT ;
		USE SIGNAL ;
		PORT
			LAYER metal1 ;
			RECT 7.308 7.308 7.308 7.308 ;
			END
		END IP27
END cluster_22
MACRO cluster_23
	CLASS BLOCK ;
	ORIGIN 0 0 ;
	FOREIGN cluster_23 0 0 ;
	SIZE 13.518 BY 13.518 ;
	SYMMETRY X Y ;
	PIN OP0
		DIRECTION OUTPUT ;
		USE SIGNAL ;
		PORT
			LAYER metal1 ;
			RECT 6.759 6.759 6.759 6.759 ;
			END
		END OP0
	PIN OP1
		DIRECTION OUTPUT ;
		USE SIGNAL ;
		PORT
			LAYER metal1 ;
			RECT 6.759 6.759 6.759 6.759 ;
			END
		END OP1
	PIN OP2
		DIRECTION OUTPUT ;
		USE SIGNAL ;
		PORT
			LAYER metal1 ;
			RECT 6.759 6.759 6.759 6.759 ;
			END
		END OP2
	PIN OP3
		DIRECTION OUTPUT ;
		USE SIGNAL ;
		PORT
			LAYER metal1 ;
			RECT 6.759 6.759 6.759 6.759 ;
			END
		END OP3
	PIN OP4
		DIRECTION OUTPUT ;
		USE SIGNAL ;
		PORT
			LAYER metal1 ;
			RECT 6.759 6.759 6.759 6.759 ;
			END
		END OP4
	PIN OP5
		DIRECTION OUTPUT ;
		USE SIGNAL ;
		PORT
			LAYER metal1 ;
			RECT 6.759 6.759 6.759 6.759 ;
			END
		END OP5
	PIN OP6
		DIRECTION OUTPUT ;
		USE SIGNAL ;
		PORT
			LAYER metal1 ;
			RECT 6.759 6.759 6.759 6.759 ;
			END
		END OP6
	PIN OP7
		DIRECTION OUTPUT ;
		USE SIGNAL ;
		PORT
			LAYER metal1 ;
			RECT 6.759 6.759 6.759 6.759 ;
			END
		END OP7
	PIN OP8
		DIRECTION OUTPUT ;
		USE SIGNAL ;
		PORT
			LAYER metal1 ;
			RECT 6.759 6.759 6.759 6.759 ;
			END
		END OP8
	PIN OP9
		DIRECTION OUTPUT ;
		USE SIGNAL ;
		PORT
			LAYER metal1 ;
			RECT 6.759 6.759 6.759 6.759 ;
			END
		END OP9
	PIN OP10
		DIRECTION OUTPUT ;
		USE SIGNAL ;
		PORT
			LAYER metal1 ;
			RECT 6.759 6.759 6.759 6.759 ;
			END
		END OP10
	PIN OP11
		DIRECTION OUTPUT ;
		USE SIGNAL ;
		PORT
			LAYER metal1 ;
			RECT 6.759 6.759 6.759 6.759 ;
			END
		END OP11
	PIN OP12
		DIRECTION OUTPUT ;
		USE SIGNAL ;
		PORT
			LAYER metal1 ;
			RECT 6.759 6.759 6.759 6.759 ;
			END
		END OP12
	PIN OP13
		DIRECTION OUTPUT ;
		USE SIGNAL ;
		PORT
			LAYER metal1 ;
			RECT 6.759 6.759 6.759 6.759 ;
			END
		END OP13
	PIN OP14
		DIRECTION OUTPUT ;
		USE SIGNAL ;
		PORT
			LAYER metal1 ;
			RECT 6.759 6.759 6.759 6.759 ;
			END
		END OP14
	PIN OP15
		DIRECTION OUTPUT ;
		USE SIGNAL ;
		PORT
			LAYER metal1 ;
			RECT 6.759 6.759 6.759 6.759 ;
			END
		END OP15
	PIN OP16
		DIRECTION OUTPUT ;
		USE SIGNAL ;
		PORT
			LAYER metal1 ;
			RECT 6.759 6.759 6.759 6.759 ;
			END
		END OP16
	PIN OP17
		DIRECTION OUTPUT ;
		USE SIGNAL ;
		PORT
			LAYER metal1 ;
			RECT 6.759 6.759 6.759 6.759 ;
			END
		END OP17
	PIN OP18
		DIRECTION OUTPUT ;
		USE SIGNAL ;
		PORT
			LAYER metal1 ;
			RECT 6.759 6.759 6.759 6.759 ;
			END
		END OP18
	PIN OP19
		DIRECTION OUTPUT ;
		USE SIGNAL ;
		PORT
			LAYER metal1 ;
			RECT 6.759 6.759 6.759 6.759 ;
			END
		END OP19
	PIN OP20
		DIRECTION OUTPUT ;
		USE SIGNAL ;
		PORT
			LAYER metal1 ;
			RECT 6.759 6.759 6.759 6.759 ;
			END
		END OP20
	PIN OP21
		DIRECTION OUTPUT ;
		USE SIGNAL ;
		PORT
			LAYER metal1 ;
			RECT 6.759 6.759 6.759 6.759 ;
			END
		END OP21
	PIN OP22
		DIRECTION OUTPUT ;
		USE SIGNAL ;
		PORT
			LAYER metal1 ;
			RECT 6.759 6.759 6.759 6.759 ;
			END
		END OP22
	PIN OP23
		DIRECTION OUTPUT ;
		USE SIGNAL ;
		PORT
			LAYER metal1 ;
			RECT 6.759 6.759 6.759 6.759 ;
			END
		END OP23
	PIN OP24
		DIRECTION OUTPUT ;
		USE SIGNAL ;
		PORT
			LAYER metal1 ;
			RECT 6.759 6.759 6.759 6.759 ;
			END
		END OP24
	PIN OP25
		DIRECTION OUTPUT ;
		USE SIGNAL ;
		PORT
			LAYER metal1 ;
			RECT 6.759 6.759 6.759 6.759 ;
			END
		END OP25
	PIN OP26
		DIRECTION OUTPUT ;
		USE SIGNAL ;
		PORT
			LAYER metal1 ;
			RECT 6.759 6.759 6.759 6.759 ;
			END
		END OP26
	PIN OP27
		DIRECTION OUTPUT ;
		USE SIGNAL ;
		PORT
			LAYER metal1 ;
			RECT 6.759 6.759 6.759 6.759 ;
			END
		END OP27
	PIN OP28
		DIRECTION OUTPUT ;
		USE SIGNAL ;
		PORT
			LAYER metal1 ;
			RECT 6.759 6.759 6.759 6.759 ;
			END
		END OP28
	PIN OP29
		DIRECTION OUTPUT ;
		USE SIGNAL ;
		PORT
			LAYER metal1 ;
			RECT 6.759 6.759 6.759 6.759 ;
			END
		END OP29
	PIN OP30
		DIRECTION OUTPUT ;
		USE SIGNAL ;
		PORT
			LAYER metal1 ;
			RECT 6.759 6.759 6.759 6.759 ;
			END
		END OP30
	PIN OP31
		DIRECTION OUTPUT ;
		USE SIGNAL ;
		PORT
			LAYER metal1 ;
			RECT 6.759 6.759 6.759 6.759 ;
			END
		END OP31
	PIN OP32
		DIRECTION OUTPUT ;
		USE SIGNAL ;
		PORT
			LAYER metal1 ;
			RECT 6.759 6.759 6.759 6.759 ;
			END
		END OP32
	PIN OP33
		DIRECTION OUTPUT ;
		USE SIGNAL ;
		PORT
			LAYER metal1 ;
			RECT 6.759 6.759 6.759 6.759 ;
			END
		END OP33
	PIN OP34
		DIRECTION OUTPUT ;
		USE SIGNAL ;
		PORT
			LAYER metal1 ;
			RECT 6.759 6.759 6.759 6.759 ;
			END
		END OP34
	PIN OP35
		DIRECTION OUTPUT ;
		USE SIGNAL ;
		PORT
			LAYER metal1 ;
			RECT 6.759 6.759 6.759 6.759 ;
			END
		END OP35
	PIN OP36
		DIRECTION OUTPUT ;
		USE SIGNAL ;
		PORT
			LAYER metal1 ;
			RECT 6.759 6.759 6.759 6.759 ;
			END
		END OP36
	PIN OP37
		DIRECTION OUTPUT ;
		USE SIGNAL ;
		PORT
			LAYER metal1 ;
			RECT 6.759 6.759 6.759 6.759 ;
			END
		END OP37
	PIN OP38
		DIRECTION OUTPUT ;
		USE SIGNAL ;
		PORT
			LAYER metal1 ;
			RECT 6.759 6.759 6.759 6.759 ;
			END
		END OP38
	PIN OP39
		DIRECTION OUTPUT ;
		USE SIGNAL ;
		PORT
			LAYER metal1 ;
			RECT 6.759 6.759 6.759 6.759 ;
			END
		END OP39
	PIN OP40
		DIRECTION OUTPUT ;
		USE SIGNAL ;
		PORT
			LAYER metal1 ;
			RECT 6.759 6.759 6.759 6.759 ;
			END
		END OP40
	PIN OP41
		DIRECTION OUTPUT ;
		USE SIGNAL ;
		PORT
			LAYER metal1 ;
			RECT 6.759 6.759 6.759 6.759 ;
			END
		END OP41
	PIN OP42
		DIRECTION OUTPUT ;
		USE SIGNAL ;
		PORT
			LAYER metal1 ;
			RECT 6.759 6.759 6.759 6.759 ;
			END
		END OP42
	PIN OP43
		DIRECTION OUTPUT ;
		USE SIGNAL ;
		PORT
			LAYER metal1 ;
			RECT 6.759 6.759 6.759 6.759 ;
			END
		END OP43
	PIN OP44
		DIRECTION OUTPUT ;
		USE SIGNAL ;
		PORT
			LAYER metal1 ;
			RECT 6.759 6.759 6.759 6.759 ;
			END
		END OP44
	PIN OP45
		DIRECTION OUTPUT ;
		USE SIGNAL ;
		PORT
			LAYER metal1 ;
			RECT 6.759 6.759 6.759 6.759 ;
			END
		END OP45
	PIN OP46
		DIRECTION OUTPUT ;
		USE SIGNAL ;
		PORT
			LAYER metal1 ;
			RECT 6.759 6.759 6.759 6.759 ;
			END
		END OP46
	PIN OP47
		DIRECTION OUTPUT ;
		USE SIGNAL ;
		PORT
			LAYER metal1 ;
			RECT 6.759 6.759 6.759 6.759 ;
			END
		END OP47
	PIN OP48
		DIRECTION OUTPUT ;
		USE SIGNAL ;
		PORT
			LAYER metal1 ;
			RECT 6.759 6.759 6.759 6.759 ;
			END
		END OP48
	PIN OP49
		DIRECTION OUTPUT ;
		USE SIGNAL ;
		PORT
			LAYER metal1 ;
			RECT 6.759 6.759 6.759 6.759 ;
			END
		END OP49
	PIN OP50
		DIRECTION OUTPUT ;
		USE SIGNAL ;
		PORT
			LAYER metal1 ;
			RECT 6.759 6.759 6.759 6.759 ;
			END
		END OP50
	PIN OP51
		DIRECTION OUTPUT ;
		USE SIGNAL ;
		PORT
			LAYER metal1 ;
			RECT 6.759 6.759 6.759 6.759 ;
			END
		END OP51
	PIN IP0
		DIRECTION INPUT ;
		USE SIGNAL ;
		PORT
			LAYER metal1 ;
			RECT 6.759 6.759 6.759 6.759 ;
			END
		END IP0
	PIN IP1
		DIRECTION INPUT ;
		USE SIGNAL ;
		PORT
			LAYER metal1 ;
			RECT 6.759 6.759 6.759 6.759 ;
			END
		END IP1
	PIN IP2
		DIRECTION INPUT ;
		USE SIGNAL ;
		PORT
			LAYER metal1 ;
			RECT 6.759 6.759 6.759 6.759 ;
			END
		END IP2
	PIN IP3
		DIRECTION INPUT ;
		USE SIGNAL ;
		PORT
			LAYER metal1 ;
			RECT 6.759 6.759 6.759 6.759 ;
			END
		END IP3
	PIN IP4
		DIRECTION INPUT ;
		USE SIGNAL ;
		PORT
			LAYER metal1 ;
			RECT 6.759 6.759 6.759 6.759 ;
			END
		END IP4
	PIN IP5
		DIRECTION INPUT ;
		USE SIGNAL ;
		PORT
			LAYER metal1 ;
			RECT 6.759 6.759 6.759 6.759 ;
			END
		END IP5
	PIN IP6
		DIRECTION INPUT ;
		USE SIGNAL ;
		PORT
			LAYER metal1 ;
			RECT 6.759 6.759 6.759 6.759 ;
			END
		END IP6
	PIN IP7
		DIRECTION INPUT ;
		USE SIGNAL ;
		PORT
			LAYER metal1 ;
			RECT 6.759 6.759 6.759 6.759 ;
			END
		END IP7
	PIN IP8
		DIRECTION INPUT ;
		USE SIGNAL ;
		PORT
			LAYER metal1 ;
			RECT 6.759 6.759 6.759 6.759 ;
			END
		END IP8
	PIN IP9
		DIRECTION INPUT ;
		USE SIGNAL ;
		PORT
			LAYER metal1 ;
			RECT 6.759 6.759 6.759 6.759 ;
			END
		END IP9
	PIN IP10
		DIRECTION INPUT ;
		USE SIGNAL ;
		PORT
			LAYER metal1 ;
			RECT 6.759 6.759 6.759 6.759 ;
			END
		END IP10
	PIN IP11
		DIRECTION INPUT ;
		USE SIGNAL ;
		PORT
			LAYER metal1 ;
			RECT 6.759 6.759 6.759 6.759 ;
			END
		END IP11
	PIN IP12
		DIRECTION INPUT ;
		USE SIGNAL ;
		PORT
			LAYER metal1 ;
			RECT 6.759 6.759 6.759 6.759 ;
			END
		END IP12
	PIN IP13
		DIRECTION INPUT ;
		USE SIGNAL ;
		PORT
			LAYER metal1 ;
			RECT 6.759 6.759 6.759 6.759 ;
			END
		END IP13
	PIN IP14
		DIRECTION INPUT ;
		USE SIGNAL ;
		PORT
			LAYER metal1 ;
			RECT 6.759 6.759 6.759 6.759 ;
			END
		END IP14
	PIN IP15
		DIRECTION INPUT ;
		USE SIGNAL ;
		PORT
			LAYER metal1 ;
			RECT 6.759 6.759 6.759 6.759 ;
			END
		END IP15
	PIN IP16
		DIRECTION INPUT ;
		USE SIGNAL ;
		PORT
			LAYER metal1 ;
			RECT 6.759 6.759 6.759 6.759 ;
			END
		END IP16
	PIN IP17
		DIRECTION INPUT ;
		USE SIGNAL ;
		PORT
			LAYER metal1 ;
			RECT 6.759 6.759 6.759 6.759 ;
			END
		END IP17
	PIN IP18
		DIRECTION INPUT ;
		USE SIGNAL ;
		PORT
			LAYER metal1 ;
			RECT 6.759 6.759 6.759 6.759 ;
			END
		END IP18
END cluster_23
MACRO cluster_24
	CLASS BLOCK ;
	ORIGIN 0 0 ;
	FOREIGN cluster_24 0 0 ;
	SIZE 13.27 BY 13.27 ;
	SYMMETRY X Y ;
	PIN OP0
		DIRECTION OUTPUT ;
		USE SIGNAL ;
		PORT
			LAYER metal1 ;
			RECT 6.635 6.635 6.635 6.635 ;
			END
		END OP0
	PIN OP1
		DIRECTION OUTPUT ;
		USE SIGNAL ;
		PORT
			LAYER metal1 ;
			RECT 6.635 6.635 6.635 6.635 ;
			END
		END OP1
	PIN OP2
		DIRECTION OUTPUT ;
		USE SIGNAL ;
		PORT
			LAYER metal1 ;
			RECT 6.635 6.635 6.635 6.635 ;
			END
		END OP2
	PIN OP3
		DIRECTION OUTPUT ;
		USE SIGNAL ;
		PORT
			LAYER metal1 ;
			RECT 6.635 6.635 6.635 6.635 ;
			END
		END OP3
	PIN OP4
		DIRECTION OUTPUT ;
		USE SIGNAL ;
		PORT
			LAYER metal1 ;
			RECT 6.635 6.635 6.635 6.635 ;
			END
		END OP4
	PIN OP5
		DIRECTION OUTPUT ;
		USE SIGNAL ;
		PORT
			LAYER metal1 ;
			RECT 6.635 6.635 6.635 6.635 ;
			END
		END OP5
	PIN OP6
		DIRECTION OUTPUT ;
		USE SIGNAL ;
		PORT
			LAYER metal1 ;
			RECT 6.635 6.635 6.635 6.635 ;
			END
		END OP6
	PIN OP7
		DIRECTION OUTPUT ;
		USE SIGNAL ;
		PORT
			LAYER metal1 ;
			RECT 6.635 6.635 6.635 6.635 ;
			END
		END OP7
	PIN OP8
		DIRECTION OUTPUT ;
		USE SIGNAL ;
		PORT
			LAYER metal1 ;
			RECT 6.635 6.635 6.635 6.635 ;
			END
		END OP8
	PIN OP9
		DIRECTION OUTPUT ;
		USE SIGNAL ;
		PORT
			LAYER metal1 ;
			RECT 6.635 6.635 6.635 6.635 ;
			END
		END OP9
	PIN OP10
		DIRECTION OUTPUT ;
		USE SIGNAL ;
		PORT
			LAYER metal1 ;
			RECT 6.635 6.635 6.635 6.635 ;
			END
		END OP10
	PIN OP11
		DIRECTION OUTPUT ;
		USE SIGNAL ;
		PORT
			LAYER metal1 ;
			RECT 6.635 6.635 6.635 6.635 ;
			END
		END OP11
	PIN OP12
		DIRECTION OUTPUT ;
		USE SIGNAL ;
		PORT
			LAYER metal1 ;
			RECT 6.635 6.635 6.635 6.635 ;
			END
		END OP12
	PIN OP13
		DIRECTION OUTPUT ;
		USE SIGNAL ;
		PORT
			LAYER metal1 ;
			RECT 6.635 6.635 6.635 6.635 ;
			END
		END OP13
	PIN OP14
		DIRECTION OUTPUT ;
		USE SIGNAL ;
		PORT
			LAYER metal1 ;
			RECT 6.635 6.635 6.635 6.635 ;
			END
		END OP14
	PIN OP15
		DIRECTION OUTPUT ;
		USE SIGNAL ;
		PORT
			LAYER metal1 ;
			RECT 6.635 6.635 6.635 6.635 ;
			END
		END OP15
	PIN OP16
		DIRECTION OUTPUT ;
		USE SIGNAL ;
		PORT
			LAYER metal1 ;
			RECT 6.635 6.635 6.635 6.635 ;
			END
		END OP16
	PIN OP17
		DIRECTION OUTPUT ;
		USE SIGNAL ;
		PORT
			LAYER metal1 ;
			RECT 6.635 6.635 6.635 6.635 ;
			END
		END OP17
	PIN OP18
		DIRECTION OUTPUT ;
		USE SIGNAL ;
		PORT
			LAYER metal1 ;
			RECT 6.635 6.635 6.635 6.635 ;
			END
		END OP18
	PIN OP19
		DIRECTION OUTPUT ;
		USE SIGNAL ;
		PORT
			LAYER metal1 ;
			RECT 6.635 6.635 6.635 6.635 ;
			END
		END OP19
	PIN OP20
		DIRECTION OUTPUT ;
		USE SIGNAL ;
		PORT
			LAYER metal1 ;
			RECT 6.635 6.635 6.635 6.635 ;
			END
		END OP20
	PIN OP21
		DIRECTION OUTPUT ;
		USE SIGNAL ;
		PORT
			LAYER metal1 ;
			RECT 6.635 6.635 6.635 6.635 ;
			END
		END OP21
	PIN OP22
		DIRECTION OUTPUT ;
		USE SIGNAL ;
		PORT
			LAYER metal1 ;
			RECT 6.635 6.635 6.635 6.635 ;
			END
		END OP22
	PIN OP23
		DIRECTION OUTPUT ;
		USE SIGNAL ;
		PORT
			LAYER metal1 ;
			RECT 6.635 6.635 6.635 6.635 ;
			END
		END OP23
	PIN OP24
		DIRECTION OUTPUT ;
		USE SIGNAL ;
		PORT
			LAYER metal1 ;
			RECT 6.635 6.635 6.635 6.635 ;
			END
		END OP24
	PIN OP25
		DIRECTION OUTPUT ;
		USE SIGNAL ;
		PORT
			LAYER metal1 ;
			RECT 6.635 6.635 6.635 6.635 ;
			END
		END OP25
	PIN OP26
		DIRECTION OUTPUT ;
		USE SIGNAL ;
		PORT
			LAYER metal1 ;
			RECT 6.635 6.635 6.635 6.635 ;
			END
		END OP26
	PIN OP27
		DIRECTION OUTPUT ;
		USE SIGNAL ;
		PORT
			LAYER metal1 ;
			RECT 6.635 6.635 6.635 6.635 ;
			END
		END OP27
	PIN OP28
		DIRECTION OUTPUT ;
		USE SIGNAL ;
		PORT
			LAYER metal1 ;
			RECT 6.635 6.635 6.635 6.635 ;
			END
		END OP28
	PIN OP29
		DIRECTION OUTPUT ;
		USE SIGNAL ;
		PORT
			LAYER metal1 ;
			RECT 6.635 6.635 6.635 6.635 ;
			END
		END OP29
	PIN OP30
		DIRECTION OUTPUT ;
		USE SIGNAL ;
		PORT
			LAYER metal1 ;
			RECT 6.635 6.635 6.635 6.635 ;
			END
		END OP30
	PIN OP31
		DIRECTION OUTPUT ;
		USE SIGNAL ;
		PORT
			LAYER metal1 ;
			RECT 6.635 6.635 6.635 6.635 ;
			END
		END OP31
	PIN OP32
		DIRECTION OUTPUT ;
		USE SIGNAL ;
		PORT
			LAYER metal1 ;
			RECT 6.635 6.635 6.635 6.635 ;
			END
		END OP32
	PIN OP33
		DIRECTION OUTPUT ;
		USE SIGNAL ;
		PORT
			LAYER metal1 ;
			RECT 6.635 6.635 6.635 6.635 ;
			END
		END OP33
	PIN OP34
		DIRECTION OUTPUT ;
		USE SIGNAL ;
		PORT
			LAYER metal1 ;
			RECT 6.635 6.635 6.635 6.635 ;
			END
		END OP34
	PIN OP35
		DIRECTION OUTPUT ;
		USE SIGNAL ;
		PORT
			LAYER metal1 ;
			RECT 6.635 6.635 6.635 6.635 ;
			END
		END OP35
	PIN OP36
		DIRECTION OUTPUT ;
		USE SIGNAL ;
		PORT
			LAYER metal1 ;
			RECT 6.635 6.635 6.635 6.635 ;
			END
		END OP36
	PIN OP37
		DIRECTION OUTPUT ;
		USE SIGNAL ;
		PORT
			LAYER metal1 ;
			RECT 6.635 6.635 6.635 6.635 ;
			END
		END OP37
	PIN OP38
		DIRECTION OUTPUT ;
		USE SIGNAL ;
		PORT
			LAYER metal1 ;
			RECT 6.635 6.635 6.635 6.635 ;
			END
		END OP38
	PIN OP39
		DIRECTION OUTPUT ;
		USE SIGNAL ;
		PORT
			LAYER metal1 ;
			RECT 6.635 6.635 6.635 6.635 ;
			END
		END OP39
	PIN OP40
		DIRECTION OUTPUT ;
		USE SIGNAL ;
		PORT
			LAYER metal1 ;
			RECT 6.635 6.635 6.635 6.635 ;
			END
		END OP40
	PIN OP41
		DIRECTION OUTPUT ;
		USE SIGNAL ;
		PORT
			LAYER metal1 ;
			RECT 6.635 6.635 6.635 6.635 ;
			END
		END OP41
	PIN OP42
		DIRECTION OUTPUT ;
		USE SIGNAL ;
		PORT
			LAYER metal1 ;
			RECT 6.635 6.635 6.635 6.635 ;
			END
		END OP42
	PIN OP43
		DIRECTION OUTPUT ;
		USE SIGNAL ;
		PORT
			LAYER metal1 ;
			RECT 6.635 6.635 6.635 6.635 ;
			END
		END OP43
	PIN OP44
		DIRECTION OUTPUT ;
		USE SIGNAL ;
		PORT
			LAYER metal1 ;
			RECT 6.635 6.635 6.635 6.635 ;
			END
		END OP44
	PIN OP45
		DIRECTION OUTPUT ;
		USE SIGNAL ;
		PORT
			LAYER metal1 ;
			RECT 6.635 6.635 6.635 6.635 ;
			END
		END OP45
	PIN IP0
		DIRECTION INPUT ;
		USE SIGNAL ;
		PORT
			LAYER metal1 ;
			RECT 6.635 6.635 6.635 6.635 ;
			END
		END IP0
	PIN IP1
		DIRECTION INPUT ;
		USE SIGNAL ;
		PORT
			LAYER metal1 ;
			RECT 6.635 6.635 6.635 6.635 ;
			END
		END IP1
	PIN IP2
		DIRECTION INPUT ;
		USE SIGNAL ;
		PORT
			LAYER metal1 ;
			RECT 6.635 6.635 6.635 6.635 ;
			END
		END IP2
	PIN IP3
		DIRECTION INPUT ;
		USE SIGNAL ;
		PORT
			LAYER metal1 ;
			RECT 6.635 6.635 6.635 6.635 ;
			END
		END IP3
	PIN IP4
		DIRECTION INPUT ;
		USE SIGNAL ;
		PORT
			LAYER metal1 ;
			RECT 6.635 6.635 6.635 6.635 ;
			END
		END IP4
	PIN IP5
		DIRECTION INPUT ;
		USE SIGNAL ;
		PORT
			LAYER metal1 ;
			RECT 6.635 6.635 6.635 6.635 ;
			END
		END IP5
	PIN IP6
		DIRECTION INPUT ;
		USE SIGNAL ;
		PORT
			LAYER metal1 ;
			RECT 6.635 6.635 6.635 6.635 ;
			END
		END IP6
	PIN IP7
		DIRECTION INPUT ;
		USE SIGNAL ;
		PORT
			LAYER metal1 ;
			RECT 6.635 6.635 6.635 6.635 ;
			END
		END IP7
	PIN IP8
		DIRECTION INPUT ;
		USE SIGNAL ;
		PORT
			LAYER metal1 ;
			RECT 6.635 6.635 6.635 6.635 ;
			END
		END IP8
	PIN IP9
		DIRECTION INPUT ;
		USE SIGNAL ;
		PORT
			LAYER metal1 ;
			RECT 6.635 6.635 6.635 6.635 ;
			END
		END IP9
	PIN IP10
		DIRECTION INPUT ;
		USE SIGNAL ;
		PORT
			LAYER metal1 ;
			RECT 6.635 6.635 6.635 6.635 ;
			END
		END IP10
	PIN IP11
		DIRECTION INPUT ;
		USE SIGNAL ;
		PORT
			LAYER metal1 ;
			RECT 6.635 6.635 6.635 6.635 ;
			END
		END IP11
	PIN IP12
		DIRECTION INPUT ;
		USE SIGNAL ;
		PORT
			LAYER metal1 ;
			RECT 6.635 6.635 6.635 6.635 ;
			END
		END IP12
	PIN IP13
		DIRECTION INPUT ;
		USE SIGNAL ;
		PORT
			LAYER metal1 ;
			RECT 6.635 6.635 6.635 6.635 ;
			END
		END IP13
	PIN IP14
		DIRECTION INPUT ;
		USE SIGNAL ;
		PORT
			LAYER metal1 ;
			RECT 6.635 6.635 6.635 6.635 ;
			END
		END IP14
END cluster_24
MACRO cluster_25
	CLASS BLOCK ;
	ORIGIN 0 0 ;
	FOREIGN cluster_25 0 0 ;
	SIZE 11.716 BY 11.715 ;
	SYMMETRY X Y ;
	PIN OP0
		DIRECTION OUTPUT ;
		USE SIGNAL ;
		PORT
			LAYER metal1 ;
			RECT 5.858 5.857 5.858 5.857 ;
			END
		END OP0
	PIN OP1
		DIRECTION OUTPUT ;
		USE SIGNAL ;
		PORT
			LAYER metal1 ;
			RECT 5.858 5.857 5.858 5.857 ;
			END
		END OP1
	PIN OP2
		DIRECTION OUTPUT ;
		USE SIGNAL ;
		PORT
			LAYER metal1 ;
			RECT 5.858 5.857 5.858 5.857 ;
			END
		END OP2
	PIN OP3
		DIRECTION OUTPUT ;
		USE SIGNAL ;
		PORT
			LAYER metal1 ;
			RECT 5.858 5.857 5.858 5.857 ;
			END
		END OP3
	PIN OP4
		DIRECTION OUTPUT ;
		USE SIGNAL ;
		PORT
			LAYER metal1 ;
			RECT 5.858 5.857 5.858 5.857 ;
			END
		END OP4
	PIN OP5
		DIRECTION OUTPUT ;
		USE SIGNAL ;
		PORT
			LAYER metal1 ;
			RECT 5.858 5.857 5.858 5.857 ;
			END
		END OP5
	PIN OP6
		DIRECTION OUTPUT ;
		USE SIGNAL ;
		PORT
			LAYER metal1 ;
			RECT 5.858 5.857 5.858 5.857 ;
			END
		END OP6
	PIN OP7
		DIRECTION OUTPUT ;
		USE SIGNAL ;
		PORT
			LAYER metal1 ;
			RECT 5.858 5.857 5.858 5.857 ;
			END
		END OP7
	PIN OP8
		DIRECTION OUTPUT ;
		USE SIGNAL ;
		PORT
			LAYER metal1 ;
			RECT 5.858 5.857 5.858 5.857 ;
			END
		END OP8
	PIN OP9
		DIRECTION OUTPUT ;
		USE SIGNAL ;
		PORT
			LAYER metal1 ;
			RECT 5.858 5.857 5.858 5.857 ;
			END
		END OP9
	PIN OP10
		DIRECTION OUTPUT ;
		USE SIGNAL ;
		PORT
			LAYER metal1 ;
			RECT 5.858 5.857 5.858 5.857 ;
			END
		END OP10
	PIN OP11
		DIRECTION OUTPUT ;
		USE SIGNAL ;
		PORT
			LAYER metal1 ;
			RECT 5.858 5.857 5.858 5.857 ;
			END
		END OP11
	PIN OP12
		DIRECTION OUTPUT ;
		USE SIGNAL ;
		PORT
			LAYER metal1 ;
			RECT 5.858 5.857 5.858 5.857 ;
			END
		END OP12
	PIN OP13
		DIRECTION OUTPUT ;
		USE SIGNAL ;
		PORT
			LAYER metal1 ;
			RECT 5.858 5.857 5.858 5.857 ;
			END
		END OP13
	PIN OP14
		DIRECTION OUTPUT ;
		USE SIGNAL ;
		PORT
			LAYER metal1 ;
			RECT 5.858 5.857 5.858 5.857 ;
			END
		END OP14
	PIN OP15
		DIRECTION OUTPUT ;
		USE SIGNAL ;
		PORT
			LAYER metal1 ;
			RECT 5.858 5.857 5.858 5.857 ;
			END
		END OP15
	PIN OP16
		DIRECTION OUTPUT ;
		USE SIGNAL ;
		PORT
			LAYER metal1 ;
			RECT 5.858 5.857 5.858 5.857 ;
			END
		END OP16
	PIN OP17
		DIRECTION OUTPUT ;
		USE SIGNAL ;
		PORT
			LAYER metal1 ;
			RECT 5.858 5.857 5.858 5.857 ;
			END
		END OP17
	PIN OP18
		DIRECTION OUTPUT ;
		USE SIGNAL ;
		PORT
			LAYER metal1 ;
			RECT 5.858 5.857 5.858 5.857 ;
			END
		END OP18
	PIN OP19
		DIRECTION OUTPUT ;
		USE SIGNAL ;
		PORT
			LAYER metal1 ;
			RECT 5.858 5.857 5.858 5.857 ;
			END
		END OP19
	PIN OP20
		DIRECTION OUTPUT ;
		USE SIGNAL ;
		PORT
			LAYER metal1 ;
			RECT 5.858 5.857 5.858 5.857 ;
			END
		END OP20
	PIN OP21
		DIRECTION OUTPUT ;
		USE SIGNAL ;
		PORT
			LAYER metal1 ;
			RECT 5.858 5.857 5.858 5.857 ;
			END
		END OP21
	PIN OP22
		DIRECTION OUTPUT ;
		USE SIGNAL ;
		PORT
			LAYER metal1 ;
			RECT 5.858 5.857 5.858 5.857 ;
			END
		END OP22
	PIN OP23
		DIRECTION OUTPUT ;
		USE SIGNAL ;
		PORT
			LAYER metal1 ;
			RECT 5.858 5.857 5.858 5.857 ;
			END
		END OP23
	PIN IP0
		DIRECTION INPUT ;
		USE SIGNAL ;
		PORT
			LAYER metal1 ;
			RECT 5.858 5.857 5.858 5.857 ;
			END
		END IP0
	PIN IP1
		DIRECTION INPUT ;
		USE SIGNAL ;
		PORT
			LAYER metal1 ;
			RECT 5.858 5.857 5.858 5.857 ;
			END
		END IP1
	PIN IP2
		DIRECTION INPUT ;
		USE SIGNAL ;
		PORT
			LAYER metal1 ;
			RECT 5.858 5.857 5.858 5.857 ;
			END
		END IP2
	PIN IP3
		DIRECTION INPUT ;
		USE SIGNAL ;
		PORT
			LAYER metal1 ;
			RECT 5.858 5.857 5.858 5.857 ;
			END
		END IP3
	PIN IP4
		DIRECTION INPUT ;
		USE SIGNAL ;
		PORT
			LAYER metal1 ;
			RECT 5.858 5.857 5.858 5.857 ;
			END
		END IP4
	PIN IP5
		DIRECTION INPUT ;
		USE SIGNAL ;
		PORT
			LAYER metal1 ;
			RECT 5.858 5.857 5.858 5.857 ;
			END
		END IP5
	PIN IP6
		DIRECTION INPUT ;
		USE SIGNAL ;
		PORT
			LAYER metal1 ;
			RECT 5.858 5.857 5.858 5.857 ;
			END
		END IP6
	PIN IP7
		DIRECTION INPUT ;
		USE SIGNAL ;
		PORT
			LAYER metal1 ;
			RECT 5.858 5.857 5.858 5.857 ;
			END
		END IP7
	PIN IP8
		DIRECTION INPUT ;
		USE SIGNAL ;
		PORT
			LAYER metal1 ;
			RECT 5.858 5.857 5.858 5.857 ;
			END
		END IP8
	PIN IP9
		DIRECTION INPUT ;
		USE SIGNAL ;
		PORT
			LAYER metal1 ;
			RECT 5.858 5.857 5.858 5.857 ;
			END
		END IP9
	PIN IP10
		DIRECTION INPUT ;
		USE SIGNAL ;
		PORT
			LAYER metal1 ;
			RECT 5.858 5.857 5.858 5.857 ;
			END
		END IP10
	PIN IP11
		DIRECTION INPUT ;
		USE SIGNAL ;
		PORT
			LAYER metal1 ;
			RECT 5.858 5.857 5.858 5.857 ;
			END
		END IP11
	PIN IP12
		DIRECTION INPUT ;
		USE SIGNAL ;
		PORT
			LAYER metal1 ;
			RECT 5.858 5.857 5.858 5.857 ;
			END
		END IP12
	PIN IP13
		DIRECTION INPUT ;
		USE SIGNAL ;
		PORT
			LAYER metal1 ;
			RECT 5.858 5.857 5.858 5.857 ;
			END
		END IP13
	PIN IP14
		DIRECTION INPUT ;
		USE SIGNAL ;
		PORT
			LAYER metal1 ;
			RECT 5.858 5.857 5.858 5.857 ;
			END
		END IP14
	PIN IP15
		DIRECTION INPUT ;
		USE SIGNAL ;
		PORT
			LAYER metal1 ;
			RECT 5.858 5.857 5.858 5.857 ;
			END
		END IP15
	PIN IP16
		DIRECTION INPUT ;
		USE SIGNAL ;
		PORT
			LAYER metal1 ;
			RECT 5.858 5.857 5.858 5.857 ;
			END
		END IP16
	PIN IP17
		DIRECTION INPUT ;
		USE SIGNAL ;
		PORT
			LAYER metal1 ;
			RECT 5.858 5.857 5.858 5.857 ;
			END
		END IP17
END cluster_25
MACRO cluster_26
	CLASS BLOCK ;
	ORIGIN 0 0 ;
	FOREIGN cluster_26 0 0 ;
	SIZE 10.366 BY 10.367 ;
	SYMMETRY X Y ;
	PIN OP0
		DIRECTION OUTPUT ;
		USE SIGNAL ;
		PORT
			LAYER metal1 ;
			RECT 5.183 5.184 5.183 5.184 ;
			END
		END OP0
	PIN OP1
		DIRECTION OUTPUT ;
		USE SIGNAL ;
		PORT
			LAYER metal1 ;
			RECT 5.183 5.184 5.183 5.184 ;
			END
		END OP1
	PIN OP2
		DIRECTION OUTPUT ;
		USE SIGNAL ;
		PORT
			LAYER metal1 ;
			RECT 5.183 5.184 5.183 5.184 ;
			END
		END OP2
	PIN OP3
		DIRECTION OUTPUT ;
		USE SIGNAL ;
		PORT
			LAYER metal1 ;
			RECT 5.183 5.184 5.183 5.184 ;
			END
		END OP3
	PIN OP4
		DIRECTION OUTPUT ;
		USE SIGNAL ;
		PORT
			LAYER metal1 ;
			RECT 5.183 5.184 5.183 5.184 ;
			END
		END OP4
	PIN OP5
		DIRECTION OUTPUT ;
		USE SIGNAL ;
		PORT
			LAYER metal1 ;
			RECT 5.183 5.184 5.183 5.184 ;
			END
		END OP5
	PIN OP6
		DIRECTION OUTPUT ;
		USE SIGNAL ;
		PORT
			LAYER metal1 ;
			RECT 5.183 5.184 5.183 5.184 ;
			END
		END OP6
	PIN OP7
		DIRECTION OUTPUT ;
		USE SIGNAL ;
		PORT
			LAYER metal1 ;
			RECT 5.183 5.184 5.183 5.184 ;
			END
		END OP7
	PIN OP8
		DIRECTION OUTPUT ;
		USE SIGNAL ;
		PORT
			LAYER metal1 ;
			RECT 5.183 5.184 5.183 5.184 ;
			END
		END OP8
	PIN OP9
		DIRECTION OUTPUT ;
		USE SIGNAL ;
		PORT
			LAYER metal1 ;
			RECT 5.183 5.184 5.183 5.184 ;
			END
		END OP9
	PIN OP10
		DIRECTION OUTPUT ;
		USE SIGNAL ;
		PORT
			LAYER metal1 ;
			RECT 5.183 5.184 5.183 5.184 ;
			END
		END OP10
	PIN OP11
		DIRECTION OUTPUT ;
		USE SIGNAL ;
		PORT
			LAYER metal1 ;
			RECT 5.183 5.184 5.183 5.184 ;
			END
		END OP11
	PIN OP12
		DIRECTION OUTPUT ;
		USE SIGNAL ;
		PORT
			LAYER metal1 ;
			RECT 5.183 5.184 5.183 5.184 ;
			END
		END OP12
	PIN OP13
		DIRECTION OUTPUT ;
		USE SIGNAL ;
		PORT
			LAYER metal1 ;
			RECT 5.183 5.184 5.183 5.184 ;
			END
		END OP13
	PIN OP14
		DIRECTION OUTPUT ;
		USE SIGNAL ;
		PORT
			LAYER metal1 ;
			RECT 5.183 5.184 5.183 5.184 ;
			END
		END OP14
	PIN OP15
		DIRECTION OUTPUT ;
		USE SIGNAL ;
		PORT
			LAYER metal1 ;
			RECT 5.183 5.184 5.183 5.184 ;
			END
		END OP15
	PIN OP16
		DIRECTION OUTPUT ;
		USE SIGNAL ;
		PORT
			LAYER metal1 ;
			RECT 5.183 5.184 5.183 5.184 ;
			END
		END OP16
	PIN OP17
		DIRECTION OUTPUT ;
		USE SIGNAL ;
		PORT
			LAYER metal1 ;
			RECT 5.183 5.184 5.183 5.184 ;
			END
		END OP17
	PIN OP18
		DIRECTION OUTPUT ;
		USE SIGNAL ;
		PORT
			LAYER metal1 ;
			RECT 5.183 5.184 5.183 5.184 ;
			END
		END OP18
	PIN OP19
		DIRECTION OUTPUT ;
		USE SIGNAL ;
		PORT
			LAYER metal1 ;
			RECT 5.183 5.184 5.183 5.184 ;
			END
		END OP19
	PIN OP20
		DIRECTION OUTPUT ;
		USE SIGNAL ;
		PORT
			LAYER metal1 ;
			RECT 5.183 5.184 5.183 5.184 ;
			END
		END OP20
	PIN OP21
		DIRECTION OUTPUT ;
		USE SIGNAL ;
		PORT
			LAYER metal1 ;
			RECT 5.183 5.184 5.183 5.184 ;
			END
		END OP21
	PIN OP22
		DIRECTION OUTPUT ;
		USE SIGNAL ;
		PORT
			LAYER metal1 ;
			RECT 5.183 5.184 5.183 5.184 ;
			END
		END OP22
	PIN OP23
		DIRECTION OUTPUT ;
		USE SIGNAL ;
		PORT
			LAYER metal1 ;
			RECT 5.183 5.184 5.183 5.184 ;
			END
		END OP23
	PIN OP24
		DIRECTION OUTPUT ;
		USE SIGNAL ;
		PORT
			LAYER metal1 ;
			RECT 5.183 5.184 5.183 5.184 ;
			END
		END OP24
	PIN OP25
		DIRECTION OUTPUT ;
		USE SIGNAL ;
		PORT
			LAYER metal1 ;
			RECT 5.183 5.184 5.183 5.184 ;
			END
		END OP25
	PIN OP26
		DIRECTION OUTPUT ;
		USE SIGNAL ;
		PORT
			LAYER metal1 ;
			RECT 5.183 5.184 5.183 5.184 ;
			END
		END OP26
	PIN OP27
		DIRECTION OUTPUT ;
		USE SIGNAL ;
		PORT
			LAYER metal1 ;
			RECT 5.183 5.184 5.183 5.184 ;
			END
		END OP27
	PIN OP28
		DIRECTION OUTPUT ;
		USE SIGNAL ;
		PORT
			LAYER metal1 ;
			RECT 5.183 5.184 5.183 5.184 ;
			END
		END OP28
	PIN OP29
		DIRECTION OUTPUT ;
		USE SIGNAL ;
		PORT
			LAYER metal1 ;
			RECT 5.183 5.184 5.183 5.184 ;
			END
		END OP29
	PIN IP0
		DIRECTION INPUT ;
		USE SIGNAL ;
		PORT
			LAYER metal1 ;
			RECT 5.183 5.184 5.183 5.184 ;
			END
		END IP0
	PIN IP1
		DIRECTION INPUT ;
		USE SIGNAL ;
		PORT
			LAYER metal1 ;
			RECT 5.183 5.184 5.183 5.184 ;
			END
		END IP1
	PIN IP2
		DIRECTION INPUT ;
		USE SIGNAL ;
		PORT
			LAYER metal1 ;
			RECT 5.183 5.184 5.183 5.184 ;
			END
		END IP2
	PIN IP3
		DIRECTION INPUT ;
		USE SIGNAL ;
		PORT
			LAYER metal1 ;
			RECT 5.183 5.184 5.183 5.184 ;
			END
		END IP3
	PIN IP4
		DIRECTION INPUT ;
		USE SIGNAL ;
		PORT
			LAYER metal1 ;
			RECT 5.183 5.184 5.183 5.184 ;
			END
		END IP4
	PIN IP5
		DIRECTION INPUT ;
		USE SIGNAL ;
		PORT
			LAYER metal1 ;
			RECT 5.183 5.184 5.183 5.184 ;
			END
		END IP5
	PIN IP6
		DIRECTION INPUT ;
		USE SIGNAL ;
		PORT
			LAYER metal1 ;
			RECT 5.183 5.184 5.183 5.184 ;
			END
		END IP6
	PIN IP7
		DIRECTION INPUT ;
		USE SIGNAL ;
		PORT
			LAYER metal1 ;
			RECT 5.183 5.184 5.183 5.184 ;
			END
		END IP7
	PIN IP8
		DIRECTION INPUT ;
		USE SIGNAL ;
		PORT
			LAYER metal1 ;
			RECT 5.183 5.184 5.183 5.184 ;
			END
		END IP8
	PIN IP9
		DIRECTION INPUT ;
		USE SIGNAL ;
		PORT
			LAYER metal1 ;
			RECT 5.183 5.184 5.183 5.184 ;
			END
		END IP9
	PIN IP10
		DIRECTION INPUT ;
		USE SIGNAL ;
		PORT
			LAYER metal1 ;
			RECT 5.183 5.184 5.183 5.184 ;
			END
		END IP10
END cluster_26
MACRO cluster_27
	CLASS BLOCK ;
	ORIGIN 0 0 ;
	FOREIGN cluster_27 0 0 ;
	SIZE 9.397 BY 9.398 ;
	SYMMETRY X Y ;
	PIN OP0
		DIRECTION OUTPUT ;
		USE SIGNAL ;
		PORT
			LAYER metal1 ;
			RECT 4.699 4.699 4.699 4.699 ;
			END
		END OP0
	PIN OP1
		DIRECTION OUTPUT ;
		USE SIGNAL ;
		PORT
			LAYER metal1 ;
			RECT 4.699 4.699 4.699 4.699 ;
			END
		END OP1
	PIN OP2
		DIRECTION OUTPUT ;
		USE SIGNAL ;
		PORT
			LAYER metal1 ;
			RECT 4.699 4.699 4.699 4.699 ;
			END
		END OP2
	PIN OP3
		DIRECTION OUTPUT ;
		USE SIGNAL ;
		PORT
			LAYER metal1 ;
			RECT 4.699 4.699 4.699 4.699 ;
			END
		END OP3
	PIN OP4
		DIRECTION OUTPUT ;
		USE SIGNAL ;
		PORT
			LAYER metal1 ;
			RECT 4.699 4.699 4.699 4.699 ;
			END
		END OP4
	PIN OP5
		DIRECTION OUTPUT ;
		USE SIGNAL ;
		PORT
			LAYER metal1 ;
			RECT 4.699 4.699 4.699 4.699 ;
			END
		END OP5
	PIN OP6
		DIRECTION OUTPUT ;
		USE SIGNAL ;
		PORT
			LAYER metal1 ;
			RECT 4.699 4.699 4.699 4.699 ;
			END
		END OP6
	PIN OP7
		DIRECTION OUTPUT ;
		USE SIGNAL ;
		PORT
			LAYER metal1 ;
			RECT 4.699 4.699 4.699 4.699 ;
			END
		END OP7
	PIN OP8
		DIRECTION OUTPUT ;
		USE SIGNAL ;
		PORT
			LAYER metal1 ;
			RECT 4.699 4.699 4.699 4.699 ;
			END
		END OP8
	PIN OP9
		DIRECTION OUTPUT ;
		USE SIGNAL ;
		PORT
			LAYER metal1 ;
			RECT 4.699 4.699 4.699 4.699 ;
			END
		END OP9
	PIN OP10
		DIRECTION OUTPUT ;
		USE SIGNAL ;
		PORT
			LAYER metal1 ;
			RECT 4.699 4.699 4.699 4.699 ;
			END
		END OP10
	PIN OP11
		DIRECTION OUTPUT ;
		USE SIGNAL ;
		PORT
			LAYER metal1 ;
			RECT 4.699 4.699 4.699 4.699 ;
			END
		END OP11
	PIN OP12
		DIRECTION OUTPUT ;
		USE SIGNAL ;
		PORT
			LAYER metal1 ;
			RECT 4.699 4.699 4.699 4.699 ;
			END
		END OP12
	PIN OP13
		DIRECTION OUTPUT ;
		USE SIGNAL ;
		PORT
			LAYER metal1 ;
			RECT 4.699 4.699 4.699 4.699 ;
			END
		END OP13
	PIN OP14
		DIRECTION OUTPUT ;
		USE SIGNAL ;
		PORT
			LAYER metal1 ;
			RECT 4.699 4.699 4.699 4.699 ;
			END
		END OP14
	PIN OP15
		DIRECTION OUTPUT ;
		USE SIGNAL ;
		PORT
			LAYER metal1 ;
			RECT 4.699 4.699 4.699 4.699 ;
			END
		END OP15
	PIN OP16
		DIRECTION OUTPUT ;
		USE SIGNAL ;
		PORT
			LAYER metal1 ;
			RECT 4.699 4.699 4.699 4.699 ;
			END
		END OP16
	PIN OP17
		DIRECTION OUTPUT ;
		USE SIGNAL ;
		PORT
			LAYER metal1 ;
			RECT 4.699 4.699 4.699 4.699 ;
			END
		END OP17
	PIN OP18
		DIRECTION OUTPUT ;
		USE SIGNAL ;
		PORT
			LAYER metal1 ;
			RECT 4.699 4.699 4.699 4.699 ;
			END
		END OP18
	PIN OP19
		DIRECTION OUTPUT ;
		USE SIGNAL ;
		PORT
			LAYER metal1 ;
			RECT 4.699 4.699 4.699 4.699 ;
			END
		END OP19
	PIN OP20
		DIRECTION OUTPUT ;
		USE SIGNAL ;
		PORT
			LAYER metal1 ;
			RECT 4.699 4.699 4.699 4.699 ;
			END
		END OP20
	PIN OP21
		DIRECTION OUTPUT ;
		USE SIGNAL ;
		PORT
			LAYER metal1 ;
			RECT 4.699 4.699 4.699 4.699 ;
			END
		END OP21
	PIN OP22
		DIRECTION OUTPUT ;
		USE SIGNAL ;
		PORT
			LAYER metal1 ;
			RECT 4.699 4.699 4.699 4.699 ;
			END
		END OP22
	PIN OP23
		DIRECTION OUTPUT ;
		USE SIGNAL ;
		PORT
			LAYER metal1 ;
			RECT 4.699 4.699 4.699 4.699 ;
			END
		END OP23
	PIN OP24
		DIRECTION OUTPUT ;
		USE SIGNAL ;
		PORT
			LAYER metal1 ;
			RECT 4.699 4.699 4.699 4.699 ;
			END
		END OP24
	PIN IP0
		DIRECTION INPUT ;
		USE SIGNAL ;
		PORT
			LAYER metal1 ;
			RECT 4.699 4.699 4.699 4.699 ;
			END
		END IP0
	PIN IP1
		DIRECTION INPUT ;
		USE SIGNAL ;
		PORT
			LAYER metal1 ;
			RECT 4.699 4.699 4.699 4.699 ;
			END
		END IP1
	PIN IP2
		DIRECTION INPUT ;
		USE SIGNAL ;
		PORT
			LAYER metal1 ;
			RECT 4.699 4.699 4.699 4.699 ;
			END
		END IP2
	PIN IP3
		DIRECTION INPUT ;
		USE SIGNAL ;
		PORT
			LAYER metal1 ;
			RECT 4.699 4.699 4.699 4.699 ;
			END
		END IP3
	PIN IP4
		DIRECTION INPUT ;
		USE SIGNAL ;
		PORT
			LAYER metal1 ;
			RECT 4.699 4.699 4.699 4.699 ;
			END
		END IP4
	PIN IP5
		DIRECTION INPUT ;
		USE SIGNAL ;
		PORT
			LAYER metal1 ;
			RECT 4.699 4.699 4.699 4.699 ;
			END
		END IP5
	PIN IP6
		DIRECTION INPUT ;
		USE SIGNAL ;
		PORT
			LAYER metal1 ;
			RECT 4.699 4.699 4.699 4.699 ;
			END
		END IP6
	PIN IP7
		DIRECTION INPUT ;
		USE SIGNAL ;
		PORT
			LAYER metal1 ;
			RECT 4.699 4.699 4.699 4.699 ;
			END
		END IP7
	PIN IP8
		DIRECTION INPUT ;
		USE SIGNAL ;
		PORT
			LAYER metal1 ;
			RECT 4.699 4.699 4.699 4.699 ;
			END
		END IP8
	PIN IP9
		DIRECTION INPUT ;
		USE SIGNAL ;
		PORT
			LAYER metal1 ;
			RECT 4.699 4.699 4.699 4.699 ;
			END
		END IP9
END cluster_27
MACRO cluster_28
	CLASS BLOCK ;
	ORIGIN 0 0 ;
	FOREIGN cluster_28 0 0 ;
	SIZE 9.212 BY 9.211 ;
	SYMMETRY X Y ;
	PIN OP0
		DIRECTION OUTPUT ;
		USE SIGNAL ;
		PORT
			LAYER metal1 ;
			RECT 4.606 4.606 4.606 4.606 ;
			END
		END OP0
	PIN OP1
		DIRECTION OUTPUT ;
		USE SIGNAL ;
		PORT
			LAYER metal1 ;
			RECT 4.606 4.606 4.606 4.606 ;
			END
		END OP1
	PIN OP2
		DIRECTION OUTPUT ;
		USE SIGNAL ;
		PORT
			LAYER metal1 ;
			RECT 4.606 4.606 4.606 4.606 ;
			END
		END OP2
	PIN OP3
		DIRECTION OUTPUT ;
		USE SIGNAL ;
		PORT
			LAYER metal1 ;
			RECT 4.606 4.606 4.606 4.606 ;
			END
		END OP3
	PIN OP4
		DIRECTION OUTPUT ;
		USE SIGNAL ;
		PORT
			LAYER metal1 ;
			RECT 4.606 4.606 4.606 4.606 ;
			END
		END OP4
	PIN OP5
		DIRECTION OUTPUT ;
		USE SIGNAL ;
		PORT
			LAYER metal1 ;
			RECT 4.606 4.606 4.606 4.606 ;
			END
		END OP5
	PIN OP6
		DIRECTION OUTPUT ;
		USE SIGNAL ;
		PORT
			LAYER metal1 ;
			RECT 4.606 4.606 4.606 4.606 ;
			END
		END OP6
	PIN OP7
		DIRECTION OUTPUT ;
		USE SIGNAL ;
		PORT
			LAYER metal1 ;
			RECT 4.606 4.606 4.606 4.606 ;
			END
		END OP7
	PIN OP8
		DIRECTION OUTPUT ;
		USE SIGNAL ;
		PORT
			LAYER metal1 ;
			RECT 4.606 4.606 4.606 4.606 ;
			END
		END OP8
	PIN OP9
		DIRECTION OUTPUT ;
		USE SIGNAL ;
		PORT
			LAYER metal1 ;
			RECT 4.606 4.606 4.606 4.606 ;
			END
		END OP9
	PIN OP10
		DIRECTION OUTPUT ;
		USE SIGNAL ;
		PORT
			LAYER metal1 ;
			RECT 4.606 4.606 4.606 4.606 ;
			END
		END OP10
	PIN OP11
		DIRECTION OUTPUT ;
		USE SIGNAL ;
		PORT
			LAYER metal1 ;
			RECT 4.606 4.606 4.606 4.606 ;
			END
		END OP11
	PIN OP12
		DIRECTION OUTPUT ;
		USE SIGNAL ;
		PORT
			LAYER metal1 ;
			RECT 4.606 4.606 4.606 4.606 ;
			END
		END OP12
	PIN OP13
		DIRECTION OUTPUT ;
		USE SIGNAL ;
		PORT
			LAYER metal1 ;
			RECT 4.606 4.606 4.606 4.606 ;
			END
		END OP13
	PIN OP14
		DIRECTION OUTPUT ;
		USE SIGNAL ;
		PORT
			LAYER metal1 ;
			RECT 4.606 4.606 4.606 4.606 ;
			END
		END OP14
	PIN OP15
		DIRECTION OUTPUT ;
		USE SIGNAL ;
		PORT
			LAYER metal1 ;
			RECT 4.606 4.606 4.606 4.606 ;
			END
		END OP15
	PIN IP0
		DIRECTION INPUT ;
		USE SIGNAL ;
		PORT
			LAYER metal1 ;
			RECT 4.606 4.606 4.606 4.606 ;
			END
		END IP0
	PIN IP1
		DIRECTION INPUT ;
		USE SIGNAL ;
		PORT
			LAYER metal1 ;
			RECT 4.606 4.606 4.606 4.606 ;
			END
		END IP1
	PIN IP2
		DIRECTION INPUT ;
		USE SIGNAL ;
		PORT
			LAYER metal1 ;
			RECT 4.606 4.606 4.606 4.606 ;
			END
		END IP2
	PIN IP3
		DIRECTION INPUT ;
		USE SIGNAL ;
		PORT
			LAYER metal1 ;
			RECT 4.606 4.606 4.606 4.606 ;
			END
		END IP3
	PIN IP4
		DIRECTION INPUT ;
		USE SIGNAL ;
		PORT
			LAYER metal1 ;
			RECT 4.606 4.606 4.606 4.606 ;
			END
		END IP4
	PIN IP5
		DIRECTION INPUT ;
		USE SIGNAL ;
		PORT
			LAYER metal1 ;
			RECT 4.606 4.606 4.606 4.606 ;
			END
		END IP5
	PIN IP6
		DIRECTION INPUT ;
		USE SIGNAL ;
		PORT
			LAYER metal1 ;
			RECT 4.606 4.606 4.606 4.606 ;
			END
		END IP6
	PIN IP7
		DIRECTION INPUT ;
		USE SIGNAL ;
		PORT
			LAYER metal1 ;
			RECT 4.606 4.606 4.606 4.606 ;
			END
		END IP7
	PIN IP8
		DIRECTION INPUT ;
		USE SIGNAL ;
		PORT
			LAYER metal1 ;
			RECT 4.606 4.606 4.606 4.606 ;
			END
		END IP8
	PIN IP9
		DIRECTION INPUT ;
		USE SIGNAL ;
		PORT
			LAYER metal1 ;
			RECT 4.606 4.606 4.606 4.606 ;
			END
		END IP9
END cluster_28
MACRO cluster_29
	CLASS BLOCK ;
	ORIGIN 0 0 ;
	FOREIGN cluster_29 0 0 ;
	SIZE 9.482 BY 9.482 ;
	SYMMETRY X Y ;
	PIN OP0
		DIRECTION OUTPUT ;
		USE SIGNAL ;
		PORT
			LAYER metal1 ;
			RECT 4.741 4.741 4.741 4.741 ;
			END
		END OP0
	PIN OP1
		DIRECTION OUTPUT ;
		USE SIGNAL ;
		PORT
			LAYER metal1 ;
			RECT 4.741 4.741 4.741 4.741 ;
			END
		END OP1
	PIN OP2
		DIRECTION OUTPUT ;
		USE SIGNAL ;
		PORT
			LAYER metal1 ;
			RECT 4.741 4.741 4.741 4.741 ;
			END
		END OP2
	PIN OP3
		DIRECTION OUTPUT ;
		USE SIGNAL ;
		PORT
			LAYER metal1 ;
			RECT 4.741 4.741 4.741 4.741 ;
			END
		END OP3
	PIN OP4
		DIRECTION OUTPUT ;
		USE SIGNAL ;
		PORT
			LAYER metal1 ;
			RECT 4.741 4.741 4.741 4.741 ;
			END
		END OP4
	PIN OP5
		DIRECTION OUTPUT ;
		USE SIGNAL ;
		PORT
			LAYER metal1 ;
			RECT 4.741 4.741 4.741 4.741 ;
			END
		END OP5
	PIN OP6
		DIRECTION OUTPUT ;
		USE SIGNAL ;
		PORT
			LAYER metal1 ;
			RECT 4.741 4.741 4.741 4.741 ;
			END
		END OP6
	PIN OP7
		DIRECTION OUTPUT ;
		USE SIGNAL ;
		PORT
			LAYER metal1 ;
			RECT 4.741 4.741 4.741 4.741 ;
			END
		END OP7
	PIN OP8
		DIRECTION OUTPUT ;
		USE SIGNAL ;
		PORT
			LAYER metal1 ;
			RECT 4.741 4.741 4.741 4.741 ;
			END
		END OP8
	PIN OP9
		DIRECTION OUTPUT ;
		USE SIGNAL ;
		PORT
			LAYER metal1 ;
			RECT 4.741 4.741 4.741 4.741 ;
			END
		END OP9
	PIN OP10
		DIRECTION OUTPUT ;
		USE SIGNAL ;
		PORT
			LAYER metal1 ;
			RECT 4.741 4.741 4.741 4.741 ;
			END
		END OP10
	PIN OP11
		DIRECTION OUTPUT ;
		USE SIGNAL ;
		PORT
			LAYER metal1 ;
			RECT 4.741 4.741 4.741 4.741 ;
			END
		END OP11
	PIN OP12
		DIRECTION OUTPUT ;
		USE SIGNAL ;
		PORT
			LAYER metal1 ;
			RECT 4.741 4.741 4.741 4.741 ;
			END
		END OP12
	PIN OP13
		DIRECTION OUTPUT ;
		USE SIGNAL ;
		PORT
			LAYER metal1 ;
			RECT 4.741 4.741 4.741 4.741 ;
			END
		END OP13
	PIN OP14
		DIRECTION OUTPUT ;
		USE SIGNAL ;
		PORT
			LAYER metal1 ;
			RECT 4.741 4.741 4.741 4.741 ;
			END
		END OP14
	PIN OP15
		DIRECTION OUTPUT ;
		USE SIGNAL ;
		PORT
			LAYER metal1 ;
			RECT 4.741 4.741 4.741 4.741 ;
			END
		END OP15
	PIN OP16
		DIRECTION OUTPUT ;
		USE SIGNAL ;
		PORT
			LAYER metal1 ;
			RECT 4.741 4.741 4.741 4.741 ;
			END
		END OP16
	PIN OP17
		DIRECTION OUTPUT ;
		USE SIGNAL ;
		PORT
			LAYER metal1 ;
			RECT 4.741 4.741 4.741 4.741 ;
			END
		END OP17
	PIN OP18
		DIRECTION OUTPUT ;
		USE SIGNAL ;
		PORT
			LAYER metal1 ;
			RECT 4.741 4.741 4.741 4.741 ;
			END
		END OP18
	PIN IP0
		DIRECTION INPUT ;
		USE SIGNAL ;
		PORT
			LAYER metal1 ;
			RECT 4.741 4.741 4.741 4.741 ;
			END
		END IP0
	PIN IP1
		DIRECTION INPUT ;
		USE SIGNAL ;
		PORT
			LAYER metal1 ;
			RECT 4.741 4.741 4.741 4.741 ;
			END
		END IP1
	PIN IP2
		DIRECTION INPUT ;
		USE SIGNAL ;
		PORT
			LAYER metal1 ;
			RECT 4.741 4.741 4.741 4.741 ;
			END
		END IP2
	PIN IP3
		DIRECTION INPUT ;
		USE SIGNAL ;
		PORT
			LAYER metal1 ;
			RECT 4.741 4.741 4.741 4.741 ;
			END
		END IP3
	PIN IP4
		DIRECTION INPUT ;
		USE SIGNAL ;
		PORT
			LAYER metal1 ;
			RECT 4.741 4.741 4.741 4.741 ;
			END
		END IP4
	PIN IP5
		DIRECTION INPUT ;
		USE SIGNAL ;
		PORT
			LAYER metal1 ;
			RECT 4.741 4.741 4.741 4.741 ;
			END
		END IP5
	PIN IP6
		DIRECTION INPUT ;
		USE SIGNAL ;
		PORT
			LAYER metal1 ;
			RECT 4.741 4.741 4.741 4.741 ;
			END
		END IP6
	PIN IP7
		DIRECTION INPUT ;
		USE SIGNAL ;
		PORT
			LAYER metal1 ;
			RECT 4.741 4.741 4.741 4.741 ;
			END
		END IP7
	PIN IP8
		DIRECTION INPUT ;
		USE SIGNAL ;
		PORT
			LAYER metal1 ;
			RECT 4.741 4.741 4.741 4.741 ;
			END
		END IP8
END cluster_29
MACRO cluster_30
	CLASS BLOCK ;
	ORIGIN 0 0 ;
	FOREIGN cluster_30 0 0 ;
	SIZE 9.11 BY 9.11 ;
	SYMMETRY X Y ;
	PIN OP0
		DIRECTION OUTPUT ;
		USE SIGNAL ;
		PORT
			LAYER metal1 ;
			RECT 4.555 4.555 4.555 4.555 ;
			END
		END OP0
	PIN OP1
		DIRECTION OUTPUT ;
		USE SIGNAL ;
		PORT
			LAYER metal1 ;
			RECT 4.555 4.555 4.555 4.555 ;
			END
		END OP1
	PIN OP2
		DIRECTION OUTPUT ;
		USE SIGNAL ;
		PORT
			LAYER metal1 ;
			RECT 4.555 4.555 4.555 4.555 ;
			END
		END OP2
	PIN OP3
		DIRECTION OUTPUT ;
		USE SIGNAL ;
		PORT
			LAYER metal1 ;
			RECT 4.555 4.555 4.555 4.555 ;
			END
		END OP3
	PIN OP4
		DIRECTION OUTPUT ;
		USE SIGNAL ;
		PORT
			LAYER metal1 ;
			RECT 4.555 4.555 4.555 4.555 ;
			END
		END OP4
	PIN OP5
		DIRECTION OUTPUT ;
		USE SIGNAL ;
		PORT
			LAYER metal1 ;
			RECT 4.555 4.555 4.555 4.555 ;
			END
		END OP5
	PIN OP6
		DIRECTION OUTPUT ;
		USE SIGNAL ;
		PORT
			LAYER metal1 ;
			RECT 4.555 4.555 4.555 4.555 ;
			END
		END OP6
	PIN OP7
		DIRECTION OUTPUT ;
		USE SIGNAL ;
		PORT
			LAYER metal1 ;
			RECT 4.555 4.555 4.555 4.555 ;
			END
		END OP7
	PIN OP8
		DIRECTION OUTPUT ;
		USE SIGNAL ;
		PORT
			LAYER metal1 ;
			RECT 4.555 4.555 4.555 4.555 ;
			END
		END OP8
	PIN OP9
		DIRECTION OUTPUT ;
		USE SIGNAL ;
		PORT
			LAYER metal1 ;
			RECT 4.555 4.555 4.555 4.555 ;
			END
		END OP9
	PIN OP10
		DIRECTION OUTPUT ;
		USE SIGNAL ;
		PORT
			LAYER metal1 ;
			RECT 4.555 4.555 4.555 4.555 ;
			END
		END OP10
	PIN OP11
		DIRECTION OUTPUT ;
		USE SIGNAL ;
		PORT
			LAYER metal1 ;
			RECT 4.555 4.555 4.555 4.555 ;
			END
		END OP11
	PIN OP12
		DIRECTION OUTPUT ;
		USE SIGNAL ;
		PORT
			LAYER metal1 ;
			RECT 4.555 4.555 4.555 4.555 ;
			END
		END OP12
	PIN OP13
		DIRECTION OUTPUT ;
		USE SIGNAL ;
		PORT
			LAYER metal1 ;
			RECT 4.555 4.555 4.555 4.555 ;
			END
		END OP13
	PIN OP14
		DIRECTION OUTPUT ;
		USE SIGNAL ;
		PORT
			LAYER metal1 ;
			RECT 4.555 4.555 4.555 4.555 ;
			END
		END OP14
	PIN OP15
		DIRECTION OUTPUT ;
		USE SIGNAL ;
		PORT
			LAYER metal1 ;
			RECT 4.555 4.555 4.555 4.555 ;
			END
		END OP15
	PIN IP0
		DIRECTION INPUT ;
		USE SIGNAL ;
		PORT
			LAYER metal1 ;
			RECT 4.555 4.555 4.555 4.555 ;
			END
		END IP0
	PIN IP1
		DIRECTION INPUT ;
		USE SIGNAL ;
		PORT
			LAYER metal1 ;
			RECT 4.555 4.555 4.555 4.555 ;
			END
		END IP1
	PIN IP2
		DIRECTION INPUT ;
		USE SIGNAL ;
		PORT
			LAYER metal1 ;
			RECT 4.555 4.555 4.555 4.555 ;
			END
		END IP2
	PIN IP3
		DIRECTION INPUT ;
		USE SIGNAL ;
		PORT
			LAYER metal1 ;
			RECT 4.555 4.555 4.555 4.555 ;
			END
		END IP3
	PIN IP4
		DIRECTION INPUT ;
		USE SIGNAL ;
		PORT
			LAYER metal1 ;
			RECT 4.555 4.555 4.555 4.555 ;
			END
		END IP4
	PIN IP5
		DIRECTION INPUT ;
		USE SIGNAL ;
		PORT
			LAYER metal1 ;
			RECT 4.555 4.555 4.555 4.555 ;
			END
		END IP5
	PIN IP6
		DIRECTION INPUT ;
		USE SIGNAL ;
		PORT
			LAYER metal1 ;
			RECT 4.555 4.555 4.555 4.555 ;
			END
		END IP6
	PIN IP7
		DIRECTION INPUT ;
		USE SIGNAL ;
		PORT
			LAYER metal1 ;
			RECT 4.555 4.555 4.555 4.555 ;
			END
		END IP7
	PIN IP8
		DIRECTION INPUT ;
		USE SIGNAL ;
		PORT
			LAYER metal1 ;
			RECT 4.555 4.555 4.555 4.555 ;
			END
		END IP8
END cluster_30
MACRO cluster_31
	CLASS BLOCK ;
	ORIGIN 0 0 ;
	FOREIGN cluster_31 0 0 ;
	SIZE 8.888 BY 8.889 ;
	SYMMETRY X Y ;
	PIN OP0
		DIRECTION OUTPUT ;
		USE SIGNAL ;
		PORT
			LAYER metal1 ;
			RECT 4.444 4.444 4.444 4.444 ;
			END
		END OP0
	PIN OP1
		DIRECTION OUTPUT ;
		USE SIGNAL ;
		PORT
			LAYER metal1 ;
			RECT 4.444 4.444 4.444 4.444 ;
			END
		END OP1
	PIN OP2
		DIRECTION OUTPUT ;
		USE SIGNAL ;
		PORT
			LAYER metal1 ;
			RECT 4.444 4.444 4.444 4.444 ;
			END
		END OP2
	PIN OP3
		DIRECTION OUTPUT ;
		USE SIGNAL ;
		PORT
			LAYER metal1 ;
			RECT 4.444 4.444 4.444 4.444 ;
			END
		END OP3
	PIN OP4
		DIRECTION OUTPUT ;
		USE SIGNAL ;
		PORT
			LAYER metal1 ;
			RECT 4.444 4.444 4.444 4.444 ;
			END
		END OP4
	PIN OP5
		DIRECTION OUTPUT ;
		USE SIGNAL ;
		PORT
			LAYER metal1 ;
			RECT 4.444 4.444 4.444 4.444 ;
			END
		END OP5
	PIN OP6
		DIRECTION OUTPUT ;
		USE SIGNAL ;
		PORT
			LAYER metal1 ;
			RECT 4.444 4.444 4.444 4.444 ;
			END
		END OP6
	PIN OP7
		DIRECTION OUTPUT ;
		USE SIGNAL ;
		PORT
			LAYER metal1 ;
			RECT 4.444 4.444 4.444 4.444 ;
			END
		END OP7
	PIN OP8
		DIRECTION OUTPUT ;
		USE SIGNAL ;
		PORT
			LAYER metal1 ;
			RECT 4.444 4.444 4.444 4.444 ;
			END
		END OP8
	PIN OP9
		DIRECTION OUTPUT ;
		USE SIGNAL ;
		PORT
			LAYER metal1 ;
			RECT 4.444 4.444 4.444 4.444 ;
			END
		END OP9
	PIN OP10
		DIRECTION OUTPUT ;
		USE SIGNAL ;
		PORT
			LAYER metal1 ;
			RECT 4.444 4.444 4.444 4.444 ;
			END
		END OP10
	PIN OP11
		DIRECTION OUTPUT ;
		USE SIGNAL ;
		PORT
			LAYER metal1 ;
			RECT 4.444 4.444 4.444 4.444 ;
			END
		END OP11
	PIN OP12
		DIRECTION OUTPUT ;
		USE SIGNAL ;
		PORT
			LAYER metal1 ;
			RECT 4.444 4.444 4.444 4.444 ;
			END
		END OP12
	PIN OP13
		DIRECTION OUTPUT ;
		USE SIGNAL ;
		PORT
			LAYER metal1 ;
			RECT 4.444 4.444 4.444 4.444 ;
			END
		END OP13
	PIN OP14
		DIRECTION OUTPUT ;
		USE SIGNAL ;
		PORT
			LAYER metal1 ;
			RECT 4.444 4.444 4.444 4.444 ;
			END
		END OP14
	PIN OP15
		DIRECTION OUTPUT ;
		USE SIGNAL ;
		PORT
			LAYER metal1 ;
			RECT 4.444 4.444 4.444 4.444 ;
			END
		END OP15
	PIN IP0
		DIRECTION INPUT ;
		USE SIGNAL ;
		PORT
			LAYER metal1 ;
			RECT 4.444 4.444 4.444 4.444 ;
			END
		END IP0
	PIN IP1
		DIRECTION INPUT ;
		USE SIGNAL ;
		PORT
			LAYER metal1 ;
			RECT 4.444 4.444 4.444 4.444 ;
			END
		END IP1
	PIN IP2
		DIRECTION INPUT ;
		USE SIGNAL ;
		PORT
			LAYER metal1 ;
			RECT 4.444 4.444 4.444 4.444 ;
			END
		END IP2
	PIN IP3
		DIRECTION INPUT ;
		USE SIGNAL ;
		PORT
			LAYER metal1 ;
			RECT 4.444 4.444 4.444 4.444 ;
			END
		END IP3
	PIN IP4
		DIRECTION INPUT ;
		USE SIGNAL ;
		PORT
			LAYER metal1 ;
			RECT 4.444 4.444 4.444 4.444 ;
			END
		END IP4
	PIN IP5
		DIRECTION INPUT ;
		USE SIGNAL ;
		PORT
			LAYER metal1 ;
			RECT 4.444 4.444 4.444 4.444 ;
			END
		END IP5
	PIN IP6
		DIRECTION INPUT ;
		USE SIGNAL ;
		PORT
			LAYER metal1 ;
			RECT 4.444 4.444 4.444 4.444 ;
			END
		END IP6
	PIN IP7
		DIRECTION INPUT ;
		USE SIGNAL ;
		PORT
			LAYER metal1 ;
			RECT 4.444 4.444 4.444 4.444 ;
			END
		END IP7
	PIN IP8
		DIRECTION INPUT ;
		USE SIGNAL ;
		PORT
			LAYER metal1 ;
			RECT 4.444 4.444 4.444 4.444 ;
			END
		END IP8
END cluster_31
MACRO cluster_32
	CLASS BLOCK ;
	ORIGIN 0 0 ;
	FOREIGN cluster_32 0 0 ;
	SIZE 8.858 BY 8.859 ;
	SYMMETRY X Y ;
	PIN OP0
		DIRECTION OUTPUT ;
		USE SIGNAL ;
		PORT
			LAYER metal1 ;
			RECT 4.429 4.429 4.429 4.429 ;
			END
		END OP0
	PIN OP1
		DIRECTION OUTPUT ;
		USE SIGNAL ;
		PORT
			LAYER metal1 ;
			RECT 4.429 4.429 4.429 4.429 ;
			END
		END OP1
	PIN OP2
		DIRECTION OUTPUT ;
		USE SIGNAL ;
		PORT
			LAYER metal1 ;
			RECT 4.429 4.429 4.429 4.429 ;
			END
		END OP2
	PIN OP3
		DIRECTION OUTPUT ;
		USE SIGNAL ;
		PORT
			LAYER metal1 ;
			RECT 4.429 4.429 4.429 4.429 ;
			END
		END OP3
	PIN OP4
		DIRECTION OUTPUT ;
		USE SIGNAL ;
		PORT
			LAYER metal1 ;
			RECT 4.429 4.429 4.429 4.429 ;
			END
		END OP4
	PIN OP5
		DIRECTION OUTPUT ;
		USE SIGNAL ;
		PORT
			LAYER metal1 ;
			RECT 4.429 4.429 4.429 4.429 ;
			END
		END OP5
	PIN OP6
		DIRECTION OUTPUT ;
		USE SIGNAL ;
		PORT
			LAYER metal1 ;
			RECT 4.429 4.429 4.429 4.429 ;
			END
		END OP6
	PIN OP7
		DIRECTION OUTPUT ;
		USE SIGNAL ;
		PORT
			LAYER metal1 ;
			RECT 4.429 4.429 4.429 4.429 ;
			END
		END OP7
	PIN OP8
		DIRECTION OUTPUT ;
		USE SIGNAL ;
		PORT
			LAYER metal1 ;
			RECT 4.429 4.429 4.429 4.429 ;
			END
		END OP8
	PIN OP9
		DIRECTION OUTPUT ;
		USE SIGNAL ;
		PORT
			LAYER metal1 ;
			RECT 4.429 4.429 4.429 4.429 ;
			END
		END OP9
	PIN OP10
		DIRECTION OUTPUT ;
		USE SIGNAL ;
		PORT
			LAYER metal1 ;
			RECT 4.429 4.429 4.429 4.429 ;
			END
		END OP10
	PIN OP11
		DIRECTION OUTPUT ;
		USE SIGNAL ;
		PORT
			LAYER metal1 ;
			RECT 4.429 4.429 4.429 4.429 ;
			END
		END OP11
	PIN OP12
		DIRECTION OUTPUT ;
		USE SIGNAL ;
		PORT
			LAYER metal1 ;
			RECT 4.429 4.429 4.429 4.429 ;
			END
		END OP12
	PIN OP13
		DIRECTION OUTPUT ;
		USE SIGNAL ;
		PORT
			LAYER metal1 ;
			RECT 4.429 4.429 4.429 4.429 ;
			END
		END OP13
	PIN OP14
		DIRECTION OUTPUT ;
		USE SIGNAL ;
		PORT
			LAYER metal1 ;
			RECT 4.429 4.429 4.429 4.429 ;
			END
		END OP14
	PIN OP15
		DIRECTION OUTPUT ;
		USE SIGNAL ;
		PORT
			LAYER metal1 ;
			RECT 4.429 4.429 4.429 4.429 ;
			END
		END OP15
	PIN OP16
		DIRECTION OUTPUT ;
		USE SIGNAL ;
		PORT
			LAYER metal1 ;
			RECT 4.429 4.429 4.429 4.429 ;
			END
		END OP16
	PIN IP0
		DIRECTION INPUT ;
		USE SIGNAL ;
		PORT
			LAYER metal1 ;
			RECT 4.429 4.429 4.429 4.429 ;
			END
		END IP0
	PIN IP1
		DIRECTION INPUT ;
		USE SIGNAL ;
		PORT
			LAYER metal1 ;
			RECT 4.429 4.429 4.429 4.429 ;
			END
		END IP1
	PIN IP2
		DIRECTION INPUT ;
		USE SIGNAL ;
		PORT
			LAYER metal1 ;
			RECT 4.429 4.429 4.429 4.429 ;
			END
		END IP2
	PIN IP3
		DIRECTION INPUT ;
		USE SIGNAL ;
		PORT
			LAYER metal1 ;
			RECT 4.429 4.429 4.429 4.429 ;
			END
		END IP3
	PIN IP4
		DIRECTION INPUT ;
		USE SIGNAL ;
		PORT
			LAYER metal1 ;
			RECT 4.429 4.429 4.429 4.429 ;
			END
		END IP4
	PIN IP5
		DIRECTION INPUT ;
		USE SIGNAL ;
		PORT
			LAYER metal1 ;
			RECT 4.429 4.429 4.429 4.429 ;
			END
		END IP5
	PIN IP6
		DIRECTION INPUT ;
		USE SIGNAL ;
		PORT
			LAYER metal1 ;
			RECT 4.429 4.429 4.429 4.429 ;
			END
		END IP6
END cluster_32
MACRO cluster_33
	CLASS BLOCK ;
	ORIGIN 0 0 ;
	FOREIGN cluster_33 0 0 ;
	SIZE 8.768 BY 8.768 ;
	SYMMETRY X Y ;
	PIN OP0
		DIRECTION OUTPUT ;
		USE SIGNAL ;
		PORT
			LAYER metal1 ;
			RECT 4.384 4.384 4.384 4.384 ;
			END
		END OP0
	PIN OP1
		DIRECTION OUTPUT ;
		USE SIGNAL ;
		PORT
			LAYER metal1 ;
			RECT 4.384 4.384 4.384 4.384 ;
			END
		END OP1
	PIN OP2
		DIRECTION OUTPUT ;
		USE SIGNAL ;
		PORT
			LAYER metal1 ;
			RECT 4.384 4.384 4.384 4.384 ;
			END
		END OP2
	PIN OP3
		DIRECTION OUTPUT ;
		USE SIGNAL ;
		PORT
			LAYER metal1 ;
			RECT 4.384 4.384 4.384 4.384 ;
			END
		END OP3
	PIN OP4
		DIRECTION OUTPUT ;
		USE SIGNAL ;
		PORT
			LAYER metal1 ;
			RECT 4.384 4.384 4.384 4.384 ;
			END
		END OP4
	PIN OP5
		DIRECTION OUTPUT ;
		USE SIGNAL ;
		PORT
			LAYER metal1 ;
			RECT 4.384 4.384 4.384 4.384 ;
			END
		END OP5
	PIN OP6
		DIRECTION OUTPUT ;
		USE SIGNAL ;
		PORT
			LAYER metal1 ;
			RECT 4.384 4.384 4.384 4.384 ;
			END
		END OP6
	PIN OP7
		DIRECTION OUTPUT ;
		USE SIGNAL ;
		PORT
			LAYER metal1 ;
			RECT 4.384 4.384 4.384 4.384 ;
			END
		END OP7
	PIN OP8
		DIRECTION OUTPUT ;
		USE SIGNAL ;
		PORT
			LAYER metal1 ;
			RECT 4.384 4.384 4.384 4.384 ;
			END
		END OP8
	PIN OP9
		DIRECTION OUTPUT ;
		USE SIGNAL ;
		PORT
			LAYER metal1 ;
			RECT 4.384 4.384 4.384 4.384 ;
			END
		END OP9
	PIN OP10
		DIRECTION OUTPUT ;
		USE SIGNAL ;
		PORT
			LAYER metal1 ;
			RECT 4.384 4.384 4.384 4.384 ;
			END
		END OP10
	PIN OP11
		DIRECTION OUTPUT ;
		USE SIGNAL ;
		PORT
			LAYER metal1 ;
			RECT 4.384 4.384 4.384 4.384 ;
			END
		END OP11
	PIN OP12
		DIRECTION OUTPUT ;
		USE SIGNAL ;
		PORT
			LAYER metal1 ;
			RECT 4.384 4.384 4.384 4.384 ;
			END
		END OP12
	PIN OP13
		DIRECTION OUTPUT ;
		USE SIGNAL ;
		PORT
			LAYER metal1 ;
			RECT 4.384 4.384 4.384 4.384 ;
			END
		END OP13
	PIN OP14
		DIRECTION OUTPUT ;
		USE SIGNAL ;
		PORT
			LAYER metal1 ;
			RECT 4.384 4.384 4.384 4.384 ;
			END
		END OP14
	PIN OP15
		DIRECTION OUTPUT ;
		USE SIGNAL ;
		PORT
			LAYER metal1 ;
			RECT 4.384 4.384 4.384 4.384 ;
			END
		END OP15
	PIN IP0
		DIRECTION INPUT ;
		USE SIGNAL ;
		PORT
			LAYER metal1 ;
			RECT 4.384 4.384 4.384 4.384 ;
			END
		END IP0
	PIN IP1
		DIRECTION INPUT ;
		USE SIGNAL ;
		PORT
			LAYER metal1 ;
			RECT 4.384 4.384 4.384 4.384 ;
			END
		END IP1
	PIN IP2
		DIRECTION INPUT ;
		USE SIGNAL ;
		PORT
			LAYER metal1 ;
			RECT 4.384 4.384 4.384 4.384 ;
			END
		END IP2
	PIN IP3
		DIRECTION INPUT ;
		USE SIGNAL ;
		PORT
			LAYER metal1 ;
			RECT 4.384 4.384 4.384 4.384 ;
			END
		END IP3
	PIN IP4
		DIRECTION INPUT ;
		USE SIGNAL ;
		PORT
			LAYER metal1 ;
			RECT 4.384 4.384 4.384 4.384 ;
			END
		END IP4
	PIN IP5
		DIRECTION INPUT ;
		USE SIGNAL ;
		PORT
			LAYER metal1 ;
			RECT 4.384 4.384 4.384 4.384 ;
			END
		END IP5
	PIN IP6
		DIRECTION INPUT ;
		USE SIGNAL ;
		PORT
			LAYER metal1 ;
			RECT 4.384 4.384 4.384 4.384 ;
			END
		END IP6
	PIN IP7
		DIRECTION INPUT ;
		USE SIGNAL ;
		PORT
			LAYER metal1 ;
			RECT 4.384 4.384 4.384 4.384 ;
			END
		END IP7
END cluster_33
MACRO cluster_34
	CLASS BLOCK ;
	ORIGIN 0 0 ;
	FOREIGN cluster_34 0 0 ;
	SIZE 8.522 BY 8.521 ;
	SYMMETRY X Y ;
	PIN OP0
		DIRECTION OUTPUT ;
		USE SIGNAL ;
		PORT
			LAYER metal1 ;
			RECT 4.261 4.261 4.261 4.261 ;
			END
		END OP0
	PIN OP1
		DIRECTION OUTPUT ;
		USE SIGNAL ;
		PORT
			LAYER metal1 ;
			RECT 4.261 4.261 4.261 4.261 ;
			END
		END OP1
	PIN OP2
		DIRECTION OUTPUT ;
		USE SIGNAL ;
		PORT
			LAYER metal1 ;
			RECT 4.261 4.261 4.261 4.261 ;
			END
		END OP2
	PIN OP3
		DIRECTION OUTPUT ;
		USE SIGNAL ;
		PORT
			LAYER metal1 ;
			RECT 4.261 4.261 4.261 4.261 ;
			END
		END OP3
	PIN OP4
		DIRECTION OUTPUT ;
		USE SIGNAL ;
		PORT
			LAYER metal1 ;
			RECT 4.261 4.261 4.261 4.261 ;
			END
		END OP4
	PIN OP5
		DIRECTION OUTPUT ;
		USE SIGNAL ;
		PORT
			LAYER metal1 ;
			RECT 4.261 4.261 4.261 4.261 ;
			END
		END OP5
	PIN OP6
		DIRECTION OUTPUT ;
		USE SIGNAL ;
		PORT
			LAYER metal1 ;
			RECT 4.261 4.261 4.261 4.261 ;
			END
		END OP6
	PIN OP7
		DIRECTION OUTPUT ;
		USE SIGNAL ;
		PORT
			LAYER metal1 ;
			RECT 4.261 4.261 4.261 4.261 ;
			END
		END OP7
	PIN OP8
		DIRECTION OUTPUT ;
		USE SIGNAL ;
		PORT
			LAYER metal1 ;
			RECT 4.261 4.261 4.261 4.261 ;
			END
		END OP8
	PIN OP9
		DIRECTION OUTPUT ;
		USE SIGNAL ;
		PORT
			LAYER metal1 ;
			RECT 4.261 4.261 4.261 4.261 ;
			END
		END OP9
	PIN OP10
		DIRECTION OUTPUT ;
		USE SIGNAL ;
		PORT
			LAYER metal1 ;
			RECT 4.261 4.261 4.261 4.261 ;
			END
		END OP10
	PIN OP11
		DIRECTION OUTPUT ;
		USE SIGNAL ;
		PORT
			LAYER metal1 ;
			RECT 4.261 4.261 4.261 4.261 ;
			END
		END OP11
	PIN OP12
		DIRECTION OUTPUT ;
		USE SIGNAL ;
		PORT
			LAYER metal1 ;
			RECT 4.261 4.261 4.261 4.261 ;
			END
		END OP12
	PIN OP13
		DIRECTION OUTPUT ;
		USE SIGNAL ;
		PORT
			LAYER metal1 ;
			RECT 4.261 4.261 4.261 4.261 ;
			END
		END OP13
	PIN OP14
		DIRECTION OUTPUT ;
		USE SIGNAL ;
		PORT
			LAYER metal1 ;
			RECT 4.261 4.261 4.261 4.261 ;
			END
		END OP14
	PIN OP15
		DIRECTION OUTPUT ;
		USE SIGNAL ;
		PORT
			LAYER metal1 ;
			RECT 4.261 4.261 4.261 4.261 ;
			END
		END OP15
	PIN OP16
		DIRECTION OUTPUT ;
		USE SIGNAL ;
		PORT
			LAYER metal1 ;
			RECT 4.261 4.261 4.261 4.261 ;
			END
		END OP16
	PIN IP0
		DIRECTION INPUT ;
		USE SIGNAL ;
		PORT
			LAYER metal1 ;
			RECT 4.261 4.261 4.261 4.261 ;
			END
		END IP0
	PIN IP1
		DIRECTION INPUT ;
		USE SIGNAL ;
		PORT
			LAYER metal1 ;
			RECT 4.261 4.261 4.261 4.261 ;
			END
		END IP1
	PIN IP2
		DIRECTION INPUT ;
		USE SIGNAL ;
		PORT
			LAYER metal1 ;
			RECT 4.261 4.261 4.261 4.261 ;
			END
		END IP2
	PIN IP3
		DIRECTION INPUT ;
		USE SIGNAL ;
		PORT
			LAYER metal1 ;
			RECT 4.261 4.261 4.261 4.261 ;
			END
		END IP3
	PIN IP4
		DIRECTION INPUT ;
		USE SIGNAL ;
		PORT
			LAYER metal1 ;
			RECT 4.261 4.261 4.261 4.261 ;
			END
		END IP4
	PIN IP5
		DIRECTION INPUT ;
		USE SIGNAL ;
		PORT
			LAYER metal1 ;
			RECT 4.261 4.261 4.261 4.261 ;
			END
		END IP5
	PIN IP6
		DIRECTION INPUT ;
		USE SIGNAL ;
		PORT
			LAYER metal1 ;
			RECT 4.261 4.261 4.261 4.261 ;
			END
		END IP6
END cluster_34
MACRO cluster_35
	CLASS BLOCK ;
	ORIGIN 0 0 ;
	FOREIGN cluster_35 0 0 ;
	SIZE 8.316 BY 8.316 ;
	SYMMETRY X Y ;
	PIN OP0
		DIRECTION OUTPUT ;
		USE SIGNAL ;
		PORT
			LAYER metal1 ;
			RECT 4.158 4.158 4.158 4.158 ;
			END
		END OP0
	PIN OP1
		DIRECTION OUTPUT ;
		USE SIGNAL ;
		PORT
			LAYER metal1 ;
			RECT 4.158 4.158 4.158 4.158 ;
			END
		END OP1
	PIN OP2
		DIRECTION OUTPUT ;
		USE SIGNAL ;
		PORT
			LAYER metal1 ;
			RECT 4.158 4.158 4.158 4.158 ;
			END
		END OP2
	PIN OP3
		DIRECTION OUTPUT ;
		USE SIGNAL ;
		PORT
			LAYER metal1 ;
			RECT 4.158 4.158 4.158 4.158 ;
			END
		END OP3
	PIN OP4
		DIRECTION OUTPUT ;
		USE SIGNAL ;
		PORT
			LAYER metal1 ;
			RECT 4.158 4.158 4.158 4.158 ;
			END
		END OP4
	PIN OP5
		DIRECTION OUTPUT ;
		USE SIGNAL ;
		PORT
			LAYER metal1 ;
			RECT 4.158 4.158 4.158 4.158 ;
			END
		END OP5
	PIN OP6
		DIRECTION OUTPUT ;
		USE SIGNAL ;
		PORT
			LAYER metal1 ;
			RECT 4.158 4.158 4.158 4.158 ;
			END
		END OP6
	PIN OP7
		DIRECTION OUTPUT ;
		USE SIGNAL ;
		PORT
			LAYER metal1 ;
			RECT 4.158 4.158 4.158 4.158 ;
			END
		END OP7
	PIN OP8
		DIRECTION OUTPUT ;
		USE SIGNAL ;
		PORT
			LAYER metal1 ;
			RECT 4.158 4.158 4.158 4.158 ;
			END
		END OP8
	PIN OP9
		DIRECTION OUTPUT ;
		USE SIGNAL ;
		PORT
			LAYER metal1 ;
			RECT 4.158 4.158 4.158 4.158 ;
			END
		END OP9
	PIN OP10
		DIRECTION OUTPUT ;
		USE SIGNAL ;
		PORT
			LAYER metal1 ;
			RECT 4.158 4.158 4.158 4.158 ;
			END
		END OP10
	PIN OP11
		DIRECTION OUTPUT ;
		USE SIGNAL ;
		PORT
			LAYER metal1 ;
			RECT 4.158 4.158 4.158 4.158 ;
			END
		END OP11
	PIN OP12
		DIRECTION OUTPUT ;
		USE SIGNAL ;
		PORT
			LAYER metal1 ;
			RECT 4.158 4.158 4.158 4.158 ;
			END
		END OP12
	PIN OP13
		DIRECTION OUTPUT ;
		USE SIGNAL ;
		PORT
			LAYER metal1 ;
			RECT 4.158 4.158 4.158 4.158 ;
			END
		END OP13
	PIN OP14
		DIRECTION OUTPUT ;
		USE SIGNAL ;
		PORT
			LAYER metal1 ;
			RECT 4.158 4.158 4.158 4.158 ;
			END
		END OP14
	PIN IP0
		DIRECTION INPUT ;
		USE SIGNAL ;
		PORT
			LAYER metal1 ;
			RECT 4.158 4.158 4.158 4.158 ;
			END
		END IP0
	PIN IP1
		DIRECTION INPUT ;
		USE SIGNAL ;
		PORT
			LAYER metal1 ;
			RECT 4.158 4.158 4.158 4.158 ;
			END
		END IP1
	PIN IP2
		DIRECTION INPUT ;
		USE SIGNAL ;
		PORT
			LAYER metal1 ;
			RECT 4.158 4.158 4.158 4.158 ;
			END
		END IP2
	PIN IP3
		DIRECTION INPUT ;
		USE SIGNAL ;
		PORT
			LAYER metal1 ;
			RECT 4.158 4.158 4.158 4.158 ;
			END
		END IP3
	PIN IP4
		DIRECTION INPUT ;
		USE SIGNAL ;
		PORT
			LAYER metal1 ;
			RECT 4.158 4.158 4.158 4.158 ;
			END
		END IP4
	PIN IP5
		DIRECTION INPUT ;
		USE SIGNAL ;
		PORT
			LAYER metal1 ;
			RECT 4.158 4.158 4.158 4.158 ;
			END
		END IP5
	PIN IP6
		DIRECTION INPUT ;
		USE SIGNAL ;
		PORT
			LAYER metal1 ;
			RECT 4.158 4.158 4.158 4.158 ;
			END
		END IP6
END cluster_35
MACRO cluster_36
	CLASS BLOCK ;
	ORIGIN 0 0 ;
	FOREIGN cluster_36 0 0 ;
	SIZE 8.122 BY 8.122 ;
	SYMMETRY X Y ;
	PIN OP0
		DIRECTION OUTPUT ;
		USE SIGNAL ;
		PORT
			LAYER metal1 ;
			RECT 4.061 4.061 4.061 4.061 ;
			END
		END OP0
	PIN OP1
		DIRECTION OUTPUT ;
		USE SIGNAL ;
		PORT
			LAYER metal1 ;
			RECT 4.061 4.061 4.061 4.061 ;
			END
		END OP1
	PIN OP2
		DIRECTION OUTPUT ;
		USE SIGNAL ;
		PORT
			LAYER metal1 ;
			RECT 4.061 4.061 4.061 4.061 ;
			END
		END OP2
	PIN OP3
		DIRECTION OUTPUT ;
		USE SIGNAL ;
		PORT
			LAYER metal1 ;
			RECT 4.061 4.061 4.061 4.061 ;
			END
		END OP3
	PIN OP4
		DIRECTION OUTPUT ;
		USE SIGNAL ;
		PORT
			LAYER metal1 ;
			RECT 4.061 4.061 4.061 4.061 ;
			END
		END OP4
	PIN OP5
		DIRECTION OUTPUT ;
		USE SIGNAL ;
		PORT
			LAYER metal1 ;
			RECT 4.061 4.061 4.061 4.061 ;
			END
		END OP5
	PIN OP6
		DIRECTION OUTPUT ;
		USE SIGNAL ;
		PORT
			LAYER metal1 ;
			RECT 4.061 4.061 4.061 4.061 ;
			END
		END OP6
	PIN OP7
		DIRECTION OUTPUT ;
		USE SIGNAL ;
		PORT
			LAYER metal1 ;
			RECT 4.061 4.061 4.061 4.061 ;
			END
		END OP7
	PIN OP8
		DIRECTION OUTPUT ;
		USE SIGNAL ;
		PORT
			LAYER metal1 ;
			RECT 4.061 4.061 4.061 4.061 ;
			END
		END OP8
	PIN OP9
		DIRECTION OUTPUT ;
		USE SIGNAL ;
		PORT
			LAYER metal1 ;
			RECT 4.061 4.061 4.061 4.061 ;
			END
		END OP9
	PIN OP10
		DIRECTION OUTPUT ;
		USE SIGNAL ;
		PORT
			LAYER metal1 ;
			RECT 4.061 4.061 4.061 4.061 ;
			END
		END OP10
	PIN OP11
		DIRECTION OUTPUT ;
		USE SIGNAL ;
		PORT
			LAYER metal1 ;
			RECT 4.061 4.061 4.061 4.061 ;
			END
		END OP11
	PIN OP12
		DIRECTION OUTPUT ;
		USE SIGNAL ;
		PORT
			LAYER metal1 ;
			RECT 4.061 4.061 4.061 4.061 ;
			END
		END OP12
	PIN OP13
		DIRECTION OUTPUT ;
		USE SIGNAL ;
		PORT
			LAYER metal1 ;
			RECT 4.061 4.061 4.061 4.061 ;
			END
		END OP13
	PIN OP14
		DIRECTION OUTPUT ;
		USE SIGNAL ;
		PORT
			LAYER metal1 ;
			RECT 4.061 4.061 4.061 4.061 ;
			END
		END OP14
	PIN IP0
		DIRECTION INPUT ;
		USE SIGNAL ;
		PORT
			LAYER metal1 ;
			RECT 4.061 4.061 4.061 4.061 ;
			END
		END IP0
	PIN IP1
		DIRECTION INPUT ;
		USE SIGNAL ;
		PORT
			LAYER metal1 ;
			RECT 4.061 4.061 4.061 4.061 ;
			END
		END IP1
	PIN IP2
		DIRECTION INPUT ;
		USE SIGNAL ;
		PORT
			LAYER metal1 ;
			RECT 4.061 4.061 4.061 4.061 ;
			END
		END IP2
	PIN IP3
		DIRECTION INPUT ;
		USE SIGNAL ;
		PORT
			LAYER metal1 ;
			RECT 4.061 4.061 4.061 4.061 ;
			END
		END IP3
	PIN IP4
		DIRECTION INPUT ;
		USE SIGNAL ;
		PORT
			LAYER metal1 ;
			RECT 4.061 4.061 4.061 4.061 ;
			END
		END IP4
	PIN IP5
		DIRECTION INPUT ;
		USE SIGNAL ;
		PORT
			LAYER metal1 ;
			RECT 4.061 4.061 4.061 4.061 ;
			END
		END IP5
	PIN IP6
		DIRECTION INPUT ;
		USE SIGNAL ;
		PORT
			LAYER metal1 ;
			RECT 4.061 4.061 4.061 4.061 ;
			END
		END IP6
	PIN IP7
		DIRECTION INPUT ;
		USE SIGNAL ;
		PORT
			LAYER metal1 ;
			RECT 4.061 4.061 4.061 4.061 ;
			END
		END IP7
END cluster_36
MACRO cluster_37
	CLASS BLOCK ;
	ORIGIN 0 0 ;
	FOREIGN cluster_37 0 0 ;
	SIZE 8.171 BY 8.171 ;
	SYMMETRY X Y ;
	PIN OP0
		DIRECTION OUTPUT ;
		USE SIGNAL ;
		PORT
			LAYER metal1 ;
			RECT 4.085 4.085 4.085 4.085 ;
			END
		END OP0
	PIN OP1
		DIRECTION OUTPUT ;
		USE SIGNAL ;
		PORT
			LAYER metal1 ;
			RECT 4.085 4.085 4.085 4.085 ;
			END
		END OP1
	PIN OP2
		DIRECTION OUTPUT ;
		USE SIGNAL ;
		PORT
			LAYER metal1 ;
			RECT 4.085 4.085 4.085 4.085 ;
			END
		END OP2
	PIN OP3
		DIRECTION OUTPUT ;
		USE SIGNAL ;
		PORT
			LAYER metal1 ;
			RECT 4.085 4.085 4.085 4.085 ;
			END
		END OP3
	PIN OP4
		DIRECTION OUTPUT ;
		USE SIGNAL ;
		PORT
			LAYER metal1 ;
			RECT 4.085 4.085 4.085 4.085 ;
			END
		END OP4
	PIN OP5
		DIRECTION OUTPUT ;
		USE SIGNAL ;
		PORT
			LAYER metal1 ;
			RECT 4.085 4.085 4.085 4.085 ;
			END
		END OP5
	PIN OP6
		DIRECTION OUTPUT ;
		USE SIGNAL ;
		PORT
			LAYER metal1 ;
			RECT 4.085 4.085 4.085 4.085 ;
			END
		END OP6
	PIN OP7
		DIRECTION OUTPUT ;
		USE SIGNAL ;
		PORT
			LAYER metal1 ;
			RECT 4.085 4.085 4.085 4.085 ;
			END
		END OP7
	PIN OP8
		DIRECTION OUTPUT ;
		USE SIGNAL ;
		PORT
			LAYER metal1 ;
			RECT 4.085 4.085 4.085 4.085 ;
			END
		END OP8
	PIN OP9
		DIRECTION OUTPUT ;
		USE SIGNAL ;
		PORT
			LAYER metal1 ;
			RECT 4.085 4.085 4.085 4.085 ;
			END
		END OP9
	PIN OP10
		DIRECTION OUTPUT ;
		USE SIGNAL ;
		PORT
			LAYER metal1 ;
			RECT 4.085 4.085 4.085 4.085 ;
			END
		END OP10
	PIN OP11
		DIRECTION OUTPUT ;
		USE SIGNAL ;
		PORT
			LAYER metal1 ;
			RECT 4.085 4.085 4.085 4.085 ;
			END
		END OP11
	PIN OP12
		DIRECTION OUTPUT ;
		USE SIGNAL ;
		PORT
			LAYER metal1 ;
			RECT 4.085 4.085 4.085 4.085 ;
			END
		END OP12
	PIN OP13
		DIRECTION OUTPUT ;
		USE SIGNAL ;
		PORT
			LAYER metal1 ;
			RECT 4.085 4.085 4.085 4.085 ;
			END
		END OP13
	PIN OP14
		DIRECTION OUTPUT ;
		USE SIGNAL ;
		PORT
			LAYER metal1 ;
			RECT 4.085 4.085 4.085 4.085 ;
			END
		END OP14
	PIN IP0
		DIRECTION INPUT ;
		USE SIGNAL ;
		PORT
			LAYER metal1 ;
			RECT 4.085 4.085 4.085 4.085 ;
			END
		END IP0
	PIN IP1
		DIRECTION INPUT ;
		USE SIGNAL ;
		PORT
			LAYER metal1 ;
			RECT 4.085 4.085 4.085 4.085 ;
			END
		END IP1
	PIN IP2
		DIRECTION INPUT ;
		USE SIGNAL ;
		PORT
			LAYER metal1 ;
			RECT 4.085 4.085 4.085 4.085 ;
			END
		END IP2
	PIN IP3
		DIRECTION INPUT ;
		USE SIGNAL ;
		PORT
			LAYER metal1 ;
			RECT 4.085 4.085 4.085 4.085 ;
			END
		END IP3
	PIN IP4
		DIRECTION INPUT ;
		USE SIGNAL ;
		PORT
			LAYER metal1 ;
			RECT 4.085 4.085 4.085 4.085 ;
			END
		END IP4
	PIN IP5
		DIRECTION INPUT ;
		USE SIGNAL ;
		PORT
			LAYER metal1 ;
			RECT 4.085 4.085 4.085 4.085 ;
			END
		END IP5
	PIN IP6
		DIRECTION INPUT ;
		USE SIGNAL ;
		PORT
			LAYER metal1 ;
			RECT 4.085 4.085 4.085 4.085 ;
			END
		END IP6
END cluster_37
MACRO cluster_38
	CLASS BLOCK ;
	ORIGIN 0 0 ;
	FOREIGN cluster_38 0 0 ;
	SIZE 7.973 BY 7.974 ;
	SYMMETRY X Y ;
	PIN OP0
		DIRECTION OUTPUT ;
		USE SIGNAL ;
		PORT
			LAYER metal1 ;
			RECT 3.986 3.987 3.986 3.987 ;
			END
		END OP0
	PIN OP1
		DIRECTION OUTPUT ;
		USE SIGNAL ;
		PORT
			LAYER metal1 ;
			RECT 3.986 3.987 3.986 3.987 ;
			END
		END OP1
	PIN OP2
		DIRECTION OUTPUT ;
		USE SIGNAL ;
		PORT
			LAYER metal1 ;
			RECT 3.986 3.987 3.986 3.987 ;
			END
		END OP2
	PIN OP3
		DIRECTION OUTPUT ;
		USE SIGNAL ;
		PORT
			LAYER metal1 ;
			RECT 3.986 3.987 3.986 3.987 ;
			END
		END OP3
	PIN OP4
		DIRECTION OUTPUT ;
		USE SIGNAL ;
		PORT
			LAYER metal1 ;
			RECT 3.986 3.987 3.986 3.987 ;
			END
		END OP4
	PIN OP5
		DIRECTION OUTPUT ;
		USE SIGNAL ;
		PORT
			LAYER metal1 ;
			RECT 3.986 3.987 3.986 3.987 ;
			END
		END OP5
	PIN OP6
		DIRECTION OUTPUT ;
		USE SIGNAL ;
		PORT
			LAYER metal1 ;
			RECT 3.986 3.987 3.986 3.987 ;
			END
		END OP6
	PIN OP7
		DIRECTION OUTPUT ;
		USE SIGNAL ;
		PORT
			LAYER metal1 ;
			RECT 3.986 3.987 3.986 3.987 ;
			END
		END OP7
	PIN OP8
		DIRECTION OUTPUT ;
		USE SIGNAL ;
		PORT
			LAYER metal1 ;
			RECT 3.986 3.987 3.986 3.987 ;
			END
		END OP8
	PIN OP9
		DIRECTION OUTPUT ;
		USE SIGNAL ;
		PORT
			LAYER metal1 ;
			RECT 3.986 3.987 3.986 3.987 ;
			END
		END OP9
	PIN OP10
		DIRECTION OUTPUT ;
		USE SIGNAL ;
		PORT
			LAYER metal1 ;
			RECT 3.986 3.987 3.986 3.987 ;
			END
		END OP10
	PIN OP11
		DIRECTION OUTPUT ;
		USE SIGNAL ;
		PORT
			LAYER metal1 ;
			RECT 3.986 3.987 3.986 3.987 ;
			END
		END OP11
	PIN OP12
		DIRECTION OUTPUT ;
		USE SIGNAL ;
		PORT
			LAYER metal1 ;
			RECT 3.986 3.987 3.986 3.987 ;
			END
		END OP12
	PIN IP0
		DIRECTION INPUT ;
		USE SIGNAL ;
		PORT
			LAYER metal1 ;
			RECT 3.986 3.987 3.986 3.987 ;
			END
		END IP0
	PIN IP1
		DIRECTION INPUT ;
		USE SIGNAL ;
		PORT
			LAYER metal1 ;
			RECT 3.986 3.987 3.986 3.987 ;
			END
		END IP1
	PIN IP2
		DIRECTION INPUT ;
		USE SIGNAL ;
		PORT
			LAYER metal1 ;
			RECT 3.986 3.987 3.986 3.987 ;
			END
		END IP2
	PIN IP3
		DIRECTION INPUT ;
		USE SIGNAL ;
		PORT
			LAYER metal1 ;
			RECT 3.986 3.987 3.986 3.987 ;
			END
		END IP3
	PIN IP4
		DIRECTION INPUT ;
		USE SIGNAL ;
		PORT
			LAYER metal1 ;
			RECT 3.986 3.987 3.986 3.987 ;
			END
		END IP4
	PIN IP5
		DIRECTION INPUT ;
		USE SIGNAL ;
		PORT
			LAYER metal1 ;
			RECT 3.986 3.987 3.986 3.987 ;
			END
		END IP5
	PIN IP6
		DIRECTION INPUT ;
		USE SIGNAL ;
		PORT
			LAYER metal1 ;
			RECT 3.986 3.987 3.986 3.987 ;
			END
		END IP6
END cluster_38
MACRO cluster_39
	CLASS BLOCK ;
	ORIGIN 0 0 ;
	FOREIGN cluster_39 0 0 ;
	SIZE 8.007 BY 8.006 ;
	SYMMETRY X Y ;
	PIN OP0
		DIRECTION OUTPUT ;
		USE SIGNAL ;
		PORT
			LAYER metal1 ;
			RECT 4.003 4.003 4.003 4.003 ;
			END
		END OP0
	PIN OP1
		DIRECTION OUTPUT ;
		USE SIGNAL ;
		PORT
			LAYER metal1 ;
			RECT 4.003 4.003 4.003 4.003 ;
			END
		END OP1
	PIN OP2
		DIRECTION OUTPUT ;
		USE SIGNAL ;
		PORT
			LAYER metal1 ;
			RECT 4.003 4.003 4.003 4.003 ;
			END
		END OP2
	PIN OP3
		DIRECTION OUTPUT ;
		USE SIGNAL ;
		PORT
			LAYER metal1 ;
			RECT 4.003 4.003 4.003 4.003 ;
			END
		END OP3
	PIN OP4
		DIRECTION OUTPUT ;
		USE SIGNAL ;
		PORT
			LAYER metal1 ;
			RECT 4.003 4.003 4.003 4.003 ;
			END
		END OP4
	PIN OP5
		DIRECTION OUTPUT ;
		USE SIGNAL ;
		PORT
			LAYER metal1 ;
			RECT 4.003 4.003 4.003 4.003 ;
			END
		END OP5
	PIN OP6
		DIRECTION OUTPUT ;
		USE SIGNAL ;
		PORT
			LAYER metal1 ;
			RECT 4.003 4.003 4.003 4.003 ;
			END
		END OP6
	PIN OP7
		DIRECTION OUTPUT ;
		USE SIGNAL ;
		PORT
			LAYER metal1 ;
			RECT 4.003 4.003 4.003 4.003 ;
			END
		END OP7
	PIN OP8
		DIRECTION OUTPUT ;
		USE SIGNAL ;
		PORT
			LAYER metal1 ;
			RECT 4.003 4.003 4.003 4.003 ;
			END
		END OP8
	PIN OP9
		DIRECTION OUTPUT ;
		USE SIGNAL ;
		PORT
			LAYER metal1 ;
			RECT 4.003 4.003 4.003 4.003 ;
			END
		END OP9
	PIN OP10
		DIRECTION OUTPUT ;
		USE SIGNAL ;
		PORT
			LAYER metal1 ;
			RECT 4.003 4.003 4.003 4.003 ;
			END
		END OP10
	PIN OP11
		DIRECTION OUTPUT ;
		USE SIGNAL ;
		PORT
			LAYER metal1 ;
			RECT 4.003 4.003 4.003 4.003 ;
			END
		END OP11
	PIN OP12
		DIRECTION OUTPUT ;
		USE SIGNAL ;
		PORT
			LAYER metal1 ;
			RECT 4.003 4.003 4.003 4.003 ;
			END
		END OP12
	PIN IP0
		DIRECTION INPUT ;
		USE SIGNAL ;
		PORT
			LAYER metal1 ;
			RECT 4.003 4.003 4.003 4.003 ;
			END
		END IP0
	PIN IP1
		DIRECTION INPUT ;
		USE SIGNAL ;
		PORT
			LAYER metal1 ;
			RECT 4.003 4.003 4.003 4.003 ;
			END
		END IP1
	PIN IP2
		DIRECTION INPUT ;
		USE SIGNAL ;
		PORT
			LAYER metal1 ;
			RECT 4.003 4.003 4.003 4.003 ;
			END
		END IP2
	PIN IP3
		DIRECTION INPUT ;
		USE SIGNAL ;
		PORT
			LAYER metal1 ;
			RECT 4.003 4.003 4.003 4.003 ;
			END
		END IP3
	PIN IP4
		DIRECTION INPUT ;
		USE SIGNAL ;
		PORT
			LAYER metal1 ;
			RECT 4.003 4.003 4.003 4.003 ;
			END
		END IP4
	PIN IP5
		DIRECTION INPUT ;
		USE SIGNAL ;
		PORT
			LAYER metal1 ;
			RECT 4.003 4.003 4.003 4.003 ;
			END
		END IP5
	PIN IP6
		DIRECTION INPUT ;
		USE SIGNAL ;
		PORT
			LAYER metal1 ;
			RECT 4.003 4.003 4.003 4.003 ;
			END
		END IP6
END cluster_39
MACRO cluster_40
	CLASS BLOCK ;
	ORIGIN 0 0 ;
	FOREIGN cluster_40 0 0 ;
	SIZE 8.023 BY 8.023 ;
	SYMMETRY X Y ;
	PIN OP0
		DIRECTION OUTPUT ;
		USE SIGNAL ;
		PORT
			LAYER metal1 ;
			RECT 4.011 4.011 4.011 4.011 ;
			END
		END OP0
	PIN OP1
		DIRECTION OUTPUT ;
		USE SIGNAL ;
		PORT
			LAYER metal1 ;
			RECT 4.011 4.011 4.011 4.011 ;
			END
		END OP1
	PIN OP2
		DIRECTION OUTPUT ;
		USE SIGNAL ;
		PORT
			LAYER metal1 ;
			RECT 4.011 4.011 4.011 4.011 ;
			END
		END OP2
	PIN OP3
		DIRECTION OUTPUT ;
		USE SIGNAL ;
		PORT
			LAYER metal1 ;
			RECT 4.011 4.011 4.011 4.011 ;
			END
		END OP3
	PIN OP4
		DIRECTION OUTPUT ;
		USE SIGNAL ;
		PORT
			LAYER metal1 ;
			RECT 4.011 4.011 4.011 4.011 ;
			END
		END OP4
	PIN OP5
		DIRECTION OUTPUT ;
		USE SIGNAL ;
		PORT
			LAYER metal1 ;
			RECT 4.011 4.011 4.011 4.011 ;
			END
		END OP5
	PIN OP6
		DIRECTION OUTPUT ;
		USE SIGNAL ;
		PORT
			LAYER metal1 ;
			RECT 4.011 4.011 4.011 4.011 ;
			END
		END OP6
	PIN OP7
		DIRECTION OUTPUT ;
		USE SIGNAL ;
		PORT
			LAYER metal1 ;
			RECT 4.011 4.011 4.011 4.011 ;
			END
		END OP7
	PIN OP8
		DIRECTION OUTPUT ;
		USE SIGNAL ;
		PORT
			LAYER metal1 ;
			RECT 4.011 4.011 4.011 4.011 ;
			END
		END OP8
	PIN OP9
		DIRECTION OUTPUT ;
		USE SIGNAL ;
		PORT
			LAYER metal1 ;
			RECT 4.011 4.011 4.011 4.011 ;
			END
		END OP9
	PIN OP10
		DIRECTION OUTPUT ;
		USE SIGNAL ;
		PORT
			LAYER metal1 ;
			RECT 4.011 4.011 4.011 4.011 ;
			END
		END OP10
	PIN OP11
		DIRECTION OUTPUT ;
		USE SIGNAL ;
		PORT
			LAYER metal1 ;
			RECT 4.011 4.011 4.011 4.011 ;
			END
		END OP11
	PIN OP12
		DIRECTION OUTPUT ;
		USE SIGNAL ;
		PORT
			LAYER metal1 ;
			RECT 4.011 4.011 4.011 4.011 ;
			END
		END OP12
	PIN IP0
		DIRECTION INPUT ;
		USE SIGNAL ;
		PORT
			LAYER metal1 ;
			RECT 4.011 4.011 4.011 4.011 ;
			END
		END IP0
	PIN IP1
		DIRECTION INPUT ;
		USE SIGNAL ;
		PORT
			LAYER metal1 ;
			RECT 4.011 4.011 4.011 4.011 ;
			END
		END IP1
	PIN IP2
		DIRECTION INPUT ;
		USE SIGNAL ;
		PORT
			LAYER metal1 ;
			RECT 4.011 4.011 4.011 4.011 ;
			END
		END IP2
	PIN IP3
		DIRECTION INPUT ;
		USE SIGNAL ;
		PORT
			LAYER metal1 ;
			RECT 4.011 4.011 4.011 4.011 ;
			END
		END IP3
	PIN IP4
		DIRECTION INPUT ;
		USE SIGNAL ;
		PORT
			LAYER metal1 ;
			RECT 4.011 4.011 4.011 4.011 ;
			END
		END IP4
	PIN IP5
		DIRECTION INPUT ;
		USE SIGNAL ;
		PORT
			LAYER metal1 ;
			RECT 4.011 4.011 4.011 4.011 ;
			END
		END IP5
	PIN IP6
		DIRECTION INPUT ;
		USE SIGNAL ;
		PORT
			LAYER metal1 ;
			RECT 4.011 4.011 4.011 4.011 ;
			END
		END IP6
END cluster_40
MACRO cluster_41
	CLASS BLOCK ;
	ORIGIN 0 0 ;
	FOREIGN cluster_41 0 0 ;
	SIZE 7.957 BY 7.956 ;
	SYMMETRY X Y ;
	PIN OP0
		DIRECTION OUTPUT ;
		USE SIGNAL ;
		PORT
			LAYER metal1 ;
			RECT 3.978 3.978 3.978 3.978 ;
			END
		END OP0
	PIN OP1
		DIRECTION OUTPUT ;
		USE SIGNAL ;
		PORT
			LAYER metal1 ;
			RECT 3.978 3.978 3.978 3.978 ;
			END
		END OP1
	PIN OP2
		DIRECTION OUTPUT ;
		USE SIGNAL ;
		PORT
			LAYER metal1 ;
			RECT 3.978 3.978 3.978 3.978 ;
			END
		END OP2
	PIN OP3
		DIRECTION OUTPUT ;
		USE SIGNAL ;
		PORT
			LAYER metal1 ;
			RECT 3.978 3.978 3.978 3.978 ;
			END
		END OP3
	PIN OP4
		DIRECTION OUTPUT ;
		USE SIGNAL ;
		PORT
			LAYER metal1 ;
			RECT 3.978 3.978 3.978 3.978 ;
			END
		END OP4
	PIN OP5
		DIRECTION OUTPUT ;
		USE SIGNAL ;
		PORT
			LAYER metal1 ;
			RECT 3.978 3.978 3.978 3.978 ;
			END
		END OP5
	PIN OP6
		DIRECTION OUTPUT ;
		USE SIGNAL ;
		PORT
			LAYER metal1 ;
			RECT 3.978 3.978 3.978 3.978 ;
			END
		END OP6
	PIN OP7
		DIRECTION OUTPUT ;
		USE SIGNAL ;
		PORT
			LAYER metal1 ;
			RECT 3.978 3.978 3.978 3.978 ;
			END
		END OP7
	PIN OP8
		DIRECTION OUTPUT ;
		USE SIGNAL ;
		PORT
			LAYER metal1 ;
			RECT 3.978 3.978 3.978 3.978 ;
			END
		END OP8
	PIN OP9
		DIRECTION OUTPUT ;
		USE SIGNAL ;
		PORT
			LAYER metal1 ;
			RECT 3.978 3.978 3.978 3.978 ;
			END
		END OP9
	PIN OP10
		DIRECTION OUTPUT ;
		USE SIGNAL ;
		PORT
			LAYER metal1 ;
			RECT 3.978 3.978 3.978 3.978 ;
			END
		END OP10
	PIN OP11
		DIRECTION OUTPUT ;
		USE SIGNAL ;
		PORT
			LAYER metal1 ;
			RECT 3.978 3.978 3.978 3.978 ;
			END
		END OP11
	PIN OP12
		DIRECTION OUTPUT ;
		USE SIGNAL ;
		PORT
			LAYER metal1 ;
			RECT 3.978 3.978 3.978 3.978 ;
			END
		END OP12
	PIN IP0
		DIRECTION INPUT ;
		USE SIGNAL ;
		PORT
			LAYER metal1 ;
			RECT 3.978 3.978 3.978 3.978 ;
			END
		END IP0
	PIN IP1
		DIRECTION INPUT ;
		USE SIGNAL ;
		PORT
			LAYER metal1 ;
			RECT 3.978 3.978 3.978 3.978 ;
			END
		END IP1
	PIN IP2
		DIRECTION INPUT ;
		USE SIGNAL ;
		PORT
			LAYER metal1 ;
			RECT 3.978 3.978 3.978 3.978 ;
			END
		END IP2
	PIN IP3
		DIRECTION INPUT ;
		USE SIGNAL ;
		PORT
			LAYER metal1 ;
			RECT 3.978 3.978 3.978 3.978 ;
			END
		END IP3
	PIN IP4
		DIRECTION INPUT ;
		USE SIGNAL ;
		PORT
			LAYER metal1 ;
			RECT 3.978 3.978 3.978 3.978 ;
			END
		END IP4
	PIN IP5
		DIRECTION INPUT ;
		USE SIGNAL ;
		PORT
			LAYER metal1 ;
			RECT 3.978 3.978 3.978 3.978 ;
			END
		END IP5
	PIN IP6
		DIRECTION INPUT ;
		USE SIGNAL ;
		PORT
			LAYER metal1 ;
			RECT 3.978 3.978 3.978 3.978 ;
			END
		END IP6
END cluster_41
MACRO cluster_42
	CLASS BLOCK ;
	ORIGIN 0 0 ;
	FOREIGN cluster_42 0 0 ;
	SIZE 7.33 BY 7.33 ;
	SYMMETRY X Y ;
	PIN OP0
		DIRECTION OUTPUT ;
		USE SIGNAL ;
		PORT
			LAYER metal1 ;
			RECT 3.665 3.665 3.665 3.665 ;
			END
		END OP0
	PIN OP1
		DIRECTION OUTPUT ;
		USE SIGNAL ;
		PORT
			LAYER metal1 ;
			RECT 3.665 3.665 3.665 3.665 ;
			END
		END OP1
	PIN OP2
		DIRECTION OUTPUT ;
		USE SIGNAL ;
		PORT
			LAYER metal1 ;
			RECT 3.665 3.665 3.665 3.665 ;
			END
		END OP2
	PIN OP3
		DIRECTION OUTPUT ;
		USE SIGNAL ;
		PORT
			LAYER metal1 ;
			RECT 3.665 3.665 3.665 3.665 ;
			END
		END OP3
	PIN OP4
		DIRECTION OUTPUT ;
		USE SIGNAL ;
		PORT
			LAYER metal1 ;
			RECT 3.665 3.665 3.665 3.665 ;
			END
		END OP4
	PIN OP5
		DIRECTION OUTPUT ;
		USE SIGNAL ;
		PORT
			LAYER metal1 ;
			RECT 3.665 3.665 3.665 3.665 ;
			END
		END OP5
	PIN OP6
		DIRECTION OUTPUT ;
		USE SIGNAL ;
		PORT
			LAYER metal1 ;
			RECT 3.665 3.665 3.665 3.665 ;
			END
		END OP6
	PIN OP7
		DIRECTION OUTPUT ;
		USE SIGNAL ;
		PORT
			LAYER metal1 ;
			RECT 3.665 3.665 3.665 3.665 ;
			END
		END OP7
	PIN OP8
		DIRECTION OUTPUT ;
		USE SIGNAL ;
		PORT
			LAYER metal1 ;
			RECT 3.665 3.665 3.665 3.665 ;
			END
		END OP8
	PIN OP9
		DIRECTION OUTPUT ;
		USE SIGNAL ;
		PORT
			LAYER metal1 ;
			RECT 3.665 3.665 3.665 3.665 ;
			END
		END OP9
	PIN OP10
		DIRECTION OUTPUT ;
		USE SIGNAL ;
		PORT
			LAYER metal1 ;
			RECT 3.665 3.665 3.665 3.665 ;
			END
		END OP10
	PIN OP11
		DIRECTION OUTPUT ;
		USE SIGNAL ;
		PORT
			LAYER metal1 ;
			RECT 3.665 3.665 3.665 3.665 ;
			END
		END OP11
	PIN OP12
		DIRECTION OUTPUT ;
		USE SIGNAL ;
		PORT
			LAYER metal1 ;
			RECT 3.665 3.665 3.665 3.665 ;
			END
		END OP12
	PIN OP13
		DIRECTION OUTPUT ;
		USE SIGNAL ;
		PORT
			LAYER metal1 ;
			RECT 3.665 3.665 3.665 3.665 ;
			END
		END OP13
	PIN OP14
		DIRECTION OUTPUT ;
		USE SIGNAL ;
		PORT
			LAYER metal1 ;
			RECT 3.665 3.665 3.665 3.665 ;
			END
		END OP14
	PIN OP15
		DIRECTION OUTPUT ;
		USE SIGNAL ;
		PORT
			LAYER metal1 ;
			RECT 3.665 3.665 3.665 3.665 ;
			END
		END OP15
	PIN IP0
		DIRECTION INPUT ;
		USE SIGNAL ;
		PORT
			LAYER metal1 ;
			RECT 3.665 3.665 3.665 3.665 ;
			END
		END IP0
	PIN IP1
		DIRECTION INPUT ;
		USE SIGNAL ;
		PORT
			LAYER metal1 ;
			RECT 3.665 3.665 3.665 3.665 ;
			END
		END IP1
	PIN IP2
		DIRECTION INPUT ;
		USE SIGNAL ;
		PORT
			LAYER metal1 ;
			RECT 3.665 3.665 3.665 3.665 ;
			END
		END IP2
	PIN IP3
		DIRECTION INPUT ;
		USE SIGNAL ;
		PORT
			LAYER metal1 ;
			RECT 3.665 3.665 3.665 3.665 ;
			END
		END IP3
	PIN IP4
		DIRECTION INPUT ;
		USE SIGNAL ;
		PORT
			LAYER metal1 ;
			RECT 3.665 3.665 3.665 3.665 ;
			END
		END IP4
	PIN IP5
		DIRECTION INPUT ;
		USE SIGNAL ;
		PORT
			LAYER metal1 ;
			RECT 3.665 3.665 3.665 3.665 ;
			END
		END IP5
	PIN IP6
		DIRECTION INPUT ;
		USE SIGNAL ;
		PORT
			LAYER metal1 ;
			RECT 3.665 3.665 3.665 3.665 ;
			END
		END IP6
END cluster_42
MACRO cluster_43
	CLASS BLOCK ;
	ORIGIN 0 0 ;
	FOREIGN cluster_43 0 0 ;
	SIZE 6.585 BY 6.584 ;
	SYMMETRY X Y ;
	PIN OP0
		DIRECTION OUTPUT ;
		USE SIGNAL ;
		PORT
			LAYER metal1 ;
			RECT 3.292 3.292 3.292 3.292 ;
			END
		END OP0
	PIN OP1
		DIRECTION OUTPUT ;
		USE SIGNAL ;
		PORT
			LAYER metal1 ;
			RECT 3.292 3.292 3.292 3.292 ;
			END
		END OP1
	PIN OP2
		DIRECTION OUTPUT ;
		USE SIGNAL ;
		PORT
			LAYER metal1 ;
			RECT 3.292 3.292 3.292 3.292 ;
			END
		END OP2
	PIN OP3
		DIRECTION OUTPUT ;
		USE SIGNAL ;
		PORT
			LAYER metal1 ;
			RECT 3.292 3.292 3.292 3.292 ;
			END
		END OP3
	PIN OP4
		DIRECTION OUTPUT ;
		USE SIGNAL ;
		PORT
			LAYER metal1 ;
			RECT 3.292 3.292 3.292 3.292 ;
			END
		END OP4
	PIN OP5
		DIRECTION OUTPUT ;
		USE SIGNAL ;
		PORT
			LAYER metal1 ;
			RECT 3.292 3.292 3.292 3.292 ;
			END
		END OP5
	PIN IP0
		DIRECTION INPUT ;
		USE SIGNAL ;
		PORT
			LAYER metal1 ;
			RECT 3.292 3.292 3.292 3.292 ;
			END
		END IP0
END cluster_43
MACRO cluster_44
	CLASS BLOCK ;
	ORIGIN 0 0 ;
	FOREIGN cluster_44 0 0 ;
	SIZE 6.958 BY 6.958 ;
	SYMMETRY X Y ;
	PIN OP0
		DIRECTION OUTPUT ;
		USE SIGNAL ;
		PORT
			LAYER metal1 ;
			RECT 3.479 3.479 3.479 3.479 ;
			END
		END OP0
	PIN OP1
		DIRECTION OUTPUT ;
		USE SIGNAL ;
		PORT
			LAYER metal1 ;
			RECT 3.479 3.479 3.479 3.479 ;
			END
		END OP1
	PIN OP2
		DIRECTION OUTPUT ;
		USE SIGNAL ;
		PORT
			LAYER metal1 ;
			RECT 3.479 3.479 3.479 3.479 ;
			END
		END OP2
	PIN OP3
		DIRECTION OUTPUT ;
		USE SIGNAL ;
		PORT
			LAYER metal1 ;
			RECT 3.479 3.479 3.479 3.479 ;
			END
		END OP3
	PIN OP4
		DIRECTION OUTPUT ;
		USE SIGNAL ;
		PORT
			LAYER metal1 ;
			RECT 3.479 3.479 3.479 3.479 ;
			END
		END OP4
	PIN OP5
		DIRECTION OUTPUT ;
		USE SIGNAL ;
		PORT
			LAYER metal1 ;
			RECT 3.479 3.479 3.479 3.479 ;
			END
		END OP5
	PIN OP6
		DIRECTION OUTPUT ;
		USE SIGNAL ;
		PORT
			LAYER metal1 ;
			RECT 3.479 3.479 3.479 3.479 ;
			END
		END OP6
	PIN OP7
		DIRECTION OUTPUT ;
		USE SIGNAL ;
		PORT
			LAYER metal1 ;
			RECT 3.479 3.479 3.479 3.479 ;
			END
		END OP7
	PIN OP8
		DIRECTION OUTPUT ;
		USE SIGNAL ;
		PORT
			LAYER metal1 ;
			RECT 3.479 3.479 3.479 3.479 ;
			END
		END OP8
	PIN OP9
		DIRECTION OUTPUT ;
		USE SIGNAL ;
		PORT
			LAYER metal1 ;
			RECT 3.479 3.479 3.479 3.479 ;
			END
		END OP9
	PIN OP10
		DIRECTION OUTPUT ;
		USE SIGNAL ;
		PORT
			LAYER metal1 ;
			RECT 3.479 3.479 3.479 3.479 ;
			END
		END OP10
	PIN OP11
		DIRECTION OUTPUT ;
		USE SIGNAL ;
		PORT
			LAYER metal1 ;
			RECT 3.479 3.479 3.479 3.479 ;
			END
		END OP11
	PIN OP12
		DIRECTION OUTPUT ;
		USE SIGNAL ;
		PORT
			LAYER metal1 ;
			RECT 3.479 3.479 3.479 3.479 ;
			END
		END OP12
	PIN OP13
		DIRECTION OUTPUT ;
		USE SIGNAL ;
		PORT
			LAYER metal1 ;
			RECT 3.479 3.479 3.479 3.479 ;
			END
		END OP13
	PIN IP0
		DIRECTION INPUT ;
		USE SIGNAL ;
		PORT
			LAYER metal1 ;
			RECT 3.479 3.479 3.479 3.479 ;
			END
		END IP0
	PIN IP1
		DIRECTION INPUT ;
		USE SIGNAL ;
		PORT
			LAYER metal1 ;
			RECT 3.479 3.479 3.479 3.479 ;
			END
		END IP1
	PIN IP2
		DIRECTION INPUT ;
		USE SIGNAL ;
		PORT
			LAYER metal1 ;
			RECT 3.479 3.479 3.479 3.479 ;
			END
		END IP2
	PIN IP3
		DIRECTION INPUT ;
		USE SIGNAL ;
		PORT
			LAYER metal1 ;
			RECT 3.479 3.479 3.479 3.479 ;
			END
		END IP3
	PIN IP4
		DIRECTION INPUT ;
		USE SIGNAL ;
		PORT
			LAYER metal1 ;
			RECT 3.479 3.479 3.479 3.479 ;
			END
		END IP4
	PIN IP5
		DIRECTION INPUT ;
		USE SIGNAL ;
		PORT
			LAYER metal1 ;
			RECT 3.479 3.479 3.479 3.479 ;
			END
		END IP5
END cluster_44
MACRO cluster_45
	CLASS BLOCK ;
	ORIGIN 0 0 ;
	FOREIGN cluster_45 0 0 ;
	SIZE 4.407 BY 4.406 ;
	SYMMETRY X Y ;
	PIN OP0
		DIRECTION OUTPUT ;
		USE SIGNAL ;
		PORT
			LAYER metal1 ;
			RECT 2.204 2.203 2.204 2.203 ;
			END
		END OP0
	PIN OP1
		DIRECTION OUTPUT ;
		USE SIGNAL ;
		PORT
			LAYER metal1 ;
			RECT 2.204 2.203 2.204 2.203 ;
			END
		END OP1
	PIN OP2
		DIRECTION OUTPUT ;
		USE SIGNAL ;
		PORT
			LAYER metal1 ;
			RECT 2.204 2.203 2.204 2.203 ;
			END
		END OP2
	PIN OP3
		DIRECTION OUTPUT ;
		USE SIGNAL ;
		PORT
			LAYER metal1 ;
			RECT 2.204 2.203 2.204 2.203 ;
			END
		END OP3
	PIN OP4
		DIRECTION OUTPUT ;
		USE SIGNAL ;
		PORT
			LAYER metal1 ;
			RECT 2.204 2.203 2.204 2.203 ;
			END
		END OP4
	PIN IP0
		DIRECTION INPUT ;
		USE SIGNAL ;
		PORT
			LAYER metal1 ;
			RECT 2.204 2.203 2.204 2.203 ;
			END
		END IP0
	PIN IP1
		DIRECTION INPUT ;
		USE SIGNAL ;
		PORT
			LAYER metal1 ;
			RECT 2.204 2.203 2.204 2.203 ;
			END
		END IP1
END cluster_45
MACRO cluster_46
	CLASS BLOCK ;
	ORIGIN 0 0 ;
	FOREIGN cluster_46 0 0 ;
	SIZE 2.63 BY 2.63 ;
	SYMMETRY X Y ;
	PIN OP0
		DIRECTION OUTPUT ;
		USE SIGNAL ;
		PORT
			LAYER metal1 ;
			RECT 1.315 1.315 1.315 1.315 ;
			END
		END OP0
	PIN OP1
		DIRECTION OUTPUT ;
		USE SIGNAL ;
		PORT
			LAYER metal1 ;
			RECT 1.315 1.315 1.315 1.315 ;
			END
		END OP1
	PIN OP2
		DIRECTION OUTPUT ;
		USE SIGNAL ;
		PORT
			LAYER metal1 ;
			RECT 1.315 1.315 1.315 1.315 ;
			END
		END OP2
	PIN IP0
		DIRECTION INPUT ;
		USE SIGNAL ;
		PORT
			LAYER metal1 ;
			RECT 1.315 1.315 1.315 1.315 ;
			END
		END IP0
END cluster_46
MACRO cluster_47
	CLASS BLOCK ;
	ORIGIN 0 0 ;
	FOREIGN cluster_47 0 0 ;
	SIZE 2.63 BY 2.63 ;
	SYMMETRY X Y ;
	PIN OP0
		DIRECTION OUTPUT ;
		USE SIGNAL ;
		PORT
			LAYER metal1 ;
			RECT 1.315 1.315 1.315 1.315 ;
			END
		END OP0
	PIN OP1
		DIRECTION OUTPUT ;
		USE SIGNAL ;
		PORT
			LAYER metal1 ;
			RECT 1.315 1.315 1.315 1.315 ;
			END
		END OP1
	PIN OP2
		DIRECTION OUTPUT ;
		USE SIGNAL ;
		PORT
			LAYER metal1 ;
			RECT 1.315 1.315 1.315 1.315 ;
			END
		END OP2
	PIN IP0
		DIRECTION INPUT ;
		USE SIGNAL ;
		PORT
			LAYER metal1 ;
			RECT 1.315 1.315 1.315 1.315 ;
			END
		END IP0
END cluster_47
MACRO cluster_48
	CLASS BLOCK ;
	ORIGIN 0 0 ;
	FOREIGN cluster_48 0 0 ;
	SIZE 2.63 BY 2.63 ;
	SYMMETRY X Y ;
	PIN OP0
		DIRECTION OUTPUT ;
		USE SIGNAL ;
		PORT
			LAYER metal1 ;
			RECT 1.315 1.315 1.315 1.315 ;
			END
		END OP0
	PIN OP1
		DIRECTION OUTPUT ;
		USE SIGNAL ;
		PORT
			LAYER metal1 ;
			RECT 1.315 1.315 1.315 1.315 ;
			END
		END OP1
	PIN OP2
		DIRECTION OUTPUT ;
		USE SIGNAL ;
		PORT
			LAYER metal1 ;
			RECT 1.315 1.315 1.315 1.315 ;
			END
		END OP2
	PIN IP0
		DIRECTION INPUT ;
		USE SIGNAL ;
		PORT
			LAYER metal1 ;
			RECT 1.315 1.315 1.315 1.315 ;
			END
		END IP0
END cluster_48
MACRO cluster_49
	CLASS BLOCK ;
	ORIGIN 0 0 ;
	FOREIGN cluster_49 0 0 ;
	SIZE 2.63 BY 2.63 ;
	SYMMETRY X Y ;
	PIN OP0
		DIRECTION OUTPUT ;
		USE SIGNAL ;
		PORT
			LAYER metal1 ;
			RECT 1.315 1.315 1.315 1.315 ;
			END
		END OP0
	PIN OP1
		DIRECTION OUTPUT ;
		USE SIGNAL ;
		PORT
			LAYER metal1 ;
			RECT 1.315 1.315 1.315 1.315 ;
			END
		END OP1
	PIN OP2
		DIRECTION OUTPUT ;
		USE SIGNAL ;
		PORT
			LAYER metal1 ;
			RECT 1.315 1.315 1.315 1.315 ;
			END
		END OP2
	PIN IP0
		DIRECTION INPUT ;
		USE SIGNAL ;
		PORT
			LAYER metal1 ;
			RECT 1.315 1.315 1.315 1.315 ;
			END
		END IP0
END cluster_49
MACRO cluster_50
	CLASS BLOCK ;
	ORIGIN 0 0 ;
	FOREIGN cluster_50 0 0 ;
	SIZE 2.63 BY 2.63 ;
	SYMMETRY X Y ;
	PIN OP0
		DIRECTION OUTPUT ;
		USE SIGNAL ;
		PORT
			LAYER metal1 ;
			RECT 1.315 1.315 1.315 1.315 ;
			END
		END OP0
	PIN OP1
		DIRECTION OUTPUT ;
		USE SIGNAL ;
		PORT
			LAYER metal1 ;
			RECT 1.315 1.315 1.315 1.315 ;
			END
		END OP1
	PIN OP2
		DIRECTION OUTPUT ;
		USE SIGNAL ;
		PORT
			LAYER metal1 ;
			RECT 1.315 1.315 1.315 1.315 ;
			END
		END OP2
	PIN IP0
		DIRECTION INPUT ;
		USE SIGNAL ;
		PORT
			LAYER metal1 ;
			RECT 1.315 1.315 1.315 1.315 ;
			END
		END IP0
END cluster_50
MACRO cluster_51
	CLASS BLOCK ;
	ORIGIN 0 0 ;
	FOREIGN cluster_51 0 0 ;
	SIZE 2.63 BY 2.63 ;
	SYMMETRY X Y ;
	PIN OP0
		DIRECTION OUTPUT ;
		USE SIGNAL ;
		PORT
			LAYER metal1 ;
			RECT 1.315 1.315 1.315 1.315 ;
			END
		END OP0
	PIN OP1
		DIRECTION OUTPUT ;
		USE SIGNAL ;
		PORT
			LAYER metal1 ;
			RECT 1.315 1.315 1.315 1.315 ;
			END
		END OP1
	PIN OP2
		DIRECTION OUTPUT ;
		USE SIGNAL ;
		PORT
			LAYER metal1 ;
			RECT 1.315 1.315 1.315 1.315 ;
			END
		END OP2
	PIN IP0
		DIRECTION INPUT ;
		USE SIGNAL ;
		PORT
			LAYER metal1 ;
			RECT 1.315 1.315 1.315 1.315 ;
			END
		END IP0
END cluster_51
MACRO cluster_52
	CLASS BLOCK ;
	ORIGIN 0 0 ;
	FOREIGN cluster_52 0 0 ;
	SIZE 2.63 BY 2.63 ;
	SYMMETRY X Y ;
	PIN OP0
		DIRECTION OUTPUT ;
		USE SIGNAL ;
		PORT
			LAYER metal1 ;
			RECT 1.315 1.315 1.315 1.315 ;
			END
		END OP0
	PIN OP1
		DIRECTION OUTPUT ;
		USE SIGNAL ;
		PORT
			LAYER metal1 ;
			RECT 1.315 1.315 1.315 1.315 ;
			END
		END OP1
	PIN OP2
		DIRECTION OUTPUT ;
		USE SIGNAL ;
		PORT
			LAYER metal1 ;
			RECT 1.315 1.315 1.315 1.315 ;
			END
		END OP2
	PIN IP0
		DIRECTION INPUT ;
		USE SIGNAL ;
		PORT
			LAYER metal1 ;
			RECT 1.315 1.315 1.315 1.315 ;
			END
		END IP0
END cluster_52
MACRO cluster_53
	CLASS BLOCK ;
	ORIGIN 0 0 ;
	FOREIGN cluster_53 0 0 ;
	SIZE 2.63 BY 2.63 ;
	SYMMETRY X Y ;
	PIN OP0
		DIRECTION OUTPUT ;
		USE SIGNAL ;
		PORT
			LAYER metal1 ;
			RECT 1.315 1.315 1.315 1.315 ;
			END
		END OP0
	PIN OP1
		DIRECTION OUTPUT ;
		USE SIGNAL ;
		PORT
			LAYER metal1 ;
			RECT 1.315 1.315 1.315 1.315 ;
			END
		END OP1
	PIN OP2
		DIRECTION OUTPUT ;
		USE SIGNAL ;
		PORT
			LAYER metal1 ;
			RECT 1.315 1.315 1.315 1.315 ;
			END
		END OP2
	PIN IP0
		DIRECTION INPUT ;
		USE SIGNAL ;
		PORT
			LAYER metal1 ;
			RECT 1.315 1.315 1.315 1.315 ;
			END
		END IP0
END cluster_53
MACRO cluster_54
	CLASS BLOCK ;
	ORIGIN 0 0 ;
	FOREIGN cluster_54 0 0 ;
	SIZE 2.63 BY 2.63 ;
	SYMMETRY X Y ;
	PIN OP0
		DIRECTION OUTPUT ;
		USE SIGNAL ;
		PORT
			LAYER metal1 ;
			RECT 1.315 1.315 1.315 1.315 ;
			END
		END OP0
	PIN OP1
		DIRECTION OUTPUT ;
		USE SIGNAL ;
		PORT
			LAYER metal1 ;
			RECT 1.315 1.315 1.315 1.315 ;
			END
		END OP1
	PIN OP2
		DIRECTION OUTPUT ;
		USE SIGNAL ;
		PORT
			LAYER metal1 ;
			RECT 1.315 1.315 1.315 1.315 ;
			END
		END OP2
	PIN IP0
		DIRECTION INPUT ;
		USE SIGNAL ;
		PORT
			LAYER metal1 ;
			RECT 1.315 1.315 1.315 1.315 ;
			END
		END IP0
END cluster_54
MACRO cluster_55
	CLASS BLOCK ;
	ORIGIN 0 0 ;
	FOREIGN cluster_55 0 0 ;
	SIZE 2.63 BY 2.63 ;
	SYMMETRY X Y ;
	PIN OP0
		DIRECTION OUTPUT ;
		USE SIGNAL ;
		PORT
			LAYER metal1 ;
			RECT 1.315 1.315 1.315 1.315 ;
			END
		END OP0
	PIN OP1
		DIRECTION OUTPUT ;
		USE SIGNAL ;
		PORT
			LAYER metal1 ;
			RECT 1.315 1.315 1.315 1.315 ;
			END
		END OP1
	PIN OP2
		DIRECTION OUTPUT ;
		USE SIGNAL ;
		PORT
			LAYER metal1 ;
			RECT 1.315 1.315 1.315 1.315 ;
			END
		END OP2
	PIN IP0
		DIRECTION INPUT ;
		USE SIGNAL ;
		PORT
			LAYER metal1 ;
			RECT 1.315 1.315 1.315 1.315 ;
			END
		END IP0
END cluster_55
MACRO cluster_56
	CLASS BLOCK ;
	ORIGIN 0 0 ;
	FOREIGN cluster_56 0 0 ;
	SIZE 2.63 BY 2.63 ;
	SYMMETRY X Y ;
	PIN OP0
		DIRECTION OUTPUT ;
		USE SIGNAL ;
		PORT
			LAYER metal1 ;
			RECT 1.315 1.315 1.315 1.315 ;
			END
		END OP0
	PIN OP1
		DIRECTION OUTPUT ;
		USE SIGNAL ;
		PORT
			LAYER metal1 ;
			RECT 1.315 1.315 1.315 1.315 ;
			END
		END OP1
	PIN OP2
		DIRECTION OUTPUT ;
		USE SIGNAL ;
		PORT
			LAYER metal1 ;
			RECT 1.315 1.315 1.315 1.315 ;
			END
		END OP2
	PIN IP0
		DIRECTION INPUT ;
		USE SIGNAL ;
		PORT
			LAYER metal1 ;
			RECT 1.315 1.315 1.315 1.315 ;
			END
		END IP0
END cluster_56
MACRO cluster_57
	CLASS BLOCK ;
	ORIGIN 0 0 ;
	FOREIGN cluster_57 0 0 ;
	SIZE 2.63 BY 2.63 ;
	SYMMETRY X Y ;
	PIN OP0
		DIRECTION OUTPUT ;
		USE SIGNAL ;
		PORT
			LAYER metal1 ;
			RECT 1.315 1.315 1.315 1.315 ;
			END
		END OP0
	PIN OP1
		DIRECTION OUTPUT ;
		USE SIGNAL ;
		PORT
			LAYER metal1 ;
			RECT 1.315 1.315 1.315 1.315 ;
			END
		END OP1
	PIN OP2
		DIRECTION OUTPUT ;
		USE SIGNAL ;
		PORT
			LAYER metal1 ;
			RECT 1.315 1.315 1.315 1.315 ;
			END
		END OP2
	PIN IP0
		DIRECTION INPUT ;
		USE SIGNAL ;
		PORT
			LAYER metal1 ;
			RECT 1.315 1.315 1.315 1.315 ;
			END
		END IP0
END cluster_57
MACRO cluster_58
	CLASS BLOCK ;
	ORIGIN 0 0 ;
	FOREIGN cluster_58 0 0 ;
	SIZE 2.63 BY 2.63 ;
	SYMMETRY X Y ;
	PIN OP0
		DIRECTION OUTPUT ;
		USE SIGNAL ;
		PORT
			LAYER metal1 ;
			RECT 1.315 1.315 1.315 1.315 ;
			END
		END OP0
	PIN OP1
		DIRECTION OUTPUT ;
		USE SIGNAL ;
		PORT
			LAYER metal1 ;
			RECT 1.315 1.315 1.315 1.315 ;
			END
		END OP1
	PIN OP2
		DIRECTION OUTPUT ;
		USE SIGNAL ;
		PORT
			LAYER metal1 ;
			RECT 1.315 1.315 1.315 1.315 ;
			END
		END OP2
	PIN IP0
		DIRECTION INPUT ;
		USE SIGNAL ;
		PORT
			LAYER metal1 ;
			RECT 1.315 1.315 1.315 1.315 ;
			END
		END IP0
END cluster_58
MACRO cluster_59
	CLASS BLOCK ;
	ORIGIN 0 0 ;
	FOREIGN cluster_59 0 0 ;
	SIZE 2.63 BY 2.63 ;
	SYMMETRY X Y ;
	PIN OP0
		DIRECTION OUTPUT ;
		USE SIGNAL ;
		PORT
			LAYER metal1 ;
			RECT 1.315 1.315 1.315 1.315 ;
			END
		END OP0
	PIN OP1
		DIRECTION OUTPUT ;
		USE SIGNAL ;
		PORT
			LAYER metal1 ;
			RECT 1.315 1.315 1.315 1.315 ;
			END
		END OP1
	PIN OP2
		DIRECTION OUTPUT ;
		USE SIGNAL ;
		PORT
			LAYER metal1 ;
			RECT 1.315 1.315 1.315 1.315 ;
			END
		END OP2
	PIN IP0
		DIRECTION INPUT ;
		USE SIGNAL ;
		PORT
			LAYER metal1 ;
			RECT 1.315 1.315 1.315 1.315 ;
			END
		END IP0
END cluster_59
MACRO cluster_60
	CLASS BLOCK ;
	ORIGIN 0 0 ;
	FOREIGN cluster_60 0 0 ;
	SIZE 2.63 BY 2.63 ;
	SYMMETRY X Y ;
	PIN OP0
		DIRECTION OUTPUT ;
		USE SIGNAL ;
		PORT
			LAYER metal1 ;
			RECT 1.315 1.315 1.315 1.315 ;
			END
		END OP0
	PIN OP1
		DIRECTION OUTPUT ;
		USE SIGNAL ;
		PORT
			LAYER metal1 ;
			RECT 1.315 1.315 1.315 1.315 ;
			END
		END OP1
	PIN OP2
		DIRECTION OUTPUT ;
		USE SIGNAL ;
		PORT
			LAYER metal1 ;
			RECT 1.315 1.315 1.315 1.315 ;
			END
		END OP2
	PIN IP0
		DIRECTION INPUT ;
		USE SIGNAL ;
		PORT
			LAYER metal1 ;
			RECT 1.315 1.315 1.315 1.315 ;
			END
		END IP0
END cluster_60
MACRO cluster_61
	CLASS BLOCK ;
	ORIGIN 0 0 ;
	FOREIGN cluster_61 0 0 ;
	SIZE 2.63 BY 2.63 ;
	SYMMETRY X Y ;
	PIN OP0
		DIRECTION OUTPUT ;
		USE SIGNAL ;
		PORT
			LAYER metal1 ;
			RECT 1.315 1.315 1.315 1.315 ;
			END
		END OP0
	PIN OP1
		DIRECTION OUTPUT ;
		USE SIGNAL ;
		PORT
			LAYER metal1 ;
			RECT 1.315 1.315 1.315 1.315 ;
			END
		END OP1
	PIN OP2
		DIRECTION OUTPUT ;
		USE SIGNAL ;
		PORT
			LAYER metal1 ;
			RECT 1.315 1.315 1.315 1.315 ;
			END
		END OP2
	PIN IP0
		DIRECTION INPUT ;
		USE SIGNAL ;
		PORT
			LAYER metal1 ;
			RECT 1.315 1.315 1.315 1.315 ;
			END
		END IP0
END cluster_61
END LIBRARY
